VERSION 5.8 ;
BUSBITCHARS "[]" ;
DIVIDERCHAR "/" ;
UNITS
    DATABASE MICRONS 1000 ;
END UNITS

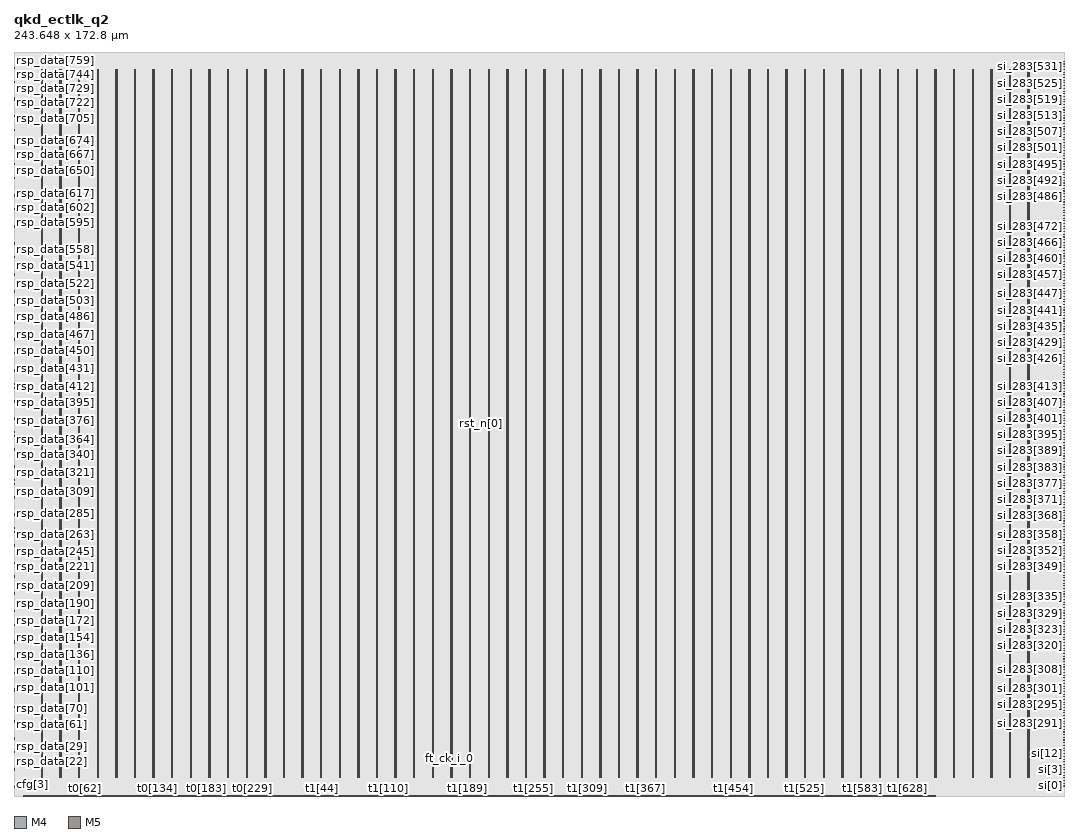
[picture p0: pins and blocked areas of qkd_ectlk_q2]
MACRO qkd_ectlk_q2
  FOREIGN qkd_ectlk_q2 0 0 ;
  CLASS BLOCK ;
  SIZE 243.648 BY 172.8 ;
  PIN cfg[0]
    DIRECTION INPUT ;
    USE SIGNAL ;
    PORT
      LAYER M4 ;
        RECT  0 2.076 0.192 2.1 ;
    END
  END cfg[0]
  PIN cfg[1]
    DIRECTION INPUT ;
    USE SIGNAL ;
    PORT
      LAYER M4 ;
        RECT  0 2.316 0.192 2.34 ;
    END
  END cfg[1]
  PIN cfg[2]
    DIRECTION INPUT ;
    USE SIGNAL ;
    PORT
      LAYER M4 ;
        RECT  0 2.556 0.192 2.58 ;
    END
  END cfg[2]
  PIN cfg[3]
    DIRECTION INPUT ;
    USE SIGNAL ;
    PORT
      LAYER M4 ;
        RECT  0 2.748 0.192 2.772 ;
    END
  END cfg[3]
  PIN cfg[4]
    DIRECTION INPUT ;
    USE SIGNAL ;
    PORT
      LAYER M4 ;
        RECT  0 2.988 0.192 3.012 ;
    END
  END cfg[4]
  PIN ck[0]
    DIRECTION INPUT ;
    USE SIGNAL ;
    PORT
      LAYER M5 ;
        RECT  108 86.16 108.048 86.64 ;
    END
  END ck[0]
  PIN ft_ck_i_0
    DIRECTION INPUT ;
    USE SIGNAL ;
    PORT
      LAYER M5 ;
        RECT  101.04 8.535 101.088 9.015 ;
    END
  END ft_ck_i_0
  PIN ft_ck_o_0
    DIRECTION OUTPUT ;
    USE SIGNAL ;
    PORT
      LAYER M5 ;
        RECT  104.88 8.535 104.928 9.015 ;
    END
  END ft_ck_o_0
  PIN rsp_data[0]
    DIRECTION INPUT ;
    USE SIGNAL ;
    PORT
      LAYER M4 ;
        RECT  0 3.18 0.192 3.204 ;
    END
  END rsp_data[0]
  PIN rsp_data[100]
    DIRECTION INPUT ;
    USE SIGNAL ;
    PORT
      LAYER M4 ;
        RECT  0 25.02 0.192 25.044 ;
    END
  END rsp_data[100]
  PIN rsp_data[101]
    DIRECTION INPUT ;
    USE SIGNAL ;
    PORT
      LAYER M4 ;
        RECT  0 25.26 0.192 25.284 ;
    END
  END rsp_data[101]
  PIN rsp_data[102]
    DIRECTION INPUT ;
    USE SIGNAL ;
    PORT
      LAYER M4 ;
        RECT  0 25.452 0.192 25.476 ;
    END
  END rsp_data[102]
  PIN rsp_data[103]
    DIRECTION INPUT ;
    USE SIGNAL ;
    PORT
      LAYER M4 ;
        RECT  0 25.692 0.192 25.716 ;
    END
  END rsp_data[103]
  PIN rsp_data[104]
    DIRECTION INPUT ;
    USE SIGNAL ;
    PORT
      LAYER M4 ;
        RECT  0 25.884 0.192 25.908 ;
    END
  END rsp_data[104]
  PIN rsp_data[105]
    DIRECTION INPUT ;
    USE SIGNAL ;
    PORT
      LAYER M4 ;
        RECT  0 26.124 0.192 26.148 ;
    END
  END rsp_data[105]
  PIN rsp_data[106]
    DIRECTION INPUT ;
    USE SIGNAL ;
    PORT
      LAYER M4 ;
        RECT  0 26.316 0.192 26.34 ;
    END
  END rsp_data[106]
  PIN rsp_data[107]
    DIRECTION INPUT ;
    USE SIGNAL ;
    PORT
      LAYER M4 ;
        RECT  0 26.556 0.192 26.58 ;
    END
  END rsp_data[107]
  PIN rsp_data[108]
    DIRECTION INPUT ;
    USE SIGNAL ;
    PORT
      LAYER M4 ;
        RECT  0 26.796 0.192 26.82 ;
    END
  END rsp_data[108]
  PIN rsp_data[109]
    DIRECTION INPUT ;
    USE SIGNAL ;
    PORT
      LAYER M4 ;
        RECT  0 26.988 0.192 27.012 ;
    END
  END rsp_data[109]
  PIN rsp_data[10]
    DIRECTION INPUT ;
    USE SIGNAL ;
    PORT
      LAYER M4 ;
        RECT  0 5.388 0.192 5.412 ;
    END
  END rsp_data[10]
  PIN rsp_data[110]
    DIRECTION INPUT ;
    USE SIGNAL ;
    PORT
      LAYER M4 ;
        RECT  0 27.228 0.192 27.252 ;
    END
  END rsp_data[110]
  PIN rsp_data[111]
    DIRECTION INPUT ;
    USE SIGNAL ;
    PORT
      LAYER M4 ;
        RECT  0 27.42 0.192 27.444 ;
    END
  END rsp_data[111]
  PIN rsp_data[112]
    DIRECTION INPUT ;
    USE SIGNAL ;
    PORT
      LAYER M4 ;
        RECT  0 27.66 0.192 27.684 ;
    END
  END rsp_data[112]
  PIN rsp_data[113]
    DIRECTION INPUT ;
    USE SIGNAL ;
    PORT
      LAYER M4 ;
        RECT  0 27.852 0.192 27.876 ;
    END
  END rsp_data[113]
  PIN rsp_data[114]
    DIRECTION INPUT ;
    USE SIGNAL ;
    PORT
      LAYER M4 ;
        RECT  0 28.092 0.192 28.116 ;
    END
  END rsp_data[114]
  PIN rsp_data[115]
    DIRECTION INPUT ;
    USE SIGNAL ;
    PORT
      LAYER M4 ;
        RECT  0 28.284 0.192 28.308 ;
    END
  END rsp_data[115]
  PIN rsp_data[116]
    DIRECTION INPUT ;
    USE SIGNAL ;
    PORT
      LAYER M4 ;
        RECT  0 28.524 0.192 28.548 ;
    END
  END rsp_data[116]
  PIN rsp_data[117]
    DIRECTION INPUT ;
    USE SIGNAL ;
    PORT
      LAYER M4 ;
        RECT  0 28.716 0.192 28.74 ;
    END
  END rsp_data[117]
  PIN rsp_data[118]
    DIRECTION INPUT ;
    USE SIGNAL ;
    PORT
      LAYER M4 ;
        RECT  0 28.956 0.192 28.98 ;
    END
  END rsp_data[118]
  PIN rsp_data[119]
    DIRECTION INPUT ;
    USE SIGNAL ;
    PORT
      LAYER M4 ;
        RECT  0 29.196 0.192 29.22 ;
    END
  END rsp_data[119]
  PIN rsp_data[11]
    DIRECTION INPUT ;
    USE SIGNAL ;
    PORT
      LAYER M4 ;
        RECT  0 5.58 0.192 5.604 ;
    END
  END rsp_data[11]
  PIN rsp_data[120]
    DIRECTION INPUT ;
    USE SIGNAL ;
    PORT
      LAYER M4 ;
        RECT  0 29.388 0.192 29.412 ;
    END
  END rsp_data[120]
  PIN rsp_data[121]
    DIRECTION INPUT ;
    USE SIGNAL ;
    PORT
      LAYER M4 ;
        RECT  0 29.628 0.192 29.652 ;
    END
  END rsp_data[121]
  PIN rsp_data[122]
    DIRECTION INPUT ;
    USE SIGNAL ;
    PORT
      LAYER M4 ;
        RECT  0 29.82 0.192 29.844 ;
    END
  END rsp_data[122]
  PIN rsp_data[123]
    DIRECTION INPUT ;
    USE SIGNAL ;
    PORT
      LAYER M4 ;
        RECT  0 30.06 0.192 30.084 ;
    END
  END rsp_data[123]
  PIN rsp_data[124]
    DIRECTION INPUT ;
    USE SIGNAL ;
    PORT
      LAYER M4 ;
        RECT  0 30.252 0.192 30.276 ;
    END
  END rsp_data[124]
  PIN rsp_data[125]
    DIRECTION INPUT ;
    USE SIGNAL ;
    PORT
      LAYER M4 ;
        RECT  0 30.492 0.192 30.516 ;
    END
  END rsp_data[125]
  PIN rsp_data[126]
    DIRECTION INPUT ;
    USE SIGNAL ;
    PORT
      LAYER M4 ;
        RECT  0 30.684 0.192 30.708 ;
    END
  END rsp_data[126]
  PIN rsp_data[127]
    DIRECTION INPUT ;
    USE SIGNAL ;
    PORT
      LAYER M4 ;
        RECT  0 30.924 0.192 30.948 ;
    END
  END rsp_data[127]
  PIN rsp_data[128]
    DIRECTION INPUT ;
    USE SIGNAL ;
    PORT
      LAYER M4 ;
        RECT  0 31.164 0.192 31.188 ;
    END
  END rsp_data[128]
  PIN rsp_data[129]
    DIRECTION INPUT ;
    USE SIGNAL ;
    PORT
      LAYER M4 ;
        RECT  0 31.356 0.192 31.38 ;
    END
  END rsp_data[129]
  PIN rsp_data[12]
    DIRECTION INPUT ;
    USE SIGNAL ;
    PORT
      LAYER M4 ;
        RECT  0 5.82 0.192 5.844 ;
    END
  END rsp_data[12]
  PIN rsp_data[130]
    DIRECTION INPUT ;
    USE SIGNAL ;
    PORT
      LAYER M4 ;
        RECT  0 31.596 0.192 31.62 ;
    END
  END rsp_data[130]
  PIN rsp_data[131]
    DIRECTION INPUT ;
    USE SIGNAL ;
    PORT
      LAYER M4 ;
        RECT  0 31.788 0.192 31.812 ;
    END
  END rsp_data[131]
  PIN rsp_data[132]
    DIRECTION INPUT ;
    USE SIGNAL ;
    PORT
      LAYER M4 ;
        RECT  0 32.028 0.192 32.052 ;
    END
  END rsp_data[132]
  PIN rsp_data[133]
    DIRECTION INPUT ;
    USE SIGNAL ;
    PORT
      LAYER M4 ;
        RECT  0 32.22 0.192 32.244 ;
    END
  END rsp_data[133]
  PIN rsp_data[134]
    DIRECTION INPUT ;
    USE SIGNAL ;
    PORT
      LAYER M4 ;
        RECT  0 32.46 0.192 32.484 ;
    END
  END rsp_data[134]
  PIN rsp_data[135]
    DIRECTION INPUT ;
    USE SIGNAL ;
    PORT
      LAYER M4 ;
        RECT  0 32.652 0.192 32.676 ;
    END
  END rsp_data[135]
  PIN rsp_data[136]
    DIRECTION INPUT ;
    USE SIGNAL ;
    PORT
      LAYER M4 ;
        RECT  0 32.892 0.192 32.916 ;
    END
  END rsp_data[136]
  PIN rsp_data[137]
    DIRECTION INPUT ;
    USE SIGNAL ;
    PORT
      LAYER M4 ;
        RECT  0 33.084 0.192 33.108 ;
    END
  END rsp_data[137]
  PIN rsp_data[138]
    DIRECTION INPUT ;
    USE SIGNAL ;
    PORT
      LAYER M4 ;
        RECT  0 33.324 0.192 33.348 ;
    END
  END rsp_data[138]
  PIN rsp_data[139]
    DIRECTION INPUT ;
    USE SIGNAL ;
    PORT
      LAYER M4 ;
        RECT  0 33.564 0.192 33.588 ;
    END
  END rsp_data[139]
  PIN rsp_data[13]
    DIRECTION INPUT ;
    USE SIGNAL ;
    PORT
      LAYER M4 ;
        RECT  0 6.012 0.192 6.036 ;
    END
  END rsp_data[13]
  PIN rsp_data[140]
    DIRECTION INPUT ;
    USE SIGNAL ;
    PORT
      LAYER M4 ;
        RECT  0 33.756 0.192 33.78 ;
    END
  END rsp_data[140]
  PIN rsp_data[141]
    DIRECTION INPUT ;
    USE SIGNAL ;
    PORT
      LAYER M4 ;
        RECT  0 33.996 0.192 34.02 ;
    END
  END rsp_data[141]
  PIN rsp_data[142]
    DIRECTION INPUT ;
    USE SIGNAL ;
    PORT
      LAYER M4 ;
        RECT  0 34.188 0.192 34.212 ;
    END
  END rsp_data[142]
  PIN rsp_data[143]
    DIRECTION INPUT ;
    USE SIGNAL ;
    PORT
      LAYER M4 ;
        RECT  0 34.428 0.192 34.452 ;
    END
  END rsp_data[143]
  PIN rsp_data[144]
    DIRECTION INPUT ;
    USE SIGNAL ;
    PORT
      LAYER M4 ;
        RECT  0 34.62 0.192 34.644 ;
    END
  END rsp_data[144]
  PIN rsp_data[145]
    DIRECTION INPUT ;
    USE SIGNAL ;
    PORT
      LAYER M4 ;
        RECT  0 34.86 0.192 34.884 ;
    END
  END rsp_data[145]
  PIN rsp_data[146]
    DIRECTION INPUT ;
    USE SIGNAL ;
    PORT
      LAYER M4 ;
        RECT  0 35.052 0.192 35.076 ;
    END
  END rsp_data[146]
  PIN rsp_data[147]
    DIRECTION INPUT ;
    USE SIGNAL ;
    PORT
      LAYER M4 ;
        RECT  0 35.292 0.192 35.316 ;
    END
  END rsp_data[147]
  PIN rsp_data[148]
    DIRECTION INPUT ;
    USE SIGNAL ;
    PORT
      LAYER M4 ;
        RECT  0 35.484 0.192 35.508 ;
    END
  END rsp_data[148]
  PIN rsp_data[149]
    DIRECTION INPUT ;
    USE SIGNAL ;
    PORT
      LAYER M4 ;
        RECT  0 35.724 0.192 35.748 ;
    END
  END rsp_data[149]
  PIN rsp_data[14]
    DIRECTION INPUT ;
    USE SIGNAL ;
    PORT
      LAYER M4 ;
        RECT  0 6.252 0.192 6.276 ;
    END
  END rsp_data[14]
  PIN rsp_data[150]
    DIRECTION INPUT ;
    USE SIGNAL ;
    PORT
      LAYER M4 ;
        RECT  0 35.964 0.192 35.988 ;
    END
  END rsp_data[150]
  PIN rsp_data[151]
    DIRECTION INPUT ;
    USE SIGNAL ;
    PORT
      LAYER M4 ;
        RECT  0 36.156 0.192 36.18 ;
    END
  END rsp_data[151]
  PIN rsp_data[152]
    DIRECTION INPUT ;
    USE SIGNAL ;
    PORT
      LAYER M4 ;
        RECT  0 36.396 0.192 36.42 ;
    END
  END rsp_data[152]
  PIN rsp_data[153]
    DIRECTION INPUT ;
    USE SIGNAL ;
    PORT
      LAYER M4 ;
        RECT  0 36.588 0.192 36.612 ;
    END
  END rsp_data[153]
  PIN rsp_data[154]
    DIRECTION INPUT ;
    USE SIGNAL ;
    PORT
      LAYER M4 ;
        RECT  0 36.828 0.192 36.852 ;
    END
  END rsp_data[154]
  PIN rsp_data[155]
    DIRECTION INPUT ;
    USE SIGNAL ;
    PORT
      LAYER M4 ;
        RECT  0 37.02 0.192 37.044 ;
    END
  END rsp_data[155]
  PIN rsp_data[156]
    DIRECTION INPUT ;
    USE SIGNAL ;
    PORT
      LAYER M4 ;
        RECT  0 37.26 0.192 37.284 ;
    END
  END rsp_data[156]
  PIN rsp_data[157]
    DIRECTION INPUT ;
    USE SIGNAL ;
    PORT
      LAYER M4 ;
        RECT  0 37.452 0.192 37.476 ;
    END
  END rsp_data[157]
  PIN rsp_data[158]
    DIRECTION INPUT ;
    USE SIGNAL ;
    PORT
      LAYER M4 ;
        RECT  0 37.692 0.192 37.716 ;
    END
  END rsp_data[158]
  PIN rsp_data[159]
    DIRECTION INPUT ;
    USE SIGNAL ;
    PORT
      LAYER M4 ;
        RECT  0 37.932 0.192 37.956 ;
    END
  END rsp_data[159]
  PIN rsp_data[15]
    DIRECTION INPUT ;
    USE SIGNAL ;
    PORT
      LAYER M4 ;
        RECT  0 6.444 0.192 6.468 ;
    END
  END rsp_data[15]
  PIN rsp_data[160]
    DIRECTION INPUT ;
    USE SIGNAL ;
    PORT
      LAYER M4 ;
        RECT  0 38.124 0.192 38.148 ;
    END
  END rsp_data[160]
  PIN rsp_data[161]
    DIRECTION INPUT ;
    USE SIGNAL ;
    PORT
      LAYER M4 ;
        RECT  0 38.364 0.192 38.388 ;
    END
  END rsp_data[161]
  PIN rsp_data[162]
    DIRECTION INPUT ;
    USE SIGNAL ;
    PORT
      LAYER M4 ;
        RECT  0 38.556 0.192 38.58 ;
    END
  END rsp_data[162]
  PIN rsp_data[163]
    DIRECTION INPUT ;
    USE SIGNAL ;
    PORT
      LAYER M4 ;
        RECT  0 38.796 0.192 38.82 ;
    END
  END rsp_data[163]
  PIN rsp_data[164]
    DIRECTION INPUT ;
    USE SIGNAL ;
    PORT
      LAYER M4 ;
        RECT  0 38.988 0.192 39.012 ;
    END
  END rsp_data[164]
  PIN rsp_data[165]
    DIRECTION INPUT ;
    USE SIGNAL ;
    PORT
      LAYER M4 ;
        RECT  0 39.228 0.192 39.252 ;
    END
  END rsp_data[165]
  PIN rsp_data[166]
    DIRECTION INPUT ;
    USE SIGNAL ;
    PORT
      LAYER M4 ;
        RECT  0 39.42 0.192 39.444 ;
    END
  END rsp_data[166]
  PIN rsp_data[167]
    DIRECTION INPUT ;
    USE SIGNAL ;
    PORT
      LAYER M4 ;
        RECT  0 39.66 0.192 39.684 ;
    END
  END rsp_data[167]
  PIN rsp_data[168]
    DIRECTION INPUT ;
    USE SIGNAL ;
    PORT
      LAYER M4 ;
        RECT  0 39.852 0.192 39.876 ;
    END
  END rsp_data[168]
  PIN rsp_data[169]
    DIRECTION INPUT ;
    USE SIGNAL ;
    PORT
      LAYER M4 ;
        RECT  0 40.092 0.192 40.116 ;
    END
  END rsp_data[169]
  PIN rsp_data[16]
    DIRECTION INPUT ;
    USE SIGNAL ;
    PORT
      LAYER M4 ;
        RECT  0 6.684 0.192 6.708 ;
    END
  END rsp_data[16]
  PIN rsp_data[170]
    DIRECTION INPUT ;
    USE SIGNAL ;
    PORT
      LAYER M4 ;
        RECT  0 40.332 0.192 40.356 ;
    END
  END rsp_data[170]
  PIN rsp_data[171]
    DIRECTION INPUT ;
    USE SIGNAL ;
    PORT
      LAYER M4 ;
        RECT  0 40.524 0.192 40.548 ;
    END
  END rsp_data[171]
  PIN rsp_data[172]
    DIRECTION INPUT ;
    USE SIGNAL ;
    PORT
      LAYER M4 ;
        RECT  0 40.764 0.192 40.788 ;
    END
  END rsp_data[172]
  PIN rsp_data[173]
    DIRECTION INPUT ;
    USE SIGNAL ;
    PORT
      LAYER M4 ;
        RECT  0 40.956 0.192 40.98 ;
    END
  END rsp_data[173]
  PIN rsp_data[174]
    DIRECTION INPUT ;
    USE SIGNAL ;
    PORT
      LAYER M4 ;
        RECT  0 41.196 0.192 41.22 ;
    END
  END rsp_data[174]
  PIN rsp_data[175]
    DIRECTION INPUT ;
    USE SIGNAL ;
    PORT
      LAYER M4 ;
        RECT  0 41.388 0.192 41.412 ;
    END
  END rsp_data[175]
  PIN rsp_data[176]
    DIRECTION INPUT ;
    USE SIGNAL ;
    PORT
      LAYER M4 ;
        RECT  0 41.628 0.192 41.652 ;
    END
  END rsp_data[176]
  PIN rsp_data[177]
    DIRECTION INPUT ;
    USE SIGNAL ;
    PORT
      LAYER M4 ;
        RECT  0 41.82 0.192 41.844 ;
    END
  END rsp_data[177]
  PIN rsp_data[178]
    DIRECTION INPUT ;
    USE SIGNAL ;
    PORT
      LAYER M4 ;
        RECT  0 42.06 0.192 42.084 ;
    END
  END rsp_data[178]
  PIN rsp_data[179]
    DIRECTION INPUT ;
    USE SIGNAL ;
    PORT
      LAYER M4 ;
        RECT  0 42.3 0.192 42.324 ;
    END
  END rsp_data[179]
  PIN rsp_data[17]
    DIRECTION INPUT ;
    USE SIGNAL ;
    PORT
      LAYER M4 ;
        RECT  0 6.924 0.192 6.948 ;
    END
  END rsp_data[17]
  PIN rsp_data[180]
    DIRECTION INPUT ;
    USE SIGNAL ;
    PORT
      LAYER M4 ;
        RECT  0 42.492 0.192 42.516 ;
    END
  END rsp_data[180]
  PIN rsp_data[181]
    DIRECTION INPUT ;
    USE SIGNAL ;
    PORT
      LAYER M4 ;
        RECT  0 42.732 0.192 42.756 ;
    END
  END rsp_data[181]
  PIN rsp_data[182]
    DIRECTION INPUT ;
    USE SIGNAL ;
    PORT
      LAYER M4 ;
        RECT  0 42.924 0.192 42.948 ;
    END
  END rsp_data[182]
  PIN rsp_data[183]
    DIRECTION INPUT ;
    USE SIGNAL ;
    PORT
      LAYER M4 ;
        RECT  0 43.164 0.192 43.188 ;
    END
  END rsp_data[183]
  PIN rsp_data[184]
    DIRECTION INPUT ;
    USE SIGNAL ;
    PORT
      LAYER M4 ;
        RECT  0 43.356 0.192 43.38 ;
    END
  END rsp_data[184]
  PIN rsp_data[185]
    DIRECTION INPUT ;
    USE SIGNAL ;
    PORT
      LAYER M4 ;
        RECT  0 43.596 0.192 43.62 ;
    END
  END rsp_data[185]
  PIN rsp_data[186]
    DIRECTION INPUT ;
    USE SIGNAL ;
    PORT
      LAYER M4 ;
        RECT  0 43.788 0.192 43.812 ;
    END
  END rsp_data[186]
  PIN rsp_data[187]
    DIRECTION INPUT ;
    USE SIGNAL ;
    PORT
      LAYER M4 ;
        RECT  0 44.028 0.192 44.052 ;
    END
  END rsp_data[187]
  PIN rsp_data[188]
    DIRECTION INPUT ;
    USE SIGNAL ;
    PORT
      LAYER M4 ;
        RECT  0 44.22 0.192 44.244 ;
    END
  END rsp_data[188]
  PIN rsp_data[189]
    DIRECTION INPUT ;
    USE SIGNAL ;
    PORT
      LAYER M4 ;
        RECT  0 44.46 0.192 44.484 ;
    END
  END rsp_data[189]
  PIN rsp_data[18]
    DIRECTION INPUT ;
    USE SIGNAL ;
    PORT
      LAYER M4 ;
        RECT  0 7.116 0.192 7.14 ;
    END
  END rsp_data[18]
  PIN rsp_data[190]
    DIRECTION INPUT ;
    USE SIGNAL ;
    PORT
      LAYER M4 ;
        RECT  0 44.7 0.192 44.724 ;
    END
  END rsp_data[190]
  PIN rsp_data[191]
    DIRECTION INPUT ;
    USE SIGNAL ;
    PORT
      LAYER M4 ;
        RECT  0 44.892 0.192 44.916 ;
    END
  END rsp_data[191]
  PIN rsp_data[192]
    DIRECTION INPUT ;
    USE SIGNAL ;
    PORT
      LAYER M4 ;
        RECT  0 45.132 0.192 45.156 ;
    END
  END rsp_data[192]
  PIN rsp_data[193]
    DIRECTION INPUT ;
    USE SIGNAL ;
    PORT
      LAYER M4 ;
        RECT  0 45.324 0.192 45.348 ;
    END
  END rsp_data[193]
  PIN rsp_data[194]
    DIRECTION INPUT ;
    USE SIGNAL ;
    PORT
      LAYER M4 ;
        RECT  0 45.564 0.192 45.588 ;
    END
  END rsp_data[194]
  PIN rsp_data[195]
    DIRECTION INPUT ;
    USE SIGNAL ;
    PORT
      LAYER M4 ;
        RECT  0 45.756 0.192 45.78 ;
    END
  END rsp_data[195]
  PIN rsp_data[196]
    DIRECTION INPUT ;
    USE SIGNAL ;
    PORT
      LAYER M4 ;
        RECT  0 45.996 0.192 46.02 ;
    END
  END rsp_data[196]
  PIN rsp_data[197]
    DIRECTION INPUT ;
    USE SIGNAL ;
    PORT
      LAYER M4 ;
        RECT  0 46.188 0.192 46.212 ;
    END
  END rsp_data[197]
  PIN rsp_data[198]
    DIRECTION INPUT ;
    USE SIGNAL ;
    PORT
      LAYER M4 ;
        RECT  0 46.428 0.192 46.452 ;
    END
  END rsp_data[198]
  PIN rsp_data[199]
    DIRECTION INPUT ;
    USE SIGNAL ;
    PORT
      LAYER M4 ;
        RECT  0 46.668 0.192 46.692 ;
    END
  END rsp_data[199]
  PIN rsp_data[19]
    DIRECTION INPUT ;
    USE SIGNAL ;
    PORT
      LAYER M4 ;
        RECT  0 7.356 0.192 7.38 ;
    END
  END rsp_data[19]
  PIN rsp_data[1]
    DIRECTION INPUT ;
    USE SIGNAL ;
    PORT
      LAYER M4 ;
        RECT  0 3.42 0.192 3.444 ;
    END
  END rsp_data[1]
  PIN rsp_data[200]
    DIRECTION INPUT ;
    USE SIGNAL ;
    PORT
      LAYER M4 ;
        RECT  0 46.86 0.192 46.884 ;
    END
  END rsp_data[200]
  PIN rsp_data[201]
    DIRECTION INPUT ;
    USE SIGNAL ;
    PORT
      LAYER M4 ;
        RECT  0 47.1 0.192 47.124 ;
    END
  END rsp_data[201]
  PIN rsp_data[202]
    DIRECTION INPUT ;
    USE SIGNAL ;
    PORT
      LAYER M4 ;
        RECT  0 47.292 0.192 47.316 ;
    END
  END rsp_data[202]
  PIN rsp_data[203]
    DIRECTION INPUT ;
    USE SIGNAL ;
    PORT
      LAYER M4 ;
        RECT  0 47.532 0.192 47.556 ;
    END
  END rsp_data[203]
  PIN rsp_data[204]
    DIRECTION INPUT ;
    USE SIGNAL ;
    PORT
      LAYER M4 ;
        RECT  0 47.724 0.192 47.748 ;
    END
  END rsp_data[204]
  PIN rsp_data[205]
    DIRECTION INPUT ;
    USE SIGNAL ;
    PORT
      LAYER M4 ;
        RECT  0 47.964 0.192 47.988 ;
    END
  END rsp_data[205]
  PIN rsp_data[206]
    DIRECTION INPUT ;
    USE SIGNAL ;
    PORT
      LAYER M4 ;
        RECT  0 48.156 0.192 48.18 ;
    END
  END rsp_data[206]
  PIN rsp_data[207]
    DIRECTION INPUT ;
    USE SIGNAL ;
    PORT
      LAYER M4 ;
        RECT  0 48.396 0.192 48.42 ;
    END
  END rsp_data[207]
  PIN rsp_data[208]
    DIRECTION INPUT ;
    USE SIGNAL ;
    PORT
      LAYER M4 ;
        RECT  0 48.588 0.192 48.612 ;
    END
  END rsp_data[208]
  PIN rsp_data[209]
    DIRECTION INPUT ;
    USE SIGNAL ;
    PORT
      LAYER M4 ;
        RECT  0 48.828 0.192 48.852 ;
    END
  END rsp_data[209]
  PIN rsp_data[20]
    DIRECTION INPUT ;
    USE SIGNAL ;
    PORT
      LAYER M4 ;
        RECT  0 7.548 0.192 7.572 ;
    END
  END rsp_data[20]
  PIN rsp_data[210]
    DIRECTION INPUT ;
    USE SIGNAL ;
    PORT
      LAYER M4 ;
        RECT  0 49.068 0.192 49.092 ;
    END
  END rsp_data[210]
  PIN rsp_data[211]
    DIRECTION INPUT ;
    USE SIGNAL ;
    PORT
      LAYER M4 ;
        RECT  0 49.26 0.192 49.284 ;
    END
  END rsp_data[211]
  PIN rsp_data[212]
    DIRECTION INPUT ;
    USE SIGNAL ;
    PORT
      LAYER M4 ;
        RECT  0 49.5 0.192 49.524 ;
    END
  END rsp_data[212]
  PIN rsp_data[213]
    DIRECTION INPUT ;
    USE SIGNAL ;
    PORT
      LAYER M4 ;
        RECT  0 49.692 0.192 49.716 ;
    END
  END rsp_data[213]
  PIN rsp_data[214]
    DIRECTION INPUT ;
    USE SIGNAL ;
    PORT
      LAYER M4 ;
        RECT  0 49.932 0.192 49.956 ;
    END
  END rsp_data[214]
  PIN rsp_data[215]
    DIRECTION INPUT ;
    USE SIGNAL ;
    PORT
      LAYER M4 ;
        RECT  0 50.124 0.192 50.148 ;
    END
  END rsp_data[215]
  PIN rsp_data[216]
    DIRECTION INPUT ;
    USE SIGNAL ;
    PORT
      LAYER M4 ;
        RECT  0 50.364 0.192 50.388 ;
    END
  END rsp_data[216]
  PIN rsp_data[217]
    DIRECTION INPUT ;
    USE SIGNAL ;
    PORT
      LAYER M4 ;
        RECT  0 50.556 0.192 50.58 ;
    END
  END rsp_data[217]
  PIN rsp_data[218]
    DIRECTION INPUT ;
    USE SIGNAL ;
    PORT
      LAYER M4 ;
        RECT  0 50.796 0.192 50.82 ;
    END
  END rsp_data[218]
  PIN rsp_data[219]
    DIRECTION INPUT ;
    USE SIGNAL ;
    PORT
      LAYER M4 ;
        RECT  0 51.036 0.192 51.06 ;
    END
  END rsp_data[219]
  PIN rsp_data[21]
    DIRECTION INPUT ;
    USE SIGNAL ;
    PORT
      LAYER M4 ;
        RECT  0 7.788 0.192 7.812 ;
    END
  END rsp_data[21]
  PIN rsp_data[220]
    DIRECTION INPUT ;
    USE SIGNAL ;
    PORT
      LAYER M4 ;
        RECT  0 51.228 0.192 51.252 ;
    END
  END rsp_data[220]
  PIN rsp_data[221]
    DIRECTION INPUT ;
    USE SIGNAL ;
    PORT
      LAYER M4 ;
        RECT  0 51.468 0.192 51.492 ;
    END
  END rsp_data[221]
  PIN rsp_data[222]
    DIRECTION INPUT ;
    USE SIGNAL ;
    PORT
      LAYER M4 ;
        RECT  0 51.66 0.192 51.684 ;
    END
  END rsp_data[222]
  PIN rsp_data[223]
    DIRECTION INPUT ;
    USE SIGNAL ;
    PORT
      LAYER M4 ;
        RECT  0 51.9 0.192 51.924 ;
    END
  END rsp_data[223]
  PIN rsp_data[224]
    DIRECTION INPUT ;
    USE SIGNAL ;
    PORT
      LAYER M4 ;
        RECT  0 52.092 0.192 52.116 ;
    END
  END rsp_data[224]
  PIN rsp_data[225]
    DIRECTION INPUT ;
    USE SIGNAL ;
    PORT
      LAYER M4 ;
        RECT  0 52.332 0.192 52.356 ;
    END
  END rsp_data[225]
  PIN rsp_data[226]
    DIRECTION INPUT ;
    USE SIGNAL ;
    PORT
      LAYER M4 ;
        RECT  0 52.524 0.192 52.548 ;
    END
  END rsp_data[226]
  PIN rsp_data[227]
    DIRECTION INPUT ;
    USE SIGNAL ;
    PORT
      LAYER M4 ;
        RECT  0 52.764 0.192 52.788 ;
    END
  END rsp_data[227]
  PIN rsp_data[228]
    DIRECTION INPUT ;
    USE SIGNAL ;
    PORT
      LAYER M4 ;
        RECT  0 52.956 0.192 52.98 ;
    END
  END rsp_data[228]
  PIN rsp_data[229]
    DIRECTION INPUT ;
    USE SIGNAL ;
    PORT
      LAYER M4 ;
        RECT  0 53.196 0.192 53.22 ;
    END
  END rsp_data[229]
  PIN rsp_data[22]
    DIRECTION INPUT ;
    USE SIGNAL ;
    PORT
      LAYER M4 ;
        RECT  0 7.98 0.192 8.004 ;
    END
  END rsp_data[22]
  PIN rsp_data[230]
    DIRECTION INPUT ;
    USE SIGNAL ;
    PORT
      LAYER M4 ;
        RECT  0 53.436 0.192 53.46 ;
    END
  END rsp_data[230]
  PIN rsp_data[231]
    DIRECTION INPUT ;
    USE SIGNAL ;
    PORT
      LAYER M4 ;
        RECT  0 53.628 0.192 53.652 ;
    END
  END rsp_data[231]
  PIN rsp_data[232]
    DIRECTION INPUT ;
    USE SIGNAL ;
    PORT
      LAYER M4 ;
        RECT  0 53.868 0.192 53.892 ;
    END
  END rsp_data[232]
  PIN rsp_data[233]
    DIRECTION INPUT ;
    USE SIGNAL ;
    PORT
      LAYER M4 ;
        RECT  0 54.06 0.192 54.084 ;
    END
  END rsp_data[233]
  PIN rsp_data[234]
    DIRECTION INPUT ;
    USE SIGNAL ;
    PORT
      LAYER M4 ;
        RECT  0 54.3 0.192 54.324 ;
    END
  END rsp_data[234]
  PIN rsp_data[235]
    DIRECTION INPUT ;
    USE SIGNAL ;
    PORT
      LAYER M4 ;
        RECT  0 54.492 0.192 54.516 ;
    END
  END rsp_data[235]
  PIN rsp_data[236]
    DIRECTION INPUT ;
    USE SIGNAL ;
    PORT
      LAYER M4 ;
        RECT  0 54.732 0.192 54.756 ;
    END
  END rsp_data[236]
  PIN rsp_data[237]
    DIRECTION INPUT ;
    USE SIGNAL ;
    PORT
      LAYER M4 ;
        RECT  0 54.924 0.192 54.948 ;
    END
  END rsp_data[237]
  PIN rsp_data[238]
    DIRECTION INPUT ;
    USE SIGNAL ;
    PORT
      LAYER M4 ;
        RECT  0 55.164 0.192 55.188 ;
    END
  END rsp_data[238]
  PIN rsp_data[239]
    DIRECTION INPUT ;
    USE SIGNAL ;
    PORT
      LAYER M4 ;
        RECT  0 55.356 0.192 55.38 ;
    END
  END rsp_data[239]
  PIN rsp_data[23]
    DIRECTION INPUT ;
    USE SIGNAL ;
    PORT
      LAYER M4 ;
        RECT  0 8.22 0.192 8.244 ;
    END
  END rsp_data[23]
  PIN rsp_data[240]
    DIRECTION INPUT ;
    USE SIGNAL ;
    PORT
      LAYER M4 ;
        RECT  0 55.596 0.192 55.62 ;
    END
  END rsp_data[240]
  PIN rsp_data[241]
    DIRECTION INPUT ;
    USE SIGNAL ;
    PORT
      LAYER M4 ;
        RECT  0 55.836 0.192 55.86 ;
    END
  END rsp_data[241]
  PIN rsp_data[242]
    DIRECTION INPUT ;
    USE SIGNAL ;
    PORT
      LAYER M4 ;
        RECT  0 56.028 0.192 56.052 ;
    END
  END rsp_data[242]
  PIN rsp_data[243]
    DIRECTION INPUT ;
    USE SIGNAL ;
    PORT
      LAYER M4 ;
        RECT  0 56.268 0.192 56.292 ;
    END
  END rsp_data[243]
  PIN rsp_data[244]
    DIRECTION INPUT ;
    USE SIGNAL ;
    PORT
      LAYER M4 ;
        RECT  0 56.46 0.192 56.484 ;
    END
  END rsp_data[244]
  PIN rsp_data[245]
    DIRECTION INPUT ;
    USE SIGNAL ;
    PORT
      LAYER M4 ;
        RECT  0 56.7 0.192 56.724 ;
    END
  END rsp_data[245]
  PIN rsp_data[246]
    DIRECTION INPUT ;
    USE SIGNAL ;
    PORT
      LAYER M4 ;
        RECT  0 56.892 0.192 56.916 ;
    END
  END rsp_data[246]
  PIN rsp_data[247]
    DIRECTION INPUT ;
    USE SIGNAL ;
    PORT
      LAYER M4 ;
        RECT  0 57.132 0.192 57.156 ;
    END
  END rsp_data[247]
  PIN rsp_data[248]
    DIRECTION INPUT ;
    USE SIGNAL ;
    PORT
      LAYER M4 ;
        RECT  0 57.324 0.192 57.348 ;
    END
  END rsp_data[248]
  PIN rsp_data[249]
    DIRECTION INPUT ;
    USE SIGNAL ;
    PORT
      LAYER M4 ;
        RECT  0 57.564 0.192 57.588 ;
    END
  END rsp_data[249]
  PIN rsp_data[24]
    DIRECTION INPUT ;
    USE SIGNAL ;
    PORT
      LAYER M4 ;
        RECT  0 8.412 0.192 8.436 ;
    END
  END rsp_data[24]
  PIN rsp_data[250]
    DIRECTION INPUT ;
    USE SIGNAL ;
    PORT
      LAYER M4 ;
        RECT  0 57.804 0.192 57.828 ;
    END
  END rsp_data[250]
  PIN rsp_data[251]
    DIRECTION INPUT ;
    USE SIGNAL ;
    PORT
      LAYER M4 ;
        RECT  0 57.996 0.192 58.02 ;
    END
  END rsp_data[251]
  PIN rsp_data[252]
    DIRECTION INPUT ;
    USE SIGNAL ;
    PORT
      LAYER M4 ;
        RECT  0 58.236 0.192 58.26 ;
    END
  END rsp_data[252]
  PIN rsp_data[253]
    DIRECTION INPUT ;
    USE SIGNAL ;
    PORT
      LAYER M4 ;
        RECT  0 58.428 0.192 58.452 ;
    END
  END rsp_data[253]
  PIN rsp_data[254]
    DIRECTION INPUT ;
    USE SIGNAL ;
    PORT
      LAYER M4 ;
        RECT  0 58.668 0.192 58.692 ;
    END
  END rsp_data[254]
  PIN rsp_data[255]
    DIRECTION INPUT ;
    USE SIGNAL ;
    PORT
      LAYER M4 ;
        RECT  0 58.86 0.192 58.884 ;
    END
  END rsp_data[255]
  PIN rsp_data[256]
    DIRECTION INPUT ;
    USE SIGNAL ;
    PORT
      LAYER M4 ;
        RECT  0 59.1 0.192 59.124 ;
    END
  END rsp_data[256]
  PIN rsp_data[257]
    DIRECTION INPUT ;
    USE SIGNAL ;
    PORT
      LAYER M4 ;
        RECT  0 59.292 0.192 59.316 ;
    END
  END rsp_data[257]
  PIN rsp_data[258]
    DIRECTION INPUT ;
    USE SIGNAL ;
    PORT
      LAYER M4 ;
        RECT  0 59.532 0.192 59.556 ;
    END
  END rsp_data[258]
  PIN rsp_data[259]
    DIRECTION INPUT ;
    USE SIGNAL ;
    PORT
      LAYER M4 ;
        RECT  0 59.724 0.192 59.748 ;
    END
  END rsp_data[259]
  PIN rsp_data[25]
    DIRECTION INPUT ;
    USE SIGNAL ;
    PORT
      LAYER M4 ;
        RECT  0 8.652 0.192 8.676 ;
    END
  END rsp_data[25]
  PIN rsp_data[260]
    DIRECTION INPUT ;
    USE SIGNAL ;
    PORT
      LAYER M4 ;
        RECT  0 59.964 0.192 59.988 ;
    END
  END rsp_data[260]
  PIN rsp_data[261]
    DIRECTION INPUT ;
    USE SIGNAL ;
    PORT
      LAYER M4 ;
        RECT  0 60.204 0.192 60.228 ;
    END
  END rsp_data[261]
  PIN rsp_data[262]
    DIRECTION INPUT ;
    USE SIGNAL ;
    PORT
      LAYER M4 ;
        RECT  0 60.396 0.192 60.42 ;
    END
  END rsp_data[262]
  PIN rsp_data[263]
    DIRECTION INPUT ;
    USE SIGNAL ;
    PORT
      LAYER M4 ;
        RECT  0 60.636 0.192 60.66 ;
    END
  END rsp_data[263]
  PIN rsp_data[264]
    DIRECTION INPUT ;
    USE SIGNAL ;
    PORT
      LAYER M4 ;
        RECT  0 60.828 0.192 60.852 ;
    END
  END rsp_data[264]
  PIN rsp_data[265]
    DIRECTION INPUT ;
    USE SIGNAL ;
    PORT
      LAYER M4 ;
        RECT  0 61.068 0.192 61.092 ;
    END
  END rsp_data[265]
  PIN rsp_data[266]
    DIRECTION INPUT ;
    USE SIGNAL ;
    PORT
      LAYER M4 ;
        RECT  0 61.26 0.192 61.284 ;
    END
  END rsp_data[266]
  PIN rsp_data[267]
    DIRECTION INPUT ;
    USE SIGNAL ;
    PORT
      LAYER M4 ;
        RECT  0 61.5 0.192 61.524 ;
    END
  END rsp_data[267]
  PIN rsp_data[268]
    DIRECTION INPUT ;
    USE SIGNAL ;
    PORT
      LAYER M4 ;
        RECT  0 61.692 0.192 61.716 ;
    END
  END rsp_data[268]
  PIN rsp_data[269]
    DIRECTION INPUT ;
    USE SIGNAL ;
    PORT
      LAYER M4 ;
        RECT  0 61.932 0.192 61.956 ;
    END
  END rsp_data[269]
  PIN rsp_data[26]
    DIRECTION INPUT ;
    USE SIGNAL ;
    PORT
      LAYER M4 ;
        RECT  0 8.844 0.192 8.868 ;
    END
  END rsp_data[26]
  PIN rsp_data[270]
    DIRECTION INPUT ;
    USE SIGNAL ;
    PORT
      LAYER M4 ;
        RECT  0 62.172 0.192 62.196 ;
    END
  END rsp_data[270]
  PIN rsp_data[271]
    DIRECTION INPUT ;
    USE SIGNAL ;
    PORT
      LAYER M4 ;
        RECT  0 62.364 0.192 62.388 ;
    END
  END rsp_data[271]
  PIN rsp_data[272]
    DIRECTION INPUT ;
    USE SIGNAL ;
    PORT
      LAYER M4 ;
        RECT  0 62.604 0.192 62.628 ;
    END
  END rsp_data[272]
  PIN rsp_data[273]
    DIRECTION INPUT ;
    USE SIGNAL ;
    PORT
      LAYER M4 ;
        RECT  0 62.796 0.192 62.82 ;
    END
  END rsp_data[273]
  PIN rsp_data[274]
    DIRECTION INPUT ;
    USE SIGNAL ;
    PORT
      LAYER M4 ;
        RECT  0 63.036 0.192 63.06 ;
    END
  END rsp_data[274]
  PIN rsp_data[275]
    DIRECTION INPUT ;
    USE SIGNAL ;
    PORT
      LAYER M4 ;
        RECT  0 63.228 0.192 63.252 ;
    END
  END rsp_data[275]
  PIN rsp_data[276]
    DIRECTION INPUT ;
    USE SIGNAL ;
    PORT
      LAYER M4 ;
        RECT  0 63.468 0.192 63.492 ;
    END
  END rsp_data[276]
  PIN rsp_data[277]
    DIRECTION INPUT ;
    USE SIGNAL ;
    PORT
      LAYER M4 ;
        RECT  0 63.66 0.192 63.684 ;
    END
  END rsp_data[277]
  PIN rsp_data[278]
    DIRECTION INPUT ;
    USE SIGNAL ;
    PORT
      LAYER M4 ;
        RECT  0 63.9 0.192 63.924 ;
    END
  END rsp_data[278]
  PIN rsp_data[279]
    DIRECTION INPUT ;
    USE SIGNAL ;
    PORT
      LAYER M4 ;
        RECT  0 64.092 0.192 64.116 ;
    END
  END rsp_data[279]
  PIN rsp_data[27]
    DIRECTION INPUT ;
    USE SIGNAL ;
    PORT
      LAYER M4 ;
        RECT  0 9.084 0.192 9.108 ;
    END
  END rsp_data[27]
  PIN rsp_data[280]
    DIRECTION INPUT ;
    USE SIGNAL ;
    PORT
      LAYER M4 ;
        RECT  0 64.332 0.192 64.356 ;
    END
  END rsp_data[280]
  PIN rsp_data[281]
    DIRECTION INPUT ;
    USE SIGNAL ;
    PORT
      LAYER M4 ;
        RECT  0 64.572 0.192 64.596 ;
    END
  END rsp_data[281]
  PIN rsp_data[282]
    DIRECTION INPUT ;
    USE SIGNAL ;
    PORT
      LAYER M4 ;
        RECT  0 64.764 0.192 64.788 ;
    END
  END rsp_data[282]
  PIN rsp_data[283]
    DIRECTION INPUT ;
    USE SIGNAL ;
    PORT
      LAYER M4 ;
        RECT  0 65.004 0.192 65.028 ;
    END
  END rsp_data[283]
  PIN rsp_data[284]
    DIRECTION INPUT ;
    USE SIGNAL ;
    PORT
      LAYER M4 ;
        RECT  0 65.196 0.192 65.22 ;
    END
  END rsp_data[284]
  PIN rsp_data[285]
    DIRECTION INPUT ;
    USE SIGNAL ;
    PORT
      LAYER M4 ;
        RECT  0 65.436 0.192 65.46 ;
    END
  END rsp_data[285]
  PIN rsp_data[286]
    DIRECTION INPUT ;
    USE SIGNAL ;
    PORT
      LAYER M4 ;
        RECT  0 65.628 0.192 65.652 ;
    END
  END rsp_data[286]
  PIN rsp_data[287]
    DIRECTION INPUT ;
    USE SIGNAL ;
    PORT
      LAYER M4 ;
        RECT  0 65.868 0.192 65.892 ;
    END
  END rsp_data[287]
  PIN rsp_data[288]
    DIRECTION INPUT ;
    USE SIGNAL ;
    PORT
      LAYER M4 ;
        RECT  0 66.06 0.192 66.084 ;
    END
  END rsp_data[288]
  PIN rsp_data[289]
    DIRECTION INPUT ;
    USE SIGNAL ;
    PORT
      LAYER M4 ;
        RECT  0 66.3 0.192 66.324 ;
    END
  END rsp_data[289]
  PIN rsp_data[28]
    DIRECTION INPUT ;
    USE SIGNAL ;
    PORT
      LAYER M4 ;
        RECT  0 9.324 0.192 9.348 ;
    END
  END rsp_data[28]
  PIN rsp_data[290]
    DIRECTION INPUT ;
    USE SIGNAL ;
    PORT
      LAYER M4 ;
        RECT  0 66.54 0.192 66.564 ;
    END
  END rsp_data[290]
  PIN rsp_data[291]
    DIRECTION INPUT ;
    USE SIGNAL ;
    PORT
      LAYER M4 ;
        RECT  0 66.732 0.192 66.756 ;
    END
  END rsp_data[291]
  PIN rsp_data[292]
    DIRECTION INPUT ;
    USE SIGNAL ;
    PORT
      LAYER M4 ;
        RECT  0 66.972 0.192 66.996 ;
    END
  END rsp_data[292]
  PIN rsp_data[293]
    DIRECTION INPUT ;
    USE SIGNAL ;
    PORT
      LAYER M4 ;
        RECT  0 67.164 0.192 67.188 ;
    END
  END rsp_data[293]
  PIN rsp_data[294]
    DIRECTION INPUT ;
    USE SIGNAL ;
    PORT
      LAYER M4 ;
        RECT  0 67.404 0.192 67.428 ;
    END
  END rsp_data[294]
  PIN rsp_data[295]
    DIRECTION INPUT ;
    USE SIGNAL ;
    PORT
      LAYER M4 ;
        RECT  0 67.596 0.192 67.62 ;
    END
  END rsp_data[295]
  PIN rsp_data[296]
    DIRECTION INPUT ;
    USE SIGNAL ;
    PORT
      LAYER M4 ;
        RECT  0 67.836 0.192 67.86 ;
    END
  END rsp_data[296]
  PIN rsp_data[297]
    DIRECTION INPUT ;
    USE SIGNAL ;
    PORT
      LAYER M4 ;
        RECT  0 68.028 0.192 68.052 ;
    END
  END rsp_data[297]
  PIN rsp_data[298]
    DIRECTION INPUT ;
    USE SIGNAL ;
    PORT
      LAYER M4 ;
        RECT  0 68.268 0.192 68.292 ;
    END
  END rsp_data[298]
  PIN rsp_data[299]
    DIRECTION INPUT ;
    USE SIGNAL ;
    PORT
      LAYER M4 ;
        RECT  0 68.46 0.192 68.484 ;
    END
  END rsp_data[299]
  PIN rsp_data[29]
    DIRECTION INPUT ;
    USE SIGNAL ;
    PORT
      LAYER M4 ;
        RECT  0 9.516 0.192 9.54 ;
    END
  END rsp_data[29]
  PIN rsp_data[2]
    DIRECTION INPUT ;
    USE SIGNAL ;
    PORT
      LAYER M4 ;
        RECT  0 3.612 0.192 3.636 ;
    END
  END rsp_data[2]
  PIN rsp_data[300]
    DIRECTION INPUT ;
    USE SIGNAL ;
    PORT
      LAYER M4 ;
        RECT  0 68.7 0.192 68.724 ;
    END
  END rsp_data[300]
  PIN rsp_data[301]
    DIRECTION INPUT ;
    USE SIGNAL ;
    PORT
      LAYER M4 ;
        RECT  0 68.94 0.192 68.964 ;
    END
  END rsp_data[301]
  PIN rsp_data[302]
    DIRECTION INPUT ;
    USE SIGNAL ;
    PORT
      LAYER M4 ;
        RECT  0 69.132 0.192 69.156 ;
    END
  END rsp_data[302]
  PIN rsp_data[303]
    DIRECTION INPUT ;
    USE SIGNAL ;
    PORT
      LAYER M4 ;
        RECT  0 69.372 0.192 69.396 ;
    END
  END rsp_data[303]
  PIN rsp_data[304]
    DIRECTION INPUT ;
    USE SIGNAL ;
    PORT
      LAYER M4 ;
        RECT  0 69.564 0.192 69.588 ;
    END
  END rsp_data[304]
  PIN rsp_data[305]
    DIRECTION INPUT ;
    USE SIGNAL ;
    PORT
      LAYER M4 ;
        RECT  0 69.804 0.192 69.828 ;
    END
  END rsp_data[305]
  PIN rsp_data[306]
    DIRECTION INPUT ;
    USE SIGNAL ;
    PORT
      LAYER M4 ;
        RECT  0 69.996 0.192 70.02 ;
    END
  END rsp_data[306]
  PIN rsp_data[307]
    DIRECTION INPUT ;
    USE SIGNAL ;
    PORT
      LAYER M4 ;
        RECT  0 70.236 0.192 70.26 ;
    END
  END rsp_data[307]
  PIN rsp_data[308]
    DIRECTION INPUT ;
    USE SIGNAL ;
    PORT
      LAYER M4 ;
        RECT  0 70.428 0.192 70.452 ;
    END
  END rsp_data[308]
  PIN rsp_data[309]
    DIRECTION INPUT ;
    USE SIGNAL ;
    PORT
      LAYER M4 ;
        RECT  0 70.668 0.192 70.692 ;
    END
  END rsp_data[309]
  PIN rsp_data[30]
    DIRECTION INPUT ;
    USE SIGNAL ;
    PORT
      LAYER M4 ;
        RECT  0 9.756 0.192 9.78 ;
    END
  END rsp_data[30]
  PIN rsp_data[310]
    DIRECTION INPUT ;
    USE SIGNAL ;
    PORT
      LAYER M4 ;
        RECT  0 70.86 0.192 70.884 ;
    END
  END rsp_data[310]
  PIN rsp_data[311]
    DIRECTION INPUT ;
    USE SIGNAL ;
    PORT
      LAYER M4 ;
        RECT  0 71.1 0.192 71.124 ;
    END
  END rsp_data[311]
  PIN rsp_data[312]
    DIRECTION INPUT ;
    USE SIGNAL ;
    PORT
      LAYER M4 ;
        RECT  0 71.34 0.192 71.364 ;
    END
  END rsp_data[312]
  PIN rsp_data[313]
    DIRECTION INPUT ;
    USE SIGNAL ;
    PORT
      LAYER M4 ;
        RECT  0 71.532 0.192 71.556 ;
    END
  END rsp_data[313]
  PIN rsp_data[314]
    DIRECTION INPUT ;
    USE SIGNAL ;
    PORT
      LAYER M4 ;
        RECT  0 71.772 0.192 71.796 ;
    END
  END rsp_data[314]
  PIN rsp_data[315]
    DIRECTION INPUT ;
    USE SIGNAL ;
    PORT
      LAYER M4 ;
        RECT  0 71.964 0.192 71.988 ;
    END
  END rsp_data[315]
  PIN rsp_data[316]
    DIRECTION INPUT ;
    USE SIGNAL ;
    PORT
      LAYER M4 ;
        RECT  0 72.204 0.192 72.228 ;
    END
  END rsp_data[316]
  PIN rsp_data[317]
    DIRECTION INPUT ;
    USE SIGNAL ;
    PORT
      LAYER M4 ;
        RECT  0 72.396 0.192 72.42 ;
    END
  END rsp_data[317]
  PIN rsp_data[318]
    DIRECTION INPUT ;
    USE SIGNAL ;
    PORT
      LAYER M4 ;
        RECT  0 72.636 0.192 72.66 ;
    END
  END rsp_data[318]
  PIN rsp_data[319]
    DIRECTION INPUT ;
    USE SIGNAL ;
    PORT
      LAYER M4 ;
        RECT  0 72.828 0.192 72.852 ;
    END
  END rsp_data[319]
  PIN rsp_data[31]
    DIRECTION INPUT ;
    USE SIGNAL ;
    PORT
      LAYER M4 ;
        RECT  0 9.948 0.192 9.972 ;
    END
  END rsp_data[31]
  PIN rsp_data[320]
    DIRECTION INPUT ;
    USE SIGNAL ;
    PORT
      LAYER M4 ;
        RECT  0 73.068 0.192 73.092 ;
    END
  END rsp_data[320]
  PIN rsp_data[321]
    DIRECTION INPUT ;
    USE SIGNAL ;
    PORT
      LAYER M4 ;
        RECT  0 73.308 0.192 73.332 ;
    END
  END rsp_data[321]
  PIN rsp_data[322]
    DIRECTION INPUT ;
    USE SIGNAL ;
    PORT
      LAYER M4 ;
        RECT  0 73.5 0.192 73.524 ;
    END
  END rsp_data[322]
  PIN rsp_data[323]
    DIRECTION INPUT ;
    USE SIGNAL ;
    PORT
      LAYER M4 ;
        RECT  0 73.74 0.192 73.764 ;
    END
  END rsp_data[323]
  PIN rsp_data[324]
    DIRECTION INPUT ;
    USE SIGNAL ;
    PORT
      LAYER M4 ;
        RECT  0 73.932 0.192 73.956 ;
    END
  END rsp_data[324]
  PIN rsp_data[325]
    DIRECTION INPUT ;
    USE SIGNAL ;
    PORT
      LAYER M4 ;
        RECT  0 74.172 0.192 74.196 ;
    END
  END rsp_data[325]
  PIN rsp_data[326]
    DIRECTION INPUT ;
    USE SIGNAL ;
    PORT
      LAYER M4 ;
        RECT  0 74.364 0.192 74.388 ;
    END
  END rsp_data[326]
  PIN rsp_data[327]
    DIRECTION INPUT ;
    USE SIGNAL ;
    PORT
      LAYER M4 ;
        RECT  0 74.604 0.192 74.628 ;
    END
  END rsp_data[327]
  PIN rsp_data[328]
    DIRECTION INPUT ;
    USE SIGNAL ;
    PORT
      LAYER M4 ;
        RECT  0 74.796 0.192 74.82 ;
    END
  END rsp_data[328]
  PIN rsp_data[329]
    DIRECTION INPUT ;
    USE SIGNAL ;
    PORT
      LAYER M4 ;
        RECT  0 75.036 0.192 75.06 ;
    END
  END rsp_data[329]
  PIN rsp_data[32]
    DIRECTION INPUT ;
    USE SIGNAL ;
    PORT
      LAYER M4 ;
        RECT  0 10.188 0.192 10.212 ;
    END
  END rsp_data[32]
  PIN rsp_data[330]
    DIRECTION INPUT ;
    USE SIGNAL ;
    PORT
      LAYER M4 ;
        RECT  0 75.228 0.192 75.252 ;
    END
  END rsp_data[330]
  PIN rsp_data[331]
    DIRECTION INPUT ;
    USE SIGNAL ;
    PORT
      LAYER M4 ;
        RECT  0 75.468 0.192 75.492 ;
    END
  END rsp_data[331]
  PIN rsp_data[332]
    DIRECTION INPUT ;
    USE SIGNAL ;
    PORT
      LAYER M4 ;
        RECT  0 75.708 0.192 75.732 ;
    END
  END rsp_data[332]
  PIN rsp_data[333]
    DIRECTION INPUT ;
    USE SIGNAL ;
    PORT
      LAYER M4 ;
        RECT  0 75.9 0.192 75.924 ;
    END
  END rsp_data[333]
  PIN rsp_data[334]
    DIRECTION INPUT ;
    USE SIGNAL ;
    PORT
      LAYER M4 ;
        RECT  0 76.14 0.192 76.164 ;
    END
  END rsp_data[334]
  PIN rsp_data[335]
    DIRECTION INPUT ;
    USE SIGNAL ;
    PORT
      LAYER M4 ;
        RECT  0 76.332 0.192 76.356 ;
    END
  END rsp_data[335]
  PIN rsp_data[336]
    DIRECTION INPUT ;
    USE SIGNAL ;
    PORT
      LAYER M4 ;
        RECT  0 76.572 0.192 76.596 ;
    END
  END rsp_data[336]
  PIN rsp_data[337]
    DIRECTION INPUT ;
    USE SIGNAL ;
    PORT
      LAYER M4 ;
        RECT  0 76.764 0.192 76.788 ;
    END
  END rsp_data[337]
  PIN rsp_data[338]
    DIRECTION INPUT ;
    USE SIGNAL ;
    PORT
      LAYER M4 ;
        RECT  0 77.004 0.192 77.028 ;
    END
  END rsp_data[338]
  PIN rsp_data[339]
    DIRECTION INPUT ;
    USE SIGNAL ;
    PORT
      LAYER M4 ;
        RECT  0 77.196 0.192 77.22 ;
    END
  END rsp_data[339]
  PIN rsp_data[33]
    DIRECTION INPUT ;
    USE SIGNAL ;
    PORT
      LAYER M4 ;
        RECT  0 10.38 0.192 10.404 ;
    END
  END rsp_data[33]
  PIN rsp_data[340]
    DIRECTION INPUT ;
    USE SIGNAL ;
    PORT
      LAYER M4 ;
        RECT  0 77.436 0.192 77.46 ;
    END
  END rsp_data[340]
  PIN rsp_data[341]
    DIRECTION INPUT ;
    USE SIGNAL ;
    PORT
      LAYER M4 ;
        RECT  0 77.676 0.192 77.7 ;
    END
  END rsp_data[341]
  PIN rsp_data[342]
    DIRECTION INPUT ;
    USE SIGNAL ;
    PORT
      LAYER M4 ;
        RECT  0 77.868 0.192 77.892 ;
    END
  END rsp_data[342]
  PIN rsp_data[343]
    DIRECTION INPUT ;
    USE SIGNAL ;
    PORT
      LAYER M4 ;
        RECT  0 78.108 0.192 78.132 ;
    END
  END rsp_data[343]
  PIN rsp_data[344]
    DIRECTION INPUT ;
    USE SIGNAL ;
    PORT
      LAYER M4 ;
        RECT  0 78.3 0.192 78.324 ;
    END
  END rsp_data[344]
  PIN rsp_data[345]
    DIRECTION INPUT ;
    USE SIGNAL ;
    PORT
      LAYER M4 ;
        RECT  0 78.54 0.192 78.564 ;
    END
  END rsp_data[345]
  PIN rsp_data[346]
    DIRECTION INPUT ;
    USE SIGNAL ;
    PORT
      LAYER M4 ;
        RECT  0 78.732 0.192 78.756 ;
    END
  END rsp_data[346]
  PIN rsp_data[347]
    DIRECTION INPUT ;
    USE SIGNAL ;
    PORT
      LAYER M4 ;
        RECT  0 78.972 0.192 78.996 ;
    END
  END rsp_data[347]
  PIN rsp_data[348]
    DIRECTION INPUT ;
    USE SIGNAL ;
    PORT
      LAYER M4 ;
        RECT  0 79.164 0.192 79.188 ;
    END
  END rsp_data[348]
  PIN rsp_data[349]
    DIRECTION INPUT ;
    USE SIGNAL ;
    PORT
      LAYER M4 ;
        RECT  0 79.404 0.192 79.428 ;
    END
  END rsp_data[349]
  PIN rsp_data[34]
    DIRECTION INPUT ;
    USE SIGNAL ;
    PORT
      LAYER M4 ;
        RECT  0 10.62 0.192 10.644 ;
    END
  END rsp_data[34]
  PIN rsp_data[350]
    DIRECTION INPUT ;
    USE SIGNAL ;
    PORT
      LAYER M4 ;
        RECT  0 79.596 0.192 79.62 ;
    END
  END rsp_data[350]
  PIN rsp_data[351]
    DIRECTION INPUT ;
    USE SIGNAL ;
    PORT
      LAYER M4 ;
        RECT  0 79.836 0.192 79.86 ;
    END
  END rsp_data[351]
  PIN rsp_data[352]
    DIRECTION INPUT ;
    USE SIGNAL ;
    PORT
      LAYER M4 ;
        RECT  0 80.076 0.192 80.1 ;
    END
  END rsp_data[352]
  PIN rsp_data[353]
    DIRECTION INPUT ;
    USE SIGNAL ;
    PORT
      LAYER M4 ;
        RECT  0 80.268 0.192 80.292 ;
    END
  END rsp_data[353]
  PIN rsp_data[354]
    DIRECTION INPUT ;
    USE SIGNAL ;
    PORT
      LAYER M4 ;
        RECT  0 80.508 0.192 80.532 ;
    END
  END rsp_data[354]
  PIN rsp_data[355]
    DIRECTION INPUT ;
    USE SIGNAL ;
    PORT
      LAYER M4 ;
        RECT  0 80.7 0.192 80.724 ;
    END
  END rsp_data[355]
  PIN rsp_data[356]
    DIRECTION INPUT ;
    USE SIGNAL ;
    PORT
      LAYER M4 ;
        RECT  0 80.94 0.192 80.964 ;
    END
  END rsp_data[356]
  PIN rsp_data[357]
    DIRECTION INPUT ;
    USE SIGNAL ;
    PORT
      LAYER M4 ;
        RECT  0 81.132 0.192 81.156 ;
    END
  END rsp_data[357]
  PIN rsp_data[358]
    DIRECTION INPUT ;
    USE SIGNAL ;
    PORT
      LAYER M4 ;
        RECT  0 81.372 0.192 81.396 ;
    END
  END rsp_data[358]
  PIN rsp_data[359]
    DIRECTION INPUT ;
    USE SIGNAL ;
    PORT
      LAYER M4 ;
        RECT  0 81.564 0.192 81.588 ;
    END
  END rsp_data[359]
  PIN rsp_data[35]
    DIRECTION INPUT ;
    USE SIGNAL ;
    PORT
      LAYER M4 ;
        RECT  0 10.812 0.192 10.836 ;
    END
  END rsp_data[35]
  PIN rsp_data[360]
    DIRECTION INPUT ;
    USE SIGNAL ;
    PORT
      LAYER M4 ;
        RECT  0 81.804 0.192 81.828 ;
    END
  END rsp_data[360]
  PIN rsp_data[361]
    DIRECTION INPUT ;
    USE SIGNAL ;
    PORT
      LAYER M4 ;
        RECT  0 82.044 0.192 82.068 ;
    END
  END rsp_data[361]
  PIN rsp_data[362]
    DIRECTION INPUT ;
    USE SIGNAL ;
    PORT
      LAYER M4 ;
        RECT  0 82.236 0.192 82.26 ;
    END
  END rsp_data[362]
  PIN rsp_data[363]
    DIRECTION INPUT ;
    USE SIGNAL ;
    PORT
      LAYER M4 ;
        RECT  0 82.476 0.192 82.5 ;
    END
  END rsp_data[363]
  PIN rsp_data[364]
    DIRECTION INPUT ;
    USE SIGNAL ;
    PORT
      LAYER M4 ;
        RECT  0 82.668 0.192 82.692 ;
    END
  END rsp_data[364]
  PIN rsp_data[365]
    DIRECTION INPUT ;
    USE SIGNAL ;
    PORT
      LAYER M4 ;
        RECT  0 82.908 0.192 82.932 ;
    END
  END rsp_data[365]
  PIN rsp_data[366]
    DIRECTION INPUT ;
    USE SIGNAL ;
    PORT
      LAYER M4 ;
        RECT  0 83.1 0.192 83.124 ;
    END
  END rsp_data[366]
  PIN rsp_data[367]
    DIRECTION INPUT ;
    USE SIGNAL ;
    PORT
      LAYER M4 ;
        RECT  0 83.34 0.192 83.364 ;
    END
  END rsp_data[367]
  PIN rsp_data[368]
    DIRECTION INPUT ;
    USE SIGNAL ;
    PORT
      LAYER M4 ;
        RECT  0 83.532 0.192 83.556 ;
    END
  END rsp_data[368]
  PIN rsp_data[369]
    DIRECTION INPUT ;
    USE SIGNAL ;
    PORT
      LAYER M4 ;
        RECT  0 83.772 0.192 83.796 ;
    END
  END rsp_data[369]
  PIN rsp_data[36]
    DIRECTION INPUT ;
    USE SIGNAL ;
    PORT
      LAYER M4 ;
        RECT  0 11.052 0.192 11.076 ;
    END
  END rsp_data[36]
  PIN rsp_data[370]
    DIRECTION INPUT ;
    USE SIGNAL ;
    PORT
      LAYER M4 ;
        RECT  0 83.964 0.192 83.988 ;
    END
  END rsp_data[370]
  PIN rsp_data[371]
    DIRECTION INPUT ;
    USE SIGNAL ;
    PORT
      LAYER M4 ;
        RECT  0 84.204 0.192 84.228 ;
    END
  END rsp_data[371]
  PIN rsp_data[372]
    DIRECTION INPUT ;
    USE SIGNAL ;
    PORT
      LAYER M4 ;
        RECT  0 84.444 0.192 84.468 ;
    END
  END rsp_data[372]
  PIN rsp_data[373]
    DIRECTION INPUT ;
    USE SIGNAL ;
    PORT
      LAYER M4 ;
        RECT  0 84.636 0.192 84.66 ;
    END
  END rsp_data[373]
  PIN rsp_data[374]
    DIRECTION INPUT ;
    USE SIGNAL ;
    PORT
      LAYER M4 ;
        RECT  0 84.876 0.192 84.9 ;
    END
  END rsp_data[374]
  PIN rsp_data[375]
    DIRECTION INPUT ;
    USE SIGNAL ;
    PORT
      LAYER M4 ;
        RECT  0 85.068 0.192 85.092 ;
    END
  END rsp_data[375]
  PIN rsp_data[376]
    DIRECTION INPUT ;
    USE SIGNAL ;
    PORT
      LAYER M4 ;
        RECT  0 85.308 0.192 85.332 ;
    END
  END rsp_data[376]
  PIN rsp_data[377]
    DIRECTION INPUT ;
    USE SIGNAL ;
    PORT
      LAYER M4 ;
        RECT  0 85.5 0.192 85.524 ;
    END
  END rsp_data[377]
  PIN rsp_data[378]
    DIRECTION INPUT ;
    USE SIGNAL ;
    PORT
      LAYER M4 ;
        RECT  0 85.74 0.192 85.764 ;
    END
  END rsp_data[378]
  PIN rsp_data[379]
    DIRECTION INPUT ;
    USE SIGNAL ;
    PORT
      LAYER M4 ;
        RECT  0 85.932 0.192 85.956 ;
    END
  END rsp_data[379]
  PIN rsp_data[37]
    DIRECTION INPUT ;
    USE SIGNAL ;
    PORT
      LAYER M4 ;
        RECT  0 11.292 0.192 11.316 ;
    END
  END rsp_data[37]
  PIN rsp_data[380]
    DIRECTION INPUT ;
    USE SIGNAL ;
    PORT
      LAYER M4 ;
        RECT  0 86.172 0.192 86.196 ;
    END
  END rsp_data[380]
  PIN rsp_data[381]
    DIRECTION INPUT ;
    USE SIGNAL ;
    PORT
      LAYER M4 ;
        RECT  0 86.412 0.192 86.436 ;
    END
  END rsp_data[381]
  PIN rsp_data[382]
    DIRECTION INPUT ;
    USE SIGNAL ;
    PORT
      LAYER M4 ;
        RECT  0 86.604 0.192 86.628 ;
    END
  END rsp_data[382]
  PIN rsp_data[383]
    DIRECTION INPUT ;
    USE SIGNAL ;
    PORT
      LAYER M4 ;
        RECT  0 86.844 0.192 86.868 ;
    END
  END rsp_data[383]
  PIN rsp_data[384]
    DIRECTION INPUT ;
    USE SIGNAL ;
    PORT
      LAYER M4 ;
        RECT  0 87.036 0.192 87.06 ;
    END
  END rsp_data[384]
  PIN rsp_data[385]
    DIRECTION INPUT ;
    USE SIGNAL ;
    PORT
      LAYER M4 ;
        RECT  0 87.276 0.192 87.3 ;
    END
  END rsp_data[385]
  PIN rsp_data[386]
    DIRECTION INPUT ;
    USE SIGNAL ;
    PORT
      LAYER M4 ;
        RECT  0 87.468 0.192 87.492 ;
    END
  END rsp_data[386]
  PIN rsp_data[387]
    DIRECTION INPUT ;
    USE SIGNAL ;
    PORT
      LAYER M4 ;
        RECT  0 87.708 0.192 87.732 ;
    END
  END rsp_data[387]
  PIN rsp_data[388]
    DIRECTION INPUT ;
    USE SIGNAL ;
    PORT
      LAYER M4 ;
        RECT  0 87.9 0.192 87.924 ;
    END
  END rsp_data[388]
  PIN rsp_data[389]
    DIRECTION INPUT ;
    USE SIGNAL ;
    PORT
      LAYER M4 ;
        RECT  0 88.14 0.192 88.164 ;
    END
  END rsp_data[389]
  PIN rsp_data[38]
    DIRECTION INPUT ;
    USE SIGNAL ;
    PORT
      LAYER M4 ;
        RECT  0 11.484 0.192 11.508 ;
    END
  END rsp_data[38]
  PIN rsp_data[390]
    DIRECTION INPUT ;
    USE SIGNAL ;
    PORT
      LAYER M4 ;
        RECT  0 88.332 0.192 88.356 ;
    END
  END rsp_data[390]
  PIN rsp_data[391]
    DIRECTION INPUT ;
    USE SIGNAL ;
    PORT
      LAYER M4 ;
        RECT  0 88.572 0.192 88.596 ;
    END
  END rsp_data[391]
  PIN rsp_data[392]
    DIRECTION INPUT ;
    USE SIGNAL ;
    PORT
      LAYER M4 ;
        RECT  0 88.812 0.192 88.836 ;
    END
  END rsp_data[392]
  PIN rsp_data[393]
    DIRECTION INPUT ;
    USE SIGNAL ;
    PORT
      LAYER M4 ;
        RECT  0 89.004 0.192 89.028 ;
    END
  END rsp_data[393]
  PIN rsp_data[394]
    DIRECTION INPUT ;
    USE SIGNAL ;
    PORT
      LAYER M4 ;
        RECT  0 89.244 0.192 89.268 ;
    END
  END rsp_data[394]
  PIN rsp_data[395]
    DIRECTION INPUT ;
    USE SIGNAL ;
    PORT
      LAYER M4 ;
        RECT  0 89.436 0.192 89.46 ;
    END
  END rsp_data[395]
  PIN rsp_data[396]
    DIRECTION INPUT ;
    USE SIGNAL ;
    PORT
      LAYER M4 ;
        RECT  0 89.676 0.192 89.7 ;
    END
  END rsp_data[396]
  PIN rsp_data[397]
    DIRECTION INPUT ;
    USE SIGNAL ;
    PORT
      LAYER M4 ;
        RECT  0 89.868 0.192 89.892 ;
    END
  END rsp_data[397]
  PIN rsp_data[398]
    DIRECTION INPUT ;
    USE SIGNAL ;
    PORT
      LAYER M4 ;
        RECT  0 90.108 0.192 90.132 ;
    END
  END rsp_data[398]
  PIN rsp_data[399]
    DIRECTION INPUT ;
    USE SIGNAL ;
    PORT
      LAYER M4 ;
        RECT  0 90.3 0.192 90.324 ;
    END
  END rsp_data[399]
  PIN rsp_data[39]
    DIRECTION INPUT ;
    USE SIGNAL ;
    PORT
      LAYER M4 ;
        RECT  0 11.724 0.192 11.748 ;
    END
  END rsp_data[39]
  PIN rsp_data[3]
    DIRECTION INPUT ;
    USE SIGNAL ;
    PORT
      LAYER M4 ;
        RECT  0 3.852 0.192 3.876 ;
    END
  END rsp_data[3]
  PIN rsp_data[400]
    DIRECTION INPUT ;
    USE SIGNAL ;
    PORT
      LAYER M4 ;
        RECT  0 90.54 0.192 90.564 ;
    END
  END rsp_data[400]
  PIN rsp_data[401]
    DIRECTION INPUT ;
    USE SIGNAL ;
    PORT
      LAYER M4 ;
        RECT  0 90.732 0.192 90.756 ;
    END
  END rsp_data[401]
  PIN rsp_data[402]
    DIRECTION INPUT ;
    USE SIGNAL ;
    PORT
      LAYER M4 ;
        RECT  0 90.972 0.192 90.996 ;
    END
  END rsp_data[402]
  PIN rsp_data[403]
    DIRECTION INPUT ;
    USE SIGNAL ;
    PORT
      LAYER M4 ;
        RECT  0 91.212 0.192 91.236 ;
    END
  END rsp_data[403]
  PIN rsp_data[404]
    DIRECTION INPUT ;
    USE SIGNAL ;
    PORT
      LAYER M4 ;
        RECT  0 91.404 0.192 91.428 ;
    END
  END rsp_data[404]
  PIN rsp_data[405]
    DIRECTION INPUT ;
    USE SIGNAL ;
    PORT
      LAYER M4 ;
        RECT  0 91.644 0.192 91.668 ;
    END
  END rsp_data[405]
  PIN rsp_data[406]
    DIRECTION INPUT ;
    USE SIGNAL ;
    PORT
      LAYER M4 ;
        RECT  0 91.836 0.192 91.86 ;
    END
  END rsp_data[406]
  PIN rsp_data[407]
    DIRECTION INPUT ;
    USE SIGNAL ;
    PORT
      LAYER M4 ;
        RECT  0 92.076 0.192 92.1 ;
    END
  END rsp_data[407]
  PIN rsp_data[408]
    DIRECTION INPUT ;
    USE SIGNAL ;
    PORT
      LAYER M4 ;
        RECT  0 92.268 0.192 92.292 ;
    END
  END rsp_data[408]
  PIN rsp_data[409]
    DIRECTION INPUT ;
    USE SIGNAL ;
    PORT
      LAYER M4 ;
        RECT  0 92.508 0.192 92.532 ;
    END
  END rsp_data[409]
  PIN rsp_data[40]
    DIRECTION INPUT ;
    USE SIGNAL ;
    PORT
      LAYER M4 ;
        RECT  0 11.916 0.192 11.94 ;
    END
  END rsp_data[40]
  PIN rsp_data[410]
    DIRECTION INPUT ;
    USE SIGNAL ;
    PORT
      LAYER M4 ;
        RECT  0 92.7 0.192 92.724 ;
    END
  END rsp_data[410]
  PIN rsp_data[411]
    DIRECTION INPUT ;
    USE SIGNAL ;
    PORT
      LAYER M4 ;
        RECT  0 92.94 0.192 92.964 ;
    END
  END rsp_data[411]
  PIN rsp_data[412]
    DIRECTION INPUT ;
    USE SIGNAL ;
    PORT
      LAYER M4 ;
        RECT  0 93.18 0.192 93.204 ;
    END
  END rsp_data[412]
  PIN rsp_data[413]
    DIRECTION INPUT ;
    USE SIGNAL ;
    PORT
      LAYER M4 ;
        RECT  0 93.372 0.192 93.396 ;
    END
  END rsp_data[413]
  PIN rsp_data[414]
    DIRECTION INPUT ;
    USE SIGNAL ;
    PORT
      LAYER M4 ;
        RECT  0 93.612 0.192 93.636 ;
    END
  END rsp_data[414]
  PIN rsp_data[415]
    DIRECTION INPUT ;
    USE SIGNAL ;
    PORT
      LAYER M4 ;
        RECT  0 93.804 0.192 93.828 ;
    END
  END rsp_data[415]
  PIN rsp_data[416]
    DIRECTION INPUT ;
    USE SIGNAL ;
    PORT
      LAYER M4 ;
        RECT  0 94.044 0.192 94.068 ;
    END
  END rsp_data[416]
  PIN rsp_data[417]
    DIRECTION INPUT ;
    USE SIGNAL ;
    PORT
      LAYER M4 ;
        RECT  0 94.236 0.192 94.26 ;
    END
  END rsp_data[417]
  PIN rsp_data[418]
    DIRECTION INPUT ;
    USE SIGNAL ;
    PORT
      LAYER M4 ;
        RECT  0 94.476 0.192 94.5 ;
    END
  END rsp_data[418]
  PIN rsp_data[419]
    DIRECTION INPUT ;
    USE SIGNAL ;
    PORT
      LAYER M4 ;
        RECT  0 94.668 0.192 94.692 ;
    END
  END rsp_data[419]
  PIN rsp_data[41]
    DIRECTION INPUT ;
    USE SIGNAL ;
    PORT
      LAYER M4 ;
        RECT  0 12.156 0.192 12.18 ;
    END
  END rsp_data[41]
  PIN rsp_data[420]
    DIRECTION INPUT ;
    USE SIGNAL ;
    PORT
      LAYER M4 ;
        RECT  0 94.908 0.192 94.932 ;
    END
  END rsp_data[420]
  PIN rsp_data[421]
    DIRECTION INPUT ;
    USE SIGNAL ;
    PORT
      LAYER M4 ;
        RECT  0 95.1 0.192 95.124 ;
    END
  END rsp_data[421]
  PIN rsp_data[422]
    DIRECTION INPUT ;
    USE SIGNAL ;
    PORT
      LAYER M4 ;
        RECT  0 95.34 0.192 95.364 ;
    END
  END rsp_data[422]
  PIN rsp_data[423]
    DIRECTION INPUT ;
    USE SIGNAL ;
    PORT
      LAYER M4 ;
        RECT  0 95.58 0.192 95.604 ;
    END
  END rsp_data[423]
  PIN rsp_data[424]
    DIRECTION INPUT ;
    USE SIGNAL ;
    PORT
      LAYER M4 ;
        RECT  0 95.772 0.192 95.796 ;
    END
  END rsp_data[424]
  PIN rsp_data[425]
    DIRECTION INPUT ;
    USE SIGNAL ;
    PORT
      LAYER M4 ;
        RECT  0 96.012 0.192 96.036 ;
    END
  END rsp_data[425]
  PIN rsp_data[426]
    DIRECTION INPUT ;
    USE SIGNAL ;
    PORT
      LAYER M4 ;
        RECT  0 96.204 0.192 96.228 ;
    END
  END rsp_data[426]
  PIN rsp_data[427]
    DIRECTION INPUT ;
    USE SIGNAL ;
    PORT
      LAYER M4 ;
        RECT  0 96.444 0.192 96.468 ;
    END
  END rsp_data[427]
  PIN rsp_data[428]
    DIRECTION INPUT ;
    USE SIGNAL ;
    PORT
      LAYER M4 ;
        RECT  0 96.636 0.192 96.66 ;
    END
  END rsp_data[428]
  PIN rsp_data[429]
    DIRECTION INPUT ;
    USE SIGNAL ;
    PORT
      LAYER M4 ;
        RECT  0 96.876 0.192 96.9 ;
    END
  END rsp_data[429]
  PIN rsp_data[42]
    DIRECTION INPUT ;
    USE SIGNAL ;
    PORT
      LAYER M4 ;
        RECT  0 12.348 0.192 12.372 ;
    END
  END rsp_data[42]
  PIN rsp_data[430]
    DIRECTION INPUT ;
    USE SIGNAL ;
    PORT
      LAYER M4 ;
        RECT  0 97.068 0.192 97.092 ;
    END
  END rsp_data[430]
  PIN rsp_data[431]
    DIRECTION INPUT ;
    USE SIGNAL ;
    PORT
      LAYER M4 ;
        RECT  0 97.308 0.192 97.332 ;
    END
  END rsp_data[431]
  PIN rsp_data[432]
    DIRECTION INPUT ;
    USE SIGNAL ;
    PORT
      LAYER M4 ;
        RECT  0 97.548 0.192 97.572 ;
    END
  END rsp_data[432]
  PIN rsp_data[433]
    DIRECTION INPUT ;
    USE SIGNAL ;
    PORT
      LAYER M4 ;
        RECT  0 97.74 0.192 97.764 ;
    END
  END rsp_data[433]
  PIN rsp_data[434]
    DIRECTION INPUT ;
    USE SIGNAL ;
    PORT
      LAYER M4 ;
        RECT  0 97.98 0.192 98.004 ;
    END
  END rsp_data[434]
  PIN rsp_data[435]
    DIRECTION INPUT ;
    USE SIGNAL ;
    PORT
      LAYER M4 ;
        RECT  0 98.172 0.192 98.196 ;
    END
  END rsp_data[435]
  PIN rsp_data[436]
    DIRECTION INPUT ;
    USE SIGNAL ;
    PORT
      LAYER M4 ;
        RECT  0 98.412 0.192 98.436 ;
    END
  END rsp_data[436]
  PIN rsp_data[437]
    DIRECTION INPUT ;
    USE SIGNAL ;
    PORT
      LAYER M4 ;
        RECT  0 98.604 0.192 98.628 ;
    END
  END rsp_data[437]
  PIN rsp_data[438]
    DIRECTION INPUT ;
    USE SIGNAL ;
    PORT
      LAYER M4 ;
        RECT  0 98.844 0.192 98.868 ;
    END
  END rsp_data[438]
  PIN rsp_data[439]
    DIRECTION INPUT ;
    USE SIGNAL ;
    PORT
      LAYER M4 ;
        RECT  0 99.036 0.192 99.06 ;
    END
  END rsp_data[439]
  PIN rsp_data[43]
    DIRECTION INPUT ;
    USE SIGNAL ;
    PORT
      LAYER M4 ;
        RECT  0 12.588 0.192 12.612 ;
    END
  END rsp_data[43]
  PIN rsp_data[440]
    DIRECTION INPUT ;
    USE SIGNAL ;
    PORT
      LAYER M4 ;
        RECT  0 99.276 0.192 99.3 ;
    END
  END rsp_data[440]
  PIN rsp_data[441]
    DIRECTION INPUT ;
    USE SIGNAL ;
    PORT
      LAYER M4 ;
        RECT  0 99.468 0.192 99.492 ;
    END
  END rsp_data[441]
  PIN rsp_data[442]
    DIRECTION INPUT ;
    USE SIGNAL ;
    PORT
      LAYER M4 ;
        RECT  0 99.708 0.192 99.732 ;
    END
  END rsp_data[442]
  PIN rsp_data[443]
    DIRECTION INPUT ;
    USE SIGNAL ;
    PORT
      LAYER M4 ;
        RECT  0 99.948 0.192 99.972 ;
    END
  END rsp_data[443]
  PIN rsp_data[444]
    DIRECTION INPUT ;
    USE SIGNAL ;
    PORT
      LAYER M4 ;
        RECT  0 100.14 0.192 100.164 ;
    END
  END rsp_data[444]
  PIN rsp_data[445]
    DIRECTION INPUT ;
    USE SIGNAL ;
    PORT
      LAYER M4 ;
        RECT  0 100.38 0.192 100.404 ;
    END
  END rsp_data[445]
  PIN rsp_data[446]
    DIRECTION INPUT ;
    USE SIGNAL ;
    PORT
      LAYER M4 ;
        RECT  0 100.572 0.192 100.596 ;
    END
  END rsp_data[446]
  PIN rsp_data[447]
    DIRECTION INPUT ;
    USE SIGNAL ;
    PORT
      LAYER M4 ;
        RECT  0 100.812 0.192 100.836 ;
    END
  END rsp_data[447]
  PIN rsp_data[448]
    DIRECTION INPUT ;
    USE SIGNAL ;
    PORT
      LAYER M4 ;
        RECT  0 101.004 0.192 101.028 ;
    END
  END rsp_data[448]
  PIN rsp_data[449]
    DIRECTION INPUT ;
    USE SIGNAL ;
    PORT
      LAYER M4 ;
        RECT  0 101.244 0.192 101.268 ;
    END
  END rsp_data[449]
  PIN rsp_data[44]
    DIRECTION INPUT ;
    USE SIGNAL ;
    PORT
      LAYER M4 ;
        RECT  0 12.78 0.192 12.804 ;
    END
  END rsp_data[44]
  PIN rsp_data[450]
    DIRECTION INPUT ;
    USE SIGNAL ;
    PORT
      LAYER M4 ;
        RECT  0 101.436 0.192 101.46 ;
    END
  END rsp_data[450]
  PIN rsp_data[451]
    DIRECTION INPUT ;
    USE SIGNAL ;
    PORT
      LAYER M4 ;
        RECT  0 101.676 0.192 101.7 ;
    END
  END rsp_data[451]
  PIN rsp_data[452]
    DIRECTION INPUT ;
    USE SIGNAL ;
    PORT
      LAYER M4 ;
        RECT  0 101.916 0.192 101.94 ;
    END
  END rsp_data[452]
  PIN rsp_data[453]
    DIRECTION INPUT ;
    USE SIGNAL ;
    PORT
      LAYER M4 ;
        RECT  0 102.108 0.192 102.132 ;
    END
  END rsp_data[453]
  PIN rsp_data[454]
    DIRECTION INPUT ;
    USE SIGNAL ;
    PORT
      LAYER M4 ;
        RECT  0 102.348 0.192 102.372 ;
    END
  END rsp_data[454]
  PIN rsp_data[455]
    DIRECTION INPUT ;
    USE SIGNAL ;
    PORT
      LAYER M4 ;
        RECT  0 102.54 0.192 102.564 ;
    END
  END rsp_data[455]
  PIN rsp_data[456]
    DIRECTION INPUT ;
    USE SIGNAL ;
    PORT
      LAYER M4 ;
        RECT  0 102.78 0.192 102.804 ;
    END
  END rsp_data[456]
  PIN rsp_data[457]
    DIRECTION INPUT ;
    USE SIGNAL ;
    PORT
      LAYER M4 ;
        RECT  0 102.972 0.192 102.996 ;
    END
  END rsp_data[457]
  PIN rsp_data[458]
    DIRECTION INPUT ;
    USE SIGNAL ;
    PORT
      LAYER M4 ;
        RECT  0 103.212 0.192 103.236 ;
    END
  END rsp_data[458]
  PIN rsp_data[459]
    DIRECTION INPUT ;
    USE SIGNAL ;
    PORT
      LAYER M4 ;
        RECT  0 103.404 0.192 103.428 ;
    END
  END rsp_data[459]
  PIN rsp_data[45]
    DIRECTION INPUT ;
    USE SIGNAL ;
    PORT
      LAYER M4 ;
        RECT  0 13.02 0.192 13.044 ;
    END
  END rsp_data[45]
  PIN rsp_data[460]
    DIRECTION INPUT ;
    USE SIGNAL ;
    PORT
      LAYER M4 ;
        RECT  0 103.644 0.192 103.668 ;
    END
  END rsp_data[460]
  PIN rsp_data[461]
    DIRECTION INPUT ;
    USE SIGNAL ;
    PORT
      LAYER M4 ;
        RECT  0 103.836 0.192 103.86 ;
    END
  END rsp_data[461]
  PIN rsp_data[462]
    DIRECTION INPUT ;
    USE SIGNAL ;
    PORT
      LAYER M4 ;
        RECT  0 104.076 0.192 104.1 ;
    END
  END rsp_data[462]
  PIN rsp_data[463]
    DIRECTION INPUT ;
    USE SIGNAL ;
    PORT
      LAYER M4 ;
        RECT  0 104.316 0.192 104.34 ;
    END
  END rsp_data[463]
  PIN rsp_data[464]
    DIRECTION INPUT ;
    USE SIGNAL ;
    PORT
      LAYER M4 ;
        RECT  0 104.508 0.192 104.532 ;
    END
  END rsp_data[464]
  PIN rsp_data[465]
    DIRECTION INPUT ;
    USE SIGNAL ;
    PORT
      LAYER M4 ;
        RECT  0 104.748 0.192 104.772 ;
    END
  END rsp_data[465]
  PIN rsp_data[466]
    DIRECTION INPUT ;
    USE SIGNAL ;
    PORT
      LAYER M4 ;
        RECT  0 104.94 0.192 104.964 ;
    END
  END rsp_data[466]
  PIN rsp_data[467]
    DIRECTION INPUT ;
    USE SIGNAL ;
    PORT
      LAYER M4 ;
        RECT  0 105.18 0.192 105.204 ;
    END
  END rsp_data[467]
  PIN rsp_data[468]
    DIRECTION INPUT ;
    USE SIGNAL ;
    PORT
      LAYER M4 ;
        RECT  0 105.372 0.192 105.396 ;
    END
  END rsp_data[468]
  PIN rsp_data[469]
    DIRECTION INPUT ;
    USE SIGNAL ;
    PORT
      LAYER M4 ;
        RECT  0 105.612 0.192 105.636 ;
    END
  END rsp_data[469]
  PIN rsp_data[46]
    DIRECTION INPUT ;
    USE SIGNAL ;
    PORT
      LAYER M4 ;
        RECT  0 13.212 0.192 13.236 ;
    END
  END rsp_data[46]
  PIN rsp_data[470]
    DIRECTION INPUT ;
    USE SIGNAL ;
    PORT
      LAYER M4 ;
        RECT  0 105.804 0.192 105.828 ;
    END
  END rsp_data[470]
  PIN rsp_data[471]
    DIRECTION INPUT ;
    USE SIGNAL ;
    PORT
      LAYER M4 ;
        RECT  0 106.044 0.192 106.068 ;
    END
  END rsp_data[471]
  PIN rsp_data[472]
    DIRECTION INPUT ;
    USE SIGNAL ;
    PORT
      LAYER M4 ;
        RECT  0 106.236 0.192 106.26 ;
    END
  END rsp_data[472]
  PIN rsp_data[473]
    DIRECTION INPUT ;
    USE SIGNAL ;
    PORT
      LAYER M4 ;
        RECT  0 106.476 0.192 106.5 ;
    END
  END rsp_data[473]
  PIN rsp_data[474]
    DIRECTION INPUT ;
    USE SIGNAL ;
    PORT
      LAYER M4 ;
        RECT  0 106.716 0.192 106.74 ;
    END
  END rsp_data[474]
  PIN rsp_data[475]
    DIRECTION INPUT ;
    USE SIGNAL ;
    PORT
      LAYER M4 ;
        RECT  0 106.908 0.192 106.932 ;
    END
  END rsp_data[475]
  PIN rsp_data[476]
    DIRECTION INPUT ;
    USE SIGNAL ;
    PORT
      LAYER M4 ;
        RECT  0 107.148 0.192 107.172 ;
    END
  END rsp_data[476]
  PIN rsp_data[477]
    DIRECTION INPUT ;
    USE SIGNAL ;
    PORT
      LAYER M4 ;
        RECT  0 107.34 0.192 107.364 ;
    END
  END rsp_data[477]
  PIN rsp_data[478]
    DIRECTION INPUT ;
    USE SIGNAL ;
    PORT
      LAYER M4 ;
        RECT  0 107.58 0.192 107.604 ;
    END
  END rsp_data[478]
  PIN rsp_data[479]
    DIRECTION INPUT ;
    USE SIGNAL ;
    PORT
      LAYER M4 ;
        RECT  0 107.772 0.192 107.796 ;
    END
  END rsp_data[479]
  PIN rsp_data[47]
    DIRECTION INPUT ;
    USE SIGNAL ;
    PORT
      LAYER M4 ;
        RECT  0 13.452 0.192 13.476 ;
    END
  END rsp_data[47]
  PIN rsp_data[480]
    DIRECTION INPUT ;
    USE SIGNAL ;
    PORT
      LAYER M4 ;
        RECT  0 108.012 0.192 108.036 ;
    END
  END rsp_data[480]
  PIN rsp_data[481]
    DIRECTION INPUT ;
    USE SIGNAL ;
    PORT
      LAYER M4 ;
        RECT  0 108.204 0.192 108.228 ;
    END
  END rsp_data[481]
  PIN rsp_data[482]
    DIRECTION INPUT ;
    USE SIGNAL ;
    PORT
      LAYER M4 ;
        RECT  0 108.444 0.192 108.468 ;
    END
  END rsp_data[482]
  PIN rsp_data[483]
    DIRECTION INPUT ;
    USE SIGNAL ;
    PORT
      LAYER M4 ;
        RECT  0 108.684 0.192 108.708 ;
    END
  END rsp_data[483]
  PIN rsp_data[484]
    DIRECTION INPUT ;
    USE SIGNAL ;
    PORT
      LAYER M4 ;
        RECT  0 108.876 0.192 108.9 ;
    END
  END rsp_data[484]
  PIN rsp_data[485]
    DIRECTION INPUT ;
    USE SIGNAL ;
    PORT
      LAYER M4 ;
        RECT  0 109.116 0.192 109.14 ;
    END
  END rsp_data[485]
  PIN rsp_data[486]
    DIRECTION INPUT ;
    USE SIGNAL ;
    PORT
      LAYER M4 ;
        RECT  0 109.308 0.192 109.332 ;
    END
  END rsp_data[486]
  PIN rsp_data[487]
    DIRECTION INPUT ;
    USE SIGNAL ;
    PORT
      LAYER M4 ;
        RECT  0 109.548 0.192 109.572 ;
    END
  END rsp_data[487]
  PIN rsp_data[488]
    DIRECTION INPUT ;
    USE SIGNAL ;
    PORT
      LAYER M4 ;
        RECT  0 109.74 0.192 109.764 ;
    END
  END rsp_data[488]
  PIN rsp_data[489]
    DIRECTION INPUT ;
    USE SIGNAL ;
    PORT
      LAYER M4 ;
        RECT  0 109.98 0.192 110.004 ;
    END
  END rsp_data[489]
  PIN rsp_data[48]
    DIRECTION INPUT ;
    USE SIGNAL ;
    PORT
      LAYER M4 ;
        RECT  0 13.692 0.192 13.716 ;
    END
  END rsp_data[48]
  PIN rsp_data[490]
    DIRECTION INPUT ;
    USE SIGNAL ;
    PORT
      LAYER M4 ;
        RECT  0 110.172 0.192 110.196 ;
    END
  END rsp_data[490]
  PIN rsp_data[491]
    DIRECTION INPUT ;
    USE SIGNAL ;
    PORT
      LAYER M4 ;
        RECT  0 110.412 0.192 110.436 ;
    END
  END rsp_data[491]
  PIN rsp_data[492]
    DIRECTION INPUT ;
    USE SIGNAL ;
    PORT
      LAYER M4 ;
        RECT  0 110.604 0.192 110.628 ;
    END
  END rsp_data[492]
  PIN rsp_data[493]
    DIRECTION INPUT ;
    USE SIGNAL ;
    PORT
      LAYER M4 ;
        RECT  0 110.844 0.192 110.868 ;
    END
  END rsp_data[493]
  PIN rsp_data[494]
    DIRECTION INPUT ;
    USE SIGNAL ;
    PORT
      LAYER M4 ;
        RECT  0 111.084 0.192 111.108 ;
    END
  END rsp_data[494]
  PIN rsp_data[495]
    DIRECTION INPUT ;
    USE SIGNAL ;
    PORT
      LAYER M4 ;
        RECT  0 111.276 0.192 111.3 ;
    END
  END rsp_data[495]
  PIN rsp_data[496]
    DIRECTION INPUT ;
    USE SIGNAL ;
    PORT
      LAYER M4 ;
        RECT  0 111.516 0.192 111.54 ;
    END
  END rsp_data[496]
  PIN rsp_data[497]
    DIRECTION INPUT ;
    USE SIGNAL ;
    PORT
      LAYER M4 ;
        RECT  0 111.708 0.192 111.732 ;
    END
  END rsp_data[497]
  PIN rsp_data[498]
    DIRECTION INPUT ;
    USE SIGNAL ;
    PORT
      LAYER M4 ;
        RECT  0 111.948 0.192 111.972 ;
    END
  END rsp_data[498]
  PIN rsp_data[499]
    DIRECTION INPUT ;
    USE SIGNAL ;
    PORT
      LAYER M4 ;
        RECT  0 112.14 0.192 112.164 ;
    END
  END rsp_data[499]
  PIN rsp_data[49]
    DIRECTION INPUT ;
    USE SIGNAL ;
    PORT
      LAYER M4 ;
        RECT  0 13.884 0.192 13.908 ;
    END
  END rsp_data[49]
  PIN rsp_data[4]
    DIRECTION INPUT ;
    USE SIGNAL ;
    PORT
      LAYER M4 ;
        RECT  0 4.044 0.192 4.068 ;
    END
  END rsp_data[4]
  PIN rsp_data[500]
    DIRECTION INPUT ;
    USE SIGNAL ;
    PORT
      LAYER M4 ;
        RECT  0 112.38 0.192 112.404 ;
    END
  END rsp_data[500]
  PIN rsp_data[501]
    DIRECTION INPUT ;
    USE SIGNAL ;
    PORT
      LAYER M4 ;
        RECT  0 112.572 0.192 112.596 ;
    END
  END rsp_data[501]
  PIN rsp_data[502]
    DIRECTION INPUT ;
    USE SIGNAL ;
    PORT
      LAYER M4 ;
        RECT  0 112.812 0.192 112.836 ;
    END
  END rsp_data[502]
  PIN rsp_data[503]
    DIRECTION INPUT ;
    USE SIGNAL ;
    PORT
      LAYER M4 ;
        RECT  0 113.052 0.192 113.076 ;
    END
  END rsp_data[503]
  PIN rsp_data[504]
    DIRECTION INPUT ;
    USE SIGNAL ;
    PORT
      LAYER M4 ;
        RECT  0 113.244 0.192 113.268 ;
    END
  END rsp_data[504]
  PIN rsp_data[505]
    DIRECTION INPUT ;
    USE SIGNAL ;
    PORT
      LAYER M4 ;
        RECT  0 113.484 0.192 113.508 ;
    END
  END rsp_data[505]
  PIN rsp_data[506]
    DIRECTION INPUT ;
    USE SIGNAL ;
    PORT
      LAYER M4 ;
        RECT  0 113.676 0.192 113.7 ;
    END
  END rsp_data[506]
  PIN rsp_data[507]
    DIRECTION INPUT ;
    USE SIGNAL ;
    PORT
      LAYER M4 ;
        RECT  0 113.916 0.192 113.94 ;
    END
  END rsp_data[507]
  PIN rsp_data[508]
    DIRECTION INPUT ;
    USE SIGNAL ;
    PORT
      LAYER M4 ;
        RECT  0 114.108 0.192 114.132 ;
    END
  END rsp_data[508]
  PIN rsp_data[509]
    DIRECTION INPUT ;
    USE SIGNAL ;
    PORT
      LAYER M4 ;
        RECT  0 114.348 0.192 114.372 ;
    END
  END rsp_data[509]
  PIN rsp_data[50]
    DIRECTION INPUT ;
    USE SIGNAL ;
    PORT
      LAYER M4 ;
        RECT  0 14.124 0.192 14.148 ;
    END
  END rsp_data[50]
  PIN rsp_data[510]
    DIRECTION INPUT ;
    USE SIGNAL ;
    PORT
      LAYER M4 ;
        RECT  0 114.54 0.192 114.564 ;
    END
  END rsp_data[510]
  PIN rsp_data[511]
    DIRECTION INPUT ;
    USE SIGNAL ;
    PORT
      LAYER M4 ;
        RECT  0 114.78 0.192 114.804 ;
    END
  END rsp_data[511]
  PIN rsp_data[512]
    DIRECTION INPUT ;
    USE SIGNAL ;
    PORT
      LAYER M4 ;
        RECT  0 114.972 0.192 114.996 ;
    END
  END rsp_data[512]
  PIN rsp_data[513]
    DIRECTION INPUT ;
    USE SIGNAL ;
    PORT
      LAYER M4 ;
        RECT  0 115.212 0.192 115.236 ;
    END
  END rsp_data[513]
  PIN rsp_data[514]
    DIRECTION INPUT ;
    USE SIGNAL ;
    PORT
      LAYER M4 ;
        RECT  0 115.452 0.192 115.476 ;
    END
  END rsp_data[514]
  PIN rsp_data[515]
    DIRECTION INPUT ;
    USE SIGNAL ;
    PORT
      LAYER M4 ;
        RECT  0 115.644 0.192 115.668 ;
    END
  END rsp_data[515]
  PIN rsp_data[516]
    DIRECTION INPUT ;
    USE SIGNAL ;
    PORT
      LAYER M4 ;
        RECT  0 115.884 0.192 115.908 ;
    END
  END rsp_data[516]
  PIN rsp_data[517]
    DIRECTION INPUT ;
    USE SIGNAL ;
    PORT
      LAYER M4 ;
        RECT  0 116.076 0.192 116.1 ;
    END
  END rsp_data[517]
  PIN rsp_data[518]
    DIRECTION INPUT ;
    USE SIGNAL ;
    PORT
      LAYER M4 ;
        RECT  0 116.316 0.192 116.34 ;
    END
  END rsp_data[518]
  PIN rsp_data[519]
    DIRECTION INPUT ;
    USE SIGNAL ;
    PORT
      LAYER M4 ;
        RECT  0 116.508 0.192 116.532 ;
    END
  END rsp_data[519]
  PIN rsp_data[51]
    DIRECTION INPUT ;
    USE SIGNAL ;
    PORT
      LAYER M4 ;
        RECT  0 14.316 0.192 14.34 ;
    END
  END rsp_data[51]
  PIN rsp_data[520]
    DIRECTION INPUT ;
    USE SIGNAL ;
    PORT
      LAYER M4 ;
        RECT  0 116.748 0.192 116.772 ;
    END
  END rsp_data[520]
  PIN rsp_data[521]
    DIRECTION INPUT ;
    USE SIGNAL ;
    PORT
      LAYER M4 ;
        RECT  0 116.94 0.192 116.964 ;
    END
  END rsp_data[521]
  PIN rsp_data[522]
    DIRECTION INPUT ;
    USE SIGNAL ;
    PORT
      LAYER M4 ;
        RECT  0 117.18 0.192 117.204 ;
    END
  END rsp_data[522]
  PIN rsp_data[523]
    DIRECTION INPUT ;
    USE SIGNAL ;
    PORT
      LAYER M4 ;
        RECT  0 117.42 0.192 117.444 ;
    END
  END rsp_data[523]
  PIN rsp_data[524]
    DIRECTION INPUT ;
    USE SIGNAL ;
    PORT
      LAYER M4 ;
        RECT  0 117.612 0.192 117.636 ;
    END
  END rsp_data[524]
  PIN rsp_data[525]
    DIRECTION INPUT ;
    USE SIGNAL ;
    PORT
      LAYER M4 ;
        RECT  0 117.852 0.192 117.876 ;
    END
  END rsp_data[525]
  PIN rsp_data[526]
    DIRECTION INPUT ;
    USE SIGNAL ;
    PORT
      LAYER M4 ;
        RECT  0 118.044 0.192 118.068 ;
    END
  END rsp_data[526]
  PIN rsp_data[527]
    DIRECTION INPUT ;
    USE SIGNAL ;
    PORT
      LAYER M4 ;
        RECT  0 118.284 0.192 118.308 ;
    END
  END rsp_data[527]
  PIN rsp_data[528]
    DIRECTION INPUT ;
    USE SIGNAL ;
    PORT
      LAYER M4 ;
        RECT  0 118.476 0.192 118.5 ;
    END
  END rsp_data[528]
  PIN rsp_data[529]
    DIRECTION INPUT ;
    USE SIGNAL ;
    PORT
      LAYER M4 ;
        RECT  0 118.716 0.192 118.74 ;
    END
  END rsp_data[529]
  PIN rsp_data[52]
    DIRECTION INPUT ;
    USE SIGNAL ;
    PORT
      LAYER M4 ;
        RECT  0 14.556 0.192 14.58 ;
    END
  END rsp_data[52]
  PIN rsp_data[530]
    DIRECTION INPUT ;
    USE SIGNAL ;
    PORT
      LAYER M4 ;
        RECT  0 118.908 0.192 118.932 ;
    END
  END rsp_data[530]
  PIN rsp_data[531]
    DIRECTION INPUT ;
    USE SIGNAL ;
    PORT
      LAYER M4 ;
        RECT  0 119.148 0.192 119.172 ;
    END
  END rsp_data[531]
  PIN rsp_data[532]
    DIRECTION INPUT ;
    USE SIGNAL ;
    PORT
      LAYER M4 ;
        RECT  0 119.34 0.192 119.364 ;
    END
  END rsp_data[532]
  PIN rsp_data[533]
    DIRECTION INPUT ;
    USE SIGNAL ;
    PORT
      LAYER M4 ;
        RECT  0 119.58 0.192 119.604 ;
    END
  END rsp_data[533]
  PIN rsp_data[534]
    DIRECTION INPUT ;
    USE SIGNAL ;
    PORT
      LAYER M4 ;
        RECT  0 119.82 0.192 119.844 ;
    END
  END rsp_data[534]
  PIN rsp_data[535]
    DIRECTION INPUT ;
    USE SIGNAL ;
    PORT
      LAYER M4 ;
        RECT  0 120.012 0.192 120.036 ;
    END
  END rsp_data[535]
  PIN rsp_data[536]
    DIRECTION INPUT ;
    USE SIGNAL ;
    PORT
      LAYER M4 ;
        RECT  0 120.252 0.192 120.276 ;
    END
  END rsp_data[536]
  PIN rsp_data[537]
    DIRECTION INPUT ;
    USE SIGNAL ;
    PORT
      LAYER M4 ;
        RECT  0 120.444 0.192 120.468 ;
    END
  END rsp_data[537]
  PIN rsp_data[538]
    DIRECTION INPUT ;
    USE SIGNAL ;
    PORT
      LAYER M4 ;
        RECT  0 120.684 0.192 120.708 ;
    END
  END rsp_data[538]
  PIN rsp_data[539]
    DIRECTION INPUT ;
    USE SIGNAL ;
    PORT
      LAYER M4 ;
        RECT  0 120.876 0.192 120.9 ;
    END
  END rsp_data[539]
  PIN rsp_data[53]
    DIRECTION INPUT ;
    USE SIGNAL ;
    PORT
      LAYER M4 ;
        RECT  0 14.748 0.192 14.772 ;
    END
  END rsp_data[53]
  PIN rsp_data[540]
    DIRECTION INPUT ;
    USE SIGNAL ;
    PORT
      LAYER M4 ;
        RECT  0 121.116 0.192 121.14 ;
    END
  END rsp_data[540]
  PIN rsp_data[541]
    DIRECTION INPUT ;
    USE SIGNAL ;
    PORT
      LAYER M4 ;
        RECT  0 121.308 0.192 121.332 ;
    END
  END rsp_data[541]
  PIN rsp_data[542]
    DIRECTION INPUT ;
    USE SIGNAL ;
    PORT
      LAYER M4 ;
        RECT  0 121.548 0.192 121.572 ;
    END
  END rsp_data[542]
  PIN rsp_data[543]
    DIRECTION INPUT ;
    USE SIGNAL ;
    PORT
      LAYER M4 ;
        RECT  0 121.74 0.192 121.764 ;
    END
  END rsp_data[543]
  PIN rsp_data[544]
    DIRECTION INPUT ;
    USE SIGNAL ;
    PORT
      LAYER M4 ;
        RECT  0 121.98 0.192 122.004 ;
    END
  END rsp_data[544]
  PIN rsp_data[545]
    DIRECTION INPUT ;
    USE SIGNAL ;
    PORT
      LAYER M4 ;
        RECT  0 122.22 0.192 122.244 ;
    END
  END rsp_data[545]
  PIN rsp_data[546]
    DIRECTION INPUT ;
    USE SIGNAL ;
    PORT
      LAYER M4 ;
        RECT  0 122.412 0.192 122.436 ;
    END
  END rsp_data[546]
  PIN rsp_data[547]
    DIRECTION INPUT ;
    USE SIGNAL ;
    PORT
      LAYER M4 ;
        RECT  0 122.652 0.192 122.676 ;
    END
  END rsp_data[547]
  PIN rsp_data[548]
    DIRECTION INPUT ;
    USE SIGNAL ;
    PORT
      LAYER M4 ;
        RECT  0 122.844 0.192 122.868 ;
    END
  END rsp_data[548]
  PIN rsp_data[549]
    DIRECTION INPUT ;
    USE SIGNAL ;
    PORT
      LAYER M4 ;
        RECT  0 123.084 0.192 123.108 ;
    END
  END rsp_data[549]
  PIN rsp_data[54]
    DIRECTION INPUT ;
    USE SIGNAL ;
    PORT
      LAYER M4 ;
        RECT  0 14.988 0.192 15.012 ;
    END
  END rsp_data[54]
  PIN rsp_data[550]
    DIRECTION INPUT ;
    USE SIGNAL ;
    PORT
      LAYER M4 ;
        RECT  0 123.276 0.192 123.3 ;
    END
  END rsp_data[550]
  PIN rsp_data[551]
    DIRECTION INPUT ;
    USE SIGNAL ;
    PORT
      LAYER M4 ;
        RECT  0 123.516 0.192 123.54 ;
    END
  END rsp_data[551]
  PIN rsp_data[552]
    DIRECTION INPUT ;
    USE SIGNAL ;
    PORT
      LAYER M4 ;
        RECT  0 123.708 0.192 123.732 ;
    END
  END rsp_data[552]
  PIN rsp_data[553]
    DIRECTION INPUT ;
    USE SIGNAL ;
    PORT
      LAYER M4 ;
        RECT  0 123.948 0.192 123.972 ;
    END
  END rsp_data[553]
  PIN rsp_data[554]
    DIRECTION INPUT ;
    USE SIGNAL ;
    PORT
      LAYER M4 ;
        RECT  0 124.188 0.192 124.212 ;
    END
  END rsp_data[554]
  PIN rsp_data[555]
    DIRECTION INPUT ;
    USE SIGNAL ;
    PORT
      LAYER M4 ;
        RECT  0 124.38 0.192 124.404 ;
    END
  END rsp_data[555]
  PIN rsp_data[556]
    DIRECTION INPUT ;
    USE SIGNAL ;
    PORT
      LAYER M4 ;
        RECT  0 124.62 0.192 124.644 ;
    END
  END rsp_data[556]
  PIN rsp_data[557]
    DIRECTION INPUT ;
    USE SIGNAL ;
    PORT
      LAYER M4 ;
        RECT  0 124.812 0.192 124.836 ;
    END
  END rsp_data[557]
  PIN rsp_data[558]
    DIRECTION INPUT ;
    USE SIGNAL ;
    PORT
      LAYER M4 ;
        RECT  0 125.052 0.192 125.076 ;
    END
  END rsp_data[558]
  PIN rsp_data[559]
    DIRECTION INPUT ;
    USE SIGNAL ;
    PORT
      LAYER M4 ;
        RECT  0 125.244 0.192 125.268 ;
    END
  END rsp_data[559]
  PIN rsp_data[55]
    DIRECTION INPUT ;
    USE SIGNAL ;
    PORT
      LAYER M4 ;
        RECT  0 15.18 0.192 15.204 ;
    END
  END rsp_data[55]
  PIN rsp_data[560]
    DIRECTION INPUT ;
    USE SIGNAL ;
    PORT
      LAYER M4 ;
        RECT  0 125.484 0.192 125.508 ;
    END
  END rsp_data[560]
  PIN rsp_data[561]
    DIRECTION INPUT ;
    USE SIGNAL ;
    PORT
      LAYER M4 ;
        RECT  0 125.676 0.192 125.7 ;
    END
  END rsp_data[561]
  PIN rsp_data[562]
    DIRECTION INPUT ;
    USE SIGNAL ;
    PORT
      LAYER M4 ;
        RECT  0 125.916 0.192 125.94 ;
    END
  END rsp_data[562]
  PIN rsp_data[563]
    DIRECTION INPUT ;
    USE SIGNAL ;
    PORT
      LAYER M4 ;
        RECT  0 126.108 0.192 126.132 ;
    END
  END rsp_data[563]
  PIN rsp_data[564]
    DIRECTION INPUT ;
    USE SIGNAL ;
    PORT
      LAYER M4 ;
        RECT  0 126.348 0.192 126.372 ;
    END
  END rsp_data[564]
  PIN rsp_data[565]
    DIRECTION INPUT ;
    USE SIGNAL ;
    PORT
      LAYER M4 ;
        RECT  0 126.588 0.192 126.612 ;
    END
  END rsp_data[565]
  PIN rsp_data[566]
    DIRECTION INPUT ;
    USE SIGNAL ;
    PORT
      LAYER M4 ;
        RECT  0 126.78 0.192 126.804 ;
    END
  END rsp_data[566]
  PIN rsp_data[567]
    DIRECTION INPUT ;
    USE SIGNAL ;
    PORT
      LAYER M4 ;
        RECT  0 127.02 0.192 127.044 ;
    END
  END rsp_data[567]
  PIN rsp_data[568]
    DIRECTION INPUT ;
    USE SIGNAL ;
    PORT
      LAYER M4 ;
        RECT  0 127.212 0.192 127.236 ;
    END
  END rsp_data[568]
  PIN rsp_data[569]
    DIRECTION INPUT ;
    USE SIGNAL ;
    PORT
      LAYER M4 ;
        RECT  0 127.452 0.192 127.476 ;
    END
  END rsp_data[569]
  PIN rsp_data[56]
    DIRECTION INPUT ;
    USE SIGNAL ;
    PORT
      LAYER M4 ;
        RECT  0 15.42 0.192 15.444 ;
    END
  END rsp_data[56]
  PIN rsp_data[570]
    DIRECTION INPUT ;
    USE SIGNAL ;
    PORT
      LAYER M4 ;
        RECT  0 127.644 0.192 127.668 ;
    END
  END rsp_data[570]
  PIN rsp_data[571]
    DIRECTION INPUT ;
    USE SIGNAL ;
    PORT
      LAYER M4 ;
        RECT  0 127.884 0.192 127.908 ;
    END
  END rsp_data[571]
  PIN rsp_data[572]
    DIRECTION INPUT ;
    USE SIGNAL ;
    PORT
      LAYER M4 ;
        RECT  0 128.076 0.192 128.1 ;
    END
  END rsp_data[572]
  PIN rsp_data[573]
    DIRECTION INPUT ;
    USE SIGNAL ;
    PORT
      LAYER M4 ;
        RECT  0 128.316 0.192 128.34 ;
    END
  END rsp_data[573]
  PIN rsp_data[574]
    DIRECTION INPUT ;
    USE SIGNAL ;
    PORT
      LAYER M4 ;
        RECT  0 128.556 0.192 128.58 ;
    END
  END rsp_data[574]
  PIN rsp_data[575]
    DIRECTION INPUT ;
    USE SIGNAL ;
    PORT
      LAYER M4 ;
        RECT  0 128.748 0.192 128.772 ;
    END
  END rsp_data[575]
  PIN rsp_data[576]
    DIRECTION INPUT ;
    USE SIGNAL ;
    PORT
      LAYER M4 ;
        RECT  0 128.988 0.192 129.012 ;
    END
  END rsp_data[576]
  PIN rsp_data[577]
    DIRECTION INPUT ;
    USE SIGNAL ;
    PORT
      LAYER M4 ;
        RECT  0 129.18 0.192 129.204 ;
    END
  END rsp_data[577]
  PIN rsp_data[578]
    DIRECTION INPUT ;
    USE SIGNAL ;
    PORT
      LAYER M4 ;
        RECT  0 129.42 0.192 129.444 ;
    END
  END rsp_data[578]
  PIN rsp_data[579]
    DIRECTION INPUT ;
    USE SIGNAL ;
    PORT
      LAYER M4 ;
        RECT  0 129.612 0.192 129.636 ;
    END
  END rsp_data[579]
  PIN rsp_data[57]
    DIRECTION INPUT ;
    USE SIGNAL ;
    PORT
      LAYER M4 ;
        RECT  0 15.66 0.192 15.684 ;
    END
  END rsp_data[57]
  PIN rsp_data[580]
    DIRECTION INPUT ;
    USE SIGNAL ;
    PORT
      LAYER M4 ;
        RECT  0 129.852 0.192 129.876 ;
    END
  END rsp_data[580]
  PIN rsp_data[581]
    DIRECTION INPUT ;
    USE SIGNAL ;
    PORT
      LAYER M4 ;
        RECT  0 130.044 0.192 130.068 ;
    END
  END rsp_data[581]
  PIN rsp_data[582]
    DIRECTION INPUT ;
    USE SIGNAL ;
    PORT
      LAYER M4 ;
        RECT  0 130.284 0.192 130.308 ;
    END
  END rsp_data[582]
  PIN rsp_data[583]
    DIRECTION INPUT ;
    USE SIGNAL ;
    PORT
      LAYER M4 ;
        RECT  0 130.476 0.192 130.5 ;
    END
  END rsp_data[583]
  PIN rsp_data[584]
    DIRECTION INPUT ;
    USE SIGNAL ;
    PORT
      LAYER M4 ;
        RECT  0 130.716 0.192 130.74 ;
    END
  END rsp_data[584]
  PIN rsp_data[585]
    DIRECTION INPUT ;
    USE SIGNAL ;
    PORT
      LAYER M4 ;
        RECT  0 130.956 0.192 130.98 ;
    END
  END rsp_data[585]
  PIN rsp_data[586]
    DIRECTION INPUT ;
    USE SIGNAL ;
    PORT
      LAYER M4 ;
        RECT  0 131.148 0.192 131.172 ;
    END
  END rsp_data[586]
  PIN rsp_data[587]
    DIRECTION INPUT ;
    USE SIGNAL ;
    PORT
      LAYER M4 ;
        RECT  0 131.388 0.192 131.412 ;
    END
  END rsp_data[587]
  PIN rsp_data[588]
    DIRECTION INPUT ;
    USE SIGNAL ;
    PORT
      LAYER M4 ;
        RECT  0 131.58 0.192 131.604 ;
    END
  END rsp_data[588]
  PIN rsp_data[589]
    DIRECTION INPUT ;
    USE SIGNAL ;
    PORT
      LAYER M4 ;
        RECT  0 131.82 0.192 131.844 ;
    END
  END rsp_data[589]
  PIN rsp_data[58]
    DIRECTION INPUT ;
    USE SIGNAL ;
    PORT
      LAYER M4 ;
        RECT  0 15.852 0.192 15.876 ;
    END
  END rsp_data[58]
  PIN rsp_data[590]
    DIRECTION INPUT ;
    USE SIGNAL ;
    PORT
      LAYER M4 ;
        RECT  0 132.012 0.192 132.036 ;
    END
  END rsp_data[590]
  PIN rsp_data[591]
    DIRECTION INPUT ;
    USE SIGNAL ;
    PORT
      LAYER M4 ;
        RECT  0 132.252 0.192 132.276 ;
    END
  END rsp_data[591]
  PIN rsp_data[592]
    DIRECTION INPUT ;
    USE SIGNAL ;
    PORT
      LAYER M4 ;
        RECT  0 132.444 0.192 132.468 ;
    END
  END rsp_data[592]
  PIN rsp_data[593]
    DIRECTION INPUT ;
    USE SIGNAL ;
    PORT
      LAYER M4 ;
        RECT  0 132.684 0.192 132.708 ;
    END
  END rsp_data[593]
  PIN rsp_data[594]
    DIRECTION INPUT ;
    USE SIGNAL ;
    PORT
      LAYER M4 ;
        RECT  0 132.924 0.192 132.948 ;
    END
  END rsp_data[594]
  PIN rsp_data[595]
    DIRECTION INPUT ;
    USE SIGNAL ;
    PORT
      LAYER M4 ;
        RECT  0 133.116 0.192 133.14 ;
    END
  END rsp_data[595]
  PIN rsp_data[596]
    DIRECTION INPUT ;
    USE SIGNAL ;
    PORT
      LAYER M4 ;
        RECT  0 133.356 0.192 133.38 ;
    END
  END rsp_data[596]
  PIN rsp_data[597]
    DIRECTION INPUT ;
    USE SIGNAL ;
    PORT
      LAYER M4 ;
        RECT  0 133.548 0.192 133.572 ;
    END
  END rsp_data[597]
  PIN rsp_data[598]
    DIRECTION INPUT ;
    USE SIGNAL ;
    PORT
      LAYER M4 ;
        RECT  0 133.788 0.192 133.812 ;
    END
  END rsp_data[598]
  PIN rsp_data[599]
    DIRECTION INPUT ;
    USE SIGNAL ;
    PORT
      LAYER M4 ;
        RECT  0 133.98 0.192 134.004 ;
    END
  END rsp_data[599]
  PIN rsp_data[59]
    DIRECTION INPUT ;
    USE SIGNAL ;
    PORT
      LAYER M4 ;
        RECT  0 16.092 0.192 16.116 ;
    END
  END rsp_data[59]
  PIN rsp_data[5]
    DIRECTION INPUT ;
    USE SIGNAL ;
    PORT
      LAYER M4 ;
        RECT  0 4.284 0.192 4.308 ;
    END
  END rsp_data[5]
  PIN rsp_data[600]
    DIRECTION INPUT ;
    USE SIGNAL ;
    PORT
      LAYER M4 ;
        RECT  0 134.22 0.192 134.244 ;
    END
  END rsp_data[600]
  PIN rsp_data[601]
    DIRECTION INPUT ;
    USE SIGNAL ;
    PORT
      LAYER M4 ;
        RECT  0 134.412 0.192 134.436 ;
    END
  END rsp_data[601]
  PIN rsp_data[602]
    DIRECTION INPUT ;
    USE SIGNAL ;
    PORT
      LAYER M4 ;
        RECT  0 134.652 0.192 134.676 ;
    END
  END rsp_data[602]
  PIN rsp_data[603]
    DIRECTION INPUT ;
    USE SIGNAL ;
    PORT
      LAYER M4 ;
        RECT  0 134.844 0.192 134.868 ;
    END
  END rsp_data[603]
  PIN rsp_data[604]
    DIRECTION INPUT ;
    USE SIGNAL ;
    PORT
      LAYER M4 ;
        RECT  0 135.084 0.192 135.108 ;
    END
  END rsp_data[604]
  PIN rsp_data[605]
    DIRECTION INPUT ;
    USE SIGNAL ;
    PORT
      LAYER M4 ;
        RECT  0 135.324 0.192 135.348 ;
    END
  END rsp_data[605]
  PIN rsp_data[606]
    DIRECTION INPUT ;
    USE SIGNAL ;
    PORT
      LAYER M4 ;
        RECT  0 135.516 0.192 135.54 ;
    END
  END rsp_data[606]
  PIN rsp_data[607]
    DIRECTION INPUT ;
    USE SIGNAL ;
    PORT
      LAYER M4 ;
        RECT  0 135.756 0.192 135.78 ;
    END
  END rsp_data[607]
  PIN rsp_data[608]
    DIRECTION INPUT ;
    USE SIGNAL ;
    PORT
      LAYER M4 ;
        RECT  0 135.948 0.192 135.972 ;
    END
  END rsp_data[608]
  PIN rsp_data[609]
    DIRECTION INPUT ;
    USE SIGNAL ;
    PORT
      LAYER M4 ;
        RECT  0 136.188 0.192 136.212 ;
    END
  END rsp_data[609]
  PIN rsp_data[60]
    DIRECTION INPUT ;
    USE SIGNAL ;
    PORT
      LAYER M4 ;
        RECT  0 16.284 0.192 16.308 ;
    END
  END rsp_data[60]
  PIN rsp_data[610]
    DIRECTION INPUT ;
    USE SIGNAL ;
    PORT
      LAYER M4 ;
        RECT  0 136.38 0.192 136.404 ;
    END
  END rsp_data[610]
  PIN rsp_data[611]
    DIRECTION INPUT ;
    USE SIGNAL ;
    PORT
      LAYER M4 ;
        RECT  0 136.62 0.192 136.644 ;
    END
  END rsp_data[611]
  PIN rsp_data[612]
    DIRECTION INPUT ;
    USE SIGNAL ;
    PORT
      LAYER M4 ;
        RECT  0 136.812 0.192 136.836 ;
    END
  END rsp_data[612]
  PIN rsp_data[613]
    DIRECTION INPUT ;
    USE SIGNAL ;
    PORT
      LAYER M4 ;
        RECT  0 137.052 0.192 137.076 ;
    END
  END rsp_data[613]
  PIN rsp_data[614]
    DIRECTION INPUT ;
    USE SIGNAL ;
    PORT
      LAYER M4 ;
        RECT  0 137.292 0.192 137.316 ;
    END
  END rsp_data[614]
  PIN rsp_data[615]
    DIRECTION INPUT ;
    USE SIGNAL ;
    PORT
      LAYER M4 ;
        RECT  0 137.484 0.192 137.508 ;
    END
  END rsp_data[615]
  PIN rsp_data[616]
    DIRECTION INPUT ;
    USE SIGNAL ;
    PORT
      LAYER M4 ;
        RECT  0 137.724 0.192 137.748 ;
    END
  END rsp_data[616]
  PIN rsp_data[617]
    DIRECTION INPUT ;
    USE SIGNAL ;
    PORT
      LAYER M4 ;
        RECT  0 137.916 0.192 137.94 ;
    END
  END rsp_data[617]
  PIN rsp_data[618]
    DIRECTION INPUT ;
    USE SIGNAL ;
    PORT
      LAYER M4 ;
        RECT  0 138.156 0.192 138.18 ;
    END
  END rsp_data[618]
  PIN rsp_data[619]
    DIRECTION INPUT ;
    USE SIGNAL ;
    PORT
      LAYER M4 ;
        RECT  0 138.348 0.192 138.372 ;
    END
  END rsp_data[619]
  PIN rsp_data[61]
    DIRECTION INPUT ;
    USE SIGNAL ;
    PORT
      LAYER M4 ;
        RECT  0 16.524 0.192 16.548 ;
    END
  END rsp_data[61]
  PIN rsp_data[620]
    DIRECTION INPUT ;
    USE SIGNAL ;
    PORT
      LAYER M4 ;
        RECT  0 138.588 0.192 138.612 ;
    END
  END rsp_data[620]
  PIN rsp_data[621]
    DIRECTION INPUT ;
    USE SIGNAL ;
    PORT
      LAYER M4 ;
        RECT  0 138.78 0.192 138.804 ;
    END
  END rsp_data[621]
  PIN rsp_data[622]
    DIRECTION INPUT ;
    USE SIGNAL ;
    PORT
      LAYER M4 ;
        RECT  0 139.02 0.192 139.044 ;
    END
  END rsp_data[622]
  PIN rsp_data[623]
    DIRECTION INPUT ;
    USE SIGNAL ;
    PORT
      LAYER M4 ;
        RECT  0 139.212 0.192 139.236 ;
    END
  END rsp_data[623]
  PIN rsp_data[624]
    DIRECTION INPUT ;
    USE SIGNAL ;
    PORT
      LAYER M4 ;
        RECT  0 139.452 0.192 139.476 ;
    END
  END rsp_data[624]
  PIN rsp_data[625]
    DIRECTION INPUT ;
    USE SIGNAL ;
    PORT
      LAYER M4 ;
        RECT  0 139.692 0.192 139.716 ;
    END
  END rsp_data[625]
  PIN rsp_data[626]
    DIRECTION INPUT ;
    USE SIGNAL ;
    PORT
      LAYER M4 ;
        RECT  0 139.884 0.192 139.908 ;
    END
  END rsp_data[626]
  PIN rsp_data[627]
    DIRECTION INPUT ;
    USE SIGNAL ;
    PORT
      LAYER M4 ;
        RECT  0 140.124 0.192 140.148 ;
    END
  END rsp_data[627]
  PIN rsp_data[628]
    DIRECTION INPUT ;
    USE SIGNAL ;
    PORT
      LAYER M4 ;
        RECT  0 140.316 0.192 140.34 ;
    END
  END rsp_data[628]
  PIN rsp_data[629]
    DIRECTION INPUT ;
    USE SIGNAL ;
    PORT
      LAYER M4 ;
        RECT  0 140.556 0.192 140.58 ;
    END
  END rsp_data[629]
  PIN rsp_data[62]
    DIRECTION INPUT ;
    USE SIGNAL ;
    PORT
      LAYER M4 ;
        RECT  0 16.716 0.192 16.74 ;
    END
  END rsp_data[62]
  PIN rsp_data[630]
    DIRECTION INPUT ;
    USE SIGNAL ;
    PORT
      LAYER M4 ;
        RECT  0 140.748 0.192 140.772 ;
    END
  END rsp_data[630]
  PIN rsp_data[631]
    DIRECTION INPUT ;
    USE SIGNAL ;
    PORT
      LAYER M4 ;
        RECT  0 140.988 0.192 141.012 ;
    END
  END rsp_data[631]
  PIN rsp_data[632]
    DIRECTION INPUT ;
    USE SIGNAL ;
    PORT
      LAYER M4 ;
        RECT  0 141.18 0.192 141.204 ;
    END
  END rsp_data[632]
  PIN rsp_data[633]
    DIRECTION INPUT ;
    USE SIGNAL ;
    PORT
      LAYER M4 ;
        RECT  0 141.42 0.192 141.444 ;
    END
  END rsp_data[633]
  PIN rsp_data[634]
    DIRECTION INPUT ;
    USE SIGNAL ;
    PORT
      LAYER M4 ;
        RECT  0 141.612 0.192 141.636 ;
    END
  END rsp_data[634]
  PIN rsp_data[635]
    DIRECTION INPUT ;
    USE SIGNAL ;
    PORT
      LAYER M4 ;
        RECT  0 141.852 0.192 141.876 ;
    END
  END rsp_data[635]
  PIN rsp_data[636]
    DIRECTION INPUT ;
    USE SIGNAL ;
    PORT
      LAYER M4 ;
        RECT  0 142.092 0.192 142.116 ;
    END
  END rsp_data[636]
  PIN rsp_data[637]
    DIRECTION INPUT ;
    USE SIGNAL ;
    PORT
      LAYER M4 ;
        RECT  0 142.284 0.192 142.308 ;
    END
  END rsp_data[637]
  PIN rsp_data[638]
    DIRECTION INPUT ;
    USE SIGNAL ;
    PORT
      LAYER M4 ;
        RECT  0 142.524 0.192 142.548 ;
    END
  END rsp_data[638]
  PIN rsp_data[639]
    DIRECTION INPUT ;
    USE SIGNAL ;
    PORT
      LAYER M4 ;
        RECT  0 142.716 0.192 142.74 ;
    END
  END rsp_data[639]
  PIN rsp_data[63]
    DIRECTION INPUT ;
    USE SIGNAL ;
    PORT
      LAYER M4 ;
        RECT  0 16.956 0.192 16.98 ;
    END
  END rsp_data[63]
  PIN rsp_data[640]
    DIRECTION INPUT ;
    USE SIGNAL ;
    PORT
      LAYER M4 ;
        RECT  0 142.956 0.192 142.98 ;
    END
  END rsp_data[640]
  PIN rsp_data[641]
    DIRECTION INPUT ;
    USE SIGNAL ;
    PORT
      LAYER M4 ;
        RECT  0 143.148 0.192 143.172 ;
    END
  END rsp_data[641]
  PIN rsp_data[642]
    DIRECTION INPUT ;
    USE SIGNAL ;
    PORT
      LAYER M4 ;
        RECT  0 143.388 0.192 143.412 ;
    END
  END rsp_data[642]
  PIN rsp_data[643]
    DIRECTION INPUT ;
    USE SIGNAL ;
    PORT
      LAYER M4 ;
        RECT  0 143.58 0.192 143.604 ;
    END
  END rsp_data[643]
  PIN rsp_data[644]
    DIRECTION INPUT ;
    USE SIGNAL ;
    PORT
      LAYER M4 ;
        RECT  0 143.82 0.192 143.844 ;
    END
  END rsp_data[644]
  PIN rsp_data[645]
    DIRECTION INPUT ;
    USE SIGNAL ;
    PORT
      LAYER M4 ;
        RECT  0 144.06 0.192 144.084 ;
    END
  END rsp_data[645]
  PIN rsp_data[646]
    DIRECTION INPUT ;
    USE SIGNAL ;
    PORT
      LAYER M4 ;
        RECT  0 144.252 0.192 144.276 ;
    END
  END rsp_data[646]
  PIN rsp_data[647]
    DIRECTION INPUT ;
    USE SIGNAL ;
    PORT
      LAYER M4 ;
        RECT  0 144.492 0.192 144.516 ;
    END
  END rsp_data[647]
  PIN rsp_data[648]
    DIRECTION INPUT ;
    USE SIGNAL ;
    PORT
      LAYER M4 ;
        RECT  0 144.684 0.192 144.708 ;
    END
  END rsp_data[648]
  PIN rsp_data[649]
    DIRECTION INPUT ;
    USE SIGNAL ;
    PORT
      LAYER M4 ;
        RECT  0 144.924 0.192 144.948 ;
    END
  END rsp_data[649]
  PIN rsp_data[64]
    DIRECTION INPUT ;
    USE SIGNAL ;
    PORT
      LAYER M4 ;
        RECT  0 17.148 0.192 17.172 ;
    END
  END rsp_data[64]
  PIN rsp_data[650]
    DIRECTION INPUT ;
    USE SIGNAL ;
    PORT
      LAYER M4 ;
        RECT  0 145.116 0.192 145.14 ;
    END
  END rsp_data[650]
  PIN rsp_data[651]
    DIRECTION INPUT ;
    USE SIGNAL ;
    PORT
      LAYER M4 ;
        RECT  0 145.356 0.192 145.38 ;
    END
  END rsp_data[651]
  PIN rsp_data[652]
    DIRECTION INPUT ;
    USE SIGNAL ;
    PORT
      LAYER M4 ;
        RECT  0 145.548 0.192 145.572 ;
    END
  END rsp_data[652]
  PIN rsp_data[653]
    DIRECTION INPUT ;
    USE SIGNAL ;
    PORT
      LAYER M4 ;
        RECT  0 145.788 0.192 145.812 ;
    END
  END rsp_data[653]
  PIN rsp_data[654]
    DIRECTION INPUT ;
    USE SIGNAL ;
    PORT
      LAYER M4 ;
        RECT  0 145.98 0.192 146.004 ;
    END
  END rsp_data[654]
  PIN rsp_data[655]
    DIRECTION INPUT ;
    USE SIGNAL ;
    PORT
      LAYER M4 ;
        RECT  0 146.22 0.192 146.244 ;
    END
  END rsp_data[655]
  PIN rsp_data[656]
    DIRECTION INPUT ;
    USE SIGNAL ;
    PORT
      LAYER M4 ;
        RECT  0 146.46 0.192 146.484 ;
    END
  END rsp_data[656]
  PIN rsp_data[657]
    DIRECTION INPUT ;
    USE SIGNAL ;
    PORT
      LAYER M4 ;
        RECT  0 146.652 0.192 146.676 ;
    END
  END rsp_data[657]
  PIN rsp_data[658]
    DIRECTION INPUT ;
    USE SIGNAL ;
    PORT
      LAYER M4 ;
        RECT  0 146.892 0.192 146.916 ;
    END
  END rsp_data[658]
  PIN rsp_data[659]
    DIRECTION INPUT ;
    USE SIGNAL ;
    PORT
      LAYER M4 ;
        RECT  0 147.084 0.192 147.108 ;
    END
  END rsp_data[659]
  PIN rsp_data[65]
    DIRECTION INPUT ;
    USE SIGNAL ;
    PORT
      LAYER M4 ;
        RECT  0 17.388 0.192 17.412 ;
    END
  END rsp_data[65]
  PIN rsp_data[660]
    DIRECTION INPUT ;
    USE SIGNAL ;
    PORT
      LAYER M4 ;
        RECT  0 147.324 0.192 147.348 ;
    END
  END rsp_data[660]
  PIN rsp_data[661]
    DIRECTION INPUT ;
    USE SIGNAL ;
    PORT
      LAYER M4 ;
        RECT  0 147.516 0.192 147.54 ;
    END
  END rsp_data[661]
  PIN rsp_data[662]
    DIRECTION INPUT ;
    USE SIGNAL ;
    PORT
      LAYER M4 ;
        RECT  0 147.756 0.192 147.78 ;
    END
  END rsp_data[662]
  PIN rsp_data[663]
    DIRECTION INPUT ;
    USE SIGNAL ;
    PORT
      LAYER M4 ;
        RECT  0 147.948 0.192 147.972 ;
    END
  END rsp_data[663]
  PIN rsp_data[664]
    DIRECTION INPUT ;
    USE SIGNAL ;
    PORT
      LAYER M4 ;
        RECT  0 148.188 0.192 148.212 ;
    END
  END rsp_data[664]
  PIN rsp_data[665]
    DIRECTION INPUT ;
    USE SIGNAL ;
    PORT
      LAYER M4 ;
        RECT  0 148.428 0.192 148.452 ;
    END
  END rsp_data[665]
  PIN rsp_data[666]
    DIRECTION INPUT ;
    USE SIGNAL ;
    PORT
      LAYER M4 ;
        RECT  0 148.62 0.192 148.644 ;
    END
  END rsp_data[666]
  PIN rsp_data[667]
    DIRECTION INPUT ;
    USE SIGNAL ;
    PORT
      LAYER M4 ;
        RECT  0 148.86 0.192 148.884 ;
    END
  END rsp_data[667]
  PIN rsp_data[668]
    DIRECTION INPUT ;
    USE SIGNAL ;
    PORT
      LAYER M4 ;
        RECT  0 149.052 0.192 149.076 ;
    END
  END rsp_data[668]
  PIN rsp_data[669]
    DIRECTION INPUT ;
    USE SIGNAL ;
    PORT
      LAYER M4 ;
        RECT  0 149.292 0.192 149.316 ;
    END
  END rsp_data[669]
  PIN rsp_data[66]
    DIRECTION INPUT ;
    USE SIGNAL ;
    PORT
      LAYER M4 ;
        RECT  0 17.58 0.192 17.604 ;
    END
  END rsp_data[66]
  PIN rsp_data[670]
    DIRECTION INPUT ;
    USE SIGNAL ;
    PORT
      LAYER M4 ;
        RECT  0 149.484 0.192 149.508 ;
    END
  END rsp_data[670]
  PIN rsp_data[671]
    DIRECTION INPUT ;
    USE SIGNAL ;
    PORT
      LAYER M4 ;
        RECT  0 149.724 0.192 149.748 ;
    END
  END rsp_data[671]
  PIN rsp_data[672]
    DIRECTION INPUT ;
    USE SIGNAL ;
    PORT
      LAYER M4 ;
        RECT  0 149.916 0.192 149.94 ;
    END
  END rsp_data[672]
  PIN rsp_data[673]
    DIRECTION INPUT ;
    USE SIGNAL ;
    PORT
      LAYER M4 ;
        RECT  0 150.156 0.192 150.18 ;
    END
  END rsp_data[673]
  PIN rsp_data[674]
    DIRECTION INPUT ;
    USE SIGNAL ;
    PORT
      LAYER M4 ;
        RECT  0 150.348 0.192 150.372 ;
    END
  END rsp_data[674]
  PIN rsp_data[675]
    DIRECTION INPUT ;
    USE SIGNAL ;
    PORT
      LAYER M4 ;
        RECT  0 150.588 0.192 150.612 ;
    END
  END rsp_data[675]
  PIN rsp_data[676]
    DIRECTION INPUT ;
    USE SIGNAL ;
    PORT
      LAYER M4 ;
        RECT  0 150.828 0.192 150.852 ;
    END
  END rsp_data[676]
  PIN rsp_data[677]
    DIRECTION INPUT ;
    USE SIGNAL ;
    PORT
      LAYER M4 ;
        RECT  0 151.02 0.192 151.044 ;
    END
  END rsp_data[677]
  PIN rsp_data[678]
    DIRECTION INPUT ;
    USE SIGNAL ;
    PORT
      LAYER M4 ;
        RECT  0 151.26 0.192 151.284 ;
    END
  END rsp_data[678]
  PIN rsp_data[679]
    DIRECTION INPUT ;
    USE SIGNAL ;
    PORT
      LAYER M4 ;
        RECT  0 151.452 0.192 151.476 ;
    END
  END rsp_data[679]
  PIN rsp_data[67]
    DIRECTION INPUT ;
    USE SIGNAL ;
    PORT
      LAYER M4 ;
        RECT  0 17.82 0.192 17.844 ;
    END
  END rsp_data[67]
  PIN rsp_data[680]
    DIRECTION INPUT ;
    USE SIGNAL ;
    PORT
      LAYER M4 ;
        RECT  0 151.692 0.192 151.716 ;
    END
  END rsp_data[680]
  PIN rsp_data[681]
    DIRECTION INPUT ;
    USE SIGNAL ;
    PORT
      LAYER M4 ;
        RECT  0 151.884 0.192 151.908 ;
    END
  END rsp_data[681]
  PIN rsp_data[682]
    DIRECTION INPUT ;
    USE SIGNAL ;
    PORT
      LAYER M4 ;
        RECT  0 152.124 0.192 152.148 ;
    END
  END rsp_data[682]
  PIN rsp_data[683]
    DIRECTION INPUT ;
    USE SIGNAL ;
    PORT
      LAYER M4 ;
        RECT  0 152.316 0.192 152.34 ;
    END
  END rsp_data[683]
  PIN rsp_data[684]
    DIRECTION INPUT ;
    USE SIGNAL ;
    PORT
      LAYER M4 ;
        RECT  0 152.556 0.192 152.58 ;
    END
  END rsp_data[684]
  PIN rsp_data[685]
    DIRECTION INPUT ;
    USE SIGNAL ;
    PORT
      LAYER M4 ;
        RECT  0 152.796 0.192 152.82 ;
    END
  END rsp_data[685]
  PIN rsp_data[686]
    DIRECTION INPUT ;
    USE SIGNAL ;
    PORT
      LAYER M4 ;
        RECT  0 152.988 0.192 153.012 ;
    END
  END rsp_data[686]
  PIN rsp_data[687]
    DIRECTION INPUT ;
    USE SIGNAL ;
    PORT
      LAYER M4 ;
        RECT  0 153.228 0.192 153.252 ;
    END
  END rsp_data[687]
  PIN rsp_data[688]
    DIRECTION INPUT ;
    USE SIGNAL ;
    PORT
      LAYER M4 ;
        RECT  0 153.42 0.192 153.444 ;
    END
  END rsp_data[688]
  PIN rsp_data[689]
    DIRECTION INPUT ;
    USE SIGNAL ;
    PORT
      LAYER M4 ;
        RECT  0 153.66 0.192 153.684 ;
    END
  END rsp_data[689]
  PIN rsp_data[68]
    DIRECTION INPUT ;
    USE SIGNAL ;
    PORT
      LAYER M4 ;
        RECT  0 18.06 0.192 18.084 ;
    END
  END rsp_data[68]
  PIN rsp_data[690]
    DIRECTION INPUT ;
    USE SIGNAL ;
    PORT
      LAYER M4 ;
        RECT  0 153.852 0.192 153.876 ;
    END
  END rsp_data[690]
  PIN rsp_data[691]
    DIRECTION INPUT ;
    USE SIGNAL ;
    PORT
      LAYER M4 ;
        RECT  0 154.092 0.192 154.116 ;
    END
  END rsp_data[691]
  PIN rsp_data[692]
    DIRECTION INPUT ;
    USE SIGNAL ;
    PORT
      LAYER M4 ;
        RECT  0 154.284 0.192 154.308 ;
    END
  END rsp_data[692]
  PIN rsp_data[693]
    DIRECTION INPUT ;
    USE SIGNAL ;
    PORT
      LAYER M4 ;
        RECT  0 154.524 0.192 154.548 ;
    END
  END rsp_data[693]
  PIN rsp_data[694]
    DIRECTION INPUT ;
    USE SIGNAL ;
    PORT
      LAYER M4 ;
        RECT  0 154.716 0.192 154.74 ;
    END
  END rsp_data[694]
  PIN rsp_data[695]
    DIRECTION INPUT ;
    USE SIGNAL ;
    PORT
      LAYER M4 ;
        RECT  0 154.956 0.192 154.98 ;
    END
  END rsp_data[695]
  PIN rsp_data[696]
    DIRECTION INPUT ;
    USE SIGNAL ;
    PORT
      LAYER M4 ;
        RECT  0 155.196 0.192 155.22 ;
    END
  END rsp_data[696]
  PIN rsp_data[697]
    DIRECTION INPUT ;
    USE SIGNAL ;
    PORT
      LAYER M4 ;
        RECT  0 155.388 0.192 155.412 ;
    END
  END rsp_data[697]
  PIN rsp_data[698]
    DIRECTION INPUT ;
    USE SIGNAL ;
    PORT
      LAYER M4 ;
        RECT  0 155.628 0.192 155.652 ;
    END
  END rsp_data[698]
  PIN rsp_data[699]
    DIRECTION INPUT ;
    USE SIGNAL ;
    PORT
      LAYER M4 ;
        RECT  0 155.82 0.192 155.844 ;
    END
  END rsp_data[699]
  PIN rsp_data[69]
    DIRECTION INPUT ;
    USE SIGNAL ;
    PORT
      LAYER M4 ;
        RECT  0 18.252 0.192 18.276 ;
    END
  END rsp_data[69]
  PIN rsp_data[6]
    DIRECTION INPUT ;
    USE SIGNAL ;
    PORT
      LAYER M4 ;
        RECT  0 4.476 0.192 4.5 ;
    END
  END rsp_data[6]
  PIN rsp_data[700]
    DIRECTION INPUT ;
    USE SIGNAL ;
    PORT
      LAYER M4 ;
        RECT  0 156.06 0.192 156.084 ;
    END
  END rsp_data[700]
  PIN rsp_data[701]
    DIRECTION INPUT ;
    USE SIGNAL ;
    PORT
      LAYER M4 ;
        RECT  0 156.252 0.192 156.276 ;
    END
  END rsp_data[701]
  PIN rsp_data[702]
    DIRECTION INPUT ;
    USE SIGNAL ;
    PORT
      LAYER M4 ;
        RECT  0 156.492 0.192 156.516 ;
    END
  END rsp_data[702]
  PIN rsp_data[703]
    DIRECTION INPUT ;
    USE SIGNAL ;
    PORT
      LAYER M4 ;
        RECT  0 156.684 0.192 156.708 ;
    END
  END rsp_data[703]
  PIN rsp_data[704]
    DIRECTION INPUT ;
    USE SIGNAL ;
    PORT
      LAYER M4 ;
        RECT  0 156.924 0.192 156.948 ;
    END
  END rsp_data[704]
  PIN rsp_data[705]
    DIRECTION INPUT ;
    USE SIGNAL ;
    PORT
      LAYER M4 ;
        RECT  0 157.116 0.192 157.14 ;
    END
  END rsp_data[705]
  PIN rsp_data[706]
    DIRECTION INPUT ;
    USE SIGNAL ;
    PORT
      LAYER M4 ;
        RECT  0 157.356 0.192 157.38 ;
    END
  END rsp_data[706]
  PIN rsp_data[707]
    DIRECTION INPUT ;
    USE SIGNAL ;
    PORT
      LAYER M4 ;
        RECT  0 157.596 0.192 157.62 ;
    END
  END rsp_data[707]
  PIN rsp_data[708]
    DIRECTION INPUT ;
    USE SIGNAL ;
    PORT
      LAYER M4 ;
        RECT  0 157.788 0.192 157.812 ;
    END
  END rsp_data[708]
  PIN rsp_data[709]
    DIRECTION INPUT ;
    USE SIGNAL ;
    PORT
      LAYER M4 ;
        RECT  0 158.028 0.192 158.052 ;
    END
  END rsp_data[709]
  PIN rsp_data[70]
    DIRECTION INPUT ;
    USE SIGNAL ;
    PORT
      LAYER M4 ;
        RECT  0 18.492 0.192 18.516 ;
    END
  END rsp_data[70]
  PIN rsp_data[710]
    DIRECTION INPUT ;
    USE SIGNAL ;
    PORT
      LAYER M4 ;
        RECT  0 158.22 0.192 158.244 ;
    END
  END rsp_data[710]
  PIN rsp_data[711]
    DIRECTION INPUT ;
    USE SIGNAL ;
    PORT
      LAYER M4 ;
        RECT  0 158.46 0.192 158.484 ;
    END
  END rsp_data[711]
  PIN rsp_data[712]
    DIRECTION INPUT ;
    USE SIGNAL ;
    PORT
      LAYER M4 ;
        RECT  0 158.652 0.192 158.676 ;
    END
  END rsp_data[712]
  PIN rsp_data[713]
    DIRECTION INPUT ;
    USE SIGNAL ;
    PORT
      LAYER M4 ;
        RECT  0 158.892 0.192 158.916 ;
    END
  END rsp_data[713]
  PIN rsp_data[714]
    DIRECTION INPUT ;
    USE SIGNAL ;
    PORT
      LAYER M4 ;
        RECT  0 159.084 0.192 159.108 ;
    END
  END rsp_data[714]
  PIN rsp_data[715]
    DIRECTION INPUT ;
    USE SIGNAL ;
    PORT
      LAYER M4 ;
        RECT  0 159.324 0.192 159.348 ;
    END
  END rsp_data[715]
  PIN rsp_data[716]
    DIRECTION INPUT ;
    USE SIGNAL ;
    PORT
      LAYER M4 ;
        RECT  0 159.564 0.192 159.588 ;
    END
  END rsp_data[716]
  PIN rsp_data[717]
    DIRECTION INPUT ;
    USE SIGNAL ;
    PORT
      LAYER M4 ;
        RECT  0 159.756 0.192 159.78 ;
    END
  END rsp_data[717]
  PIN rsp_data[718]
    DIRECTION INPUT ;
    USE SIGNAL ;
    PORT
      LAYER M4 ;
        RECT  0 159.996 0.192 160.02 ;
    END
  END rsp_data[718]
  PIN rsp_data[719]
    DIRECTION INPUT ;
    USE SIGNAL ;
    PORT
      LAYER M4 ;
        RECT  0 160.188 0.192 160.212 ;
    END
  END rsp_data[719]
  PIN rsp_data[71]
    DIRECTION INPUT ;
    USE SIGNAL ;
    PORT
      LAYER M4 ;
        RECT  0 18.684 0.192 18.708 ;
    END
  END rsp_data[71]
  PIN rsp_data[720]
    DIRECTION INPUT ;
    USE SIGNAL ;
    PORT
      LAYER M4 ;
        RECT  0 160.428 0.192 160.452 ;
    END
  END rsp_data[720]
  PIN rsp_data[721]
    DIRECTION INPUT ;
    USE SIGNAL ;
    PORT
      LAYER M4 ;
        RECT  0 160.62 0.192 160.644 ;
    END
  END rsp_data[721]
  PIN rsp_data[722]
    DIRECTION INPUT ;
    USE SIGNAL ;
    PORT
      LAYER M4 ;
        RECT  0 160.86 0.192 160.884 ;
    END
  END rsp_data[722]
  PIN rsp_data[723]
    DIRECTION INPUT ;
    USE SIGNAL ;
    PORT
      LAYER M4 ;
        RECT  0 161.052 0.192 161.076 ;
    END
  END rsp_data[723]
  PIN rsp_data[724]
    DIRECTION INPUT ;
    USE SIGNAL ;
    PORT
      LAYER M4 ;
        RECT  0 161.292 0.192 161.316 ;
    END
  END rsp_data[724]
  PIN rsp_data[725]
    DIRECTION INPUT ;
    USE SIGNAL ;
    PORT
      LAYER M4 ;
        RECT  0 161.484 0.192 161.508 ;
    END
  END rsp_data[725]
  PIN rsp_data[726]
    DIRECTION INPUT ;
    USE SIGNAL ;
    PORT
      LAYER M4 ;
        RECT  0 161.724 0.192 161.748 ;
    END
  END rsp_data[726]
  PIN rsp_data[727]
    DIRECTION INPUT ;
    USE SIGNAL ;
    PORT
      LAYER M4 ;
        RECT  0 161.964 0.192 161.988 ;
    END
  END rsp_data[727]
  PIN rsp_data[728]
    DIRECTION INPUT ;
    USE SIGNAL ;
    PORT
      LAYER M4 ;
        RECT  0 162.156 0.192 162.18 ;
    END
  END rsp_data[728]
  PIN rsp_data[729]
    DIRECTION INPUT ;
    USE SIGNAL ;
    PORT
      LAYER M4 ;
        RECT  0 162.396 0.192 162.42 ;
    END
  END rsp_data[729]
  PIN rsp_data[72]
    DIRECTION INPUT ;
    USE SIGNAL ;
    PORT
      LAYER M4 ;
        RECT  0 18.924 0.192 18.948 ;
    END
  END rsp_data[72]
  PIN rsp_data[730]
    DIRECTION INPUT ;
    USE SIGNAL ;
    PORT
      LAYER M4 ;
        RECT  0 162.588 0.192 162.612 ;
    END
  END rsp_data[730]
  PIN rsp_data[731]
    DIRECTION INPUT ;
    USE SIGNAL ;
    PORT
      LAYER M4 ;
        RECT  0 162.828 0.192 162.852 ;
    END
  END rsp_data[731]
  PIN rsp_data[732]
    DIRECTION INPUT ;
    USE SIGNAL ;
    PORT
      LAYER M4 ;
        RECT  0 163.02 0.192 163.044 ;
    END
  END rsp_data[732]
  PIN rsp_data[733]
    DIRECTION INPUT ;
    USE SIGNAL ;
    PORT
      LAYER M4 ;
        RECT  0 163.26 0.192 163.284 ;
    END
  END rsp_data[733]
  PIN rsp_data[734]
    DIRECTION INPUT ;
    USE SIGNAL ;
    PORT
      LAYER M4 ;
        RECT  0 163.452 0.192 163.476 ;
    END
  END rsp_data[734]
  PIN rsp_data[735]
    DIRECTION INPUT ;
    USE SIGNAL ;
    PORT
      LAYER M4 ;
        RECT  0 163.692 0.192 163.716 ;
    END
  END rsp_data[735]
  PIN rsp_data[736]
    DIRECTION INPUT ;
    USE SIGNAL ;
    PORT
      LAYER M4 ;
        RECT  0 163.932 0.192 163.956 ;
    END
  END rsp_data[736]
  PIN rsp_data[737]
    DIRECTION INPUT ;
    USE SIGNAL ;
    PORT
      LAYER M4 ;
        RECT  0 164.124 0.192 164.148 ;
    END
  END rsp_data[737]
  PIN rsp_data[738]
    DIRECTION INPUT ;
    USE SIGNAL ;
    PORT
      LAYER M4 ;
        RECT  0 164.364 0.192 164.388 ;
    END
  END rsp_data[738]
  PIN rsp_data[739]
    DIRECTION INPUT ;
    USE SIGNAL ;
    PORT
      LAYER M4 ;
        RECT  0 164.556 0.192 164.58 ;
    END
  END rsp_data[739]
  PIN rsp_data[73]
    DIRECTION INPUT ;
    USE SIGNAL ;
    PORT
      LAYER M4 ;
        RECT  0 19.116 0.192 19.14 ;
    END
  END rsp_data[73]
  PIN rsp_data[740]
    DIRECTION INPUT ;
    USE SIGNAL ;
    PORT
      LAYER M4 ;
        RECT  0 164.796 0.192 164.82 ;
    END
  END rsp_data[740]
  PIN rsp_data[741]
    DIRECTION INPUT ;
    USE SIGNAL ;
    PORT
      LAYER M4 ;
        RECT  0 164.988 0.192 165.012 ;
    END
  END rsp_data[741]
  PIN rsp_data[742]
    DIRECTION INPUT ;
    USE SIGNAL ;
    PORT
      LAYER M4 ;
        RECT  0 165.228 0.192 165.252 ;
    END
  END rsp_data[742]
  PIN rsp_data[743]
    DIRECTION INPUT ;
    USE SIGNAL ;
    PORT
      LAYER M4 ;
        RECT  0 165.42 0.192 165.444 ;
    END
  END rsp_data[743]
  PIN rsp_data[744]
    DIRECTION INPUT ;
    USE SIGNAL ;
    PORT
      LAYER M4 ;
        RECT  0 165.66 0.192 165.684 ;
    END
  END rsp_data[744]
  PIN rsp_data[745]
    DIRECTION INPUT ;
    USE SIGNAL ;
    PORT
      LAYER M4 ;
        RECT  0 165.852 0.192 165.876 ;
    END
  END rsp_data[745]
  PIN rsp_data[746]
    DIRECTION INPUT ;
    USE SIGNAL ;
    PORT
      LAYER M4 ;
        RECT  0 166.092 0.192 166.116 ;
    END
  END rsp_data[746]
  PIN rsp_data[747]
    DIRECTION INPUT ;
    USE SIGNAL ;
    PORT
      LAYER M4 ;
        RECT  0 166.332 0.192 166.356 ;
    END
  END rsp_data[747]
  PIN rsp_data[748]
    DIRECTION INPUT ;
    USE SIGNAL ;
    PORT
      LAYER M4 ;
        RECT  0 166.524 0.192 166.548 ;
    END
  END rsp_data[748]
  PIN rsp_data[749]
    DIRECTION INPUT ;
    USE SIGNAL ;
    PORT
      LAYER M4 ;
        RECT  0 166.764 0.192 166.788 ;
    END
  END rsp_data[749]
  PIN rsp_data[74]
    DIRECTION INPUT ;
    USE SIGNAL ;
    PORT
      LAYER M4 ;
        RECT  0 19.356 0.192 19.38 ;
    END
  END rsp_data[74]
  PIN rsp_data[750]
    DIRECTION INPUT ;
    USE SIGNAL ;
    PORT
      LAYER M4 ;
        RECT  0 166.956 0.192 166.98 ;
    END
  END rsp_data[750]
  PIN rsp_data[751]
    DIRECTION INPUT ;
    USE SIGNAL ;
    PORT
      LAYER M4 ;
        RECT  0 167.196 0.192 167.22 ;
    END
  END rsp_data[751]
  PIN rsp_data[752]
    DIRECTION INPUT ;
    USE SIGNAL ;
    PORT
      LAYER M4 ;
        RECT  0 167.388 0.192 167.412 ;
    END
  END rsp_data[752]
  PIN rsp_data[753]
    DIRECTION INPUT ;
    USE SIGNAL ;
    PORT
      LAYER M4 ;
        RECT  0 167.628 0.192 167.652 ;
    END
  END rsp_data[753]
  PIN rsp_data[754]
    DIRECTION INPUT ;
    USE SIGNAL ;
    PORT
      LAYER M4 ;
        RECT  0 167.82 0.192 167.844 ;
    END
  END rsp_data[754]
  PIN rsp_data[755]
    DIRECTION INPUT ;
    USE SIGNAL ;
    PORT
      LAYER M4 ;
        RECT  0 168.06 0.192 168.084 ;
    END
  END rsp_data[755]
  PIN rsp_data[756]
    DIRECTION INPUT ;
    USE SIGNAL ;
    PORT
      LAYER M4 ;
        RECT  0 168.3 0.192 168.324 ;
    END
  END rsp_data[756]
  PIN rsp_data[757]
    DIRECTION INPUT ;
    USE SIGNAL ;
    PORT
      LAYER M4 ;
        RECT  0 168.492 0.192 168.516 ;
    END
  END rsp_data[757]
  PIN rsp_data[758]
    DIRECTION INPUT ;
    USE SIGNAL ;
    PORT
      LAYER M4 ;
        RECT  0 168.732 0.192 168.756 ;
    END
  END rsp_data[758]
  PIN rsp_data[759]
    DIRECTION INPUT ;
    USE SIGNAL ;
    PORT
      LAYER M4 ;
        RECT  0 168.924 0.192 168.948 ;
    END
  END rsp_data[759]
  PIN rsp_data[75]
    DIRECTION INPUT ;
    USE SIGNAL ;
    PORT
      LAYER M4 ;
        RECT  0 19.548 0.192 19.572 ;
    END
  END rsp_data[75]
  PIN rsp_data[760]
    DIRECTION INPUT ;
    USE SIGNAL ;
    PORT
      LAYER M4 ;
        RECT  0 169.164 0.192 169.188 ;
    END
  END rsp_data[760]
  PIN rsp_data[761]
    DIRECTION INPUT ;
    USE SIGNAL ;
    PORT
      LAYER M4 ;
        RECT  0 169.356 0.192 169.38 ;
    END
  END rsp_data[761]
  PIN rsp_data[762]
    DIRECTION INPUT ;
    USE SIGNAL ;
    PORT
      LAYER M4 ;
        RECT  0 169.596 0.192 169.62 ;
    END
  END rsp_data[762]
  PIN rsp_data[763]
    DIRECTION INPUT ;
    USE SIGNAL ;
    PORT
      LAYER M4 ;
        RECT  0 169.788 0.192 169.812 ;
    END
  END rsp_data[763]
  PIN rsp_data[764]
    DIRECTION INPUT ;
    USE SIGNAL ;
    PORT
      LAYER M4 ;
        RECT  0 170.028 0.192 170.052 ;
    END
  END rsp_data[764]
  PIN rsp_data[765]
    DIRECTION INPUT ;
    USE SIGNAL ;
    PORT
      LAYER M4 ;
        RECT  0 170.22 0.192 170.244 ;
    END
  END rsp_data[765]
  PIN rsp_data[766]
    DIRECTION INPUT ;
    USE SIGNAL ;
    PORT
      LAYER M4 ;
        RECT  0 170.46 0.192 170.484 ;
    END
  END rsp_data[766]
  PIN rsp_data[767]
    DIRECTION INPUT ;
    USE SIGNAL ;
    PORT
      LAYER M4 ;
        RECT  0 170.7 0.192 170.724 ;
    END
  END rsp_data[767]
  PIN rsp_data[76]
    DIRECTION INPUT ;
    USE SIGNAL ;
    PORT
      LAYER M4 ;
        RECT  0 19.788 0.192 19.812 ;
    END
  END rsp_data[76]
  PIN rsp_data[77]
    DIRECTION INPUT ;
    USE SIGNAL ;
    PORT
      LAYER M4 ;
        RECT  0 19.98 0.192 20.004 ;
    END
  END rsp_data[77]
  PIN rsp_data[78]
    DIRECTION INPUT ;
    USE SIGNAL ;
    PORT
      LAYER M4 ;
        RECT  0 20.22 0.192 20.244 ;
    END
  END rsp_data[78]
  PIN rsp_data[79]
    DIRECTION INPUT ;
    USE SIGNAL ;
    PORT
      LAYER M4 ;
        RECT  0 20.46 0.192 20.484 ;
    END
  END rsp_data[79]
  PIN rsp_data[7]
    DIRECTION INPUT ;
    USE SIGNAL ;
    PORT
      LAYER M4 ;
        RECT  0 4.716 0.192 4.74 ;
    END
  END rsp_data[7]
  PIN rsp_data[80]
    DIRECTION INPUT ;
    USE SIGNAL ;
    PORT
      LAYER M4 ;
        RECT  0 20.652 0.192 20.676 ;
    END
  END rsp_data[80]
  PIN rsp_data[81]
    DIRECTION INPUT ;
    USE SIGNAL ;
    PORT
      LAYER M4 ;
        RECT  0 20.892 0.192 20.916 ;
    END
  END rsp_data[81]
  PIN rsp_data[82]
    DIRECTION INPUT ;
    USE SIGNAL ;
    PORT
      LAYER M4 ;
        RECT  0 21.084 0.192 21.108 ;
    END
  END rsp_data[82]
  PIN rsp_data[83]
    DIRECTION INPUT ;
    USE SIGNAL ;
    PORT
      LAYER M4 ;
        RECT  0 21.324 0.192 21.348 ;
    END
  END rsp_data[83]
  PIN rsp_data[84]
    DIRECTION INPUT ;
    USE SIGNAL ;
    PORT
      LAYER M4 ;
        RECT  0 21.516 0.192 21.54 ;
    END
  END rsp_data[84]
  PIN rsp_data[85]
    DIRECTION INPUT ;
    USE SIGNAL ;
    PORT
      LAYER M4 ;
        RECT  0 21.756 0.192 21.78 ;
    END
  END rsp_data[85]
  PIN rsp_data[86]
    DIRECTION INPUT ;
    USE SIGNAL ;
    PORT
      LAYER M4 ;
        RECT  0 21.948 0.192 21.972 ;
    END
  END rsp_data[86]
  PIN rsp_data[87]
    DIRECTION INPUT ;
    USE SIGNAL ;
    PORT
      LAYER M4 ;
        RECT  0 22.188 0.192 22.212 ;
    END
  END rsp_data[87]
  PIN rsp_data[88]
    DIRECTION INPUT ;
    USE SIGNAL ;
    PORT
      LAYER M4 ;
        RECT  0 22.428 0.192 22.452 ;
    END
  END rsp_data[88]
  PIN rsp_data[89]
    DIRECTION INPUT ;
    USE SIGNAL ;
    PORT
      LAYER M4 ;
        RECT  0 22.62 0.192 22.644 ;
    END
  END rsp_data[89]
  PIN rsp_data[8]
    DIRECTION INPUT ;
    USE SIGNAL ;
    PORT
      LAYER M4 ;
        RECT  0 4.956 0.192 4.98 ;
    END
  END rsp_data[8]
  PIN rsp_data[90]
    DIRECTION INPUT ;
    USE SIGNAL ;
    PORT
      LAYER M4 ;
        RECT  0 22.86 0.192 22.884 ;
    END
  END rsp_data[90]
  PIN rsp_data[91]
    DIRECTION INPUT ;
    USE SIGNAL ;
    PORT
      LAYER M4 ;
        RECT  0 23.052 0.192 23.076 ;
    END
  END rsp_data[91]
  PIN rsp_data[92]
    DIRECTION INPUT ;
    USE SIGNAL ;
    PORT
      LAYER M4 ;
        RECT  0 23.292 0.192 23.316 ;
    END
  END rsp_data[92]
  PIN rsp_data[93]
    DIRECTION INPUT ;
    USE SIGNAL ;
    PORT
      LAYER M4 ;
        RECT  0 23.484 0.192 23.508 ;
    END
  END rsp_data[93]
  PIN rsp_data[94]
    DIRECTION INPUT ;
    USE SIGNAL ;
    PORT
      LAYER M4 ;
        RECT  0 23.724 0.192 23.748 ;
    END
  END rsp_data[94]
  PIN rsp_data[95]
    DIRECTION INPUT ;
    USE SIGNAL ;
    PORT
      LAYER M4 ;
        RECT  0 23.916 0.192 23.94 ;
    END
  END rsp_data[95]
  PIN rsp_data[96]
    DIRECTION INPUT ;
    USE SIGNAL ;
    PORT
      LAYER M4 ;
        RECT  0 24.156 0.192 24.18 ;
    END
  END rsp_data[96]
  PIN rsp_data[97]
    DIRECTION INPUT ;
    USE SIGNAL ;
    PORT
      LAYER M4 ;
        RECT  0 24.348 0.192 24.372 ;
    END
  END rsp_data[97]
  PIN rsp_data[98]
    DIRECTION INPUT ;
    USE SIGNAL ;
    PORT
      LAYER M4 ;
        RECT  0 24.588 0.192 24.612 ;
    END
  END rsp_data[98]
  PIN rsp_data[99]
    DIRECTION INPUT ;
    USE SIGNAL ;
    PORT
      LAYER M4 ;
        RECT  0 24.828 0.192 24.852 ;
    END
  END rsp_data[99]
  PIN rsp_data[9]
    DIRECTION INPUT ;
    USE SIGNAL ;
    PORT
      LAYER M4 ;
        RECT  0 5.148 0.192 5.172 ;
    END
  END rsp_data[9]
  PIN rst_n[0]
    DIRECTION INPUT ;
    USE SIGNAL ;
    PORT
      LAYER M5 ;
        RECT  108.396 86.304 108.42 86.496 ;
    END
  END rst_n[0]
  PIN si[0]
    DIRECTION INPUT ;
    USE SIGNAL ;
    PORT
      LAYER M4 ;
        RECT  243.456 2.316 243.648 2.34 ;
    END
  END si[0]
  PIN si[10]
    DIRECTION INPUT ;
    USE SIGNAL ;
    PORT
      LAYER M4 ;
        RECT  243.456 8.556 243.648 8.58 ;
    END
  END si[10]
  PIN si[11]
    DIRECTION INPUT ;
    USE SIGNAL ;
    PORT
      LAYER M4 ;
        RECT  243.456 9.228 243.648 9.252 ;
    END
  END si[11]
  PIN si[12]
    DIRECTION INPUT ;
    USE SIGNAL ;
    PORT
      LAYER M4 ;
        RECT  243.456 9.852 243.648 9.876 ;
    END
  END si[12]
  PIN si[13]
    DIRECTION INPUT ;
    USE SIGNAL ;
    PORT
      LAYER M4 ;
        RECT  243.456 10.476 243.648 10.5 ;
    END
  END si[13]
  PIN si[14]
    DIRECTION INPUT ;
    USE SIGNAL ;
    PORT
      LAYER M4 ;
        RECT  243.456 11.1 243.648 11.124 ;
    END
  END si[14]
  PIN si[1]
    DIRECTION INPUT ;
    USE SIGNAL ;
    PORT
      LAYER M4 ;
        RECT  243.456 2.94 243.648 2.964 ;
    END
  END si[1]
  PIN si[2]
    DIRECTION INPUT ;
    USE SIGNAL ;
    PORT
      LAYER M4 ;
        RECT  243.456 3.564 243.648 3.588 ;
    END
  END si[2]
  PIN si[3]
    DIRECTION INPUT ;
    USE SIGNAL ;
    PORT
      LAYER M4 ;
        RECT  243.456 4.188 243.648 4.212 ;
    END
  END si[3]
  PIN si[4]
    DIRECTION INPUT ;
    USE SIGNAL ;
    PORT
      LAYER M4 ;
        RECT  243.456 4.812 243.648 4.836 ;
    END
  END si[4]
  PIN si[5]
    DIRECTION INPUT ;
    USE SIGNAL ;
    PORT
      LAYER M4 ;
        RECT  243.456 5.436 243.648 5.46 ;
    END
  END si[5]
  PIN si[6]
    DIRECTION INPUT ;
    USE SIGNAL ;
    PORT
      LAYER M4 ;
        RECT  243.456 6.06 243.648 6.084 ;
    END
  END si[6]
  PIN si[7]
    DIRECTION INPUT ;
    USE SIGNAL ;
    PORT
      LAYER M4 ;
        RECT  243.456 6.684 243.648 6.708 ;
    END
  END si[7]
  PIN si[8]
    DIRECTION INPUT ;
    USE SIGNAL ;
    PORT
      LAYER M4 ;
        RECT  243.456 7.308 243.648 7.332 ;
    END
  END si[8]
  PIN si[9]
    DIRECTION INPUT ;
    USE SIGNAL ;
    PORT
      LAYER M4 ;
        RECT  243.456 7.932 243.648 7.956 ;
    END
  END si[9]
  PIN si_283[283]
    DIRECTION INPUT ;
    USE SIGNAL ;
    PORT
      LAYER M4 ;
        RECT  243.456 11.724 243.648 11.748 ;
    END
  END si_283[283]
  PIN si_283[284]
    DIRECTION INPUT ;
    USE SIGNAL ;
    PORT
      LAYER M4 ;
        RECT  243.456 12.348 243.648 12.372 ;
    END
  END si_283[284]
  PIN si_283[285]
    DIRECTION INPUT ;
    USE SIGNAL ;
    PORT
      LAYER M4 ;
        RECT  243.456 12.972 243.648 12.996 ;
    END
  END si_283[285]
  PIN si_283[286]
    DIRECTION INPUT ;
    USE SIGNAL ;
    PORT
      LAYER M4 ;
        RECT  243.456 13.596 243.648 13.62 ;
    END
  END si_283[286]
  PIN si_283[287]
    DIRECTION INPUT ;
    USE SIGNAL ;
    PORT
      LAYER M4 ;
        RECT  243.456 14.22 243.648 14.244 ;
    END
  END si_283[287]
  PIN si_283[288]
    DIRECTION INPUT ;
    USE SIGNAL ;
    PORT
      LAYER M4 ;
        RECT  243.456 14.844 243.648 14.868 ;
    END
  END si_283[288]
  PIN si_283[289]
    DIRECTION INPUT ;
    USE SIGNAL ;
    PORT
      LAYER M4 ;
        RECT  243.456 15.468 243.648 15.492 ;
    END
  END si_283[289]
  PIN si_283[290]
    DIRECTION INPUT ;
    USE SIGNAL ;
    PORT
      LAYER M4 ;
        RECT  243.456 16.092 243.648 16.116 ;
    END
  END si_283[290]
  PIN si_283[291]
    DIRECTION INPUT ;
    USE SIGNAL ;
    PORT
      LAYER M4 ;
        RECT  243.456 16.716 243.648 16.74 ;
    END
  END si_283[291]
  PIN si_283[292]
    DIRECTION INPUT ;
    USE SIGNAL ;
    PORT
      LAYER M4 ;
        RECT  243.456 17.34 243.648 17.364 ;
    END
  END si_283[292]
  PIN si_283[293]
    DIRECTION INPUT ;
    USE SIGNAL ;
    PORT
      LAYER M4 ;
        RECT  243.456 18.012 243.648 18.036 ;
    END
  END si_283[293]
  PIN si_283[294]
    DIRECTION INPUT ;
    USE SIGNAL ;
    PORT
      LAYER M4 ;
        RECT  243.456 18.636 243.648 18.66 ;
    END
  END si_283[294]
  PIN si_283[295]
    DIRECTION INPUT ;
    USE SIGNAL ;
    PORT
      LAYER M4 ;
        RECT  243.456 19.26 243.648 19.284 ;
    END
  END si_283[295]
  PIN si_283[296]
    DIRECTION INPUT ;
    USE SIGNAL ;
    PORT
      LAYER M4 ;
        RECT  243.456 19.884 243.648 19.908 ;
    END
  END si_283[296]
  PIN si_283[297]
    DIRECTION INPUT ;
    USE SIGNAL ;
    PORT
      LAYER M4 ;
        RECT  243.456 20.508 243.648 20.532 ;
    END
  END si_283[297]
  PIN si_283[298]
    DIRECTION INPUT ;
    USE SIGNAL ;
    PORT
      LAYER M4 ;
        RECT  243.456 21.132 243.648 21.156 ;
    END
  END si_283[298]
  PIN si_283[299]
    DIRECTION INPUT ;
    USE SIGNAL ;
    PORT
      LAYER M4 ;
        RECT  243.456 21.756 243.648 21.78 ;
    END
  END si_283[299]
  PIN si_283[300]
    DIRECTION INPUT ;
    USE SIGNAL ;
    PORT
      LAYER M4 ;
        RECT  243.456 22.38 243.648 22.404 ;
    END
  END si_283[300]
  PIN si_283[301]
    DIRECTION INPUT ;
    USE SIGNAL ;
    PORT
      LAYER M4 ;
        RECT  243.456 23.004 243.648 23.028 ;
    END
  END si_283[301]
  PIN si_283[302]
    DIRECTION INPUT ;
    USE SIGNAL ;
    PORT
      LAYER M4 ;
        RECT  243.456 23.628 243.648 23.652 ;
    END
  END si_283[302]
  PIN si_283[303]
    DIRECTION INPUT ;
    USE SIGNAL ;
    PORT
      LAYER M4 ;
        RECT  243.456 24.252 243.648 24.276 ;
    END
  END si_283[303]
  PIN si_283[304]
    DIRECTION INPUT ;
    USE SIGNAL ;
    PORT
      LAYER M4 ;
        RECT  243.456 24.876 243.648 24.9 ;
    END
  END si_283[304]
  PIN si_283[305]
    DIRECTION INPUT ;
    USE SIGNAL ;
    PORT
      LAYER M4 ;
        RECT  243.456 25.5 243.648 25.524 ;
    END
  END si_283[305]
  PIN si_283[306]
    DIRECTION INPUT ;
    USE SIGNAL ;
    PORT
      LAYER M4 ;
        RECT  243.456 26.124 243.648 26.148 ;
    END
  END si_283[306]
  PIN si_283[307]
    DIRECTION INPUT ;
    USE SIGNAL ;
    PORT
      LAYER M4 ;
        RECT  243.456 26.796 243.648 26.82 ;
    END
  END si_283[307]
  PIN si_283[308]
    DIRECTION INPUT ;
    USE SIGNAL ;
    PORT
      LAYER M4 ;
        RECT  243.456 27.42 243.648 27.444 ;
    END
  END si_283[308]
  PIN si_283[309]
    DIRECTION INPUT ;
    USE SIGNAL ;
    PORT
      LAYER M4 ;
        RECT  243.456 28.044 243.648 28.068 ;
    END
  END si_283[309]
  PIN si_283[310]
    DIRECTION INPUT ;
    USE SIGNAL ;
    PORT
      LAYER M4 ;
        RECT  243.456 28.668 243.648 28.692 ;
    END
  END si_283[310]
  PIN si_283[311]
    DIRECTION INPUT ;
    USE SIGNAL ;
    PORT
      LAYER M4 ;
        RECT  243.456 29.292 243.648 29.316 ;
    END
  END si_283[311]
  PIN si_283[312]
    DIRECTION INPUT ;
    USE SIGNAL ;
    PORT
      LAYER M4 ;
        RECT  243.456 29.916 243.648 29.94 ;
    END
  END si_283[312]
  PIN si_283[313]
    DIRECTION INPUT ;
    USE SIGNAL ;
    PORT
      LAYER M4 ;
        RECT  243.456 30.54 243.648 30.564 ;
    END
  END si_283[313]
  PIN si_283[314]
    DIRECTION INPUT ;
    USE SIGNAL ;
    PORT
      LAYER M4 ;
        RECT  243.456 31.164 243.648 31.188 ;
    END
  END si_283[314]
  PIN si_283[315]
    DIRECTION INPUT ;
    USE SIGNAL ;
    PORT
      LAYER M4 ;
        RECT  243.456 31.788 243.648 31.812 ;
    END
  END si_283[315]
  PIN si_283[316]
    DIRECTION INPUT ;
    USE SIGNAL ;
    PORT
      LAYER M4 ;
        RECT  243.456 32.412 243.648 32.436 ;
    END
  END si_283[316]
  PIN si_283[317]
    DIRECTION INPUT ;
    USE SIGNAL ;
    PORT
      LAYER M4 ;
        RECT  243.456 33.036 243.648 33.06 ;
    END
  END si_283[317]
  PIN si_283[318]
    DIRECTION INPUT ;
    USE SIGNAL ;
    PORT
      LAYER M4 ;
        RECT  243.456 33.66 243.648 33.684 ;
    END
  END si_283[318]
  PIN si_283[319]
    DIRECTION INPUT ;
    USE SIGNAL ;
    PORT
      LAYER M4 ;
        RECT  243.456 34.284 243.648 34.308 ;
    END
  END si_283[319]
  PIN si_283[320]
    DIRECTION INPUT ;
    USE SIGNAL ;
    PORT
      LAYER M4 ;
        RECT  243.456 34.956 243.648 34.98 ;
    END
  END si_283[320]
  PIN si_283[321]
    DIRECTION INPUT ;
    USE SIGNAL ;
    PORT
      LAYER M4 ;
        RECT  243.456 35.58 243.648 35.604 ;
    END
  END si_283[321]
  PIN si_283[322]
    DIRECTION INPUT ;
    USE SIGNAL ;
    PORT
      LAYER M4 ;
        RECT  243.456 36.204 243.648 36.228 ;
    END
  END si_283[322]
  PIN si_283[323]
    DIRECTION INPUT ;
    USE SIGNAL ;
    PORT
      LAYER M4 ;
        RECT  243.456 36.828 243.648 36.852 ;
    END
  END si_283[323]
  PIN si_283[324]
    DIRECTION INPUT ;
    USE SIGNAL ;
    PORT
      LAYER M4 ;
        RECT  243.456 37.452 243.648 37.476 ;
    END
  END si_283[324]
  PIN si_283[325]
    DIRECTION INPUT ;
    USE SIGNAL ;
    PORT
      LAYER M4 ;
        RECT  243.456 38.076 243.648 38.1 ;
    END
  END si_283[325]
  PIN si_283[326]
    DIRECTION INPUT ;
    USE SIGNAL ;
    PORT
      LAYER M4 ;
        RECT  243.456 38.7 243.648 38.724 ;
    END
  END si_283[326]
  PIN si_283[327]
    DIRECTION INPUT ;
    USE SIGNAL ;
    PORT
      LAYER M4 ;
        RECT  243.456 39.324 243.648 39.348 ;
    END
  END si_283[327]
  PIN si_283[328]
    DIRECTION INPUT ;
    USE SIGNAL ;
    PORT
      LAYER M4 ;
        RECT  243.456 39.948 243.648 39.972 ;
    END
  END si_283[328]
  PIN si_283[329]
    DIRECTION INPUT ;
    USE SIGNAL ;
    PORT
      LAYER M4 ;
        RECT  243.456 40.572 243.648 40.596 ;
    END
  END si_283[329]
  PIN si_283[330]
    DIRECTION INPUT ;
    USE SIGNAL ;
    PORT
      LAYER M4 ;
        RECT  243.456 41.196 243.648 41.22 ;
    END
  END si_283[330]
  PIN si_283[331]
    DIRECTION INPUT ;
    USE SIGNAL ;
    PORT
      LAYER M4 ;
        RECT  243.456 41.82 243.648 41.844 ;
    END
  END si_283[331]
  PIN si_283[332]
    DIRECTION INPUT ;
    USE SIGNAL ;
    PORT
      LAYER M4 ;
        RECT  243.456 42.444 243.648 42.468 ;
    END
  END si_283[332]
  PIN si_283[333]
    DIRECTION INPUT ;
    USE SIGNAL ;
    PORT
      LAYER M4 ;
        RECT  243.456 43.068 243.648 43.092 ;
    END
  END si_283[333]
  PIN si_283[334]
    DIRECTION INPUT ;
    USE SIGNAL ;
    PORT
      LAYER M4 ;
        RECT  243.456 43.74 243.648 43.764 ;
    END
  END si_283[334]
  PIN si_283[335]
    DIRECTION INPUT ;
    USE SIGNAL ;
    PORT
      LAYER M4 ;
        RECT  243.456 44.364 243.648 44.388 ;
    END
  END si_283[335]
  PIN si_283[336]
    DIRECTION INPUT ;
    USE SIGNAL ;
    PORT
      LAYER M4 ;
        RECT  243.456 44.988 243.648 45.012 ;
    END
  END si_283[336]
  PIN si_283[337]
    DIRECTION INPUT ;
    USE SIGNAL ;
    PORT
      LAYER M4 ;
        RECT  243.456 45.612 243.648 45.636 ;
    END
  END si_283[337]
  PIN si_283[338]
    DIRECTION INPUT ;
    USE SIGNAL ;
    PORT
      LAYER M4 ;
        RECT  243.456 46.236 243.648 46.26 ;
    END
  END si_283[338]
  PIN si_283[339]
    DIRECTION INPUT ;
    USE SIGNAL ;
    PORT
      LAYER M4 ;
        RECT  243.456 46.86 243.648 46.884 ;
    END
  END si_283[339]
  PIN si_283[340]
    DIRECTION INPUT ;
    USE SIGNAL ;
    PORT
      LAYER M4 ;
        RECT  243.456 47.484 243.648 47.508 ;
    END
  END si_283[340]
  PIN si_283[341]
    DIRECTION INPUT ;
    USE SIGNAL ;
    PORT
      LAYER M4 ;
        RECT  243.456 48.108 243.648 48.132 ;
    END
  END si_283[341]
  PIN si_283[342]
    DIRECTION INPUT ;
    USE SIGNAL ;
    PORT
      LAYER M4 ;
        RECT  243.456 48.732 243.648 48.756 ;
    END
  END si_283[342]
  PIN si_283[343]
    DIRECTION INPUT ;
    USE SIGNAL ;
    PORT
      LAYER M4 ;
        RECT  243.456 49.356 243.648 49.38 ;
    END
  END si_283[343]
  PIN si_283[344]
    DIRECTION INPUT ;
    USE SIGNAL ;
    PORT
      LAYER M4 ;
        RECT  243.456 49.98 243.648 50.004 ;
    END
  END si_283[344]
  PIN si_283[345]
    DIRECTION INPUT ;
    USE SIGNAL ;
    PORT
      LAYER M4 ;
        RECT  243.456 50.604 243.648 50.628 ;
    END
  END si_283[345]
  PIN si_283[346]
    DIRECTION INPUT ;
    USE SIGNAL ;
    PORT
      LAYER M4 ;
        RECT  243.456 51.228 243.648 51.252 ;
    END
  END si_283[346]
  PIN si_283[347]
    DIRECTION INPUT ;
    USE SIGNAL ;
    PORT
      LAYER M4 ;
        RECT  243.456 51.852 243.648 51.876 ;
    END
  END si_283[347]
  PIN si_283[348]
    DIRECTION INPUT ;
    USE SIGNAL ;
    PORT
      LAYER M4 ;
        RECT  243.456 52.524 243.648 52.548 ;
    END
  END si_283[348]
  PIN si_283[349]
    DIRECTION INPUT ;
    USE SIGNAL ;
    PORT
      LAYER M4 ;
        RECT  243.456 53.148 243.648 53.172 ;
    END
  END si_283[349]
  PIN si_283[350]
    DIRECTION INPUT ;
    USE SIGNAL ;
    PORT
      LAYER M4 ;
        RECT  243.456 53.772 243.648 53.796 ;
    END
  END si_283[350]
  PIN si_283[351]
    DIRECTION INPUT ;
    USE SIGNAL ;
    PORT
      LAYER M4 ;
        RECT  243.456 54.396 243.648 54.42 ;
    END
  END si_283[351]
  PIN si_283[352]
    DIRECTION INPUT ;
    USE SIGNAL ;
    PORT
      LAYER M4 ;
        RECT  243.456 55.02 243.648 55.044 ;
    END
  END si_283[352]
  PIN si_283[353]
    DIRECTION INPUT ;
    USE SIGNAL ;
    PORT
      LAYER M4 ;
        RECT  243.456 55.644 243.648 55.668 ;
    END
  END si_283[353]
  PIN si_283[354]
    DIRECTION INPUT ;
    USE SIGNAL ;
    PORT
      LAYER M4 ;
        RECT  243.456 56.268 243.648 56.292 ;
    END
  END si_283[354]
  PIN si_283[355]
    DIRECTION INPUT ;
    USE SIGNAL ;
    PORT
      LAYER M4 ;
        RECT  243.456 56.892 243.648 56.916 ;
    END
  END si_283[355]
  PIN si_283[356]
    DIRECTION INPUT ;
    USE SIGNAL ;
    PORT
      LAYER M4 ;
        RECT  243.456 57.516 243.648 57.54 ;
    END
  END si_283[356]
  PIN si_283[357]
    DIRECTION INPUT ;
    USE SIGNAL ;
    PORT
      LAYER M4 ;
        RECT  243.456 58.14 243.648 58.164 ;
    END
  END si_283[357]
  PIN si_283[358]
    DIRECTION INPUT ;
    USE SIGNAL ;
    PORT
      LAYER M4 ;
        RECT  243.456 58.764 243.648 58.788 ;
    END
  END si_283[358]
  PIN si_283[359]
    DIRECTION INPUT ;
    USE SIGNAL ;
    PORT
      LAYER M4 ;
        RECT  243.456 59.388 243.648 59.412 ;
    END
  END si_283[359]
  PIN si_283[360]
    DIRECTION INPUT ;
    USE SIGNAL ;
    PORT
      LAYER M4 ;
        RECT  243.456 60.012 243.648 60.036 ;
    END
  END si_283[360]
  PIN si_283[361]
    DIRECTION INPUT ;
    USE SIGNAL ;
    PORT
      LAYER M4 ;
        RECT  243.456 60.684 243.648 60.708 ;
    END
  END si_283[361]
  PIN si_283[362]
    DIRECTION INPUT ;
    USE SIGNAL ;
    PORT
      LAYER M4 ;
        RECT  243.456 61.308 243.648 61.332 ;
    END
  END si_283[362]
  PIN si_283[363]
    DIRECTION INPUT ;
    USE SIGNAL ;
    PORT
      LAYER M4 ;
        RECT  243.456 61.932 243.648 61.956 ;
    END
  END si_283[363]
  PIN si_283[364]
    DIRECTION INPUT ;
    USE SIGNAL ;
    PORT
      LAYER M4 ;
        RECT  243.456 62.556 243.648 62.58 ;
    END
  END si_283[364]
  PIN si_283[365]
    DIRECTION INPUT ;
    USE SIGNAL ;
    PORT
      LAYER M4 ;
        RECT  243.456 63.18 243.648 63.204 ;
    END
  END si_283[365]
  PIN si_283[366]
    DIRECTION INPUT ;
    USE SIGNAL ;
    PORT
      LAYER M4 ;
        RECT  243.456 63.804 243.648 63.828 ;
    END
  END si_283[366]
  PIN si_283[367]
    DIRECTION INPUT ;
    USE SIGNAL ;
    PORT
      LAYER M4 ;
        RECT  243.456 64.428 243.648 64.452 ;
    END
  END si_283[367]
  PIN si_283[368]
    DIRECTION INPUT ;
    USE SIGNAL ;
    PORT
      LAYER M4 ;
        RECT  243.456 65.052 243.648 65.076 ;
    END
  END si_283[368]
  PIN si_283[369]
    DIRECTION INPUT ;
    USE SIGNAL ;
    PORT
      LAYER M4 ;
        RECT  243.456 65.676 243.648 65.7 ;
    END
  END si_283[369]
  PIN si_283[370]
    DIRECTION INPUT ;
    USE SIGNAL ;
    PORT
      LAYER M4 ;
        RECT  243.456 66.3 243.648 66.324 ;
    END
  END si_283[370]
  PIN si_283[371]
    DIRECTION INPUT ;
    USE SIGNAL ;
    PORT
      LAYER M4 ;
        RECT  243.456 66.924 243.648 66.948 ;
    END
  END si_283[371]
  PIN si_283[372]
    DIRECTION INPUT ;
    USE SIGNAL ;
    PORT
      LAYER M4 ;
        RECT  243.456 67.548 243.648 67.572 ;
    END
  END si_283[372]
  PIN si_283[373]
    DIRECTION INPUT ;
    USE SIGNAL ;
    PORT
      LAYER M4 ;
        RECT  243.456 68.172 243.648 68.196 ;
    END
  END si_283[373]
  PIN si_283[374]
    DIRECTION INPUT ;
    USE SIGNAL ;
    PORT
      LAYER M4 ;
        RECT  243.456 68.796 243.648 68.82 ;
    END
  END si_283[374]
  PIN si_283[375]
    DIRECTION INPUT ;
    USE SIGNAL ;
    PORT
      LAYER M4 ;
        RECT  243.456 69.468 243.648 69.492 ;
    END
  END si_283[375]
  PIN si_283[376]
    DIRECTION INPUT ;
    USE SIGNAL ;
    PORT
      LAYER M4 ;
        RECT  243.456 70.092 243.648 70.116 ;
    END
  END si_283[376]
  PIN si_283[377]
    DIRECTION INPUT ;
    USE SIGNAL ;
    PORT
      LAYER M4 ;
        RECT  243.456 70.716 243.648 70.74 ;
    END
  END si_283[377]
  PIN si_283[378]
    DIRECTION INPUT ;
    USE SIGNAL ;
    PORT
      LAYER M4 ;
        RECT  243.456 71.34 243.648 71.364 ;
    END
  END si_283[378]
  PIN si_283[379]
    DIRECTION INPUT ;
    USE SIGNAL ;
    PORT
      LAYER M4 ;
        RECT  243.456 71.964 243.648 71.988 ;
    END
  END si_283[379]
  PIN si_283[380]
    DIRECTION INPUT ;
    USE SIGNAL ;
    PORT
      LAYER M4 ;
        RECT  243.456 72.588 243.648 72.612 ;
    END
  END si_283[380]
  PIN si_283[381]
    DIRECTION INPUT ;
    USE SIGNAL ;
    PORT
      LAYER M4 ;
        RECT  243.456 73.212 243.648 73.236 ;
    END
  END si_283[381]
  PIN si_283[382]
    DIRECTION INPUT ;
    USE SIGNAL ;
    PORT
      LAYER M4 ;
        RECT  243.456 73.836 243.648 73.86 ;
    END
  END si_283[382]
  PIN si_283[383]
    DIRECTION INPUT ;
    USE SIGNAL ;
    PORT
      LAYER M4 ;
        RECT  243.456 74.46 243.648 74.484 ;
    END
  END si_283[383]
  PIN si_283[384]
    DIRECTION INPUT ;
    USE SIGNAL ;
    PORT
      LAYER M4 ;
        RECT  243.456 75.084 243.648 75.108 ;
    END
  END si_283[384]
  PIN si_283[385]
    DIRECTION INPUT ;
    USE SIGNAL ;
    PORT
      LAYER M4 ;
        RECT  243.456 75.708 243.648 75.732 ;
    END
  END si_283[385]
  PIN si_283[386]
    DIRECTION INPUT ;
    USE SIGNAL ;
    PORT
      LAYER M4 ;
        RECT  243.456 76.332 243.648 76.356 ;
    END
  END si_283[386]
  PIN si_283[387]
    DIRECTION INPUT ;
    USE SIGNAL ;
    PORT
      LAYER M4 ;
        RECT  243.456 76.956 243.648 76.98 ;
    END
  END si_283[387]
  PIN si_283[388]
    DIRECTION INPUT ;
    USE SIGNAL ;
    PORT
      LAYER M4 ;
        RECT  243.456 77.58 243.648 77.604 ;
    END
  END si_283[388]
  PIN si_283[389]
    DIRECTION INPUT ;
    USE SIGNAL ;
    PORT
      LAYER M4 ;
        RECT  243.456 78.252 243.648 78.276 ;
    END
  END si_283[389]
  PIN si_283[390]
    DIRECTION INPUT ;
    USE SIGNAL ;
    PORT
      LAYER M4 ;
        RECT  243.456 78.876 243.648 78.9 ;
    END
  END si_283[390]
  PIN si_283[391]
    DIRECTION INPUT ;
    USE SIGNAL ;
    PORT
      LAYER M4 ;
        RECT  243.456 79.5 243.648 79.524 ;
    END
  END si_283[391]
  PIN si_283[392]
    DIRECTION INPUT ;
    USE SIGNAL ;
    PORT
      LAYER M4 ;
        RECT  243.456 80.124 243.648 80.148 ;
    END
  END si_283[392]
  PIN si_283[393]
    DIRECTION INPUT ;
    USE SIGNAL ;
    PORT
      LAYER M4 ;
        RECT  243.456 80.748 243.648 80.772 ;
    END
  END si_283[393]
  PIN si_283[394]
    DIRECTION INPUT ;
    USE SIGNAL ;
    PORT
      LAYER M4 ;
        RECT  243.456 81.372 243.648 81.396 ;
    END
  END si_283[394]
  PIN si_283[395]
    DIRECTION INPUT ;
    USE SIGNAL ;
    PORT
      LAYER M4 ;
        RECT  243.456 81.996 243.648 82.02 ;
    END
  END si_283[395]
  PIN si_283[396]
    DIRECTION INPUT ;
    USE SIGNAL ;
    PORT
      LAYER M4 ;
        RECT  243.456 82.62 243.648 82.644 ;
    END
  END si_283[396]
  PIN si_283[397]
    DIRECTION INPUT ;
    USE SIGNAL ;
    PORT
      LAYER M4 ;
        RECT  243.456 83.244 243.648 83.268 ;
    END
  END si_283[397]
  PIN si_283[398]
    DIRECTION INPUT ;
    USE SIGNAL ;
    PORT
      LAYER M4 ;
        RECT  243.456 83.868 243.648 83.892 ;
    END
  END si_283[398]
  PIN si_283[399]
    DIRECTION INPUT ;
    USE SIGNAL ;
    PORT
      LAYER M4 ;
        RECT  243.456 84.492 243.648 84.516 ;
    END
  END si_283[399]
  PIN si_283[400]
    DIRECTION INPUT ;
    USE SIGNAL ;
    PORT
      LAYER M4 ;
        RECT  243.456 85.116 243.648 85.14 ;
    END
  END si_283[400]
  PIN si_283[401]
    DIRECTION INPUT ;
    USE SIGNAL ;
    PORT
      LAYER M4 ;
        RECT  243.456 85.74 243.648 85.764 ;
    END
  END si_283[401]
  PIN si_283[402]
    DIRECTION INPUT ;
    USE SIGNAL ;
    PORT
      LAYER M4 ;
        RECT  243.456 86.412 243.648 86.436 ;
    END
  END si_283[402]
  PIN si_283[403]
    DIRECTION INPUT ;
    USE SIGNAL ;
    PORT
      LAYER M4 ;
        RECT  243.456 87.036 243.648 87.06 ;
    END
  END si_283[403]
  PIN si_283[404]
    DIRECTION INPUT ;
    USE SIGNAL ;
    PORT
      LAYER M4 ;
        RECT  243.456 87.66 243.648 87.684 ;
    END
  END si_283[404]
  PIN si_283[405]
    DIRECTION INPUT ;
    USE SIGNAL ;
    PORT
      LAYER M4 ;
        RECT  243.456 88.284 243.648 88.308 ;
    END
  END si_283[405]
  PIN si_283[406]
    DIRECTION INPUT ;
    USE SIGNAL ;
    PORT
      LAYER M4 ;
        RECT  243.456 88.908 243.648 88.932 ;
    END
  END si_283[406]
  PIN si_283[407]
    DIRECTION INPUT ;
    USE SIGNAL ;
    PORT
      LAYER M4 ;
        RECT  243.456 89.532 243.648 89.556 ;
    END
  END si_283[407]
  PIN si_283[408]
    DIRECTION INPUT ;
    USE SIGNAL ;
    PORT
      LAYER M4 ;
        RECT  243.456 90.156 243.648 90.18 ;
    END
  END si_283[408]
  PIN si_283[409]
    DIRECTION INPUT ;
    USE SIGNAL ;
    PORT
      LAYER M4 ;
        RECT  243.456 90.78 243.648 90.804 ;
    END
  END si_283[409]
  PIN si_283[410]
    DIRECTION INPUT ;
    USE SIGNAL ;
    PORT
      LAYER M4 ;
        RECT  243.456 91.404 243.648 91.428 ;
    END
  END si_283[410]
  PIN si_283[411]
    DIRECTION INPUT ;
    USE SIGNAL ;
    PORT
      LAYER M4 ;
        RECT  243.456 92.028 243.648 92.052 ;
    END
  END si_283[411]
  PIN si_283[412]
    DIRECTION INPUT ;
    USE SIGNAL ;
    PORT
      LAYER M4 ;
        RECT  243.456 92.652 243.648 92.676 ;
    END
  END si_283[412]
  PIN si_283[413]
    DIRECTION INPUT ;
    USE SIGNAL ;
    PORT
      LAYER M4 ;
        RECT  243.456 93.276 243.648 93.3 ;
    END
  END si_283[413]
  PIN si_283[414]
    DIRECTION INPUT ;
    USE SIGNAL ;
    PORT
      LAYER M4 ;
        RECT  243.456 93.9 243.648 93.924 ;
    END
  END si_283[414]
  PIN si_283[415]
    DIRECTION INPUT ;
    USE SIGNAL ;
    PORT
      LAYER M4 ;
        RECT  243.456 94.524 243.648 94.548 ;
    END
  END si_283[415]
  PIN si_283[416]
    DIRECTION INPUT ;
    USE SIGNAL ;
    PORT
      LAYER M4 ;
        RECT  243.456 95.196 243.648 95.22 ;
    END
  END si_283[416]
  PIN si_283[417]
    DIRECTION INPUT ;
    USE SIGNAL ;
    PORT
      LAYER M4 ;
        RECT  243.456 95.82 243.648 95.844 ;
    END
  END si_283[417]
  PIN si_283[418]
    DIRECTION INPUT ;
    USE SIGNAL ;
    PORT
      LAYER M4 ;
        RECT  243.456 96.444 243.648 96.468 ;
    END
  END si_283[418]
  PIN si_283[419]
    DIRECTION INPUT ;
    USE SIGNAL ;
    PORT
      LAYER M4 ;
        RECT  243.456 97.068 243.648 97.092 ;
    END
  END si_283[419]
  PIN si_283[420]
    DIRECTION INPUT ;
    USE SIGNAL ;
    PORT
      LAYER M4 ;
        RECT  243.456 97.692 243.648 97.716 ;
    END
  END si_283[420]
  PIN si_283[421]
    DIRECTION INPUT ;
    USE SIGNAL ;
    PORT
      LAYER M4 ;
        RECT  243.456 98.316 243.648 98.34 ;
    END
  END si_283[421]
  PIN si_283[422]
    DIRECTION INPUT ;
    USE SIGNAL ;
    PORT
      LAYER M4 ;
        RECT  243.456 98.94 243.648 98.964 ;
    END
  END si_283[422]
  PIN si_283[423]
    DIRECTION INPUT ;
    USE SIGNAL ;
    PORT
      LAYER M4 ;
        RECT  243.456 99.564 243.648 99.588 ;
    END
  END si_283[423]
  PIN si_283[424]
    DIRECTION INPUT ;
    USE SIGNAL ;
    PORT
      LAYER M4 ;
        RECT  243.456 100.188 243.648 100.212 ;
    END
  END si_283[424]
  PIN si_283[425]
    DIRECTION INPUT ;
    USE SIGNAL ;
    PORT
      LAYER M4 ;
        RECT  243.456 100.812 243.648 100.836 ;
    END
  END si_283[425]
  PIN si_283[426]
    DIRECTION INPUT ;
    USE SIGNAL ;
    PORT
      LAYER M4 ;
        RECT  243.456 101.436 243.648 101.46 ;
    END
  END si_283[426]
  PIN si_283[427]
    DIRECTION INPUT ;
    USE SIGNAL ;
    PORT
      LAYER M4 ;
        RECT  243.456 102.06 243.648 102.084 ;
    END
  END si_283[427]
  PIN si_283[428]
    DIRECTION INPUT ;
    USE SIGNAL ;
    PORT
      LAYER M4 ;
        RECT  243.456 102.684 243.648 102.708 ;
    END
  END si_283[428]
  PIN si_283[429]
    DIRECTION INPUT ;
    USE SIGNAL ;
    PORT
      LAYER M4 ;
        RECT  243.456 103.308 243.648 103.332 ;
    END
  END si_283[429]
  PIN si_283[430]
    DIRECTION INPUT ;
    USE SIGNAL ;
    PORT
      LAYER M4 ;
        RECT  243.456 103.98 243.648 104.004 ;
    END
  END si_283[430]
  PIN si_283[431]
    DIRECTION INPUT ;
    USE SIGNAL ;
    PORT
      LAYER M4 ;
        RECT  243.456 104.604 243.648 104.628 ;
    END
  END si_283[431]
  PIN si_283[432]
    DIRECTION INPUT ;
    USE SIGNAL ;
    PORT
      LAYER M4 ;
        RECT  243.456 105.228 243.648 105.252 ;
    END
  END si_283[432]
  PIN si_283[433]
    DIRECTION INPUT ;
    USE SIGNAL ;
    PORT
      LAYER M4 ;
        RECT  243.456 105.852 243.648 105.876 ;
    END
  END si_283[433]
  PIN si_283[434]
    DIRECTION INPUT ;
    USE SIGNAL ;
    PORT
      LAYER M4 ;
        RECT  243.456 106.476 243.648 106.5 ;
    END
  END si_283[434]
  PIN si_283[435]
    DIRECTION INPUT ;
    USE SIGNAL ;
    PORT
      LAYER M4 ;
        RECT  243.456 107.1 243.648 107.124 ;
    END
  END si_283[435]
  PIN si_283[436]
    DIRECTION INPUT ;
    USE SIGNAL ;
    PORT
      LAYER M4 ;
        RECT  243.456 107.724 243.648 107.748 ;
    END
  END si_283[436]
  PIN si_283[437]
    DIRECTION INPUT ;
    USE SIGNAL ;
    PORT
      LAYER M4 ;
        RECT  243.456 108.348 243.648 108.372 ;
    END
  END si_283[437]
  PIN si_283[438]
    DIRECTION INPUT ;
    USE SIGNAL ;
    PORT
      LAYER M4 ;
        RECT  243.456 108.972 243.648 108.996 ;
    END
  END si_283[438]
  PIN si_283[439]
    DIRECTION INPUT ;
    USE SIGNAL ;
    PORT
      LAYER M4 ;
        RECT  243.456 109.596 243.648 109.62 ;
    END
  END si_283[439]
  PIN si_283[440]
    DIRECTION INPUT ;
    USE SIGNAL ;
    PORT
      LAYER M4 ;
        RECT  243.456 110.22 243.648 110.244 ;
    END
  END si_283[440]
  PIN si_283[441]
    DIRECTION INPUT ;
    USE SIGNAL ;
    PORT
      LAYER M4 ;
        RECT  243.456 110.844 243.648 110.868 ;
    END
  END si_283[441]
  PIN si_283[442]
    DIRECTION INPUT ;
    USE SIGNAL ;
    PORT
      LAYER M4 ;
        RECT  243.456 111.468 243.648 111.492 ;
    END
  END si_283[442]
  PIN si_283[443]
    DIRECTION INPUT ;
    USE SIGNAL ;
    PORT
      LAYER M4 ;
        RECT  243.456 112.092 243.648 112.116 ;
    END
  END si_283[443]
  PIN si_283[444]
    DIRECTION INPUT ;
    USE SIGNAL ;
    PORT
      LAYER M4 ;
        RECT  243.456 112.764 243.648 112.788 ;
    END
  END si_283[444]
  PIN si_283[445]
    DIRECTION INPUT ;
    USE SIGNAL ;
    PORT
      LAYER M4 ;
        RECT  243.456 113.388 243.648 113.412 ;
    END
  END si_283[445]
  PIN si_283[446]
    DIRECTION INPUT ;
    USE SIGNAL ;
    PORT
      LAYER M4 ;
        RECT  243.456 114.012 243.648 114.036 ;
    END
  END si_283[446]
  PIN si_283[447]
    DIRECTION INPUT ;
    USE SIGNAL ;
    PORT
      LAYER M4 ;
        RECT  243.456 114.636 243.648 114.66 ;
    END
  END si_283[447]
  PIN si_283[448]
    DIRECTION INPUT ;
    USE SIGNAL ;
    PORT
      LAYER M4 ;
        RECT  243.456 115.26 243.648 115.284 ;
    END
  END si_283[448]
  PIN si_283[449]
    DIRECTION INPUT ;
    USE SIGNAL ;
    PORT
      LAYER M4 ;
        RECT  243.456 115.884 243.648 115.908 ;
    END
  END si_283[449]
  PIN si_283[450]
    DIRECTION INPUT ;
    USE SIGNAL ;
    PORT
      LAYER M4 ;
        RECT  243.456 116.508 243.648 116.532 ;
    END
  END si_283[450]
  PIN si_283[451]
    DIRECTION INPUT ;
    USE SIGNAL ;
    PORT
      LAYER M4 ;
        RECT  243.456 117.132 243.648 117.156 ;
    END
  END si_283[451]
  PIN si_283[452]
    DIRECTION INPUT ;
    USE SIGNAL ;
    PORT
      LAYER M4 ;
        RECT  243.456 117.756 243.648 117.78 ;
    END
  END si_283[452]
  PIN si_283[453]
    DIRECTION INPUT ;
    USE SIGNAL ;
    PORT
      LAYER M4 ;
        RECT  243.456 118.38 243.648 118.404 ;
    END
  END si_283[453]
  PIN si_283[454]
    DIRECTION INPUT ;
    USE SIGNAL ;
    PORT
      LAYER M4 ;
        RECT  243.456 119.004 243.648 119.028 ;
    END
  END si_283[454]
  PIN si_283[455]
    DIRECTION INPUT ;
    USE SIGNAL ;
    PORT
      LAYER M4 ;
        RECT  243.456 119.628 243.648 119.652 ;
    END
  END si_283[455]
  PIN si_283[456]
    DIRECTION INPUT ;
    USE SIGNAL ;
    PORT
      LAYER M4 ;
        RECT  243.456 120.252 243.648 120.276 ;
    END
  END si_283[456]
  PIN si_283[457]
    DIRECTION INPUT ;
    USE SIGNAL ;
    PORT
      LAYER M4 ;
        RECT  243.456 120.924 243.648 120.948 ;
    END
  END si_283[457]
  PIN si_283[458]
    DIRECTION INPUT ;
    USE SIGNAL ;
    PORT
      LAYER M4 ;
        RECT  243.456 121.548 243.648 121.572 ;
    END
  END si_283[458]
  PIN si_283[459]
    DIRECTION INPUT ;
    USE SIGNAL ;
    PORT
      LAYER M4 ;
        RECT  243.456 122.172 243.648 122.196 ;
    END
  END si_283[459]
  PIN si_283[460]
    DIRECTION INPUT ;
    USE SIGNAL ;
    PORT
      LAYER M4 ;
        RECT  243.456 122.796 243.648 122.82 ;
    END
  END si_283[460]
  PIN si_283[461]
    DIRECTION INPUT ;
    USE SIGNAL ;
    PORT
      LAYER M4 ;
        RECT  243.456 123.42 243.648 123.444 ;
    END
  END si_283[461]
  PIN si_283[462]
    DIRECTION INPUT ;
    USE SIGNAL ;
    PORT
      LAYER M4 ;
        RECT  243.456 124.044 243.648 124.068 ;
    END
  END si_283[462]
  PIN si_283[463]
    DIRECTION INPUT ;
    USE SIGNAL ;
    PORT
      LAYER M4 ;
        RECT  243.456 124.668 243.648 124.692 ;
    END
  END si_283[463]
  PIN si_283[464]
    DIRECTION INPUT ;
    USE SIGNAL ;
    PORT
      LAYER M4 ;
        RECT  243.456 125.292 243.648 125.316 ;
    END
  END si_283[464]
  PIN si_283[465]
    DIRECTION INPUT ;
    USE SIGNAL ;
    PORT
      LAYER M4 ;
        RECT  243.456 125.916 243.648 125.94 ;
    END
  END si_283[465]
  PIN si_283[466]
    DIRECTION INPUT ;
    USE SIGNAL ;
    PORT
      LAYER M4 ;
        RECT  243.456 126.54 243.648 126.564 ;
    END
  END si_283[466]
  PIN si_283[467]
    DIRECTION INPUT ;
    USE SIGNAL ;
    PORT
      LAYER M4 ;
        RECT  243.456 127.164 243.648 127.188 ;
    END
  END si_283[467]
  PIN si_283[468]
    DIRECTION INPUT ;
    USE SIGNAL ;
    PORT
      LAYER M4 ;
        RECT  243.456 127.788 243.648 127.812 ;
    END
  END si_283[468]
  PIN si_283[469]
    DIRECTION INPUT ;
    USE SIGNAL ;
    PORT
      LAYER M4 ;
        RECT  243.456 128.412 243.648 128.436 ;
    END
  END si_283[469]
  PIN si_283[470]
    DIRECTION INPUT ;
    USE SIGNAL ;
    PORT
      LAYER M4 ;
        RECT  243.456 129.036 243.648 129.06 ;
    END
  END si_283[470]
  PIN si_283[471]
    DIRECTION INPUT ;
    USE SIGNAL ;
    PORT
      LAYER M4 ;
        RECT  243.456 129.708 243.648 129.732 ;
    END
  END si_283[471]
  PIN si_283[472]
    DIRECTION INPUT ;
    USE SIGNAL ;
    PORT
      LAYER M4 ;
        RECT  243.456 130.332 243.648 130.356 ;
    END
  END si_283[472]
  PIN si_283[473]
    DIRECTION INPUT ;
    USE SIGNAL ;
    PORT
      LAYER M4 ;
        RECT  243.456 130.956 243.648 130.98 ;
    END
  END si_283[473]
  PIN si_283[474]
    DIRECTION INPUT ;
    USE SIGNAL ;
    PORT
      LAYER M4 ;
        RECT  243.456 131.58 243.648 131.604 ;
    END
  END si_283[474]
  PIN si_283[475]
    DIRECTION INPUT ;
    USE SIGNAL ;
    PORT
      LAYER M4 ;
        RECT  243.456 132.204 243.648 132.228 ;
    END
  END si_283[475]
  PIN si_283[476]
    DIRECTION INPUT ;
    USE SIGNAL ;
    PORT
      LAYER M4 ;
        RECT  243.456 132.828 243.648 132.852 ;
    END
  END si_283[476]
  PIN si_283[477]
    DIRECTION INPUT ;
    USE SIGNAL ;
    PORT
      LAYER M4 ;
        RECT  243.456 133.452 243.648 133.476 ;
    END
  END si_283[477]
  PIN si_283[478]
    DIRECTION INPUT ;
    USE SIGNAL ;
    PORT
      LAYER M4 ;
        RECT  243.456 134.076 243.648 134.1 ;
    END
  END si_283[478]
  PIN si_283[479]
    DIRECTION INPUT ;
    USE SIGNAL ;
    PORT
      LAYER M4 ;
        RECT  243.456 134.7 243.648 134.724 ;
    END
  END si_283[479]
  PIN si_283[480]
    DIRECTION INPUT ;
    USE SIGNAL ;
    PORT
      LAYER M4 ;
        RECT  243.456 135.324 243.648 135.348 ;
    END
  END si_283[480]
  PIN si_283[481]
    DIRECTION INPUT ;
    USE SIGNAL ;
    PORT
      LAYER M4 ;
        RECT  243.456 135.948 243.648 135.972 ;
    END
  END si_283[481]
  PIN si_283[482]
    DIRECTION INPUT ;
    USE SIGNAL ;
    PORT
      LAYER M4 ;
        RECT  243.456 136.572 243.648 136.596 ;
    END
  END si_283[482]
  PIN si_283[483]
    DIRECTION INPUT ;
    USE SIGNAL ;
    PORT
      LAYER M4 ;
        RECT  243.456 137.196 243.648 137.22 ;
    END
  END si_283[483]
  PIN si_283[484]
    DIRECTION INPUT ;
    USE SIGNAL ;
    PORT
      LAYER M4 ;
        RECT  243.456 137.82 243.648 137.844 ;
    END
  END si_283[484]
  PIN si_283[485]
    DIRECTION INPUT ;
    USE SIGNAL ;
    PORT
      LAYER M4 ;
        RECT  243.456 138.492 243.648 138.516 ;
    END
  END si_283[485]
  PIN si_283[486]
    DIRECTION INPUT ;
    USE SIGNAL ;
    PORT
      LAYER M4 ;
        RECT  243.456 139.116 243.648 139.14 ;
    END
  END si_283[486]
  PIN si_283[487]
    DIRECTION INPUT ;
    USE SIGNAL ;
    PORT
      LAYER M4 ;
        RECT  243.456 139.74 243.648 139.764 ;
    END
  END si_283[487]
  PIN si_283[488]
    DIRECTION INPUT ;
    USE SIGNAL ;
    PORT
      LAYER M4 ;
        RECT  243.456 140.364 243.648 140.388 ;
    END
  END si_283[488]
  PIN si_283[489]
    DIRECTION INPUT ;
    USE SIGNAL ;
    PORT
      LAYER M4 ;
        RECT  243.456 140.988 243.648 141.012 ;
    END
  END si_283[489]
  PIN si_283[490]
    DIRECTION INPUT ;
    USE SIGNAL ;
    PORT
      LAYER M4 ;
        RECT  243.456 141.612 243.648 141.636 ;
    END
  END si_283[490]
  PIN si_283[491]
    DIRECTION INPUT ;
    USE SIGNAL ;
    PORT
      LAYER M4 ;
        RECT  243.456 142.236 243.648 142.26 ;
    END
  END si_283[491]
  PIN si_283[492]
    DIRECTION INPUT ;
    USE SIGNAL ;
    PORT
      LAYER M4 ;
        RECT  243.456 142.86 243.648 142.884 ;
    END
  END si_283[492]
  PIN si_283[493]
    DIRECTION INPUT ;
    USE SIGNAL ;
    PORT
      LAYER M4 ;
        RECT  243.456 143.484 243.648 143.508 ;
    END
  END si_283[493]
  PIN si_283[494]
    DIRECTION INPUT ;
    USE SIGNAL ;
    PORT
      LAYER M4 ;
        RECT  243.456 144.108 243.648 144.132 ;
    END
  END si_283[494]
  PIN si_283[495]
    DIRECTION INPUT ;
    USE SIGNAL ;
    PORT
      LAYER M4 ;
        RECT  243.456 144.732 243.648 144.756 ;
    END
  END si_283[495]
  PIN si_283[496]
    DIRECTION INPUT ;
    USE SIGNAL ;
    PORT
      LAYER M4 ;
        RECT  243.456 145.356 243.648 145.38 ;
    END
  END si_283[496]
  PIN si_283[497]
    DIRECTION INPUT ;
    USE SIGNAL ;
    PORT
      LAYER M4 ;
        RECT  243.456 145.98 243.648 146.004 ;
    END
  END si_283[497]
  PIN si_283[498]
    DIRECTION INPUT ;
    USE SIGNAL ;
    PORT
      LAYER M4 ;
        RECT  243.456 146.652 243.648 146.676 ;
    END
  END si_283[498]
  PIN si_283[499]
    DIRECTION INPUT ;
    USE SIGNAL ;
    PORT
      LAYER M4 ;
        RECT  243.456 147.276 243.648 147.3 ;
    END
  END si_283[499]
  PIN si_283[500]
    DIRECTION INPUT ;
    USE SIGNAL ;
    PORT
      LAYER M4 ;
        RECT  243.456 147.9 243.648 147.924 ;
    END
  END si_283[500]
  PIN si_283[501]
    DIRECTION INPUT ;
    USE SIGNAL ;
    PORT
      LAYER M4 ;
        RECT  243.456 148.524 243.648 148.548 ;
    END
  END si_283[501]
  PIN si_283[502]
    DIRECTION INPUT ;
    USE SIGNAL ;
    PORT
      LAYER M4 ;
        RECT  243.456 149.148 243.648 149.172 ;
    END
  END si_283[502]
  PIN si_283[503]
    DIRECTION INPUT ;
    USE SIGNAL ;
    PORT
      LAYER M4 ;
        RECT  243.456 149.772 243.648 149.796 ;
    END
  END si_283[503]
  PIN si_283[504]
    DIRECTION INPUT ;
    USE SIGNAL ;
    PORT
      LAYER M4 ;
        RECT  243.456 150.396 243.648 150.42 ;
    END
  END si_283[504]
  PIN si_283[505]
    DIRECTION INPUT ;
    USE SIGNAL ;
    PORT
      LAYER M4 ;
        RECT  243.456 151.02 243.648 151.044 ;
    END
  END si_283[505]
  PIN si_283[506]
    DIRECTION INPUT ;
    USE SIGNAL ;
    PORT
      LAYER M4 ;
        RECT  243.456 151.644 243.648 151.668 ;
    END
  END si_283[506]
  PIN si_283[507]
    DIRECTION INPUT ;
    USE SIGNAL ;
    PORT
      LAYER M4 ;
        RECT  243.456 152.268 243.648 152.292 ;
    END
  END si_283[507]
  PIN si_283[508]
    DIRECTION INPUT ;
    USE SIGNAL ;
    PORT
      LAYER M4 ;
        RECT  243.456 152.892 243.648 152.916 ;
    END
  END si_283[508]
  PIN si_283[509]
    DIRECTION INPUT ;
    USE SIGNAL ;
    PORT
      LAYER M4 ;
        RECT  243.456 153.516 243.648 153.54 ;
    END
  END si_283[509]
  PIN si_283[510]
    DIRECTION INPUT ;
    USE SIGNAL ;
    PORT
      LAYER M4 ;
        RECT  243.456 154.14 243.648 154.164 ;
    END
  END si_283[510]
  PIN si_283[511]
    DIRECTION INPUT ;
    USE SIGNAL ;
    PORT
      LAYER M4 ;
        RECT  243.456 154.764 243.648 154.788 ;
    END
  END si_283[511]
  PIN si_283[512]
    DIRECTION INPUT ;
    USE SIGNAL ;
    PORT
      LAYER M4 ;
        RECT  243.456 155.436 243.648 155.46 ;
    END
  END si_283[512]
  PIN si_283[513]
    DIRECTION INPUT ;
    USE SIGNAL ;
    PORT
      LAYER M4 ;
        RECT  243.456 156.06 243.648 156.084 ;
    END
  END si_283[513]
  PIN si_283[514]
    DIRECTION INPUT ;
    USE SIGNAL ;
    PORT
      LAYER M4 ;
        RECT  243.456 156.684 243.648 156.708 ;
    END
  END si_283[514]
  PIN si_283[515]
    DIRECTION INPUT ;
    USE SIGNAL ;
    PORT
      LAYER M4 ;
        RECT  243.456 157.308 243.648 157.332 ;
    END
  END si_283[515]
  PIN si_283[516]
    DIRECTION INPUT ;
    USE SIGNAL ;
    PORT
      LAYER M4 ;
        RECT  243.456 157.932 243.648 157.956 ;
    END
  END si_283[516]
  PIN si_283[517]
    DIRECTION INPUT ;
    USE SIGNAL ;
    PORT
      LAYER M4 ;
        RECT  243.456 158.556 243.648 158.58 ;
    END
  END si_283[517]
  PIN si_283[518]
    DIRECTION INPUT ;
    USE SIGNAL ;
    PORT
      LAYER M4 ;
        RECT  243.456 159.18 243.648 159.204 ;
    END
  END si_283[518]
  PIN si_283[519]
    DIRECTION INPUT ;
    USE SIGNAL ;
    PORT
      LAYER M4 ;
        RECT  243.456 159.804 243.648 159.828 ;
    END
  END si_283[519]
  PIN si_283[520]
    DIRECTION INPUT ;
    USE SIGNAL ;
    PORT
      LAYER M4 ;
        RECT  243.456 160.428 243.648 160.452 ;
    END
  END si_283[520]
  PIN si_283[521]
    DIRECTION INPUT ;
    USE SIGNAL ;
    PORT
      LAYER M4 ;
        RECT  243.456 161.052 243.648 161.076 ;
    END
  END si_283[521]
  PIN si_283[522]
    DIRECTION INPUT ;
    USE SIGNAL ;
    PORT
      LAYER M4 ;
        RECT  243.456 161.676 243.648 161.7 ;
    END
  END si_283[522]
  PIN si_283[523]
    DIRECTION INPUT ;
    USE SIGNAL ;
    PORT
      LAYER M4 ;
        RECT  243.456 162.3 243.648 162.324 ;
    END
  END si_283[523]
  PIN si_283[524]
    DIRECTION INPUT ;
    USE SIGNAL ;
    PORT
      LAYER M4 ;
        RECT  243.456 162.924 243.648 162.948 ;
    END
  END si_283[524]
  PIN si_283[525]
    DIRECTION INPUT ;
    USE SIGNAL ;
    PORT
      LAYER M4 ;
        RECT  243.456 163.548 243.648 163.572 ;
    END
  END si_283[525]
  PIN si_283[526]
    DIRECTION INPUT ;
    USE SIGNAL ;
    PORT
      LAYER M4 ;
        RECT  243.456 164.22 243.648 164.244 ;
    END
  END si_283[526]
  PIN si_283[527]
    DIRECTION INPUT ;
    USE SIGNAL ;
    PORT
      LAYER M4 ;
        RECT  243.456 164.844 243.648 164.868 ;
    END
  END si_283[527]
  PIN si_283[528]
    DIRECTION INPUT ;
    USE SIGNAL ;
    PORT
      LAYER M4 ;
        RECT  243.456 165.468 243.648 165.492 ;
    END
  END si_283[528]
  PIN si_283[529]
    DIRECTION INPUT ;
    USE SIGNAL ;
    PORT
      LAYER M4 ;
        RECT  243.456 166.092 243.648 166.116 ;
    END
  END si_283[529]
  PIN si_283[530]
    DIRECTION INPUT ;
    USE SIGNAL ;
    PORT
      LAYER M4 ;
        RECT  243.456 166.716 243.648 166.74 ;
    END
  END si_283[530]
  PIN si_283[531]
    DIRECTION INPUT ;
    USE SIGNAL ;
    PORT
      LAYER M4 ;
        RECT  243.456 167.34 243.648 167.364 ;
    END
  END si_283[531]
  PIN si_283[532]
    DIRECTION INPUT ;
    USE SIGNAL ;
    PORT
      LAYER M4 ;
        RECT  243.456 167.964 243.648 167.988 ;
    END
  END si_283[532]
  PIN si_283[533]
    DIRECTION INPUT ;
    USE SIGNAL ;
    PORT
      LAYER M4 ;
        RECT  243.456 168.588 243.648 168.612 ;
    END
  END si_283[533]
  PIN si_283[534]
    DIRECTION INPUT ;
    USE SIGNAL ;
    PORT
      LAYER M4 ;
        RECT  243.456 169.212 243.648 169.236 ;
    END
  END si_283[534]
  PIN si_283[535]
    DIRECTION INPUT ;
    USE SIGNAL ;
    PORT
      LAYER M4 ;
        RECT  243.456 169.836 243.648 169.86 ;
    END
  END si_283[535]
  PIN si_283[536]
    DIRECTION INPUT ;
    USE SIGNAL ;
    PORT
      LAYER M4 ;
        RECT  243.456 170.46 243.648 170.484 ;
    END
  END si_283[536]
  PIN t0[0]
    DIRECTION OUTPUT ;
    USE SIGNAL ;
    PORT
      LAYER M5 ;
        RECT  2.124 0 2.148 0.192 ;
    END
  END t0[0]
  PIN t0[100]
    DIRECTION OUTPUT ;
    USE SIGNAL ;
    PORT
      LAYER M5 ;
        RECT  25.356 0 25.38 0.192 ;
    END
  END t0[100]
  PIN t0[101]
    DIRECTION OUTPUT ;
    USE SIGNAL ;
    PORT
      LAYER M5 ;
        RECT  25.596 0 25.62 0.192 ;
    END
  END t0[101]
  PIN t0[102]
    DIRECTION OUTPUT ;
    USE SIGNAL ;
    PORT
      LAYER M5 ;
        RECT  25.836 0 25.86 0.192 ;
    END
  END t0[102]
  PIN t0[103]
    DIRECTION OUTPUT ;
    USE SIGNAL ;
    PORT
      LAYER M5 ;
        RECT  26.076 0 26.1 0.192 ;
    END
  END t0[103]
  PIN t0[104]
    DIRECTION OUTPUT ;
    USE SIGNAL ;
    PORT
      LAYER M5 ;
        RECT  26.316 0 26.34 0.192 ;
    END
  END t0[104]
  PIN t0[105]
    DIRECTION OUTPUT ;
    USE SIGNAL ;
    PORT
      LAYER M5 ;
        RECT  26.556 0 26.58 0.192 ;
    END
  END t0[105]
  PIN t0[106]
    DIRECTION OUTPUT ;
    USE SIGNAL ;
    PORT
      LAYER M5 ;
        RECT  26.748 0 26.772 0.192 ;
    END
  END t0[106]
  PIN t0[107]
    DIRECTION OUTPUT ;
    USE SIGNAL ;
    PORT
      LAYER M5 ;
        RECT  26.988 0 27.012 0.192 ;
    END
  END t0[107]
  PIN t0[108]
    DIRECTION OUTPUT ;
    USE SIGNAL ;
    PORT
      LAYER M5 ;
        RECT  27.228 0 27.252 0.192 ;
    END
  END t0[108]
  PIN t0[109]
    DIRECTION OUTPUT ;
    USE SIGNAL ;
    PORT
      LAYER M5 ;
        RECT  27.468 0 27.492 0.192 ;
    END
  END t0[109]
  PIN t0[10]
    DIRECTION OUTPUT ;
    USE SIGNAL ;
    PORT
      LAYER M5 ;
        RECT  4.428 0 4.452 0.192 ;
    END
  END t0[10]
  PIN t0[110]
    DIRECTION OUTPUT ;
    USE SIGNAL ;
    PORT
      LAYER M5 ;
        RECT  27.708 0 27.732 0.192 ;
    END
  END t0[110]
  PIN t0[111]
    DIRECTION OUTPUT ;
    USE SIGNAL ;
    PORT
      LAYER M5 ;
        RECT  27.948 0 27.972 0.192 ;
    END
  END t0[111]
  PIN t0[112]
    DIRECTION OUTPUT ;
    USE SIGNAL ;
    PORT
      LAYER M5 ;
        RECT  28.188 0 28.212 0.192 ;
    END
  END t0[112]
  PIN t0[113]
    DIRECTION OUTPUT ;
    USE SIGNAL ;
    PORT
      LAYER M5 ;
        RECT  28.38 0 28.404 0.192 ;
    END
  END t0[113]
  PIN t0[114]
    DIRECTION OUTPUT ;
    USE SIGNAL ;
    PORT
      LAYER M5 ;
        RECT  28.62 0 28.644 0.192 ;
    END
  END t0[114]
  PIN t0[115]
    DIRECTION OUTPUT ;
    USE SIGNAL ;
    PORT
      LAYER M5 ;
        RECT  28.86 0 28.884 0.192 ;
    END
  END t0[115]
  PIN t0[116]
    DIRECTION OUTPUT ;
    USE SIGNAL ;
    PORT
      LAYER M5 ;
        RECT  29.1 0 29.124 0.192 ;
    END
  END t0[116]
  PIN t0[117]
    DIRECTION OUTPUT ;
    USE SIGNAL ;
    PORT
      LAYER M5 ;
        RECT  29.34 0 29.364 0.192 ;
    END
  END t0[117]
  PIN t0[118]
    DIRECTION OUTPUT ;
    USE SIGNAL ;
    PORT
      LAYER M5 ;
        RECT  29.58 0 29.604 0.192 ;
    END
  END t0[118]
  PIN t0[119]
    DIRECTION OUTPUT ;
    USE SIGNAL ;
    PORT
      LAYER M5 ;
        RECT  29.82 0 29.844 0.192 ;
    END
  END t0[119]
  PIN t0[11]
    DIRECTION OUTPUT ;
    USE SIGNAL ;
    PORT
      LAYER M5 ;
        RECT  4.668 0 4.692 0.192 ;
    END
  END t0[11]
  PIN t0[120]
    DIRECTION OUTPUT ;
    USE SIGNAL ;
    PORT
      LAYER M5 ;
        RECT  30.012 0 30.036 0.192 ;
    END
  END t0[120]
  PIN t0[121]
    DIRECTION OUTPUT ;
    USE SIGNAL ;
    PORT
      LAYER M5 ;
        RECT  30.252 0 30.276 0.192 ;
    END
  END t0[121]
  PIN t0[122]
    DIRECTION OUTPUT ;
    USE SIGNAL ;
    PORT
      LAYER M5 ;
        RECT  30.492 0 30.516 0.192 ;
    END
  END t0[122]
  PIN t0[123]
    DIRECTION OUTPUT ;
    USE SIGNAL ;
    PORT
      LAYER M5 ;
        RECT  30.732 0 30.756 0.192 ;
    END
  END t0[123]
  PIN t0[124]
    DIRECTION OUTPUT ;
    USE SIGNAL ;
    PORT
      LAYER M5 ;
        RECT  30.972 0 30.996 0.192 ;
    END
  END t0[124]
  PIN t0[125]
    DIRECTION OUTPUT ;
    USE SIGNAL ;
    PORT
      LAYER M5 ;
        RECT  31.212 0 31.236 0.192 ;
    END
  END t0[125]
  PIN t0[126]
    DIRECTION OUTPUT ;
    USE SIGNAL ;
    PORT
      LAYER M5 ;
        RECT  31.404 0 31.428 0.192 ;
    END
  END t0[126]
  PIN t0[127]
    DIRECTION OUTPUT ;
    USE SIGNAL ;
    PORT
      LAYER M5 ;
        RECT  31.644 0 31.668 0.192 ;
    END
  END t0[127]
  PIN t0[128]
    DIRECTION OUTPUT ;
    USE SIGNAL ;
    PORT
      LAYER M5 ;
        RECT  31.884 0 31.908 0.192 ;
    END
  END t0[128]
  PIN t0[129]
    DIRECTION OUTPUT ;
    USE SIGNAL ;
    PORT
      LAYER M5 ;
        RECT  32.124 0 32.148 0.192 ;
    END
  END t0[129]
  PIN t0[12]
    DIRECTION OUTPUT ;
    USE SIGNAL ;
    PORT
      LAYER M5 ;
        RECT  4.908 0 4.932 0.192 ;
    END
  END t0[12]
  PIN t0[130]
    DIRECTION OUTPUT ;
    USE SIGNAL ;
    PORT
      LAYER M5 ;
        RECT  32.364 0 32.388 0.192 ;
    END
  END t0[130]
  PIN t0[131]
    DIRECTION OUTPUT ;
    USE SIGNAL ;
    PORT
      LAYER M5 ;
        RECT  32.604 0 32.628 0.192 ;
    END
  END t0[131]
  PIN t0[132]
    DIRECTION OUTPUT ;
    USE SIGNAL ;
    PORT
      LAYER M5 ;
        RECT  32.844 0 32.868 0.192 ;
    END
  END t0[132]
  PIN t0[133]
    DIRECTION OUTPUT ;
    USE SIGNAL ;
    PORT
      LAYER M5 ;
        RECT  33.036 0 33.06 0.192 ;
    END
  END t0[133]
  PIN t0[134]
    DIRECTION OUTPUT ;
    USE SIGNAL ;
    PORT
      LAYER M5 ;
        RECT  33.276 0 33.3 0.192 ;
    END
  END t0[134]
  PIN t0[135]
    DIRECTION OUTPUT ;
    USE SIGNAL ;
    PORT
      LAYER M5 ;
        RECT  33.516 0 33.54 0.192 ;
    END
  END t0[135]
  PIN t0[136]
    DIRECTION OUTPUT ;
    USE SIGNAL ;
    PORT
      LAYER M5 ;
        RECT  33.756 0 33.78 0.192 ;
    END
  END t0[136]
  PIN t0[137]
    DIRECTION OUTPUT ;
    USE SIGNAL ;
    PORT
      LAYER M5 ;
        RECT  33.996 0 34.02 0.192 ;
    END
  END t0[137]
  PIN t0[138]
    DIRECTION OUTPUT ;
    USE SIGNAL ;
    PORT
      LAYER M5 ;
        RECT  34.236 0 34.26 0.192 ;
    END
  END t0[138]
  PIN t0[139]
    DIRECTION OUTPUT ;
    USE SIGNAL ;
    PORT
      LAYER M5 ;
        RECT  34.428 0 34.452 0.192 ;
    END
  END t0[139]
  PIN t0[13]
    DIRECTION OUTPUT ;
    USE SIGNAL ;
    PORT
      LAYER M5 ;
        RECT  5.148 0 5.172 0.192 ;
    END
  END t0[13]
  PIN t0[140]
    DIRECTION OUTPUT ;
    USE SIGNAL ;
    PORT
      LAYER M5 ;
        RECT  34.668 0 34.692 0.192 ;
    END
  END t0[140]
  PIN t0[141]
    DIRECTION OUTPUT ;
    USE SIGNAL ;
    PORT
      LAYER M5 ;
        RECT  34.908 0 34.932 0.192 ;
    END
  END t0[141]
  PIN t0[142]
    DIRECTION OUTPUT ;
    USE SIGNAL ;
    PORT
      LAYER M5 ;
        RECT  35.148 0 35.172 0.192 ;
    END
  END t0[142]
  PIN t0[143]
    DIRECTION OUTPUT ;
    USE SIGNAL ;
    PORT
      LAYER M5 ;
        RECT  35.388 0 35.412 0.192 ;
    END
  END t0[143]
  PIN t0[144]
    DIRECTION OUTPUT ;
    USE SIGNAL ;
    PORT
      LAYER M5 ;
        RECT  35.628 0 35.652 0.192 ;
    END
  END t0[144]
  PIN t0[145]
    DIRECTION OUTPUT ;
    USE SIGNAL ;
    PORT
      LAYER M5 ;
        RECT  35.868 0 35.892 0.192 ;
    END
  END t0[145]
  PIN t0[146]
    DIRECTION OUTPUT ;
    USE SIGNAL ;
    PORT
      LAYER M5 ;
        RECT  36.06 0 36.084 0.192 ;
    END
  END t0[146]
  PIN t0[147]
    DIRECTION OUTPUT ;
    USE SIGNAL ;
    PORT
      LAYER M5 ;
        RECT  36.3 0 36.324 0.192 ;
    END
  END t0[147]
  PIN t0[148]
    DIRECTION OUTPUT ;
    USE SIGNAL ;
    PORT
      LAYER M5 ;
        RECT  36.54 0 36.564 0.192 ;
    END
  END t0[148]
  PIN t0[149]
    DIRECTION OUTPUT ;
    USE SIGNAL ;
    PORT
      LAYER M5 ;
        RECT  36.78 0 36.804 0.192 ;
    END
  END t0[149]
  PIN t0[14]
    DIRECTION OUTPUT ;
    USE SIGNAL ;
    PORT
      LAYER M5 ;
        RECT  5.34 0 5.364 0.192 ;
    END
  END t0[14]
  PIN t0[150]
    DIRECTION OUTPUT ;
    USE SIGNAL ;
    PORT
      LAYER M5 ;
        RECT  37.02 0 37.044 0.192 ;
    END
  END t0[150]
  PIN t0[151]
    DIRECTION OUTPUT ;
    USE SIGNAL ;
    PORT
      LAYER M5 ;
        RECT  37.26 0 37.284 0.192 ;
    END
  END t0[151]
  PIN t0[152]
    DIRECTION OUTPUT ;
    USE SIGNAL ;
    PORT
      LAYER M5 ;
        RECT  37.5 0 37.524 0.192 ;
    END
  END t0[152]
  PIN t0[153]
    DIRECTION OUTPUT ;
    USE SIGNAL ;
    PORT
      LAYER M5 ;
        RECT  37.692 0 37.716 0.192 ;
    END
  END t0[153]
  PIN t0[154]
    DIRECTION OUTPUT ;
    USE SIGNAL ;
    PORT
      LAYER M5 ;
        RECT  37.932 0 37.956 0.192 ;
    END
  END t0[154]
  PIN t0[155]
    DIRECTION OUTPUT ;
    USE SIGNAL ;
    PORT
      LAYER M5 ;
        RECT  38.172 0 38.196 0.192 ;
    END
  END t0[155]
  PIN t0[156]
    DIRECTION OUTPUT ;
    USE SIGNAL ;
    PORT
      LAYER M5 ;
        RECT  38.412 0 38.436 0.192 ;
    END
  END t0[156]
  PIN t0[157]
    DIRECTION OUTPUT ;
    USE SIGNAL ;
    PORT
      LAYER M5 ;
        RECT  38.652 0 38.676 0.192 ;
    END
  END t0[157]
  PIN t0[158]
    DIRECTION OUTPUT ;
    USE SIGNAL ;
    PORT
      LAYER M5 ;
        RECT  38.892 0 38.916 0.192 ;
    END
  END t0[158]
  PIN t0[159]
    DIRECTION OUTPUT ;
    USE SIGNAL ;
    PORT
      LAYER M5 ;
        RECT  39.084 0 39.108 0.192 ;
    END
  END t0[159]
  PIN t0[15]
    DIRECTION OUTPUT ;
    USE SIGNAL ;
    PORT
      LAYER M5 ;
        RECT  5.58 0 5.604 0.192 ;
    END
  END t0[15]
  PIN t0[160]
    DIRECTION OUTPUT ;
    USE SIGNAL ;
    PORT
      LAYER M5 ;
        RECT  39.324 0 39.348 0.192 ;
    END
  END t0[160]
  PIN t0[161]
    DIRECTION OUTPUT ;
    USE SIGNAL ;
    PORT
      LAYER M5 ;
        RECT  39.564 0 39.588 0.192 ;
    END
  END t0[161]
  PIN t0[162]
    DIRECTION OUTPUT ;
    USE SIGNAL ;
    PORT
      LAYER M5 ;
        RECT  39.804 0 39.828 0.192 ;
    END
  END t0[162]
  PIN t0[163]
    DIRECTION OUTPUT ;
    USE SIGNAL ;
    PORT
      LAYER M5 ;
        RECT  40.044 0 40.068 0.192 ;
    END
  END t0[163]
  PIN t0[164]
    DIRECTION OUTPUT ;
    USE SIGNAL ;
    PORT
      LAYER M5 ;
        RECT  40.284 0 40.308 0.192 ;
    END
  END t0[164]
  PIN t0[165]
    DIRECTION OUTPUT ;
    USE SIGNAL ;
    PORT
      LAYER M5 ;
        RECT  40.524 0 40.548 0.192 ;
    END
  END t0[165]
  PIN t0[166]
    DIRECTION OUTPUT ;
    USE SIGNAL ;
    PORT
      LAYER M5 ;
        RECT  40.716 0 40.74 0.192 ;
    END
  END t0[166]
  PIN t0[167]
    DIRECTION OUTPUT ;
    USE SIGNAL ;
    PORT
      LAYER M5 ;
        RECT  40.956 0 40.98 0.192 ;
    END
  END t0[167]
  PIN t0[168]
    DIRECTION OUTPUT ;
    USE SIGNAL ;
    PORT
      LAYER M5 ;
        RECT  41.196 0 41.22 0.192 ;
    END
  END t0[168]
  PIN t0[169]
    DIRECTION OUTPUT ;
    USE SIGNAL ;
    PORT
      LAYER M5 ;
        RECT  41.436 0 41.46 0.192 ;
    END
  END t0[169]
  PIN t0[16]
    DIRECTION OUTPUT ;
    USE SIGNAL ;
    PORT
      LAYER M5 ;
        RECT  5.82 0 5.844 0.192 ;
    END
  END t0[16]
  PIN t0[170]
    DIRECTION OUTPUT ;
    USE SIGNAL ;
    PORT
      LAYER M5 ;
        RECT  41.676 0 41.7 0.192 ;
    END
  END t0[170]
  PIN t0[171]
    DIRECTION OUTPUT ;
    USE SIGNAL ;
    PORT
      LAYER M5 ;
        RECT  41.916 0 41.94 0.192 ;
    END
  END t0[171]
  PIN t0[172]
    DIRECTION OUTPUT ;
    USE SIGNAL ;
    PORT
      LAYER M5 ;
        RECT  42.108 0 42.132 0.192 ;
    END
  END t0[172]
  PIN t0[173]
    DIRECTION OUTPUT ;
    USE SIGNAL ;
    PORT
      LAYER M5 ;
        RECT  42.348 0 42.372 0.192 ;
    END
  END t0[173]
  PIN t0[174]
    DIRECTION OUTPUT ;
    USE SIGNAL ;
    PORT
      LAYER M5 ;
        RECT  42.588 0 42.612 0.192 ;
    END
  END t0[174]
  PIN t0[175]
    DIRECTION OUTPUT ;
    USE SIGNAL ;
    PORT
      LAYER M5 ;
        RECT  42.828 0 42.852 0.192 ;
    END
  END t0[175]
  PIN t0[176]
    DIRECTION OUTPUT ;
    USE SIGNAL ;
    PORT
      LAYER M5 ;
        RECT  43.068 0 43.092 0.192 ;
    END
  END t0[176]
  PIN t0[177]
    DIRECTION OUTPUT ;
    USE SIGNAL ;
    PORT
      LAYER M5 ;
        RECT  43.308 0 43.332 0.192 ;
    END
  END t0[177]
  PIN t0[178]
    DIRECTION OUTPUT ;
    USE SIGNAL ;
    PORT
      LAYER M5 ;
        RECT  43.548 0 43.572 0.192 ;
    END
  END t0[178]
  PIN t0[179]
    DIRECTION OUTPUT ;
    USE SIGNAL ;
    PORT
      LAYER M5 ;
        RECT  43.74 0 43.764 0.192 ;
    END
  END t0[179]
  PIN t0[17]
    DIRECTION OUTPUT ;
    USE SIGNAL ;
    PORT
      LAYER M5 ;
        RECT  6.06 0 6.084 0.192 ;
    END
  END t0[17]
  PIN t0[180]
    DIRECTION OUTPUT ;
    USE SIGNAL ;
    PORT
      LAYER M5 ;
        RECT  43.98 0 44.004 0.192 ;
    END
  END t0[180]
  PIN t0[181]
    DIRECTION OUTPUT ;
    USE SIGNAL ;
    PORT
      LAYER M5 ;
        RECT  44.22 0 44.244 0.192 ;
    END
  END t0[181]
  PIN t0[182]
    DIRECTION OUTPUT ;
    USE SIGNAL ;
    PORT
      LAYER M5 ;
        RECT  44.46 0 44.484 0.192 ;
    END
  END t0[182]
  PIN t0[183]
    DIRECTION OUTPUT ;
    USE SIGNAL ;
    PORT
      LAYER M5 ;
        RECT  44.7 0 44.724 0.192 ;
    END
  END t0[183]
  PIN t0[184]
    DIRECTION OUTPUT ;
    USE SIGNAL ;
    PORT
      LAYER M5 ;
        RECT  44.94 0 44.964 0.192 ;
    END
  END t0[184]
  PIN t0[185]
    DIRECTION OUTPUT ;
    USE SIGNAL ;
    PORT
      LAYER M5 ;
        RECT  45.132 0 45.156 0.192 ;
    END
  END t0[185]
  PIN t0[186]
    DIRECTION OUTPUT ;
    USE SIGNAL ;
    PORT
      LAYER M5 ;
        RECT  45.372 0 45.396 0.192 ;
    END
  END t0[186]
  PIN t0[187]
    DIRECTION OUTPUT ;
    USE SIGNAL ;
    PORT
      LAYER M5 ;
        RECT  45.612 0 45.636 0.192 ;
    END
  END t0[187]
  PIN t0[188]
    DIRECTION OUTPUT ;
    USE SIGNAL ;
    PORT
      LAYER M5 ;
        RECT  45.852 0 45.876 0.192 ;
    END
  END t0[188]
  PIN t0[189]
    DIRECTION OUTPUT ;
    USE SIGNAL ;
    PORT
      LAYER M5 ;
        RECT  46.092 0 46.116 0.192 ;
    END
  END t0[189]
  PIN t0[18]
    DIRECTION OUTPUT ;
    USE SIGNAL ;
    PORT
      LAYER M5 ;
        RECT  6.3 0 6.324 0.192 ;
    END
  END t0[18]
  PIN t0[190]
    DIRECTION OUTPUT ;
    USE SIGNAL ;
    PORT
      LAYER M5 ;
        RECT  46.332 0 46.356 0.192 ;
    END
  END t0[190]
  PIN t0[191]
    DIRECTION OUTPUT ;
    USE SIGNAL ;
    PORT
      LAYER M5 ;
        RECT  46.572 0 46.596 0.192 ;
    END
  END t0[191]
  PIN t0[192]
    DIRECTION OUTPUT ;
    USE SIGNAL ;
    PORT
      LAYER M5 ;
        RECT  46.764 0 46.788 0.192 ;
    END
  END t0[192]
  PIN t0[193]
    DIRECTION OUTPUT ;
    USE SIGNAL ;
    PORT
      LAYER M5 ;
        RECT  47.004 0 47.028 0.192 ;
    END
  END t0[193]
  PIN t0[194]
    DIRECTION OUTPUT ;
    USE SIGNAL ;
    PORT
      LAYER M5 ;
        RECT  47.244 0 47.268 0.192 ;
    END
  END t0[194]
  PIN t0[195]
    DIRECTION OUTPUT ;
    USE SIGNAL ;
    PORT
      LAYER M5 ;
        RECT  47.484 0 47.508 0.192 ;
    END
  END t0[195]
  PIN t0[196]
    DIRECTION OUTPUT ;
    USE SIGNAL ;
    PORT
      LAYER M5 ;
        RECT  47.724 0 47.748 0.192 ;
    END
  END t0[196]
  PIN t0[197]
    DIRECTION OUTPUT ;
    USE SIGNAL ;
    PORT
      LAYER M5 ;
        RECT  47.964 0 47.988 0.192 ;
    END
  END t0[197]
  PIN t0[198]
    DIRECTION OUTPUT ;
    USE SIGNAL ;
    PORT
      LAYER M5 ;
        RECT  48.204 0 48.228 0.192 ;
    END
  END t0[198]
  PIN t0[199]
    DIRECTION OUTPUT ;
    USE SIGNAL ;
    PORT
      LAYER M5 ;
        RECT  48.396 0 48.42 0.192 ;
    END
  END t0[199]
  PIN t0[19]
    DIRECTION OUTPUT ;
    USE SIGNAL ;
    PORT
      LAYER M5 ;
        RECT  6.54 0 6.564 0.192 ;
    END
  END t0[19]
  PIN t0[1]
    DIRECTION OUTPUT ;
    USE SIGNAL ;
    PORT
      LAYER M5 ;
        RECT  2.316 0 2.34 0.192 ;
    END
  END t0[1]
  PIN t0[200]
    DIRECTION OUTPUT ;
    USE SIGNAL ;
    PORT
      LAYER M5 ;
        RECT  48.636 0 48.66 0.192 ;
    END
  END t0[200]
  PIN t0[201]
    DIRECTION OUTPUT ;
    USE SIGNAL ;
    PORT
      LAYER M5 ;
        RECT  48.876 0 48.9 0.192 ;
    END
  END t0[201]
  PIN t0[202]
    DIRECTION OUTPUT ;
    USE SIGNAL ;
    PORT
      LAYER M5 ;
        RECT  49.116 0 49.14 0.192 ;
    END
  END t0[202]
  PIN t0[203]
    DIRECTION OUTPUT ;
    USE SIGNAL ;
    PORT
      LAYER M5 ;
        RECT  49.356 0 49.38 0.192 ;
    END
  END t0[203]
  PIN t0[204]
    DIRECTION OUTPUT ;
    USE SIGNAL ;
    PORT
      LAYER M5 ;
        RECT  49.596 0 49.62 0.192 ;
    END
  END t0[204]
  PIN t0[205]
    DIRECTION OUTPUT ;
    USE SIGNAL ;
    PORT
      LAYER M5 ;
        RECT  49.788 0 49.812 0.192 ;
    END
  END t0[205]
  PIN t0[206]
    DIRECTION OUTPUT ;
    USE SIGNAL ;
    PORT
      LAYER M5 ;
        RECT  50.028 0 50.052 0.192 ;
    END
  END t0[206]
  PIN t0[207]
    DIRECTION OUTPUT ;
    USE SIGNAL ;
    PORT
      LAYER M5 ;
        RECT  50.268 0 50.292 0.192 ;
    END
  END t0[207]
  PIN t0[208]
    DIRECTION OUTPUT ;
    USE SIGNAL ;
    PORT
      LAYER M5 ;
        RECT  50.508 0 50.532 0.192 ;
    END
  END t0[208]
  PIN t0[209]
    DIRECTION OUTPUT ;
    USE SIGNAL ;
    PORT
      LAYER M5 ;
        RECT  50.748 0 50.772 0.192 ;
    END
  END t0[209]
  PIN t0[20]
    DIRECTION OUTPUT ;
    USE SIGNAL ;
    PORT
      LAYER M5 ;
        RECT  6.78 0 6.804 0.192 ;
    END
  END t0[20]
  PIN t0[210]
    DIRECTION OUTPUT ;
    USE SIGNAL ;
    PORT
      LAYER M5 ;
        RECT  50.988 0 51.012 0.192 ;
    END
  END t0[210]
  PIN t0[211]
    DIRECTION OUTPUT ;
    USE SIGNAL ;
    PORT
      LAYER M5 ;
        RECT  51.228 0 51.252 0.192 ;
    END
  END t0[211]
  PIN t0[212]
    DIRECTION OUTPUT ;
    USE SIGNAL ;
    PORT
      LAYER M5 ;
        RECT  51.42 0 51.444 0.192 ;
    END
  END t0[212]
  PIN t0[213]
    DIRECTION OUTPUT ;
    USE SIGNAL ;
    PORT
      LAYER M5 ;
        RECT  51.66 0 51.684 0.192 ;
    END
  END t0[213]
  PIN t0[214]
    DIRECTION OUTPUT ;
    USE SIGNAL ;
    PORT
      LAYER M5 ;
        RECT  51.9 0 51.924 0.192 ;
    END
  END t0[214]
  PIN t0[215]
    DIRECTION OUTPUT ;
    USE SIGNAL ;
    PORT
      LAYER M5 ;
        RECT  52.14 0 52.164 0.192 ;
    END
  END t0[215]
  PIN t0[216]
    DIRECTION OUTPUT ;
    USE SIGNAL ;
    PORT
      LAYER M5 ;
        RECT  52.38 0 52.404 0.192 ;
    END
  END t0[216]
  PIN t0[217]
    DIRECTION OUTPUT ;
    USE SIGNAL ;
    PORT
      LAYER M5 ;
        RECT  52.62 0 52.644 0.192 ;
    END
  END t0[217]
  PIN t0[218]
    DIRECTION OUTPUT ;
    USE SIGNAL ;
    PORT
      LAYER M5 ;
        RECT  52.812 0 52.836 0.192 ;
    END
  END t0[218]
  PIN t0[219]
    DIRECTION OUTPUT ;
    USE SIGNAL ;
    PORT
      LAYER M5 ;
        RECT  53.052 0 53.076 0.192 ;
    END
  END t0[219]
  PIN t0[21]
    DIRECTION OUTPUT ;
    USE SIGNAL ;
    PORT
      LAYER M5 ;
        RECT  6.972 0 6.996 0.192 ;
    END
  END t0[21]
  PIN t0[220]
    DIRECTION OUTPUT ;
    USE SIGNAL ;
    PORT
      LAYER M5 ;
        RECT  53.292 0 53.316 0.192 ;
    END
  END t0[220]
  PIN t0[221]
    DIRECTION OUTPUT ;
    USE SIGNAL ;
    PORT
      LAYER M5 ;
        RECT  53.532 0 53.556 0.192 ;
    END
  END t0[221]
  PIN t0[222]
    DIRECTION OUTPUT ;
    USE SIGNAL ;
    PORT
      LAYER M5 ;
        RECT  53.772 0 53.796 0.192 ;
    END
  END t0[222]
  PIN t0[223]
    DIRECTION OUTPUT ;
    USE SIGNAL ;
    PORT
      LAYER M5 ;
        RECT  54.012 0 54.036 0.192 ;
    END
  END t0[223]
  PIN t0[224]
    DIRECTION OUTPUT ;
    USE SIGNAL ;
    PORT
      LAYER M5 ;
        RECT  54.252 0 54.276 0.192 ;
    END
  END t0[224]
  PIN t0[225]
    DIRECTION OUTPUT ;
    USE SIGNAL ;
    PORT
      LAYER M5 ;
        RECT  54.444 0 54.468 0.192 ;
    END
  END t0[225]
  PIN t0[226]
    DIRECTION OUTPUT ;
    USE SIGNAL ;
    PORT
      LAYER M5 ;
        RECT  54.684 0 54.708 0.192 ;
    END
  END t0[226]
  PIN t0[227]
    DIRECTION OUTPUT ;
    USE SIGNAL ;
    PORT
      LAYER M5 ;
        RECT  54.924 0 54.948 0.192 ;
    END
  END t0[227]
  PIN t0[228]
    DIRECTION OUTPUT ;
    USE SIGNAL ;
    PORT
      LAYER M5 ;
        RECT  55.164 0 55.188 0.192 ;
    END
  END t0[228]
  PIN t0[229]
    DIRECTION OUTPUT ;
    USE SIGNAL ;
    PORT
      LAYER M5 ;
        RECT  55.404 0 55.428 0.192 ;
    END
  END t0[229]
  PIN t0[22]
    DIRECTION OUTPUT ;
    USE SIGNAL ;
    PORT
      LAYER M5 ;
        RECT  7.212 0 7.236 0.192 ;
    END
  END t0[22]
  PIN t0[230]
    DIRECTION OUTPUT ;
    USE SIGNAL ;
    PORT
      LAYER M5 ;
        RECT  55.644 0 55.668 0.192 ;
    END
  END t0[230]
  PIN t0[231]
    DIRECTION OUTPUT ;
    USE SIGNAL ;
    PORT
      LAYER M5 ;
        RECT  55.884 0 55.908 0.192 ;
    END
  END t0[231]
  PIN t0[232]
    DIRECTION OUTPUT ;
    USE SIGNAL ;
    PORT
      LAYER M5 ;
        RECT  56.076 0 56.1 0.192 ;
    END
  END t0[232]
  PIN t0[233]
    DIRECTION OUTPUT ;
    USE SIGNAL ;
    PORT
      LAYER M5 ;
        RECT  56.316 0 56.34 0.192 ;
    END
  END t0[233]
  PIN t0[234]
    DIRECTION OUTPUT ;
    USE SIGNAL ;
    PORT
      LAYER M5 ;
        RECT  56.556 0 56.58 0.192 ;
    END
  END t0[234]
  PIN t0[235]
    DIRECTION OUTPUT ;
    USE SIGNAL ;
    PORT
      LAYER M5 ;
        RECT  56.796 0 56.82 0.192 ;
    END
  END t0[235]
  PIN t0[236]
    DIRECTION OUTPUT ;
    USE SIGNAL ;
    PORT
      LAYER M5 ;
        RECT  57.036 0 57.06 0.192 ;
    END
  END t0[236]
  PIN t0[237]
    DIRECTION OUTPUT ;
    USE SIGNAL ;
    PORT
      LAYER M5 ;
        RECT  57.276 0 57.3 0.192 ;
    END
  END t0[237]
  PIN t0[238]
    DIRECTION OUTPUT ;
    USE SIGNAL ;
    PORT
      LAYER M5 ;
        RECT  57.468 0 57.492 0.192 ;
    END
  END t0[238]
  PIN t0[239]
    DIRECTION OUTPUT ;
    USE SIGNAL ;
    PORT
      LAYER M5 ;
        RECT  57.708 0 57.732 0.192 ;
    END
  END t0[239]
  PIN t0[23]
    DIRECTION OUTPUT ;
    USE SIGNAL ;
    PORT
      LAYER M5 ;
        RECT  7.452 0 7.476 0.192 ;
    END
  END t0[23]
  PIN t0[240]
    DIRECTION OUTPUT ;
    USE SIGNAL ;
    PORT
      LAYER M5 ;
        RECT  57.948 0 57.972 0.192 ;
    END
  END t0[240]
  PIN t0[241]
    DIRECTION OUTPUT ;
    USE SIGNAL ;
    PORT
      LAYER M5 ;
        RECT  58.188 0 58.212 0.192 ;
    END
  END t0[241]
  PIN t0[242]
    DIRECTION OUTPUT ;
    USE SIGNAL ;
    PORT
      LAYER M5 ;
        RECT  58.428 0 58.452 0.192 ;
    END
  END t0[242]
  PIN t0[243]
    DIRECTION OUTPUT ;
    USE SIGNAL ;
    PORT
      LAYER M5 ;
        RECT  58.668 0 58.692 0.192 ;
    END
  END t0[243]
  PIN t0[244]
    DIRECTION OUTPUT ;
    USE SIGNAL ;
    PORT
      LAYER M5 ;
        RECT  58.908 0 58.932 0.192 ;
    END
  END t0[244]
  PIN t0[245]
    DIRECTION OUTPUT ;
    USE SIGNAL ;
    PORT
      LAYER M5 ;
        RECT  59.1 0 59.124 0.192 ;
    END
  END t0[245]
  PIN t0[246]
    DIRECTION OUTPUT ;
    USE SIGNAL ;
    PORT
      LAYER M5 ;
        RECT  59.34 0 59.364 0.192 ;
    END
  END t0[246]
  PIN t0[247]
    DIRECTION OUTPUT ;
    USE SIGNAL ;
    PORT
      LAYER M5 ;
        RECT  59.58 0 59.604 0.192 ;
    END
  END t0[247]
  PIN t0[248]
    DIRECTION OUTPUT ;
    USE SIGNAL ;
    PORT
      LAYER M5 ;
        RECT  59.82 0 59.844 0.192 ;
    END
  END t0[248]
  PIN t0[249]
    DIRECTION OUTPUT ;
    USE SIGNAL ;
    PORT
      LAYER M5 ;
        RECT  60.06 0 60.084 0.192 ;
    END
  END t0[249]
  PIN t0[24]
    DIRECTION OUTPUT ;
    USE SIGNAL ;
    PORT
      LAYER M5 ;
        RECT  7.692 0 7.716 0.192 ;
    END
  END t0[24]
  PIN t0[250]
    DIRECTION OUTPUT ;
    USE SIGNAL ;
    PORT
      LAYER M5 ;
        RECT  60.3 0 60.324 0.192 ;
    END
  END t0[250]
  PIN t0[251]
    DIRECTION OUTPUT ;
    USE SIGNAL ;
    PORT
      LAYER M5 ;
        RECT  60.492 0 60.516 0.192 ;
    END
  END t0[251]
  PIN t0[252]
    DIRECTION OUTPUT ;
    USE SIGNAL ;
    PORT
      LAYER M5 ;
        RECT  60.732 0 60.756 0.192 ;
    END
  END t0[252]
  PIN t0[253]
    DIRECTION OUTPUT ;
    USE SIGNAL ;
    PORT
      LAYER M5 ;
        RECT  60.972 0 60.996 0.192 ;
    END
  END t0[253]
  PIN t0[25]
    DIRECTION OUTPUT ;
    USE SIGNAL ;
    PORT
      LAYER M5 ;
        RECT  7.932 0 7.956 0.192 ;
    END
  END t0[25]
  PIN t0[26]
    DIRECTION OUTPUT ;
    USE SIGNAL ;
    PORT
      LAYER M5 ;
        RECT  8.172 0 8.196 0.192 ;
    END
  END t0[26]
  PIN t0[27]
    DIRECTION OUTPUT ;
    USE SIGNAL ;
    PORT
      LAYER M5 ;
        RECT  8.364 0 8.388 0.192 ;
    END
  END t0[27]
  PIN t0[28]
    DIRECTION OUTPUT ;
    USE SIGNAL ;
    PORT
      LAYER M5 ;
        RECT  8.604 0 8.628 0.192 ;
    END
  END t0[28]
  PIN t0[29]
    DIRECTION OUTPUT ;
    USE SIGNAL ;
    PORT
      LAYER M5 ;
        RECT  8.844 0 8.868 0.192 ;
    END
  END t0[29]
  PIN t0[2]
    DIRECTION OUTPUT ;
    USE SIGNAL ;
    PORT
      LAYER M5 ;
        RECT  2.556 0 2.58 0.192 ;
    END
  END t0[2]
  PIN t0[30]
    DIRECTION OUTPUT ;
    USE SIGNAL ;
    PORT
      LAYER M5 ;
        RECT  9.084 0 9.108 0.192 ;
    END
  END t0[30]
  PIN t0[31]
    DIRECTION OUTPUT ;
    USE SIGNAL ;
    PORT
      LAYER M5 ;
        RECT  9.324 0 9.348 0.192 ;
    END
  END t0[31]
  PIN t0[32]
    DIRECTION OUTPUT ;
    USE SIGNAL ;
    PORT
      LAYER M5 ;
        RECT  9.564 0 9.588 0.192 ;
    END
  END t0[32]
  PIN t0[33]
    DIRECTION OUTPUT ;
    USE SIGNAL ;
    PORT
      LAYER M5 ;
        RECT  9.804 0 9.828 0.192 ;
    END
  END t0[33]
  PIN t0[34]
    DIRECTION OUTPUT ;
    USE SIGNAL ;
    PORT
      LAYER M5 ;
        RECT  9.996 0 10.02 0.192 ;
    END
  END t0[34]
  PIN t0[35]
    DIRECTION OUTPUT ;
    USE SIGNAL ;
    PORT
      LAYER M5 ;
        RECT  10.236 0 10.26 0.192 ;
    END
  END t0[35]
  PIN t0[36]
    DIRECTION OUTPUT ;
    USE SIGNAL ;
    PORT
      LAYER M5 ;
        RECT  10.476 0 10.5 0.192 ;
    END
  END t0[36]
  PIN t0[37]
    DIRECTION OUTPUT ;
    USE SIGNAL ;
    PORT
      LAYER M5 ;
        RECT  10.716 0 10.74 0.192 ;
    END
  END t0[37]
  PIN t0[38]
    DIRECTION OUTPUT ;
    USE SIGNAL ;
    PORT
      LAYER M5 ;
        RECT  10.956 0 10.98 0.192 ;
    END
  END t0[38]
  PIN t0[39]
    DIRECTION OUTPUT ;
    USE SIGNAL ;
    PORT
      LAYER M5 ;
        RECT  11.196 0 11.22 0.192 ;
    END
  END t0[39]
  PIN t0[3]
    DIRECTION OUTPUT ;
    USE SIGNAL ;
    PORT
      LAYER M5 ;
        RECT  2.796 0 2.82 0.192 ;
    END
  END t0[3]
  PIN t0[40]
    DIRECTION OUTPUT ;
    USE SIGNAL ;
    PORT
      LAYER M5 ;
        RECT  11.436 0 11.46 0.192 ;
    END
  END t0[40]
  PIN t0[41]
    DIRECTION OUTPUT ;
    USE SIGNAL ;
    PORT
      LAYER M5 ;
        RECT  11.628 0 11.652 0.192 ;
    END
  END t0[41]
  PIN t0[42]
    DIRECTION OUTPUT ;
    USE SIGNAL ;
    PORT
      LAYER M5 ;
        RECT  11.868 0 11.892 0.192 ;
    END
  END t0[42]
  PIN t0[43]
    DIRECTION OUTPUT ;
    USE SIGNAL ;
    PORT
      LAYER M5 ;
        RECT  12.108 0 12.132 0.192 ;
    END
  END t0[43]
  PIN t0[44]
    DIRECTION OUTPUT ;
    USE SIGNAL ;
    PORT
      LAYER M5 ;
        RECT  12.348 0 12.372 0.192 ;
    END
  END t0[44]
  PIN t0[45]
    DIRECTION OUTPUT ;
    USE SIGNAL ;
    PORT
      LAYER M5 ;
        RECT  12.588 0 12.612 0.192 ;
    END
  END t0[45]
  PIN t0[46]
    DIRECTION OUTPUT ;
    USE SIGNAL ;
    PORT
      LAYER M5 ;
        RECT  12.828 0 12.852 0.192 ;
    END
  END t0[46]
  PIN t0[47]
    DIRECTION OUTPUT ;
    USE SIGNAL ;
    PORT
      LAYER M5 ;
        RECT  13.02 0 13.044 0.192 ;
    END
  END t0[47]
  PIN t0[48]
    DIRECTION OUTPUT ;
    USE SIGNAL ;
    PORT
      LAYER M5 ;
        RECT  13.26 0 13.284 0.192 ;
    END
  END t0[48]
  PIN t0[49]
    DIRECTION OUTPUT ;
    USE SIGNAL ;
    PORT
      LAYER M5 ;
        RECT  13.5 0 13.524 0.192 ;
    END
  END t0[49]
  PIN t0[4]
    DIRECTION OUTPUT ;
    USE SIGNAL ;
    PORT
      LAYER M5 ;
        RECT  3.036 0 3.06 0.192 ;
    END
  END t0[4]
  PIN t0[50]
    DIRECTION OUTPUT ;
    USE SIGNAL ;
    PORT
      LAYER M5 ;
        RECT  13.74 0 13.764 0.192 ;
    END
  END t0[50]
  PIN t0[51]
    DIRECTION OUTPUT ;
    USE SIGNAL ;
    PORT
      LAYER M5 ;
        RECT  13.98 0 14.004 0.192 ;
    END
  END t0[51]
  PIN t0[52]
    DIRECTION OUTPUT ;
    USE SIGNAL ;
    PORT
      LAYER M5 ;
        RECT  14.22 0 14.244 0.192 ;
    END
  END t0[52]
  PIN t0[53]
    DIRECTION OUTPUT ;
    USE SIGNAL ;
    PORT
      LAYER M5 ;
        RECT  14.46 0 14.484 0.192 ;
    END
  END t0[53]
  PIN t0[54]
    DIRECTION OUTPUT ;
    USE SIGNAL ;
    PORT
      LAYER M5 ;
        RECT  14.652 0 14.676 0.192 ;
    END
  END t0[54]
  PIN t0[55]
    DIRECTION OUTPUT ;
    USE SIGNAL ;
    PORT
      LAYER M5 ;
        RECT  14.892 0 14.916 0.192 ;
    END
  END t0[55]
  PIN t0[56]
    DIRECTION OUTPUT ;
    USE SIGNAL ;
    PORT
      LAYER M5 ;
        RECT  15.132 0 15.156 0.192 ;
    END
  END t0[56]
  PIN t0[57]
    DIRECTION OUTPUT ;
    USE SIGNAL ;
    PORT
      LAYER M5 ;
        RECT  15.372 0 15.396 0.192 ;
    END
  END t0[57]
  PIN t0[58]
    DIRECTION OUTPUT ;
    USE SIGNAL ;
    PORT
      LAYER M5 ;
        RECT  15.612 0 15.636 0.192 ;
    END
  END t0[58]
  PIN t0[59]
    DIRECTION OUTPUT ;
    USE SIGNAL ;
    PORT
      LAYER M5 ;
        RECT  15.852 0 15.876 0.192 ;
    END
  END t0[59]
  PIN t0[5]
    DIRECTION OUTPUT ;
    USE SIGNAL ;
    PORT
      LAYER M5 ;
        RECT  3.276 0 3.3 0.192 ;
    END
  END t0[5]
  PIN t0[60]
    DIRECTION OUTPUT ;
    USE SIGNAL ;
    PORT
      LAYER M5 ;
        RECT  16.044 0 16.068 0.192 ;
    END
  END t0[60]
  PIN t0[61]
    DIRECTION OUTPUT ;
    USE SIGNAL ;
    PORT
      LAYER M5 ;
        RECT  16.284 0 16.308 0.192 ;
    END
  END t0[61]
  PIN t0[62]
    DIRECTION OUTPUT ;
    USE SIGNAL ;
    PORT
      LAYER M5 ;
        RECT  16.524 0 16.548 0.192 ;
    END
  END t0[62]
  PIN t0[63]
    DIRECTION OUTPUT ;
    USE SIGNAL ;
    PORT
      LAYER M5 ;
        RECT  16.764 0 16.788 0.192 ;
    END
  END t0[63]
  PIN t0[64]
    DIRECTION OUTPUT ;
    USE SIGNAL ;
    PORT
      LAYER M5 ;
        RECT  17.004 0 17.028 0.192 ;
    END
  END t0[64]
  PIN t0[65]
    DIRECTION OUTPUT ;
    USE SIGNAL ;
    PORT
      LAYER M5 ;
        RECT  17.244 0 17.268 0.192 ;
    END
  END t0[65]
  PIN t0[66]
    DIRECTION OUTPUT ;
    USE SIGNAL ;
    PORT
      LAYER M5 ;
        RECT  17.484 0 17.508 0.192 ;
    END
  END t0[66]
  PIN t0[67]
    DIRECTION OUTPUT ;
    USE SIGNAL ;
    PORT
      LAYER M5 ;
        RECT  17.676 0 17.7 0.192 ;
    END
  END t0[67]
  PIN t0[68]
    DIRECTION OUTPUT ;
    USE SIGNAL ;
    PORT
      LAYER M5 ;
        RECT  17.916 0 17.94 0.192 ;
    END
  END t0[68]
  PIN t0[69]
    DIRECTION OUTPUT ;
    USE SIGNAL ;
    PORT
      LAYER M5 ;
        RECT  18.156 0 18.18 0.192 ;
    END
  END t0[69]
  PIN t0[6]
    DIRECTION OUTPUT ;
    USE SIGNAL ;
    PORT
      LAYER M5 ;
        RECT  3.516 0 3.54 0.192 ;
    END
  END t0[6]
  PIN t0[70]
    DIRECTION OUTPUT ;
    USE SIGNAL ;
    PORT
      LAYER M5 ;
        RECT  18.396 0 18.42 0.192 ;
    END
  END t0[70]
  PIN t0[71]
    DIRECTION OUTPUT ;
    USE SIGNAL ;
    PORT
      LAYER M5 ;
        RECT  18.636 0 18.66 0.192 ;
    END
  END t0[71]
  PIN t0[72]
    DIRECTION OUTPUT ;
    USE SIGNAL ;
    PORT
      LAYER M5 ;
        RECT  18.876 0 18.9 0.192 ;
    END
  END t0[72]
  PIN t0[73]
    DIRECTION OUTPUT ;
    USE SIGNAL ;
    PORT
      LAYER M5 ;
        RECT  19.116 0 19.14 0.192 ;
    END
  END t0[73]
  PIN t0[74]
    DIRECTION OUTPUT ;
    USE SIGNAL ;
    PORT
      LAYER M5 ;
        RECT  19.308 0 19.332 0.192 ;
    END
  END t0[74]
  PIN t0[75]
    DIRECTION OUTPUT ;
    USE SIGNAL ;
    PORT
      LAYER M5 ;
        RECT  19.548 0 19.572 0.192 ;
    END
  END t0[75]
  PIN t0[76]
    DIRECTION OUTPUT ;
    USE SIGNAL ;
    PORT
      LAYER M5 ;
        RECT  19.788 0 19.812 0.192 ;
    END
  END t0[76]
  PIN t0[77]
    DIRECTION OUTPUT ;
    USE SIGNAL ;
    PORT
      LAYER M5 ;
        RECT  20.028 0 20.052 0.192 ;
    END
  END t0[77]
  PIN t0[78]
    DIRECTION OUTPUT ;
    USE SIGNAL ;
    PORT
      LAYER M5 ;
        RECT  20.268 0 20.292 0.192 ;
    END
  END t0[78]
  PIN t0[79]
    DIRECTION OUTPUT ;
    USE SIGNAL ;
    PORT
      LAYER M5 ;
        RECT  20.508 0 20.532 0.192 ;
    END
  END t0[79]
  PIN t0[7]
    DIRECTION OUTPUT ;
    USE SIGNAL ;
    PORT
      LAYER M5 ;
        RECT  3.756 0 3.78 0.192 ;
    END
  END t0[7]
  PIN t0[80]
    DIRECTION OUTPUT ;
    USE SIGNAL ;
    PORT
      LAYER M5 ;
        RECT  20.7 0 20.724 0.192 ;
    END
  END t0[80]
  PIN t0[81]
    DIRECTION OUTPUT ;
    USE SIGNAL ;
    PORT
      LAYER M5 ;
        RECT  20.94 0 20.964 0.192 ;
    END
  END t0[81]
  PIN t0[82]
    DIRECTION OUTPUT ;
    USE SIGNAL ;
    PORT
      LAYER M5 ;
        RECT  21.18 0 21.204 0.192 ;
    END
  END t0[82]
  PIN t0[83]
    DIRECTION OUTPUT ;
    USE SIGNAL ;
    PORT
      LAYER M5 ;
        RECT  21.42 0 21.444 0.192 ;
    END
  END t0[83]
  PIN t0[84]
    DIRECTION OUTPUT ;
    USE SIGNAL ;
    PORT
      LAYER M5 ;
        RECT  21.66 0 21.684 0.192 ;
    END
  END t0[84]
  PIN t0[85]
    DIRECTION OUTPUT ;
    USE SIGNAL ;
    PORT
      LAYER M5 ;
        RECT  21.9 0 21.924 0.192 ;
    END
  END t0[85]
  PIN t0[86]
    DIRECTION OUTPUT ;
    USE SIGNAL ;
    PORT
      LAYER M5 ;
        RECT  22.14 0 22.164 0.192 ;
    END
  END t0[86]
  PIN t0[87]
    DIRECTION OUTPUT ;
    USE SIGNAL ;
    PORT
      LAYER M5 ;
        RECT  22.332 0 22.356 0.192 ;
    END
  END t0[87]
  PIN t0[88]
    DIRECTION OUTPUT ;
    USE SIGNAL ;
    PORT
      LAYER M5 ;
        RECT  22.572 0 22.596 0.192 ;
    END
  END t0[88]
  PIN t0[89]
    DIRECTION OUTPUT ;
    USE SIGNAL ;
    PORT
      LAYER M5 ;
        RECT  22.812 0 22.836 0.192 ;
    END
  END t0[89]
  PIN t0[8]
    DIRECTION OUTPUT ;
    USE SIGNAL ;
    PORT
      LAYER M5 ;
        RECT  3.948 0 3.972 0.192 ;
    END
  END t0[8]
  PIN t0[90]
    DIRECTION OUTPUT ;
    USE SIGNAL ;
    PORT
      LAYER M5 ;
        RECT  23.052 0 23.076 0.192 ;
    END
  END t0[90]
  PIN t0[91]
    DIRECTION OUTPUT ;
    USE SIGNAL ;
    PORT
      LAYER M5 ;
        RECT  23.292 0 23.316 0.192 ;
    END
  END t0[91]
  PIN t0[92]
    DIRECTION OUTPUT ;
    USE SIGNAL ;
    PORT
      LAYER M5 ;
        RECT  23.532 0 23.556 0.192 ;
    END
  END t0[92]
  PIN t0[93]
    DIRECTION OUTPUT ;
    USE SIGNAL ;
    PORT
      LAYER M5 ;
        RECT  23.724 0 23.748 0.192 ;
    END
  END t0[93]
  PIN t0[94]
    DIRECTION OUTPUT ;
    USE SIGNAL ;
    PORT
      LAYER M5 ;
        RECT  23.964 0 23.988 0.192 ;
    END
  END t0[94]
  PIN t0[95]
    DIRECTION OUTPUT ;
    USE SIGNAL ;
    PORT
      LAYER M5 ;
        RECT  24.204 0 24.228 0.192 ;
    END
  END t0[95]
  PIN t0[96]
    DIRECTION OUTPUT ;
    USE SIGNAL ;
    PORT
      LAYER M5 ;
        RECT  24.444 0 24.468 0.192 ;
    END
  END t0[96]
  PIN t0[97]
    DIRECTION OUTPUT ;
    USE SIGNAL ;
    PORT
      LAYER M5 ;
        RECT  24.684 0 24.708 0.192 ;
    END
  END t0[97]
  PIN t0[98]
    DIRECTION OUTPUT ;
    USE SIGNAL ;
    PORT
      LAYER M5 ;
        RECT  24.924 0 24.948 0.192 ;
    END
  END t0[98]
  PIN t0[99]
    DIRECTION OUTPUT ;
    USE SIGNAL ;
    PORT
      LAYER M5 ;
        RECT  25.164 0 25.188 0.192 ;
    END
  END t0[99]
  PIN t0[9]
    DIRECTION OUTPUT ;
    USE SIGNAL ;
    PORT
      LAYER M5 ;
        RECT  4.188 0 4.212 0.192 ;
    END
  END t0[9]
  PIN t1[0]
    DIRECTION OUTPUT ;
    USE SIGNAL ;
    PORT
      LAYER M5 ;
        RECT  61.212 0 61.236 0.192 ;
    END
  END t1[0]
  PIN t1[100]
    DIRECTION OUTPUT ;
    USE SIGNAL ;
    PORT
      LAYER M5 ;
        RECT  84.492 0 84.516 0.192 ;
    END
  END t1[100]
  PIN t1[101]
    DIRECTION OUTPUT ;
    USE SIGNAL ;
    PORT
      LAYER M5 ;
        RECT  84.732 0 84.756 0.192 ;
    END
  END t1[101]
  PIN t1[102]
    DIRECTION OUTPUT ;
    USE SIGNAL ;
    PORT
      LAYER M5 ;
        RECT  84.972 0 84.996 0.192 ;
    END
  END t1[102]
  PIN t1[103]
    DIRECTION OUTPUT ;
    USE SIGNAL ;
    PORT
      LAYER M5 ;
        RECT  85.164 0 85.188 0.192 ;
    END
  END t1[103]
  PIN t1[104]
    DIRECTION OUTPUT ;
    USE SIGNAL ;
    PORT
      LAYER M5 ;
        RECT  85.404 0 85.428 0.192 ;
    END
  END t1[104]
  PIN t1[105]
    DIRECTION OUTPUT ;
    USE SIGNAL ;
    PORT
      LAYER M5 ;
        RECT  85.644 0 85.668 0.192 ;
    END
  END t1[105]
  PIN t1[106]
    DIRECTION OUTPUT ;
    USE SIGNAL ;
    PORT
      LAYER M5 ;
        RECT  85.884 0 85.908 0.192 ;
    END
  END t1[106]
  PIN t1[107]
    DIRECTION OUTPUT ;
    USE SIGNAL ;
    PORT
      LAYER M5 ;
        RECT  86.124 0 86.148 0.192 ;
    END
  END t1[107]
  PIN t1[108]
    DIRECTION OUTPUT ;
    USE SIGNAL ;
    PORT
      LAYER M5 ;
        RECT  86.364 0 86.388 0.192 ;
    END
  END t1[108]
  PIN t1[109]
    DIRECTION OUTPUT ;
    USE SIGNAL ;
    PORT
      LAYER M5 ;
        RECT  86.556 0 86.58 0.192 ;
    END
  END t1[109]
  PIN t1[10]
    DIRECTION OUTPUT ;
    USE SIGNAL ;
    PORT
      LAYER M5 ;
        RECT  63.564 0 63.588 0.192 ;
    END
  END t1[10]
  PIN t1[110]
    DIRECTION OUTPUT ;
    USE SIGNAL ;
    PORT
      LAYER M5 ;
        RECT  86.796 0 86.82 0.192 ;
    END
  END t1[110]
  PIN t1[111]
    DIRECTION OUTPUT ;
    USE SIGNAL ;
    PORT
      LAYER M5 ;
        RECT  87.036 0 87.06 0.192 ;
    END
  END t1[111]
  PIN t1[112]
    DIRECTION OUTPUT ;
    USE SIGNAL ;
    PORT
      LAYER M5 ;
        RECT  87.276 0 87.3 0.192 ;
    END
  END t1[112]
  PIN t1[113]
    DIRECTION OUTPUT ;
    USE SIGNAL ;
    PORT
      LAYER M5 ;
        RECT  87.516 0 87.54 0.192 ;
    END
  END t1[113]
  PIN t1[114]
    DIRECTION OUTPUT ;
    USE SIGNAL ;
    PORT
      LAYER M5 ;
        RECT  87.756 0 87.78 0.192 ;
    END
  END t1[114]
  PIN t1[115]
    DIRECTION OUTPUT ;
    USE SIGNAL ;
    PORT
      LAYER M5 ;
        RECT  87.996 0 88.02 0.192 ;
    END
  END t1[115]
  PIN t1[116]
    DIRECTION OUTPUT ;
    USE SIGNAL ;
    PORT
      LAYER M5 ;
        RECT  88.188 0 88.212 0.192 ;
    END
  END t1[116]
  PIN t1[117]
    DIRECTION OUTPUT ;
    USE SIGNAL ;
    PORT
      LAYER M5 ;
        RECT  88.428 0 88.452 0.192 ;
    END
  END t1[117]
  PIN t1[118]
    DIRECTION OUTPUT ;
    USE SIGNAL ;
    PORT
      LAYER M5 ;
        RECT  88.668 0 88.692 0.192 ;
    END
  END t1[118]
  PIN t1[119]
    DIRECTION OUTPUT ;
    USE SIGNAL ;
    PORT
      LAYER M5 ;
        RECT  88.908 0 88.932 0.192 ;
    END
  END t1[119]
  PIN t1[11]
    DIRECTION OUTPUT ;
    USE SIGNAL ;
    PORT
      LAYER M5 ;
        RECT  63.756 0 63.78 0.192 ;
    END
  END t1[11]
  PIN t1[120]
    DIRECTION OUTPUT ;
    USE SIGNAL ;
    PORT
      LAYER M5 ;
        RECT  89.148 0 89.172 0.192 ;
    END
  END t1[120]
  PIN t1[121]
    DIRECTION OUTPUT ;
    USE SIGNAL ;
    PORT
      LAYER M5 ;
        RECT  89.388 0 89.412 0.192 ;
    END
  END t1[121]
  PIN t1[122]
    DIRECTION OUTPUT ;
    USE SIGNAL ;
    PORT
      LAYER M5 ;
        RECT  89.58 0 89.604 0.192 ;
    END
  END t1[122]
  PIN t1[123]
    DIRECTION OUTPUT ;
    USE SIGNAL ;
    PORT
      LAYER M5 ;
        RECT  89.82 0 89.844 0.192 ;
    END
  END t1[123]
  PIN t1[124]
    DIRECTION OUTPUT ;
    USE SIGNAL ;
    PORT
      LAYER M5 ;
        RECT  90.06 0 90.084 0.192 ;
    END
  END t1[124]
  PIN t1[125]
    DIRECTION OUTPUT ;
    USE SIGNAL ;
    PORT
      LAYER M5 ;
        RECT  90.3 0 90.324 0.192 ;
    END
  END t1[125]
  PIN t1[126]
    DIRECTION OUTPUT ;
    USE SIGNAL ;
    PORT
      LAYER M5 ;
        RECT  90.54 0 90.564 0.192 ;
    END
  END t1[126]
  PIN t1[127]
    DIRECTION OUTPUT ;
    USE SIGNAL ;
    PORT
      LAYER M5 ;
        RECT  90.78 0 90.804 0.192 ;
    END
  END t1[127]
  PIN t1[128]
    DIRECTION OUTPUT ;
    USE SIGNAL ;
    PORT
      LAYER M5 ;
        RECT  91.02 0 91.044 0.192 ;
    END
  END t1[128]
  PIN t1[129]
    DIRECTION OUTPUT ;
    USE SIGNAL ;
    PORT
      LAYER M5 ;
        RECT  91.212 0 91.236 0.192 ;
    END
  END t1[129]
  PIN t1[12]
    DIRECTION OUTPUT ;
    USE SIGNAL ;
    PORT
      LAYER M5 ;
        RECT  63.996 0 64.02 0.192 ;
    END
  END t1[12]
  PIN t1[130]
    DIRECTION OUTPUT ;
    USE SIGNAL ;
    PORT
      LAYER M5 ;
        RECT  91.452 0 91.476 0.192 ;
    END
  END t1[130]
  PIN t1[131]
    DIRECTION OUTPUT ;
    USE SIGNAL ;
    PORT
      LAYER M5 ;
        RECT  91.692 0 91.716 0.192 ;
    END
  END t1[131]
  PIN t1[132]
    DIRECTION OUTPUT ;
    USE SIGNAL ;
    PORT
      LAYER M5 ;
        RECT  91.932 0 91.956 0.192 ;
    END
  END t1[132]
  PIN t1[133]
    DIRECTION OUTPUT ;
    USE SIGNAL ;
    PORT
      LAYER M5 ;
        RECT  92.172 0 92.196 0.192 ;
    END
  END t1[133]
  PIN t1[134]
    DIRECTION OUTPUT ;
    USE SIGNAL ;
    PORT
      LAYER M5 ;
        RECT  92.412 0 92.436 0.192 ;
    END
  END t1[134]
  PIN t1[135]
    DIRECTION OUTPUT ;
    USE SIGNAL ;
    PORT
      LAYER M5 ;
        RECT  92.652 0 92.676 0.192 ;
    END
  END t1[135]
  PIN t1[136]
    DIRECTION OUTPUT ;
    USE SIGNAL ;
    PORT
      LAYER M5 ;
        RECT  92.844 0 92.868 0.192 ;
    END
  END t1[136]
  PIN t1[137]
    DIRECTION OUTPUT ;
    USE SIGNAL ;
    PORT
      LAYER M5 ;
        RECT  93.084 0 93.108 0.192 ;
    END
  END t1[137]
  PIN t1[138]
    DIRECTION OUTPUT ;
    USE SIGNAL ;
    PORT
      LAYER M5 ;
        RECT  93.324 0 93.348 0.192 ;
    END
  END t1[138]
  PIN t1[139]
    DIRECTION OUTPUT ;
    USE SIGNAL ;
    PORT
      LAYER M5 ;
        RECT  93.564 0 93.588 0.192 ;
    END
  END t1[139]
  PIN t1[13]
    DIRECTION OUTPUT ;
    USE SIGNAL ;
    PORT
      LAYER M5 ;
        RECT  64.236 0 64.26 0.192 ;
    END
  END t1[13]
  PIN t1[140]
    DIRECTION OUTPUT ;
    USE SIGNAL ;
    PORT
      LAYER M5 ;
        RECT  93.804 0 93.828 0.192 ;
    END
  END t1[140]
  PIN t1[141]
    DIRECTION OUTPUT ;
    USE SIGNAL ;
    PORT
      LAYER M5 ;
        RECT  94.044 0 94.068 0.192 ;
    END
  END t1[141]
  PIN t1[142]
    DIRECTION OUTPUT ;
    USE SIGNAL ;
    PORT
      LAYER M5 ;
        RECT  94.236 0 94.26 0.192 ;
    END
  END t1[142]
  PIN t1[143]
    DIRECTION OUTPUT ;
    USE SIGNAL ;
    PORT
      LAYER M5 ;
        RECT  94.476 0 94.5 0.192 ;
    END
  END t1[143]
  PIN t1[144]
    DIRECTION OUTPUT ;
    USE SIGNAL ;
    PORT
      LAYER M5 ;
        RECT  94.716 0 94.74 0.192 ;
    END
  END t1[144]
  PIN t1[145]
    DIRECTION OUTPUT ;
    USE SIGNAL ;
    PORT
      LAYER M5 ;
        RECT  94.956 0 94.98 0.192 ;
    END
  END t1[145]
  PIN t1[146]
    DIRECTION OUTPUT ;
    USE SIGNAL ;
    PORT
      LAYER M5 ;
        RECT  95.196 0 95.22 0.192 ;
    END
  END t1[146]
  PIN t1[147]
    DIRECTION OUTPUT ;
    USE SIGNAL ;
    PORT
      LAYER M5 ;
        RECT  95.436 0 95.46 0.192 ;
    END
  END t1[147]
  PIN t1[148]
    DIRECTION OUTPUT ;
    USE SIGNAL ;
    PORT
      LAYER M5 ;
        RECT  95.676 0 95.7 0.192 ;
    END
  END t1[148]
  PIN t1[149]
    DIRECTION OUTPUT ;
    USE SIGNAL ;
    PORT
      LAYER M5 ;
        RECT  95.868 0 95.892 0.192 ;
    END
  END t1[149]
  PIN t1[14]
    DIRECTION OUTPUT ;
    USE SIGNAL ;
    PORT
      LAYER M5 ;
        RECT  64.476 0 64.5 0.192 ;
    END
  END t1[14]
  PIN t1[150]
    DIRECTION OUTPUT ;
    USE SIGNAL ;
    PORT
      LAYER M5 ;
        RECT  96.108 0 96.132 0.192 ;
    END
  END t1[150]
  PIN t1[151]
    DIRECTION OUTPUT ;
    USE SIGNAL ;
    PORT
      LAYER M5 ;
        RECT  96.348 0 96.372 0.192 ;
    END
  END t1[151]
  PIN t1[152]
    DIRECTION OUTPUT ;
    USE SIGNAL ;
    PORT
      LAYER M5 ;
        RECT  96.588 0 96.612 0.192 ;
    END
  END t1[152]
  PIN t1[153]
    DIRECTION OUTPUT ;
    USE SIGNAL ;
    PORT
      LAYER M5 ;
        RECT  96.828 0 96.852 0.192 ;
    END
  END t1[153]
  PIN t1[154]
    DIRECTION OUTPUT ;
    USE SIGNAL ;
    PORT
      LAYER M5 ;
        RECT  97.068 0 97.092 0.192 ;
    END
  END t1[154]
  PIN t1[155]
    DIRECTION OUTPUT ;
    USE SIGNAL ;
    PORT
      LAYER M5 ;
        RECT  97.26 0 97.284 0.192 ;
    END
  END t1[155]
  PIN t1[156]
    DIRECTION OUTPUT ;
    USE SIGNAL ;
    PORT
      LAYER M5 ;
        RECT  97.5 0 97.524 0.192 ;
    END
  END t1[156]
  PIN t1[157]
    DIRECTION OUTPUT ;
    USE SIGNAL ;
    PORT
      LAYER M5 ;
        RECT  97.74 0 97.764 0.192 ;
    END
  END t1[157]
  PIN t1[158]
    DIRECTION OUTPUT ;
    USE SIGNAL ;
    PORT
      LAYER M5 ;
        RECT  97.98 0 98.004 0.192 ;
    END
  END t1[158]
  PIN t1[159]
    DIRECTION OUTPUT ;
    USE SIGNAL ;
    PORT
      LAYER M5 ;
        RECT  98.22 0 98.244 0.192 ;
    END
  END t1[159]
  PIN t1[15]
    DIRECTION OUTPUT ;
    USE SIGNAL ;
    PORT
      LAYER M5 ;
        RECT  64.716 0 64.74 0.192 ;
    END
  END t1[15]
  PIN t1[160]
    DIRECTION OUTPUT ;
    USE SIGNAL ;
    PORT
      LAYER M5 ;
        RECT  98.46 0 98.484 0.192 ;
    END
  END t1[160]
  PIN t1[161]
    DIRECTION OUTPUT ;
    USE SIGNAL ;
    PORT
      LAYER M5 ;
        RECT  98.7 0 98.724 0.192 ;
    END
  END t1[161]
  PIN t1[162]
    DIRECTION OUTPUT ;
    USE SIGNAL ;
    PORT
      LAYER M5 ;
        RECT  98.892 0 98.916 0.192 ;
    END
  END t1[162]
  PIN t1[163]
    DIRECTION OUTPUT ;
    USE SIGNAL ;
    PORT
      LAYER M5 ;
        RECT  99.132 0 99.156 0.192 ;
    END
  END t1[163]
  PIN t1[164]
    DIRECTION OUTPUT ;
    USE SIGNAL ;
    PORT
      LAYER M5 ;
        RECT  99.372 0 99.396 0.192 ;
    END
  END t1[164]
  PIN t1[165]
    DIRECTION OUTPUT ;
    USE SIGNAL ;
    PORT
      LAYER M5 ;
        RECT  99.612 0 99.636 0.192 ;
    END
  END t1[165]
  PIN t1[166]
    DIRECTION OUTPUT ;
    USE SIGNAL ;
    PORT
      LAYER M5 ;
        RECT  99.852 0 99.876 0.192 ;
    END
  END t1[166]
  PIN t1[167]
    DIRECTION OUTPUT ;
    USE SIGNAL ;
    PORT
      LAYER M5 ;
        RECT  100.092 0 100.116 0.192 ;
    END
  END t1[167]
  PIN t1[168]
    DIRECTION OUTPUT ;
    USE SIGNAL ;
    PORT
      LAYER M5 ;
        RECT  100.332 0 100.356 0.192 ;
    END
  END t1[168]
  PIN t1[169]
    DIRECTION OUTPUT ;
    USE SIGNAL ;
    PORT
      LAYER M5 ;
        RECT  100.524 0 100.548 0.192 ;
    END
  END t1[169]
  PIN t1[16]
    DIRECTION OUTPUT ;
    USE SIGNAL ;
    PORT
      LAYER M5 ;
        RECT  64.956 0 64.98 0.192 ;
    END
  END t1[16]
  PIN t1[170]
    DIRECTION OUTPUT ;
    USE SIGNAL ;
    PORT
      LAYER M5 ;
        RECT  100.764 0 100.788 0.192 ;
    END
  END t1[170]
  PIN t1[171]
    DIRECTION OUTPUT ;
    USE SIGNAL ;
    PORT
      LAYER M5 ;
        RECT  101.004 0 101.028 0.192 ;
    END
  END t1[171]
  PIN t1[172]
    DIRECTION OUTPUT ;
    USE SIGNAL ;
    PORT
      LAYER M5 ;
        RECT  101.244 0 101.268 0.192 ;
    END
  END t1[172]
  PIN t1[173]
    DIRECTION OUTPUT ;
    USE SIGNAL ;
    PORT
      LAYER M5 ;
        RECT  101.484 0 101.508 0.192 ;
    END
  END t1[173]
  PIN t1[174]
    DIRECTION OUTPUT ;
    USE SIGNAL ;
    PORT
      LAYER M5 ;
        RECT  101.724 0 101.748 0.192 ;
    END
  END t1[174]
  PIN t1[175]
    DIRECTION OUTPUT ;
    USE SIGNAL ;
    PORT
      LAYER M5 ;
        RECT  101.916 0 101.94 0.192 ;
    END
  END t1[175]
  PIN t1[176]
    DIRECTION OUTPUT ;
    USE SIGNAL ;
    PORT
      LAYER M5 ;
        RECT  102.156 0 102.18 0.192 ;
    END
  END t1[176]
  PIN t1[177]
    DIRECTION OUTPUT ;
    USE SIGNAL ;
    PORT
      LAYER M5 ;
        RECT  102.396 0 102.42 0.192 ;
    END
  END t1[177]
  PIN t1[178]
    DIRECTION OUTPUT ;
    USE SIGNAL ;
    PORT
      LAYER M5 ;
        RECT  102.636 0 102.66 0.192 ;
    END
  END t1[178]
  PIN t1[179]
    DIRECTION OUTPUT ;
    USE SIGNAL ;
    PORT
      LAYER M5 ;
        RECT  102.876 0 102.9 0.192 ;
    END
  END t1[179]
  PIN t1[17]
    DIRECTION OUTPUT ;
    USE SIGNAL ;
    PORT
      LAYER M5 ;
        RECT  65.148 0 65.172 0.192 ;
    END
  END t1[17]
  PIN t1[180]
    DIRECTION OUTPUT ;
    USE SIGNAL ;
    PORT
      LAYER M5 ;
        RECT  103.116 0 103.14 0.192 ;
    END
  END t1[180]
  PIN t1[181]
    DIRECTION OUTPUT ;
    USE SIGNAL ;
    PORT
      LAYER M5 ;
        RECT  103.356 0 103.38 0.192 ;
    END
  END t1[181]
  PIN t1[182]
    DIRECTION OUTPUT ;
    USE SIGNAL ;
    PORT
      LAYER M5 ;
        RECT  103.548 0 103.572 0.192 ;
    END
  END t1[182]
  PIN t1[183]
    DIRECTION OUTPUT ;
    USE SIGNAL ;
    PORT
      LAYER M5 ;
        RECT  103.788 0 103.812 0.192 ;
    END
  END t1[183]
  PIN t1[184]
    DIRECTION OUTPUT ;
    USE SIGNAL ;
    PORT
      LAYER M5 ;
        RECT  104.028 0 104.052 0.192 ;
    END
  END t1[184]
  PIN t1[185]
    DIRECTION OUTPUT ;
    USE SIGNAL ;
    PORT
      LAYER M5 ;
        RECT  104.268 0 104.292 0.192 ;
    END
  END t1[185]
  PIN t1[186]
    DIRECTION OUTPUT ;
    USE SIGNAL ;
    PORT
      LAYER M5 ;
        RECT  104.508 0 104.532 0.192 ;
    END
  END t1[186]
  PIN t1[187]
    DIRECTION OUTPUT ;
    USE SIGNAL ;
    PORT
      LAYER M5 ;
        RECT  104.748 0 104.772 0.192 ;
    END
  END t1[187]
  PIN t1[188]
    DIRECTION OUTPUT ;
    USE SIGNAL ;
    PORT
      LAYER M5 ;
        RECT  104.94 0 104.964 0.192 ;
    END
  END t1[188]
  PIN t1[189]
    DIRECTION OUTPUT ;
    USE SIGNAL ;
    PORT
      LAYER M5 ;
        RECT  105.18 0 105.204 0.192 ;
    END
  END t1[189]
  PIN t1[18]
    DIRECTION OUTPUT ;
    USE SIGNAL ;
    PORT
      LAYER M5 ;
        RECT  65.388 0 65.412 0.192 ;
    END
  END t1[18]
  PIN t1[190]
    DIRECTION OUTPUT ;
    USE SIGNAL ;
    PORT
      LAYER M5 ;
        RECT  105.42 0 105.444 0.192 ;
    END
  END t1[190]
  PIN t1[191]
    DIRECTION OUTPUT ;
    USE SIGNAL ;
    PORT
      LAYER M5 ;
        RECT  105.66 0 105.684 0.192 ;
    END
  END t1[191]
  PIN t1[192]
    DIRECTION OUTPUT ;
    USE SIGNAL ;
    PORT
      LAYER M5 ;
        RECT  105.9 0 105.924 0.192 ;
    END
  END t1[192]
  PIN t1[193]
    DIRECTION OUTPUT ;
    USE SIGNAL ;
    PORT
      LAYER M5 ;
        RECT  106.14 0 106.164 0.192 ;
    END
  END t1[193]
  PIN t1[194]
    DIRECTION OUTPUT ;
    USE SIGNAL ;
    PORT
      LAYER M5 ;
        RECT  106.38 0 106.404 0.192 ;
    END
  END t1[194]
  PIN t1[195]
    DIRECTION OUTPUT ;
    USE SIGNAL ;
    PORT
      LAYER M5 ;
        RECT  106.572 0 106.596 0.192 ;
    END
  END t1[195]
  PIN t1[196]
    DIRECTION OUTPUT ;
    USE SIGNAL ;
    PORT
      LAYER M5 ;
        RECT  106.812 0 106.836 0.192 ;
    END
  END t1[196]
  PIN t1[197]
    DIRECTION OUTPUT ;
    USE SIGNAL ;
    PORT
      LAYER M5 ;
        RECT  107.052 0 107.076 0.192 ;
    END
  END t1[197]
  PIN t1[198]
    DIRECTION OUTPUT ;
    USE SIGNAL ;
    PORT
      LAYER M5 ;
        RECT  107.292 0 107.316 0.192 ;
    END
  END t1[198]
  PIN t1[199]
    DIRECTION OUTPUT ;
    USE SIGNAL ;
    PORT
      LAYER M5 ;
        RECT  107.532 0 107.556 0.192 ;
    END
  END t1[199]
  PIN t1[19]
    DIRECTION OUTPUT ;
    USE SIGNAL ;
    PORT
      LAYER M5 ;
        RECT  65.628 0 65.652 0.192 ;
    END
  END t1[19]
  PIN t1[1]
    DIRECTION OUTPUT ;
    USE SIGNAL ;
    PORT
      LAYER M5 ;
        RECT  61.452 0 61.476 0.192 ;
    END
  END t1[1]
  PIN t1[200]
    DIRECTION OUTPUT ;
    USE SIGNAL ;
    PORT
      LAYER M5 ;
        RECT  107.772 0 107.796 0.192 ;
    END
  END t1[200]
  PIN t1[201]
    DIRECTION OUTPUT ;
    USE SIGNAL ;
    PORT
      LAYER M5 ;
        RECT  108.012 0 108.036 0.192 ;
    END
  END t1[201]
  PIN t1[202]
    DIRECTION OUTPUT ;
    USE SIGNAL ;
    PORT
      LAYER M5 ;
        RECT  108.204 0 108.228 0.192 ;
    END
  END t1[202]
  PIN t1[203]
    DIRECTION OUTPUT ;
    USE SIGNAL ;
    PORT
      LAYER M5 ;
        RECT  108.444 0 108.468 0.192 ;
    END
  END t1[203]
  PIN t1[204]
    DIRECTION OUTPUT ;
    USE SIGNAL ;
    PORT
      LAYER M5 ;
        RECT  108.684 0 108.708 0.192 ;
    END
  END t1[204]
  PIN t1[205]
    DIRECTION OUTPUT ;
    USE SIGNAL ;
    PORT
      LAYER M5 ;
        RECT  108.924 0 108.948 0.192 ;
    END
  END t1[205]
  PIN t1[206]
    DIRECTION OUTPUT ;
    USE SIGNAL ;
    PORT
      LAYER M5 ;
        RECT  109.164 0 109.188 0.192 ;
    END
  END t1[206]
  PIN t1[207]
    DIRECTION OUTPUT ;
    USE SIGNAL ;
    PORT
      LAYER M5 ;
        RECT  109.404 0 109.428 0.192 ;
    END
  END t1[207]
  PIN t1[208]
    DIRECTION OUTPUT ;
    USE SIGNAL ;
    PORT
      LAYER M5 ;
        RECT  109.596 0 109.62 0.192 ;
    END
  END t1[208]
  PIN t1[209]
    DIRECTION OUTPUT ;
    USE SIGNAL ;
    PORT
      LAYER M5 ;
        RECT  109.836 0 109.86 0.192 ;
    END
  END t1[209]
  PIN t1[20]
    DIRECTION OUTPUT ;
    USE SIGNAL ;
    PORT
      LAYER M5 ;
        RECT  65.868 0 65.892 0.192 ;
    END
  END t1[20]
  PIN t1[210]
    DIRECTION OUTPUT ;
    USE SIGNAL ;
    PORT
      LAYER M5 ;
        RECT  110.076 0 110.1 0.192 ;
    END
  END t1[210]
  PIN t1[211]
    DIRECTION OUTPUT ;
    USE SIGNAL ;
    PORT
      LAYER M5 ;
        RECT  110.316 0 110.34 0.192 ;
    END
  END t1[211]
  PIN t1[212]
    DIRECTION OUTPUT ;
    USE SIGNAL ;
    PORT
      LAYER M5 ;
        RECT  110.556 0 110.58 0.192 ;
    END
  END t1[212]
  PIN t1[213]
    DIRECTION OUTPUT ;
    USE SIGNAL ;
    PORT
      LAYER M5 ;
        RECT  110.796 0 110.82 0.192 ;
    END
  END t1[213]
  PIN t1[214]
    DIRECTION OUTPUT ;
    USE SIGNAL ;
    PORT
      LAYER M5 ;
        RECT  111.036 0 111.06 0.192 ;
    END
  END t1[214]
  PIN t1[215]
    DIRECTION OUTPUT ;
    USE SIGNAL ;
    PORT
      LAYER M5 ;
        RECT  111.228 0 111.252 0.192 ;
    END
  END t1[215]
  PIN t1[216]
    DIRECTION OUTPUT ;
    USE SIGNAL ;
    PORT
      LAYER M5 ;
        RECT  111.468 0 111.492 0.192 ;
    END
  END t1[216]
  PIN t1[217]
    DIRECTION OUTPUT ;
    USE SIGNAL ;
    PORT
      LAYER M5 ;
        RECT  111.708 0 111.732 0.192 ;
    END
  END t1[217]
  PIN t1[218]
    DIRECTION OUTPUT ;
    USE SIGNAL ;
    PORT
      LAYER M5 ;
        RECT  111.948 0 111.972 0.192 ;
    END
  END t1[218]
  PIN t1[219]
    DIRECTION OUTPUT ;
    USE SIGNAL ;
    PORT
      LAYER M5 ;
        RECT  112.188 0 112.212 0.192 ;
    END
  END t1[219]
  PIN t1[21]
    DIRECTION OUTPUT ;
    USE SIGNAL ;
    PORT
      LAYER M5 ;
        RECT  66.108 0 66.132 0.192 ;
    END
  END t1[21]
  PIN t1[220]
    DIRECTION OUTPUT ;
    USE SIGNAL ;
    PORT
      LAYER M5 ;
        RECT  112.428 0 112.452 0.192 ;
    END
  END t1[220]
  PIN t1[221]
    DIRECTION OUTPUT ;
    USE SIGNAL ;
    PORT
      LAYER M5 ;
        RECT  112.62 0 112.644 0.192 ;
    END
  END t1[221]
  PIN t1[222]
    DIRECTION OUTPUT ;
    USE SIGNAL ;
    PORT
      LAYER M5 ;
        RECT  112.86 0 112.884 0.192 ;
    END
  END t1[222]
  PIN t1[223]
    DIRECTION OUTPUT ;
    USE SIGNAL ;
    PORT
      LAYER M5 ;
        RECT  113.1 0 113.124 0.192 ;
    END
  END t1[223]
  PIN t1[224]
    DIRECTION OUTPUT ;
    USE SIGNAL ;
    PORT
      LAYER M5 ;
        RECT  113.34 0 113.364 0.192 ;
    END
  END t1[224]
  PIN t1[225]
    DIRECTION OUTPUT ;
    USE SIGNAL ;
    PORT
      LAYER M5 ;
        RECT  113.58 0 113.604 0.192 ;
    END
  END t1[225]
  PIN t1[226]
    DIRECTION OUTPUT ;
    USE SIGNAL ;
    PORT
      LAYER M5 ;
        RECT  113.82 0 113.844 0.192 ;
    END
  END t1[226]
  PIN t1[227]
    DIRECTION OUTPUT ;
    USE SIGNAL ;
    PORT
      LAYER M5 ;
        RECT  114.06 0 114.084 0.192 ;
    END
  END t1[227]
  PIN t1[228]
    DIRECTION OUTPUT ;
    USE SIGNAL ;
    PORT
      LAYER M5 ;
        RECT  114.252 0 114.276 0.192 ;
    END
  END t1[228]
  PIN t1[229]
    DIRECTION OUTPUT ;
    USE SIGNAL ;
    PORT
      LAYER M5 ;
        RECT  114.492 0 114.516 0.192 ;
    END
  END t1[229]
  PIN t1[22]
    DIRECTION OUTPUT ;
    USE SIGNAL ;
    PORT
      LAYER M5 ;
        RECT  66.348 0 66.372 0.192 ;
    END
  END t1[22]
  PIN t1[230]
    DIRECTION OUTPUT ;
    USE SIGNAL ;
    PORT
      LAYER M5 ;
        RECT  114.732 0 114.756 0.192 ;
    END
  END t1[230]
  PIN t1[231]
    DIRECTION OUTPUT ;
    USE SIGNAL ;
    PORT
      LAYER M5 ;
        RECT  114.972 0 114.996 0.192 ;
    END
  END t1[231]
  PIN t1[232]
    DIRECTION OUTPUT ;
    USE SIGNAL ;
    PORT
      LAYER M5 ;
        RECT  115.212 0 115.236 0.192 ;
    END
  END t1[232]
  PIN t1[233]
    DIRECTION OUTPUT ;
    USE SIGNAL ;
    PORT
      LAYER M5 ;
        RECT  115.452 0 115.476 0.192 ;
    END
  END t1[233]
  PIN t1[234]
    DIRECTION OUTPUT ;
    USE SIGNAL ;
    PORT
      LAYER M5 ;
        RECT  115.644 0 115.668 0.192 ;
    END
  END t1[234]
  PIN t1[235]
    DIRECTION OUTPUT ;
    USE SIGNAL ;
    PORT
      LAYER M5 ;
        RECT  115.884 0 115.908 0.192 ;
    END
  END t1[235]
  PIN t1[236]
    DIRECTION OUTPUT ;
    USE SIGNAL ;
    PORT
      LAYER M5 ;
        RECT  116.124 0 116.148 0.192 ;
    END
  END t1[236]
  PIN t1[237]
    DIRECTION OUTPUT ;
    USE SIGNAL ;
    PORT
      LAYER M5 ;
        RECT  116.364 0 116.388 0.192 ;
    END
  END t1[237]
  PIN t1[238]
    DIRECTION OUTPUT ;
    USE SIGNAL ;
    PORT
      LAYER M5 ;
        RECT  116.604 0 116.628 0.192 ;
    END
  END t1[238]
  PIN t1[239]
    DIRECTION OUTPUT ;
    USE SIGNAL ;
    PORT
      LAYER M5 ;
        RECT  116.844 0 116.868 0.192 ;
    END
  END t1[239]
  PIN t1[23]
    DIRECTION OUTPUT ;
    USE SIGNAL ;
    PORT
      LAYER M5 ;
        RECT  66.588 0 66.612 0.192 ;
    END
  END t1[23]
  PIN t1[240]
    DIRECTION OUTPUT ;
    USE SIGNAL ;
    PORT
      LAYER M5 ;
        RECT  117.084 0 117.108 0.192 ;
    END
  END t1[240]
  PIN t1[241]
    DIRECTION OUTPUT ;
    USE SIGNAL ;
    PORT
      LAYER M5 ;
        RECT  117.276 0 117.3 0.192 ;
    END
  END t1[241]
  PIN t1[242]
    DIRECTION OUTPUT ;
    USE SIGNAL ;
    PORT
      LAYER M5 ;
        RECT  117.516 0 117.54 0.192 ;
    END
  END t1[242]
  PIN t1[243]
    DIRECTION OUTPUT ;
    USE SIGNAL ;
    PORT
      LAYER M5 ;
        RECT  117.756 0 117.78 0.192 ;
    END
  END t1[243]
  PIN t1[244]
    DIRECTION OUTPUT ;
    USE SIGNAL ;
    PORT
      LAYER M5 ;
        RECT  117.996 0 118.02 0.192 ;
    END
  END t1[244]
  PIN t1[245]
    DIRECTION OUTPUT ;
    USE SIGNAL ;
    PORT
      LAYER M5 ;
        RECT  118.236 0 118.26 0.192 ;
    END
  END t1[245]
  PIN t1[246]
    DIRECTION OUTPUT ;
    USE SIGNAL ;
    PORT
      LAYER M5 ;
        RECT  118.476 0 118.5 0.192 ;
    END
  END t1[246]
  PIN t1[247]
    DIRECTION OUTPUT ;
    USE SIGNAL ;
    PORT
      LAYER M5 ;
        RECT  118.716 0 118.74 0.192 ;
    END
  END t1[247]
  PIN t1[248]
    DIRECTION OUTPUT ;
    USE SIGNAL ;
    PORT
      LAYER M5 ;
        RECT  118.908 0 118.932 0.192 ;
    END
  END t1[248]
  PIN t1[249]
    DIRECTION OUTPUT ;
    USE SIGNAL ;
    PORT
      LAYER M5 ;
        RECT  119.148 0 119.172 0.192 ;
    END
  END t1[249]
  PIN t1[24]
    DIRECTION OUTPUT ;
    USE SIGNAL ;
    PORT
      LAYER M5 ;
        RECT  66.78 0 66.804 0.192 ;
    END
  END t1[24]
  PIN t1[250]
    DIRECTION OUTPUT ;
    USE SIGNAL ;
    PORT
      LAYER M5 ;
        RECT  119.388 0 119.412 0.192 ;
    END
  END t1[250]
  PIN t1[251]
    DIRECTION OUTPUT ;
    USE SIGNAL ;
    PORT
      LAYER M5 ;
        RECT  119.628 0 119.652 0.192 ;
    END
  END t1[251]
  PIN t1[252]
    DIRECTION OUTPUT ;
    USE SIGNAL ;
    PORT
      LAYER M5 ;
        RECT  119.868 0 119.892 0.192 ;
    END
  END t1[252]
  PIN t1[253]
    DIRECTION OUTPUT ;
    USE SIGNAL ;
    PORT
      LAYER M5 ;
        RECT  120.108 0 120.132 0.192 ;
    END
  END t1[253]
  PIN t1[254]
    DIRECTION OUTPUT ;
    USE SIGNAL ;
    PORT
      LAYER M5 ;
        RECT  120.3 0 120.324 0.192 ;
    END
  END t1[254]
  PIN t1[255]
    DIRECTION OUTPUT ;
    USE SIGNAL ;
    PORT
      LAYER M5 ;
        RECT  120.54 0 120.564 0.192 ;
    END
  END t1[255]
  PIN t1[256]
    DIRECTION OUTPUT ;
    USE SIGNAL ;
    PORT
      LAYER M5 ;
        RECT  120.78 0 120.804 0.192 ;
    END
  END t1[256]
  PIN t1[257]
    DIRECTION OUTPUT ;
    USE SIGNAL ;
    PORT
      LAYER M5 ;
        RECT  121.02 0 121.044 0.192 ;
    END
  END t1[257]
  PIN t1[258]
    DIRECTION OUTPUT ;
    USE SIGNAL ;
    PORT
      LAYER M5 ;
        RECT  121.26 0 121.284 0.192 ;
    END
  END t1[258]
  PIN t1[259]
    DIRECTION OUTPUT ;
    USE SIGNAL ;
    PORT
      LAYER M5 ;
        RECT  121.5 0 121.524 0.192 ;
    END
  END t1[259]
  PIN t1[25]
    DIRECTION OUTPUT ;
    USE SIGNAL ;
    PORT
      LAYER M5 ;
        RECT  67.02 0 67.044 0.192 ;
    END
  END t1[25]
  PIN t1[260]
    DIRECTION OUTPUT ;
    USE SIGNAL ;
    PORT
      LAYER M5 ;
        RECT  121.74 0 121.764 0.192 ;
    END
  END t1[260]
  PIN t1[261]
    DIRECTION OUTPUT ;
    USE SIGNAL ;
    PORT
      LAYER M5 ;
        RECT  121.932 0 121.956 0.192 ;
    END
  END t1[261]
  PIN t1[262]
    DIRECTION OUTPUT ;
    USE SIGNAL ;
    PORT
      LAYER M5 ;
        RECT  122.172 0 122.196 0.192 ;
    END
  END t1[262]
  PIN t1[263]
    DIRECTION OUTPUT ;
    USE SIGNAL ;
    PORT
      LAYER M5 ;
        RECT  122.412 0 122.436 0.192 ;
    END
  END t1[263]
  PIN t1[264]
    DIRECTION OUTPUT ;
    USE SIGNAL ;
    PORT
      LAYER M5 ;
        RECT  122.652 0 122.676 0.192 ;
    END
  END t1[264]
  PIN t1[265]
    DIRECTION OUTPUT ;
    USE SIGNAL ;
    PORT
      LAYER M5 ;
        RECT  122.892 0 122.916 0.192 ;
    END
  END t1[265]
  PIN t1[266]
    DIRECTION OUTPUT ;
    USE SIGNAL ;
    PORT
      LAYER M5 ;
        RECT  123.132 0 123.156 0.192 ;
    END
  END t1[266]
  PIN t1[267]
    DIRECTION OUTPUT ;
    USE SIGNAL ;
    PORT
      LAYER M5 ;
        RECT  123.324 0 123.348 0.192 ;
    END
  END t1[267]
  PIN t1[268]
    DIRECTION OUTPUT ;
    USE SIGNAL ;
    PORT
      LAYER M5 ;
        RECT  123.564 0 123.588 0.192 ;
    END
  END t1[268]
  PIN t1[269]
    DIRECTION OUTPUT ;
    USE SIGNAL ;
    PORT
      LAYER M5 ;
        RECT  123.804 0 123.828 0.192 ;
    END
  END t1[269]
  PIN t1[26]
    DIRECTION OUTPUT ;
    USE SIGNAL ;
    PORT
      LAYER M5 ;
        RECT  67.26 0 67.284 0.192 ;
    END
  END t1[26]
  PIN t1[270]
    DIRECTION OUTPUT ;
    USE SIGNAL ;
    PORT
      LAYER M5 ;
        RECT  124.044 0 124.068 0.192 ;
    END
  END t1[270]
  PIN t1[271]
    DIRECTION OUTPUT ;
    USE SIGNAL ;
    PORT
      LAYER M5 ;
        RECT  124.284 0 124.308 0.192 ;
    END
  END t1[271]
  PIN t1[272]
    DIRECTION OUTPUT ;
    USE SIGNAL ;
    PORT
      LAYER M5 ;
        RECT  124.524 0 124.548 0.192 ;
    END
  END t1[272]
  PIN t1[273]
    DIRECTION OUTPUT ;
    USE SIGNAL ;
    PORT
      LAYER M5 ;
        RECT  124.764 0 124.788 0.192 ;
    END
  END t1[273]
  PIN t1[274]
    DIRECTION OUTPUT ;
    USE SIGNAL ;
    PORT
      LAYER M5 ;
        RECT  124.956 0 124.98 0.192 ;
    END
  END t1[274]
  PIN t1[275]
    DIRECTION OUTPUT ;
    USE SIGNAL ;
    PORT
      LAYER M5 ;
        RECT  125.196 0 125.22 0.192 ;
    END
  END t1[275]
  PIN t1[276]
    DIRECTION OUTPUT ;
    USE SIGNAL ;
    PORT
      LAYER M5 ;
        RECT  125.436 0 125.46 0.192 ;
    END
  END t1[276]
  PIN t1[277]
    DIRECTION OUTPUT ;
    USE SIGNAL ;
    PORT
      LAYER M5 ;
        RECT  125.676 0 125.7 0.192 ;
    END
  END t1[277]
  PIN t1[278]
    DIRECTION OUTPUT ;
    USE SIGNAL ;
    PORT
      LAYER M5 ;
        RECT  125.916 0 125.94 0.192 ;
    END
  END t1[278]
  PIN t1[279]
    DIRECTION OUTPUT ;
    USE SIGNAL ;
    PORT
      LAYER M5 ;
        RECT  126.156 0 126.18 0.192 ;
    END
  END t1[279]
  PIN t1[27]
    DIRECTION OUTPUT ;
    USE SIGNAL ;
    PORT
      LAYER M5 ;
        RECT  67.5 0 67.524 0.192 ;
    END
  END t1[27]
  PIN t1[280]
    DIRECTION OUTPUT ;
    USE SIGNAL ;
    PORT
      LAYER M5 ;
        RECT  126.396 0 126.42 0.192 ;
    END
  END t1[280]
  PIN t1[281]
    DIRECTION OUTPUT ;
    USE SIGNAL ;
    PORT
      LAYER M5 ;
        RECT  126.588 0 126.612 0.192 ;
    END
  END t1[281]
  PIN t1[282]
    DIRECTION OUTPUT ;
    USE SIGNAL ;
    PORT
      LAYER M5 ;
        RECT  126.828 0 126.852 0.192 ;
    END
  END t1[282]
  PIN t1[283]
    DIRECTION OUTPUT ;
    USE SIGNAL ;
    PORT
      LAYER M5 ;
        RECT  127.068 0 127.092 0.192 ;
    END
  END t1[283]
  PIN t1[284]
    DIRECTION OUTPUT ;
    USE SIGNAL ;
    PORT
      LAYER M5 ;
        RECT  127.308 0 127.332 0.192 ;
    END
  END t1[284]
  PIN t1[285]
    DIRECTION OUTPUT ;
    USE SIGNAL ;
    PORT
      LAYER M5 ;
        RECT  127.548 0 127.572 0.192 ;
    END
  END t1[285]
  PIN t1[286]
    DIRECTION OUTPUT ;
    USE SIGNAL ;
    PORT
      LAYER M5 ;
        RECT  127.788 0 127.812 0.192 ;
    END
  END t1[286]
  PIN t1[287]
    DIRECTION OUTPUT ;
    USE SIGNAL ;
    PORT
      LAYER M5 ;
        RECT  127.98 0 128.004 0.192 ;
    END
  END t1[287]
  PIN t1[288]
    DIRECTION OUTPUT ;
    USE SIGNAL ;
    PORT
      LAYER M5 ;
        RECT  128.22 0 128.244 0.192 ;
    END
  END t1[288]
  PIN t1[289]
    DIRECTION OUTPUT ;
    USE SIGNAL ;
    PORT
      LAYER M5 ;
        RECT  128.46 0 128.484 0.192 ;
    END
  END t1[289]
  PIN t1[28]
    DIRECTION OUTPUT ;
    USE SIGNAL ;
    PORT
      LAYER M5 ;
        RECT  67.74 0 67.764 0.192 ;
    END
  END t1[28]
  PIN t1[290]
    DIRECTION OUTPUT ;
    USE SIGNAL ;
    PORT
      LAYER M5 ;
        RECT  128.7 0 128.724 0.192 ;
    END
  END t1[290]
  PIN t1[291]
    DIRECTION OUTPUT ;
    USE SIGNAL ;
    PORT
      LAYER M5 ;
        RECT  128.94 0 128.964 0.192 ;
    END
  END t1[291]
  PIN t1[292]
    DIRECTION OUTPUT ;
    USE SIGNAL ;
    PORT
      LAYER M5 ;
        RECT  129.18 0 129.204 0.192 ;
    END
  END t1[292]
  PIN t1[293]
    DIRECTION OUTPUT ;
    USE SIGNAL ;
    PORT
      LAYER M5 ;
        RECT  129.42 0 129.444 0.192 ;
    END
  END t1[293]
  PIN t1[294]
    DIRECTION OUTPUT ;
    USE SIGNAL ;
    PORT
      LAYER M5 ;
        RECT  129.612 0 129.636 0.192 ;
    END
  END t1[294]
  PIN t1[295]
    DIRECTION OUTPUT ;
    USE SIGNAL ;
    PORT
      LAYER M5 ;
        RECT  129.852 0 129.876 0.192 ;
    END
  END t1[295]
  PIN t1[296]
    DIRECTION OUTPUT ;
    USE SIGNAL ;
    PORT
      LAYER M5 ;
        RECT  130.092 0 130.116 0.192 ;
    END
  END t1[296]
  PIN t1[297]
    DIRECTION OUTPUT ;
    USE SIGNAL ;
    PORT
      LAYER M5 ;
        RECT  130.332 0 130.356 0.192 ;
    END
  END t1[297]
  PIN t1[298]
    DIRECTION OUTPUT ;
    USE SIGNAL ;
    PORT
      LAYER M5 ;
        RECT  130.572 0 130.596 0.192 ;
    END
  END t1[298]
  PIN t1[299]
    DIRECTION OUTPUT ;
    USE SIGNAL ;
    PORT
      LAYER M5 ;
        RECT  130.812 0 130.836 0.192 ;
    END
  END t1[299]
  PIN t1[29]
    DIRECTION OUTPUT ;
    USE SIGNAL ;
    PORT
      LAYER M5 ;
        RECT  67.98 0 68.004 0.192 ;
    END
  END t1[29]
  PIN t1[2]
    DIRECTION OUTPUT ;
    USE SIGNAL ;
    PORT
      LAYER M5 ;
        RECT  61.692 0 61.716 0.192 ;
    END
  END t1[2]
  PIN t1[300]
    DIRECTION OUTPUT ;
    USE SIGNAL ;
    PORT
      LAYER M5 ;
        RECT  131.004 0 131.028 0.192 ;
    END
  END t1[300]
  PIN t1[301]
    DIRECTION OUTPUT ;
    USE SIGNAL ;
    PORT
      LAYER M5 ;
        RECT  131.244 0 131.268 0.192 ;
    END
  END t1[301]
  PIN t1[302]
    DIRECTION OUTPUT ;
    USE SIGNAL ;
    PORT
      LAYER M5 ;
        RECT  131.484 0 131.508 0.192 ;
    END
  END t1[302]
  PIN t1[303]
    DIRECTION OUTPUT ;
    USE SIGNAL ;
    PORT
      LAYER M5 ;
        RECT  131.724 0 131.748 0.192 ;
    END
  END t1[303]
  PIN t1[304]
    DIRECTION OUTPUT ;
    USE SIGNAL ;
    PORT
      LAYER M5 ;
        RECT  131.964 0 131.988 0.192 ;
    END
  END t1[304]
  PIN t1[305]
    DIRECTION OUTPUT ;
    USE SIGNAL ;
    PORT
      LAYER M5 ;
        RECT  132.204 0 132.228 0.192 ;
    END
  END t1[305]
  PIN t1[306]
    DIRECTION OUTPUT ;
    USE SIGNAL ;
    PORT
      LAYER M5 ;
        RECT  132.444 0 132.468 0.192 ;
    END
  END t1[306]
  PIN t1[307]
    DIRECTION OUTPUT ;
    USE SIGNAL ;
    PORT
      LAYER M5 ;
        RECT  132.636 0 132.66 0.192 ;
    END
  END t1[307]
  PIN t1[308]
    DIRECTION OUTPUT ;
    USE SIGNAL ;
    PORT
      LAYER M5 ;
        RECT  132.876 0 132.9 0.192 ;
    END
  END t1[308]
  PIN t1[309]
    DIRECTION OUTPUT ;
    USE SIGNAL ;
    PORT
      LAYER M5 ;
        RECT  133.116 0 133.14 0.192 ;
    END
  END t1[309]
  PIN t1[30]
    DIRECTION OUTPUT ;
    USE SIGNAL ;
    PORT
      LAYER M5 ;
        RECT  68.172 0 68.196 0.192 ;
    END
  END t1[30]
  PIN t1[310]
    DIRECTION OUTPUT ;
    USE SIGNAL ;
    PORT
      LAYER M5 ;
        RECT  133.356 0 133.38 0.192 ;
    END
  END t1[310]
  PIN t1[311]
    DIRECTION OUTPUT ;
    USE SIGNAL ;
    PORT
      LAYER M5 ;
        RECT  133.596 0 133.62 0.192 ;
    END
  END t1[311]
  PIN t1[312]
    DIRECTION OUTPUT ;
    USE SIGNAL ;
    PORT
      LAYER M5 ;
        RECT  133.836 0 133.86 0.192 ;
    END
  END t1[312]
  PIN t1[313]
    DIRECTION OUTPUT ;
    USE SIGNAL ;
    PORT
      LAYER M5 ;
        RECT  134.028 0 134.052 0.192 ;
    END
  END t1[313]
  PIN t1[314]
    DIRECTION OUTPUT ;
    USE SIGNAL ;
    PORT
      LAYER M5 ;
        RECT  134.268 0 134.292 0.192 ;
    END
  END t1[314]
  PIN t1[315]
    DIRECTION OUTPUT ;
    USE SIGNAL ;
    PORT
      LAYER M5 ;
        RECT  134.508 0 134.532 0.192 ;
    END
  END t1[315]
  PIN t1[316]
    DIRECTION OUTPUT ;
    USE SIGNAL ;
    PORT
      LAYER M5 ;
        RECT  134.748 0 134.772 0.192 ;
    END
  END t1[316]
  PIN t1[317]
    DIRECTION OUTPUT ;
    USE SIGNAL ;
    PORT
      LAYER M5 ;
        RECT  134.988 0 135.012 0.192 ;
    END
  END t1[317]
  PIN t1[318]
    DIRECTION OUTPUT ;
    USE SIGNAL ;
    PORT
      LAYER M5 ;
        RECT  135.228 0 135.252 0.192 ;
    END
  END t1[318]
  PIN t1[319]
    DIRECTION OUTPUT ;
    USE SIGNAL ;
    PORT
      LAYER M5 ;
        RECT  135.468 0 135.492 0.192 ;
    END
  END t1[319]
  PIN t1[31]
    DIRECTION OUTPUT ;
    USE SIGNAL ;
    PORT
      LAYER M5 ;
        RECT  68.412 0 68.436 0.192 ;
    END
  END t1[31]
  PIN t1[320]
    DIRECTION OUTPUT ;
    USE SIGNAL ;
    PORT
      LAYER M5 ;
        RECT  135.66 0 135.684 0.192 ;
    END
  END t1[320]
  PIN t1[321]
    DIRECTION OUTPUT ;
    USE SIGNAL ;
    PORT
      LAYER M5 ;
        RECT  135.9 0 135.924 0.192 ;
    END
  END t1[321]
  PIN t1[322]
    DIRECTION OUTPUT ;
    USE SIGNAL ;
    PORT
      LAYER M5 ;
        RECT  136.14 0 136.164 0.192 ;
    END
  END t1[322]
  PIN t1[323]
    DIRECTION OUTPUT ;
    USE SIGNAL ;
    PORT
      LAYER M5 ;
        RECT  136.38 0 136.404 0.192 ;
    END
  END t1[323]
  PIN t1[324]
    DIRECTION OUTPUT ;
    USE SIGNAL ;
    PORT
      LAYER M5 ;
        RECT  136.62 0 136.644 0.192 ;
    END
  END t1[324]
  PIN t1[325]
    DIRECTION OUTPUT ;
    USE SIGNAL ;
    PORT
      LAYER M5 ;
        RECT  136.86 0 136.884 0.192 ;
    END
  END t1[325]
  PIN t1[326]
    DIRECTION OUTPUT ;
    USE SIGNAL ;
    PORT
      LAYER M5 ;
        RECT  137.1 0 137.124 0.192 ;
    END
  END t1[326]
  PIN t1[327]
    DIRECTION OUTPUT ;
    USE SIGNAL ;
    PORT
      LAYER M5 ;
        RECT  137.292 0 137.316 0.192 ;
    END
  END t1[327]
  PIN t1[328]
    DIRECTION OUTPUT ;
    USE SIGNAL ;
    PORT
      LAYER M5 ;
        RECT  137.532 0 137.556 0.192 ;
    END
  END t1[328]
  PIN t1[329]
    DIRECTION OUTPUT ;
    USE SIGNAL ;
    PORT
      LAYER M5 ;
        RECT  137.772 0 137.796 0.192 ;
    END
  END t1[329]
  PIN t1[32]
    DIRECTION OUTPUT ;
    USE SIGNAL ;
    PORT
      LAYER M5 ;
        RECT  68.652 0 68.676 0.192 ;
    END
  END t1[32]
  PIN t1[330]
    DIRECTION OUTPUT ;
    USE SIGNAL ;
    PORT
      LAYER M5 ;
        RECT  138.012 0 138.036 0.192 ;
    END
  END t1[330]
  PIN t1[331]
    DIRECTION OUTPUT ;
    USE SIGNAL ;
    PORT
      LAYER M5 ;
        RECT  138.252 0 138.276 0.192 ;
    END
  END t1[331]
  PIN t1[332]
    DIRECTION OUTPUT ;
    USE SIGNAL ;
    PORT
      LAYER M5 ;
        RECT  138.492 0 138.516 0.192 ;
    END
  END t1[332]
  PIN t1[333]
    DIRECTION OUTPUT ;
    USE SIGNAL ;
    PORT
      LAYER M5 ;
        RECT  138.684 0 138.708 0.192 ;
    END
  END t1[333]
  PIN t1[334]
    DIRECTION OUTPUT ;
    USE SIGNAL ;
    PORT
      LAYER M5 ;
        RECT  138.924 0 138.948 0.192 ;
    END
  END t1[334]
  PIN t1[335]
    DIRECTION OUTPUT ;
    USE SIGNAL ;
    PORT
      LAYER M5 ;
        RECT  139.164 0 139.188 0.192 ;
    END
  END t1[335]
  PIN t1[336]
    DIRECTION OUTPUT ;
    USE SIGNAL ;
    PORT
      LAYER M5 ;
        RECT  139.404 0 139.428 0.192 ;
    END
  END t1[336]
  PIN t1[337]
    DIRECTION OUTPUT ;
    USE SIGNAL ;
    PORT
      LAYER M5 ;
        RECT  139.644 0 139.668 0.192 ;
    END
  END t1[337]
  PIN t1[338]
    DIRECTION OUTPUT ;
    USE SIGNAL ;
    PORT
      LAYER M5 ;
        RECT  139.884 0 139.908 0.192 ;
    END
  END t1[338]
  PIN t1[339]
    DIRECTION OUTPUT ;
    USE SIGNAL ;
    PORT
      LAYER M5 ;
        RECT  140.124 0 140.148 0.192 ;
    END
  END t1[339]
  PIN t1[33]
    DIRECTION OUTPUT ;
    USE SIGNAL ;
    PORT
      LAYER M5 ;
        RECT  68.892 0 68.916 0.192 ;
    END
  END t1[33]
  PIN t1[340]
    DIRECTION OUTPUT ;
    USE SIGNAL ;
    PORT
      LAYER M5 ;
        RECT  140.316 0 140.34 0.192 ;
    END
  END t1[340]
  PIN t1[341]
    DIRECTION OUTPUT ;
    USE SIGNAL ;
    PORT
      LAYER M5 ;
        RECT  140.556 0 140.58 0.192 ;
    END
  END t1[341]
  PIN t1[342]
    DIRECTION OUTPUT ;
    USE SIGNAL ;
    PORT
      LAYER M5 ;
        RECT  140.796 0 140.82 0.192 ;
    END
  END t1[342]
  PIN t1[343]
    DIRECTION OUTPUT ;
    USE SIGNAL ;
    PORT
      LAYER M5 ;
        RECT  141.036 0 141.06 0.192 ;
    END
  END t1[343]
  PIN t1[344]
    DIRECTION OUTPUT ;
    USE SIGNAL ;
    PORT
      LAYER M5 ;
        RECT  141.276 0 141.3 0.192 ;
    END
  END t1[344]
  PIN t1[345]
    DIRECTION OUTPUT ;
    USE SIGNAL ;
    PORT
      LAYER M5 ;
        RECT  141.516 0 141.54 0.192 ;
    END
  END t1[345]
  PIN t1[346]
    DIRECTION OUTPUT ;
    USE SIGNAL ;
    PORT
      LAYER M5 ;
        RECT  141.708 0 141.732 0.192 ;
    END
  END t1[346]
  PIN t1[347]
    DIRECTION OUTPUT ;
    USE SIGNAL ;
    PORT
      LAYER M5 ;
        RECT  141.948 0 141.972 0.192 ;
    END
  END t1[347]
  PIN t1[348]
    DIRECTION OUTPUT ;
    USE SIGNAL ;
    PORT
      LAYER M5 ;
        RECT  142.188 0 142.212 0.192 ;
    END
  END t1[348]
  PIN t1[349]
    DIRECTION OUTPUT ;
    USE SIGNAL ;
    PORT
      LAYER M5 ;
        RECT  142.428 0 142.452 0.192 ;
    END
  END t1[349]
  PIN t1[34]
    DIRECTION OUTPUT ;
    USE SIGNAL ;
    PORT
      LAYER M5 ;
        RECT  69.132 0 69.156 0.192 ;
    END
  END t1[34]
  PIN t1[350]
    DIRECTION OUTPUT ;
    USE SIGNAL ;
    PORT
      LAYER M5 ;
        RECT  142.668 0 142.692 0.192 ;
    END
  END t1[350]
  PIN t1[351]
    DIRECTION OUTPUT ;
    USE SIGNAL ;
    PORT
      LAYER M5 ;
        RECT  142.908 0 142.932 0.192 ;
    END
  END t1[351]
  PIN t1[352]
    DIRECTION OUTPUT ;
    USE SIGNAL ;
    PORT
      LAYER M5 ;
        RECT  143.148 0 143.172 0.192 ;
    END
  END t1[352]
  PIN t1[353]
    DIRECTION OUTPUT ;
    USE SIGNAL ;
    PORT
      LAYER M5 ;
        RECT  143.34 0 143.364 0.192 ;
    END
  END t1[353]
  PIN t1[354]
    DIRECTION OUTPUT ;
    USE SIGNAL ;
    PORT
      LAYER M5 ;
        RECT  143.58 0 143.604 0.192 ;
    END
  END t1[354]
  PIN t1[355]
    DIRECTION OUTPUT ;
    USE SIGNAL ;
    PORT
      LAYER M5 ;
        RECT  143.82 0 143.844 0.192 ;
    END
  END t1[355]
  PIN t1[356]
    DIRECTION OUTPUT ;
    USE SIGNAL ;
    PORT
      LAYER M5 ;
        RECT  144.06 0 144.084 0.192 ;
    END
  END t1[356]
  PIN t1[357]
    DIRECTION OUTPUT ;
    USE SIGNAL ;
    PORT
      LAYER M5 ;
        RECT  144.3 0 144.324 0.192 ;
    END
  END t1[357]
  PIN t1[358]
    DIRECTION OUTPUT ;
    USE SIGNAL ;
    PORT
      LAYER M5 ;
        RECT  144.54 0 144.564 0.192 ;
    END
  END t1[358]
  PIN t1[359]
    DIRECTION OUTPUT ;
    USE SIGNAL ;
    PORT
      LAYER M5 ;
        RECT  144.78 0 144.804 0.192 ;
    END
  END t1[359]
  PIN t1[35]
    DIRECTION OUTPUT ;
    USE SIGNAL ;
    PORT
      LAYER M5 ;
        RECT  69.372 0 69.396 0.192 ;
    END
  END t1[35]
  PIN t1[360]
    DIRECTION OUTPUT ;
    USE SIGNAL ;
    PORT
      LAYER M5 ;
        RECT  144.972 0 144.996 0.192 ;
    END
  END t1[360]
  PIN t1[361]
    DIRECTION OUTPUT ;
    USE SIGNAL ;
    PORT
      LAYER M5 ;
        RECT  145.212 0 145.236 0.192 ;
    END
  END t1[361]
  PIN t1[362]
    DIRECTION OUTPUT ;
    USE SIGNAL ;
    PORT
      LAYER M5 ;
        RECT  145.452 0 145.476 0.192 ;
    END
  END t1[362]
  PIN t1[363]
    DIRECTION OUTPUT ;
    USE SIGNAL ;
    PORT
      LAYER M5 ;
        RECT  145.692 0 145.716 0.192 ;
    END
  END t1[363]
  PIN t1[364]
    DIRECTION OUTPUT ;
    USE SIGNAL ;
    PORT
      LAYER M5 ;
        RECT  145.932 0 145.956 0.192 ;
    END
  END t1[364]
  PIN t1[365]
    DIRECTION OUTPUT ;
    USE SIGNAL ;
    PORT
      LAYER M5 ;
        RECT  146.172 0 146.196 0.192 ;
    END
  END t1[365]
  PIN t1[366]
    DIRECTION OUTPUT ;
    USE SIGNAL ;
    PORT
      LAYER M5 ;
        RECT  146.364 0 146.388 0.192 ;
    END
  END t1[366]
  PIN t1[367]
    DIRECTION OUTPUT ;
    USE SIGNAL ;
    PORT
      LAYER M5 ;
        RECT  146.604 0 146.628 0.192 ;
    END
  END t1[367]
  PIN t1[368]
    DIRECTION OUTPUT ;
    USE SIGNAL ;
    PORT
      LAYER M5 ;
        RECT  146.844 0 146.868 0.192 ;
    END
  END t1[368]
  PIN t1[369]
    DIRECTION OUTPUT ;
    USE SIGNAL ;
    PORT
      LAYER M5 ;
        RECT  147.084 0 147.108 0.192 ;
    END
  END t1[369]
  PIN t1[36]
    DIRECTION OUTPUT ;
    USE SIGNAL ;
    PORT
      LAYER M5 ;
        RECT  69.612 0 69.636 0.192 ;
    END
  END t1[36]
  PIN t1[370]
    DIRECTION OUTPUT ;
    USE SIGNAL ;
    PORT
      LAYER M5 ;
        RECT  147.324 0 147.348 0.192 ;
    END
  END t1[370]
  PIN t1[371]
    DIRECTION OUTPUT ;
    USE SIGNAL ;
    PORT
      LAYER M5 ;
        RECT  147.564 0 147.588 0.192 ;
    END
  END t1[371]
  PIN t1[372]
    DIRECTION OUTPUT ;
    USE SIGNAL ;
    PORT
      LAYER M5 ;
        RECT  147.804 0 147.828 0.192 ;
    END
  END t1[372]
  PIN t1[373]
    DIRECTION OUTPUT ;
    USE SIGNAL ;
    PORT
      LAYER M5 ;
        RECT  147.996 0 148.02 0.192 ;
    END
  END t1[373]
  PIN t1[374]
    DIRECTION OUTPUT ;
    USE SIGNAL ;
    PORT
      LAYER M5 ;
        RECT  148.236 0 148.26 0.192 ;
    END
  END t1[374]
  PIN t1[375]
    DIRECTION OUTPUT ;
    USE SIGNAL ;
    PORT
      LAYER M5 ;
        RECT  148.476 0 148.5 0.192 ;
    END
  END t1[375]
  PIN t1[376]
    DIRECTION OUTPUT ;
    USE SIGNAL ;
    PORT
      LAYER M5 ;
        RECT  148.716 0 148.74 0.192 ;
    END
  END t1[376]
  PIN t1[377]
    DIRECTION OUTPUT ;
    USE SIGNAL ;
    PORT
      LAYER M5 ;
        RECT  148.956 0 148.98 0.192 ;
    END
  END t1[377]
  PIN t1[378]
    DIRECTION OUTPUT ;
    USE SIGNAL ;
    PORT
      LAYER M5 ;
        RECT  149.196 0 149.22 0.192 ;
    END
  END t1[378]
  PIN t1[379]
    DIRECTION OUTPUT ;
    USE SIGNAL ;
    PORT
      LAYER M5 ;
        RECT  149.388 0 149.412 0.192 ;
    END
  END t1[379]
  PIN t1[37]
    DIRECTION OUTPUT ;
    USE SIGNAL ;
    PORT
      LAYER M5 ;
        RECT  69.804 0 69.828 0.192 ;
    END
  END t1[37]
  PIN t1[380]
    DIRECTION OUTPUT ;
    USE SIGNAL ;
    PORT
      LAYER M5 ;
        RECT  149.628 0 149.652 0.192 ;
    END
  END t1[380]
  PIN t1[381]
    DIRECTION OUTPUT ;
    USE SIGNAL ;
    PORT
      LAYER M5 ;
        RECT  149.868 0 149.892 0.192 ;
    END
  END t1[381]
  PIN t1[382]
    DIRECTION OUTPUT ;
    USE SIGNAL ;
    PORT
      LAYER M5 ;
        RECT  150.108 0 150.132 0.192 ;
    END
  END t1[382]
  PIN t1[383]
    DIRECTION OUTPUT ;
    USE SIGNAL ;
    PORT
      LAYER M5 ;
        RECT  150.348 0 150.372 0.192 ;
    END
  END t1[383]
  PIN t1[384]
    DIRECTION OUTPUT ;
    USE SIGNAL ;
    PORT
      LAYER M5 ;
        RECT  150.588 0 150.612 0.192 ;
    END
  END t1[384]
  PIN t1[385]
    DIRECTION OUTPUT ;
    USE SIGNAL ;
    PORT
      LAYER M5 ;
        RECT  150.828 0 150.852 0.192 ;
    END
  END t1[385]
  PIN t1[386]
    DIRECTION OUTPUT ;
    USE SIGNAL ;
    PORT
      LAYER M5 ;
        RECT  151.02 0 151.044 0.192 ;
    END
  END t1[386]
  PIN t1[387]
    DIRECTION OUTPUT ;
    USE SIGNAL ;
    PORT
      LAYER M5 ;
        RECT  151.26 0 151.284 0.192 ;
    END
  END t1[387]
  PIN t1[388]
    DIRECTION OUTPUT ;
    USE SIGNAL ;
    PORT
      LAYER M5 ;
        RECT  151.5 0 151.524 0.192 ;
    END
  END t1[388]
  PIN t1[389]
    DIRECTION OUTPUT ;
    USE SIGNAL ;
    PORT
      LAYER M5 ;
        RECT  151.74 0 151.764 0.192 ;
    END
  END t1[389]
  PIN t1[38]
    DIRECTION OUTPUT ;
    USE SIGNAL ;
    PORT
      LAYER M5 ;
        RECT  70.044 0 70.068 0.192 ;
    END
  END t1[38]
  PIN t1[390]
    DIRECTION OUTPUT ;
    USE SIGNAL ;
    PORT
      LAYER M5 ;
        RECT  151.98 0 152.004 0.192 ;
    END
  END t1[390]
  PIN t1[391]
    DIRECTION OUTPUT ;
    USE SIGNAL ;
    PORT
      LAYER M5 ;
        RECT  152.22 0 152.244 0.192 ;
    END
  END t1[391]
  PIN t1[392]
    DIRECTION OUTPUT ;
    USE SIGNAL ;
    PORT
      LAYER M5 ;
        RECT  152.412 0 152.436 0.192 ;
    END
  END t1[392]
  PIN t1[393]
    DIRECTION OUTPUT ;
    USE SIGNAL ;
    PORT
      LAYER M5 ;
        RECT  152.652 0 152.676 0.192 ;
    END
  END t1[393]
  PIN t1[394]
    DIRECTION OUTPUT ;
    USE SIGNAL ;
    PORT
      LAYER M5 ;
        RECT  152.892 0 152.916 0.192 ;
    END
  END t1[394]
  PIN t1[395]
    DIRECTION OUTPUT ;
    USE SIGNAL ;
    PORT
      LAYER M5 ;
        RECT  153.132 0 153.156 0.192 ;
    END
  END t1[395]
  PIN t1[396]
    DIRECTION OUTPUT ;
    USE SIGNAL ;
    PORT
      LAYER M5 ;
        RECT  153.372 0 153.396 0.192 ;
    END
  END t1[396]
  PIN t1[397]
    DIRECTION OUTPUT ;
    USE SIGNAL ;
    PORT
      LAYER M5 ;
        RECT  153.612 0 153.636 0.192 ;
    END
  END t1[397]
  PIN t1[398]
    DIRECTION OUTPUT ;
    USE SIGNAL ;
    PORT
      LAYER M5 ;
        RECT  153.852 0 153.876 0.192 ;
    END
  END t1[398]
  PIN t1[399]
    DIRECTION OUTPUT ;
    USE SIGNAL ;
    PORT
      LAYER M5 ;
        RECT  154.044 0 154.068 0.192 ;
    END
  END t1[399]
  PIN t1[39]
    DIRECTION OUTPUT ;
    USE SIGNAL ;
    PORT
      LAYER M5 ;
        RECT  70.284 0 70.308 0.192 ;
    END
  END t1[39]
  PIN t1[3]
    DIRECTION OUTPUT ;
    USE SIGNAL ;
    PORT
      LAYER M5 ;
        RECT  61.932 0 61.956 0.192 ;
    END
  END t1[3]
  PIN t1[400]
    DIRECTION OUTPUT ;
    USE SIGNAL ;
    PORT
      LAYER M5 ;
        RECT  154.284 0 154.308 0.192 ;
    END
  END t1[400]
  PIN t1[401]
    DIRECTION OUTPUT ;
    USE SIGNAL ;
    PORT
      LAYER M5 ;
        RECT  154.524 0 154.548 0.192 ;
    END
  END t1[401]
  PIN t1[402]
    DIRECTION OUTPUT ;
    USE SIGNAL ;
    PORT
      LAYER M5 ;
        RECT  154.764 0 154.788 0.192 ;
    END
  END t1[402]
  PIN t1[403]
    DIRECTION OUTPUT ;
    USE SIGNAL ;
    PORT
      LAYER M5 ;
        RECT  155.004 0 155.028 0.192 ;
    END
  END t1[403]
  PIN t1[404]
    DIRECTION OUTPUT ;
    USE SIGNAL ;
    PORT
      LAYER M5 ;
        RECT  155.244 0 155.268 0.192 ;
    END
  END t1[404]
  PIN t1[405]
    DIRECTION OUTPUT ;
    USE SIGNAL ;
    PORT
      LAYER M5 ;
        RECT  155.484 0 155.508 0.192 ;
    END
  END t1[405]
  PIN t1[406]
    DIRECTION OUTPUT ;
    USE SIGNAL ;
    PORT
      LAYER M5 ;
        RECT  155.676 0 155.7 0.192 ;
    END
  END t1[406]
  PIN t1[407]
    DIRECTION OUTPUT ;
    USE SIGNAL ;
    PORT
      LAYER M5 ;
        RECT  155.916 0 155.94 0.192 ;
    END
  END t1[407]
  PIN t1[408]
    DIRECTION OUTPUT ;
    USE SIGNAL ;
    PORT
      LAYER M5 ;
        RECT  156.156 0 156.18 0.192 ;
    END
  END t1[408]
  PIN t1[409]
    DIRECTION OUTPUT ;
    USE SIGNAL ;
    PORT
      LAYER M5 ;
        RECT  156.396 0 156.42 0.192 ;
    END
  END t1[409]
  PIN t1[40]
    DIRECTION OUTPUT ;
    USE SIGNAL ;
    PORT
      LAYER M5 ;
        RECT  70.524 0 70.548 0.192 ;
    END
  END t1[40]
  PIN t1[410]
    DIRECTION OUTPUT ;
    USE SIGNAL ;
    PORT
      LAYER M5 ;
        RECT  156.636 0 156.66 0.192 ;
    END
  END t1[410]
  PIN t1[411]
    DIRECTION OUTPUT ;
    USE SIGNAL ;
    PORT
      LAYER M5 ;
        RECT  156.876 0 156.9 0.192 ;
    END
  END t1[411]
  PIN t1[412]
    DIRECTION OUTPUT ;
    USE SIGNAL ;
    PORT
      LAYER M5 ;
        RECT  157.068 0 157.092 0.192 ;
    END
  END t1[412]
  PIN t1[413]
    DIRECTION OUTPUT ;
    USE SIGNAL ;
    PORT
      LAYER M5 ;
        RECT  157.308 0 157.332 0.192 ;
    END
  END t1[413]
  PIN t1[414]
    DIRECTION OUTPUT ;
    USE SIGNAL ;
    PORT
      LAYER M5 ;
        RECT  157.548 0 157.572 0.192 ;
    END
  END t1[414]
  PIN t1[415]
    DIRECTION OUTPUT ;
    USE SIGNAL ;
    PORT
      LAYER M5 ;
        RECT  157.788 0 157.812 0.192 ;
    END
  END t1[415]
  PIN t1[416]
    DIRECTION OUTPUT ;
    USE SIGNAL ;
    PORT
      LAYER M5 ;
        RECT  158.028 0 158.052 0.192 ;
    END
  END t1[416]
  PIN t1[417]
    DIRECTION OUTPUT ;
    USE SIGNAL ;
    PORT
      LAYER M5 ;
        RECT  158.268 0 158.292 0.192 ;
    END
  END t1[417]
  PIN t1[418]
    DIRECTION OUTPUT ;
    USE SIGNAL ;
    PORT
      LAYER M5 ;
        RECT  158.508 0 158.532 0.192 ;
    END
  END t1[418]
  PIN t1[419]
    DIRECTION OUTPUT ;
    USE SIGNAL ;
    PORT
      LAYER M5 ;
        RECT  158.7 0 158.724 0.192 ;
    END
  END t1[419]
  PIN t1[41]
    DIRECTION OUTPUT ;
    USE SIGNAL ;
    PORT
      LAYER M5 ;
        RECT  70.764 0 70.788 0.192 ;
    END
  END t1[41]
  PIN t1[420]
    DIRECTION OUTPUT ;
    USE SIGNAL ;
    PORT
      LAYER M5 ;
        RECT  158.94 0 158.964 0.192 ;
    END
  END t1[420]
  PIN t1[421]
    DIRECTION OUTPUT ;
    USE SIGNAL ;
    PORT
      LAYER M5 ;
        RECT  159.18 0 159.204 0.192 ;
    END
  END t1[421]
  PIN t1[422]
    DIRECTION OUTPUT ;
    USE SIGNAL ;
    PORT
      LAYER M5 ;
        RECT  159.42 0 159.444 0.192 ;
    END
  END t1[422]
  PIN t1[423]
    DIRECTION OUTPUT ;
    USE SIGNAL ;
    PORT
      LAYER M5 ;
        RECT  159.66 0 159.684 0.192 ;
    END
  END t1[423]
  PIN t1[424]
    DIRECTION OUTPUT ;
    USE SIGNAL ;
    PORT
      LAYER M5 ;
        RECT  159.9 0 159.924 0.192 ;
    END
  END t1[424]
  PIN t1[425]
    DIRECTION OUTPUT ;
    USE SIGNAL ;
    PORT
      LAYER M5 ;
        RECT  160.092 0 160.116 0.192 ;
    END
  END t1[425]
  PIN t1[426]
    DIRECTION OUTPUT ;
    USE SIGNAL ;
    PORT
      LAYER M5 ;
        RECT  160.332 0 160.356 0.192 ;
    END
  END t1[426]
  PIN t1[427]
    DIRECTION OUTPUT ;
    USE SIGNAL ;
    PORT
      LAYER M5 ;
        RECT  160.572 0 160.596 0.192 ;
    END
  END t1[427]
  PIN t1[428]
    DIRECTION OUTPUT ;
    USE SIGNAL ;
    PORT
      LAYER M5 ;
        RECT  160.812 0 160.836 0.192 ;
    END
  END t1[428]
  PIN t1[429]
    DIRECTION OUTPUT ;
    USE SIGNAL ;
    PORT
      LAYER M5 ;
        RECT  161.052 0 161.076 0.192 ;
    END
  END t1[429]
  PIN t1[42]
    DIRECTION OUTPUT ;
    USE SIGNAL ;
    PORT
      LAYER M5 ;
        RECT  71.004 0 71.028 0.192 ;
    END
  END t1[42]
  PIN t1[430]
    DIRECTION OUTPUT ;
    USE SIGNAL ;
    PORT
      LAYER M5 ;
        RECT  161.292 0 161.316 0.192 ;
    END
  END t1[430]
  PIN t1[431]
    DIRECTION OUTPUT ;
    USE SIGNAL ;
    PORT
      LAYER M5 ;
        RECT  161.532 0 161.556 0.192 ;
    END
  END t1[431]
  PIN t1[432]
    DIRECTION OUTPUT ;
    USE SIGNAL ;
    PORT
      LAYER M5 ;
        RECT  161.724 0 161.748 0.192 ;
    END
  END t1[432]
  PIN t1[433]
    DIRECTION OUTPUT ;
    USE SIGNAL ;
    PORT
      LAYER M5 ;
        RECT  161.964 0 161.988 0.192 ;
    END
  END t1[433]
  PIN t1[434]
    DIRECTION OUTPUT ;
    USE SIGNAL ;
    PORT
      LAYER M5 ;
        RECT  162.204 0 162.228 0.192 ;
    END
  END t1[434]
  PIN t1[435]
    DIRECTION OUTPUT ;
    USE SIGNAL ;
    PORT
      LAYER M5 ;
        RECT  162.444 0 162.468 0.192 ;
    END
  END t1[435]
  PIN t1[436]
    DIRECTION OUTPUT ;
    USE SIGNAL ;
    PORT
      LAYER M5 ;
        RECT  162.684 0 162.708 0.192 ;
    END
  END t1[436]
  PIN t1[437]
    DIRECTION OUTPUT ;
    USE SIGNAL ;
    PORT
      LAYER M5 ;
        RECT  162.924 0 162.948 0.192 ;
    END
  END t1[437]
  PIN t1[438]
    DIRECTION OUTPUT ;
    USE SIGNAL ;
    PORT
      LAYER M5 ;
        RECT  163.164 0 163.188 0.192 ;
    END
  END t1[438]
  PIN t1[439]
    DIRECTION OUTPUT ;
    USE SIGNAL ;
    PORT
      LAYER M5 ;
        RECT  163.356 0 163.38 0.192 ;
    END
  END t1[439]
  PIN t1[43]
    DIRECTION OUTPUT ;
    USE SIGNAL ;
    PORT
      LAYER M5 ;
        RECT  71.196 0 71.22 0.192 ;
    END
  END t1[43]
  PIN t1[440]
    DIRECTION OUTPUT ;
    USE SIGNAL ;
    PORT
      LAYER M5 ;
        RECT  163.596 0 163.62 0.192 ;
    END
  END t1[440]
  PIN t1[441]
    DIRECTION OUTPUT ;
    USE SIGNAL ;
    PORT
      LAYER M5 ;
        RECT  163.836 0 163.86 0.192 ;
    END
  END t1[441]
  PIN t1[442]
    DIRECTION OUTPUT ;
    USE SIGNAL ;
    PORT
      LAYER M5 ;
        RECT  164.076 0 164.1 0.192 ;
    END
  END t1[442]
  PIN t1[443]
    DIRECTION OUTPUT ;
    USE SIGNAL ;
    PORT
      LAYER M5 ;
        RECT  164.316 0 164.34 0.192 ;
    END
  END t1[443]
  PIN t1[444]
    DIRECTION OUTPUT ;
    USE SIGNAL ;
    PORT
      LAYER M5 ;
        RECT  164.556 0 164.58 0.192 ;
    END
  END t1[444]
  PIN t1[445]
    DIRECTION OUTPUT ;
    USE SIGNAL ;
    PORT
      LAYER M5 ;
        RECT  164.748 0 164.772 0.192 ;
    END
  END t1[445]
  PIN t1[446]
    DIRECTION OUTPUT ;
    USE SIGNAL ;
    PORT
      LAYER M5 ;
        RECT  164.988 0 165.012 0.192 ;
    END
  END t1[446]
  PIN t1[447]
    DIRECTION OUTPUT ;
    USE SIGNAL ;
    PORT
      LAYER M5 ;
        RECT  165.228 0 165.252 0.192 ;
    END
  END t1[447]
  PIN t1[448]
    DIRECTION OUTPUT ;
    USE SIGNAL ;
    PORT
      LAYER M5 ;
        RECT  165.468 0 165.492 0.192 ;
    END
  END t1[448]
  PIN t1[449]
    DIRECTION OUTPUT ;
    USE SIGNAL ;
    PORT
      LAYER M5 ;
        RECT  165.708 0 165.732 0.192 ;
    END
  END t1[449]
  PIN t1[44]
    DIRECTION OUTPUT ;
    USE SIGNAL ;
    PORT
      LAYER M5 ;
        RECT  71.436 0 71.46 0.192 ;
    END
  END t1[44]
  PIN t1[450]
    DIRECTION OUTPUT ;
    USE SIGNAL ;
    PORT
      LAYER M5 ;
        RECT  165.948 0 165.972 0.192 ;
    END
  END t1[450]
  PIN t1[451]
    DIRECTION OUTPUT ;
    USE SIGNAL ;
    PORT
      LAYER M5 ;
        RECT  166.188 0 166.212 0.192 ;
    END
  END t1[451]
  PIN t1[452]
    DIRECTION OUTPUT ;
    USE SIGNAL ;
    PORT
      LAYER M5 ;
        RECT  166.38 0 166.404 0.192 ;
    END
  END t1[452]
  PIN t1[453]
    DIRECTION OUTPUT ;
    USE SIGNAL ;
    PORT
      LAYER M5 ;
        RECT  166.62 0 166.644 0.192 ;
    END
  END t1[453]
  PIN t1[454]
    DIRECTION OUTPUT ;
    USE SIGNAL ;
    PORT
      LAYER M5 ;
        RECT  166.86 0 166.884 0.192 ;
    END
  END t1[454]
  PIN t1[455]
    DIRECTION OUTPUT ;
    USE SIGNAL ;
    PORT
      LAYER M5 ;
        RECT  167.1 0 167.124 0.192 ;
    END
  END t1[455]
  PIN t1[456]
    DIRECTION OUTPUT ;
    USE SIGNAL ;
    PORT
      LAYER M5 ;
        RECT  167.34 0 167.364 0.192 ;
    END
  END t1[456]
  PIN t1[457]
    DIRECTION OUTPUT ;
    USE SIGNAL ;
    PORT
      LAYER M5 ;
        RECT  167.58 0 167.604 0.192 ;
    END
  END t1[457]
  PIN t1[458]
    DIRECTION OUTPUT ;
    USE SIGNAL ;
    PORT
      LAYER M5 ;
        RECT  167.772 0 167.796 0.192 ;
    END
  END t1[458]
  PIN t1[459]
    DIRECTION OUTPUT ;
    USE SIGNAL ;
    PORT
      LAYER M5 ;
        RECT  168.012 0 168.036 0.192 ;
    END
  END t1[459]
  PIN t1[45]
    DIRECTION OUTPUT ;
    USE SIGNAL ;
    PORT
      LAYER M5 ;
        RECT  71.676 0 71.7 0.192 ;
    END
  END t1[45]
  PIN t1[460]
    DIRECTION OUTPUT ;
    USE SIGNAL ;
    PORT
      LAYER M5 ;
        RECT  168.252 0 168.276 0.192 ;
    END
  END t1[460]
  PIN t1[461]
    DIRECTION OUTPUT ;
    USE SIGNAL ;
    PORT
      LAYER M5 ;
        RECT  168.492 0 168.516 0.192 ;
    END
  END t1[461]
  PIN t1[462]
    DIRECTION OUTPUT ;
    USE SIGNAL ;
    PORT
      LAYER M5 ;
        RECT  168.732 0 168.756 0.192 ;
    END
  END t1[462]
  PIN t1[463]
    DIRECTION OUTPUT ;
    USE SIGNAL ;
    PORT
      LAYER M5 ;
        RECT  168.972 0 168.996 0.192 ;
    END
  END t1[463]
  PIN t1[464]
    DIRECTION OUTPUT ;
    USE SIGNAL ;
    PORT
      LAYER M5 ;
        RECT  169.212 0 169.236 0.192 ;
    END
  END t1[464]
  PIN t1[465]
    DIRECTION OUTPUT ;
    USE SIGNAL ;
    PORT
      LAYER M5 ;
        RECT  169.404 0 169.428 0.192 ;
    END
  END t1[465]
  PIN t1[466]
    DIRECTION OUTPUT ;
    USE SIGNAL ;
    PORT
      LAYER M5 ;
        RECT  169.644 0 169.668 0.192 ;
    END
  END t1[466]
  PIN t1[467]
    DIRECTION OUTPUT ;
    USE SIGNAL ;
    PORT
      LAYER M5 ;
        RECT  169.884 0 169.908 0.192 ;
    END
  END t1[467]
  PIN t1[468]
    DIRECTION OUTPUT ;
    USE SIGNAL ;
    PORT
      LAYER M5 ;
        RECT  170.124 0 170.148 0.192 ;
    END
  END t1[468]
  PIN t1[469]
    DIRECTION OUTPUT ;
    USE SIGNAL ;
    PORT
      LAYER M5 ;
        RECT  170.364 0 170.388 0.192 ;
    END
  END t1[469]
  PIN t1[46]
    DIRECTION OUTPUT ;
    USE SIGNAL ;
    PORT
      LAYER M5 ;
        RECT  71.916 0 71.94 0.192 ;
    END
  END t1[46]
  PIN t1[470]
    DIRECTION OUTPUT ;
    USE SIGNAL ;
    PORT
      LAYER M5 ;
        RECT  170.604 0 170.628 0.192 ;
    END
  END t1[470]
  PIN t1[471]
    DIRECTION OUTPUT ;
    USE SIGNAL ;
    PORT
      LAYER M5 ;
        RECT  170.844 0 170.868 0.192 ;
    END
  END t1[471]
  PIN t1[472]
    DIRECTION OUTPUT ;
    USE SIGNAL ;
    PORT
      LAYER M5 ;
        RECT  171.036 0 171.06 0.192 ;
    END
  END t1[472]
  PIN t1[473]
    DIRECTION OUTPUT ;
    USE SIGNAL ;
    PORT
      LAYER M5 ;
        RECT  171.276 0 171.3 0.192 ;
    END
  END t1[473]
  PIN t1[474]
    DIRECTION OUTPUT ;
    USE SIGNAL ;
    PORT
      LAYER M5 ;
        RECT  171.516 0 171.54 0.192 ;
    END
  END t1[474]
  PIN t1[475]
    DIRECTION OUTPUT ;
    USE SIGNAL ;
    PORT
      LAYER M5 ;
        RECT  171.756 0 171.78 0.192 ;
    END
  END t1[475]
  PIN t1[476]
    DIRECTION OUTPUT ;
    USE SIGNAL ;
    PORT
      LAYER M5 ;
        RECT  171.996 0 172.02 0.192 ;
    END
  END t1[476]
  PIN t1[477]
    DIRECTION OUTPUT ;
    USE SIGNAL ;
    PORT
      LAYER M5 ;
        RECT  172.236 0 172.26 0.192 ;
    END
  END t1[477]
  PIN t1[478]
    DIRECTION OUTPUT ;
    USE SIGNAL ;
    PORT
      LAYER M5 ;
        RECT  172.428 0 172.452 0.192 ;
    END
  END t1[478]
  PIN t1[479]
    DIRECTION OUTPUT ;
    USE SIGNAL ;
    PORT
      LAYER M5 ;
        RECT  172.668 0 172.692 0.192 ;
    END
  END t1[479]
  PIN t1[47]
    DIRECTION OUTPUT ;
    USE SIGNAL ;
    PORT
      LAYER M5 ;
        RECT  72.156 0 72.18 0.192 ;
    END
  END t1[47]
  PIN t1[480]
    DIRECTION OUTPUT ;
    USE SIGNAL ;
    PORT
      LAYER M5 ;
        RECT  172.908 0 172.932 0.192 ;
    END
  END t1[480]
  PIN t1[481]
    DIRECTION OUTPUT ;
    USE SIGNAL ;
    PORT
      LAYER M5 ;
        RECT  173.148 0 173.172 0.192 ;
    END
  END t1[481]
  PIN t1[482]
    DIRECTION OUTPUT ;
    USE SIGNAL ;
    PORT
      LAYER M5 ;
        RECT  173.388 0 173.412 0.192 ;
    END
  END t1[482]
  PIN t1[483]
    DIRECTION OUTPUT ;
    USE SIGNAL ;
    PORT
      LAYER M5 ;
        RECT  173.628 0 173.652 0.192 ;
    END
  END t1[483]
  PIN t1[484]
    DIRECTION OUTPUT ;
    USE SIGNAL ;
    PORT
      LAYER M5 ;
        RECT  173.868 0 173.892 0.192 ;
    END
  END t1[484]
  PIN t1[485]
    DIRECTION OUTPUT ;
    USE SIGNAL ;
    PORT
      LAYER M5 ;
        RECT  174.06 0 174.084 0.192 ;
    END
  END t1[485]
  PIN t1[486]
    DIRECTION OUTPUT ;
    USE SIGNAL ;
    PORT
      LAYER M5 ;
        RECT  174.3 0 174.324 0.192 ;
    END
  END t1[486]
  PIN t1[487]
    DIRECTION OUTPUT ;
    USE SIGNAL ;
    PORT
      LAYER M5 ;
        RECT  174.54 0 174.564 0.192 ;
    END
  END t1[487]
  PIN t1[488]
    DIRECTION OUTPUT ;
    USE SIGNAL ;
    PORT
      LAYER M5 ;
        RECT  174.78 0 174.804 0.192 ;
    END
  END t1[488]
  PIN t1[489]
    DIRECTION OUTPUT ;
    USE SIGNAL ;
    PORT
      LAYER M5 ;
        RECT  175.02 0 175.044 0.192 ;
    END
  END t1[489]
  PIN t1[48]
    DIRECTION OUTPUT ;
    USE SIGNAL ;
    PORT
      LAYER M5 ;
        RECT  72.396 0 72.42 0.192 ;
    END
  END t1[48]
  PIN t1[490]
    DIRECTION OUTPUT ;
    USE SIGNAL ;
    PORT
      LAYER M5 ;
        RECT  175.26 0 175.284 0.192 ;
    END
  END t1[490]
  PIN t1[491]
    DIRECTION OUTPUT ;
    USE SIGNAL ;
    PORT
      LAYER M5 ;
        RECT  175.452 0 175.476 0.192 ;
    END
  END t1[491]
  PIN t1[492]
    DIRECTION OUTPUT ;
    USE SIGNAL ;
    PORT
      LAYER M5 ;
        RECT  175.692 0 175.716 0.192 ;
    END
  END t1[492]
  PIN t1[493]
    DIRECTION OUTPUT ;
    USE SIGNAL ;
    PORT
      LAYER M5 ;
        RECT  175.932 0 175.956 0.192 ;
    END
  END t1[493]
  PIN t1[494]
    DIRECTION OUTPUT ;
    USE SIGNAL ;
    PORT
      LAYER M5 ;
        RECT  176.172 0 176.196 0.192 ;
    END
  END t1[494]
  PIN t1[495]
    DIRECTION OUTPUT ;
    USE SIGNAL ;
    PORT
      LAYER M5 ;
        RECT  176.412 0 176.436 0.192 ;
    END
  END t1[495]
  PIN t1[496]
    DIRECTION OUTPUT ;
    USE SIGNAL ;
    PORT
      LAYER M5 ;
        RECT  176.652 0 176.676 0.192 ;
    END
  END t1[496]
  PIN t1[497]
    DIRECTION OUTPUT ;
    USE SIGNAL ;
    PORT
      LAYER M5 ;
        RECT  176.892 0 176.916 0.192 ;
    END
  END t1[497]
  PIN t1[498]
    DIRECTION OUTPUT ;
    USE SIGNAL ;
    PORT
      LAYER M5 ;
        RECT  177.084 0 177.108 0.192 ;
    END
  END t1[498]
  PIN t1[499]
    DIRECTION OUTPUT ;
    USE SIGNAL ;
    PORT
      LAYER M5 ;
        RECT  177.324 0 177.348 0.192 ;
    END
  END t1[499]
  PIN t1[49]
    DIRECTION OUTPUT ;
    USE SIGNAL ;
    PORT
      LAYER M5 ;
        RECT  72.636 0 72.66 0.192 ;
    END
  END t1[49]
  PIN t1[4]
    DIRECTION OUTPUT ;
    USE SIGNAL ;
    PORT
      LAYER M5 ;
        RECT  62.124 0 62.148 0.192 ;
    END
  END t1[4]
  PIN t1[500]
    DIRECTION OUTPUT ;
    USE SIGNAL ;
    PORT
      LAYER M5 ;
        RECT  177.564 0 177.588 0.192 ;
    END
  END t1[500]
  PIN t1[501]
    DIRECTION OUTPUT ;
    USE SIGNAL ;
    PORT
      LAYER M5 ;
        RECT  177.804 0 177.828 0.192 ;
    END
  END t1[501]
  PIN t1[502]
    DIRECTION OUTPUT ;
    USE SIGNAL ;
    PORT
      LAYER M5 ;
        RECT  178.044 0 178.068 0.192 ;
    END
  END t1[502]
  PIN t1[503]
    DIRECTION OUTPUT ;
    USE SIGNAL ;
    PORT
      LAYER M5 ;
        RECT  178.284 0 178.308 0.192 ;
    END
  END t1[503]
  PIN t1[504]
    DIRECTION OUTPUT ;
    USE SIGNAL ;
    PORT
      LAYER M5 ;
        RECT  178.476 0 178.5 0.192 ;
    END
  END t1[504]
  PIN t1[505]
    DIRECTION OUTPUT ;
    USE SIGNAL ;
    PORT
      LAYER M5 ;
        RECT  178.716 0 178.74 0.192 ;
    END
  END t1[505]
  PIN t1[506]
    DIRECTION OUTPUT ;
    USE SIGNAL ;
    PORT
      LAYER M5 ;
        RECT  178.956 0 178.98 0.192 ;
    END
  END t1[506]
  PIN t1[507]
    DIRECTION OUTPUT ;
    USE SIGNAL ;
    PORT
      LAYER M5 ;
        RECT  179.196 0 179.22 0.192 ;
    END
  END t1[507]
  PIN t1[508]
    DIRECTION OUTPUT ;
    USE SIGNAL ;
    PORT
      LAYER M5 ;
        RECT  179.436 0 179.46 0.192 ;
    END
  END t1[508]
  PIN t1[509]
    DIRECTION OUTPUT ;
    USE SIGNAL ;
    PORT
      LAYER M5 ;
        RECT  179.676 0 179.7 0.192 ;
    END
  END t1[509]
  PIN t1[50]
    DIRECTION OUTPUT ;
    USE SIGNAL ;
    PORT
      LAYER M5 ;
        RECT  72.828 0 72.852 0.192 ;
    END
  END t1[50]
  PIN t1[510]
    DIRECTION OUTPUT ;
    USE SIGNAL ;
    PORT
      LAYER M5 ;
        RECT  179.916 0 179.94 0.192 ;
    END
  END t1[510]
  PIN t1[511]
    DIRECTION OUTPUT ;
    USE SIGNAL ;
    PORT
      LAYER M5 ;
        RECT  180.108 0 180.132 0.192 ;
    END
  END t1[511]
  PIN t1[512]
    DIRECTION OUTPUT ;
    USE SIGNAL ;
    PORT
      LAYER M5 ;
        RECT  180.348 0 180.372 0.192 ;
    END
  END t1[512]
  PIN t1[513]
    DIRECTION OUTPUT ;
    USE SIGNAL ;
    PORT
      LAYER M5 ;
        RECT  180.588 0 180.612 0.192 ;
    END
  END t1[513]
  PIN t1[514]
    DIRECTION OUTPUT ;
    USE SIGNAL ;
    PORT
      LAYER M5 ;
        RECT  180.828 0 180.852 0.192 ;
    END
  END t1[514]
  PIN t1[515]
    DIRECTION OUTPUT ;
    USE SIGNAL ;
    PORT
      LAYER M5 ;
        RECT  181.068 0 181.092 0.192 ;
    END
  END t1[515]
  PIN t1[516]
    DIRECTION OUTPUT ;
    USE SIGNAL ;
    PORT
      LAYER M5 ;
        RECT  181.308 0 181.332 0.192 ;
    END
  END t1[516]
  PIN t1[517]
    DIRECTION OUTPUT ;
    USE SIGNAL ;
    PORT
      LAYER M5 ;
        RECT  181.548 0 181.572 0.192 ;
    END
  END t1[517]
  PIN t1[518]
    DIRECTION OUTPUT ;
    USE SIGNAL ;
    PORT
      LAYER M5 ;
        RECT  181.74 0 181.764 0.192 ;
    END
  END t1[518]
  PIN t1[519]
    DIRECTION OUTPUT ;
    USE SIGNAL ;
    PORT
      LAYER M5 ;
        RECT  181.98 0 182.004 0.192 ;
    END
  END t1[519]
  PIN t1[51]
    DIRECTION OUTPUT ;
    USE SIGNAL ;
    PORT
      LAYER M5 ;
        RECT  73.068 0 73.092 0.192 ;
    END
  END t1[51]
  PIN t1[520]
    DIRECTION OUTPUT ;
    USE SIGNAL ;
    PORT
      LAYER M5 ;
        RECT  182.22 0 182.244 0.192 ;
    END
  END t1[520]
  PIN t1[521]
    DIRECTION OUTPUT ;
    USE SIGNAL ;
    PORT
      LAYER M5 ;
        RECT  182.46 0 182.484 0.192 ;
    END
  END t1[521]
  PIN t1[522]
    DIRECTION OUTPUT ;
    USE SIGNAL ;
    PORT
      LAYER M5 ;
        RECT  182.7 0 182.724 0.192 ;
    END
  END t1[522]
  PIN t1[523]
    DIRECTION OUTPUT ;
    USE SIGNAL ;
    PORT
      LAYER M5 ;
        RECT  182.94 0 182.964 0.192 ;
    END
  END t1[523]
  PIN t1[524]
    DIRECTION OUTPUT ;
    USE SIGNAL ;
    PORT
      LAYER M5 ;
        RECT  183.132 0 183.156 0.192 ;
    END
  END t1[524]
  PIN t1[525]
    DIRECTION OUTPUT ;
    USE SIGNAL ;
    PORT
      LAYER M5 ;
        RECT  183.372 0 183.396 0.192 ;
    END
  END t1[525]
  PIN t1[526]
    DIRECTION OUTPUT ;
    USE SIGNAL ;
    PORT
      LAYER M5 ;
        RECT  183.612 0 183.636 0.192 ;
    END
  END t1[526]
  PIN t1[527]
    DIRECTION OUTPUT ;
    USE SIGNAL ;
    PORT
      LAYER M5 ;
        RECT  183.852 0 183.876 0.192 ;
    END
  END t1[527]
  PIN t1[528]
    DIRECTION OUTPUT ;
    USE SIGNAL ;
    PORT
      LAYER M5 ;
        RECT  184.092 0 184.116 0.192 ;
    END
  END t1[528]
  PIN t1[529]
    DIRECTION OUTPUT ;
    USE SIGNAL ;
    PORT
      LAYER M5 ;
        RECT  184.332 0 184.356 0.192 ;
    END
  END t1[529]
  PIN t1[52]
    DIRECTION OUTPUT ;
    USE SIGNAL ;
    PORT
      LAYER M5 ;
        RECT  73.308 0 73.332 0.192 ;
    END
  END t1[52]
  PIN t1[530]
    DIRECTION OUTPUT ;
    USE SIGNAL ;
    PORT
      LAYER M5 ;
        RECT  184.572 0 184.596 0.192 ;
    END
  END t1[530]
  PIN t1[531]
    DIRECTION OUTPUT ;
    USE SIGNAL ;
    PORT
      LAYER M5 ;
        RECT  184.764 0 184.788 0.192 ;
    END
  END t1[531]
  PIN t1[532]
    DIRECTION OUTPUT ;
    USE SIGNAL ;
    PORT
      LAYER M5 ;
        RECT  185.004 0 185.028 0.192 ;
    END
  END t1[532]
  PIN t1[533]
    DIRECTION OUTPUT ;
    USE SIGNAL ;
    PORT
      LAYER M5 ;
        RECT  185.244 0 185.268 0.192 ;
    END
  END t1[533]
  PIN t1[534]
    DIRECTION OUTPUT ;
    USE SIGNAL ;
    PORT
      LAYER M5 ;
        RECT  185.484 0 185.508 0.192 ;
    END
  END t1[534]
  PIN t1[535]
    DIRECTION OUTPUT ;
    USE SIGNAL ;
    PORT
      LAYER M5 ;
        RECT  185.724 0 185.748 0.192 ;
    END
  END t1[535]
  PIN t1[536]
    DIRECTION OUTPUT ;
    USE SIGNAL ;
    PORT
      LAYER M5 ;
        RECT  185.964 0 185.988 0.192 ;
    END
  END t1[536]
  PIN t1[537]
    DIRECTION OUTPUT ;
    USE SIGNAL ;
    PORT
      LAYER M5 ;
        RECT  186.156 0 186.18 0.192 ;
    END
  END t1[537]
  PIN t1[538]
    DIRECTION OUTPUT ;
    USE SIGNAL ;
    PORT
      LAYER M5 ;
        RECT  186.396 0 186.42 0.192 ;
    END
  END t1[538]
  PIN t1[539]
    DIRECTION OUTPUT ;
    USE SIGNAL ;
    PORT
      LAYER M5 ;
        RECT  186.636 0 186.66 0.192 ;
    END
  END t1[539]
  PIN t1[53]
    DIRECTION OUTPUT ;
    USE SIGNAL ;
    PORT
      LAYER M5 ;
        RECT  73.548 0 73.572 0.192 ;
    END
  END t1[53]
  PIN t1[540]
    DIRECTION OUTPUT ;
    USE SIGNAL ;
    PORT
      LAYER M5 ;
        RECT  186.876 0 186.9 0.192 ;
    END
  END t1[540]
  PIN t1[541]
    DIRECTION OUTPUT ;
    USE SIGNAL ;
    PORT
      LAYER M5 ;
        RECT  187.116 0 187.14 0.192 ;
    END
  END t1[541]
  PIN t1[542]
    DIRECTION OUTPUT ;
    USE SIGNAL ;
    PORT
      LAYER M5 ;
        RECT  187.356 0 187.38 0.192 ;
    END
  END t1[542]
  PIN t1[543]
    DIRECTION OUTPUT ;
    USE SIGNAL ;
    PORT
      LAYER M5 ;
        RECT  187.596 0 187.62 0.192 ;
    END
  END t1[543]
  PIN t1[544]
    DIRECTION OUTPUT ;
    USE SIGNAL ;
    PORT
      LAYER M5 ;
        RECT  187.788 0 187.812 0.192 ;
    END
  END t1[544]
  PIN t1[545]
    DIRECTION OUTPUT ;
    USE SIGNAL ;
    PORT
      LAYER M5 ;
        RECT  188.028 0 188.052 0.192 ;
    END
  END t1[545]
  PIN t1[546]
    DIRECTION OUTPUT ;
    USE SIGNAL ;
    PORT
      LAYER M5 ;
        RECT  188.268 0 188.292 0.192 ;
    END
  END t1[546]
  PIN t1[547]
    DIRECTION OUTPUT ;
    USE SIGNAL ;
    PORT
      LAYER M5 ;
        RECT  188.508 0 188.532 0.192 ;
    END
  END t1[547]
  PIN t1[548]
    DIRECTION OUTPUT ;
    USE SIGNAL ;
    PORT
      LAYER M5 ;
        RECT  188.748 0 188.772 0.192 ;
    END
  END t1[548]
  PIN t1[549]
    DIRECTION OUTPUT ;
    USE SIGNAL ;
    PORT
      LAYER M5 ;
        RECT  188.988 0 189.012 0.192 ;
    END
  END t1[549]
  PIN t1[54]
    DIRECTION OUTPUT ;
    USE SIGNAL ;
    PORT
      LAYER M5 ;
        RECT  73.788 0 73.812 0.192 ;
    END
  END t1[54]
  PIN t1[550]
    DIRECTION OUTPUT ;
    USE SIGNAL ;
    PORT
      LAYER M5 ;
        RECT  189.228 0 189.252 0.192 ;
    END
  END t1[550]
  PIN t1[551]
    DIRECTION OUTPUT ;
    USE SIGNAL ;
    PORT
      LAYER M5 ;
        RECT  189.42 0 189.444 0.192 ;
    END
  END t1[551]
  PIN t1[552]
    DIRECTION OUTPUT ;
    USE SIGNAL ;
    PORT
      LAYER M5 ;
        RECT  189.66 0 189.684 0.192 ;
    END
  END t1[552]
  PIN t1[553]
    DIRECTION OUTPUT ;
    USE SIGNAL ;
    PORT
      LAYER M5 ;
        RECT  189.9 0 189.924 0.192 ;
    END
  END t1[553]
  PIN t1[554]
    DIRECTION OUTPUT ;
    USE SIGNAL ;
    PORT
      LAYER M5 ;
        RECT  190.14 0 190.164 0.192 ;
    END
  END t1[554]
  PIN t1[555]
    DIRECTION OUTPUT ;
    USE SIGNAL ;
    PORT
      LAYER M5 ;
        RECT  190.38 0 190.404 0.192 ;
    END
  END t1[555]
  PIN t1[556]
    DIRECTION OUTPUT ;
    USE SIGNAL ;
    PORT
      LAYER M5 ;
        RECT  190.62 0 190.644 0.192 ;
    END
  END t1[556]
  PIN t1[557]
    DIRECTION OUTPUT ;
    USE SIGNAL ;
    PORT
      LAYER M5 ;
        RECT  190.812 0 190.836 0.192 ;
    END
  END t1[557]
  PIN t1[558]
    DIRECTION OUTPUT ;
    USE SIGNAL ;
    PORT
      LAYER M5 ;
        RECT  191.052 0 191.076 0.192 ;
    END
  END t1[558]
  PIN t1[559]
    DIRECTION OUTPUT ;
    USE SIGNAL ;
    PORT
      LAYER M5 ;
        RECT  191.292 0 191.316 0.192 ;
    END
  END t1[559]
  PIN t1[55]
    DIRECTION OUTPUT ;
    USE SIGNAL ;
    PORT
      LAYER M5 ;
        RECT  74.028 0 74.052 0.192 ;
    END
  END t1[55]
  PIN t1[560]
    DIRECTION OUTPUT ;
    USE SIGNAL ;
    PORT
      LAYER M5 ;
        RECT  191.532 0 191.556 0.192 ;
    END
  END t1[560]
  PIN t1[561]
    DIRECTION OUTPUT ;
    USE SIGNAL ;
    PORT
      LAYER M5 ;
        RECT  191.772 0 191.796 0.192 ;
    END
  END t1[561]
  PIN t1[562]
    DIRECTION OUTPUT ;
    USE SIGNAL ;
    PORT
      LAYER M5 ;
        RECT  192.012 0 192.036 0.192 ;
    END
  END t1[562]
  PIN t1[563]
    DIRECTION OUTPUT ;
    USE SIGNAL ;
    PORT
      LAYER M5 ;
        RECT  192.252 0 192.276 0.192 ;
    END
  END t1[563]
  PIN t1[564]
    DIRECTION OUTPUT ;
    USE SIGNAL ;
    PORT
      LAYER M5 ;
        RECT  192.444 0 192.468 0.192 ;
    END
  END t1[564]
  PIN t1[565]
    DIRECTION OUTPUT ;
    USE SIGNAL ;
    PORT
      LAYER M5 ;
        RECT  192.684 0 192.708 0.192 ;
    END
  END t1[565]
  PIN t1[566]
    DIRECTION OUTPUT ;
    USE SIGNAL ;
    PORT
      LAYER M5 ;
        RECT  192.924 0 192.948 0.192 ;
    END
  END t1[566]
  PIN t1[567]
    DIRECTION OUTPUT ;
    USE SIGNAL ;
    PORT
      LAYER M5 ;
        RECT  193.164 0 193.188 0.192 ;
    END
  END t1[567]
  PIN t1[568]
    DIRECTION OUTPUT ;
    USE SIGNAL ;
    PORT
      LAYER M5 ;
        RECT  193.404 0 193.428 0.192 ;
    END
  END t1[568]
  PIN t1[569]
    DIRECTION OUTPUT ;
    USE SIGNAL ;
    PORT
      LAYER M5 ;
        RECT  193.644 0 193.668 0.192 ;
    END
  END t1[569]
  PIN t1[56]
    DIRECTION OUTPUT ;
    USE SIGNAL ;
    PORT
      LAYER M5 ;
        RECT  74.268 0 74.292 0.192 ;
    END
  END t1[56]
  PIN t1[570]
    DIRECTION OUTPUT ;
    USE SIGNAL ;
    PORT
      LAYER M5 ;
        RECT  193.836 0 193.86 0.192 ;
    END
  END t1[570]
  PIN t1[571]
    DIRECTION OUTPUT ;
    USE SIGNAL ;
    PORT
      LAYER M5 ;
        RECT  194.076 0 194.1 0.192 ;
    END
  END t1[571]
  PIN t1[572]
    DIRECTION OUTPUT ;
    USE SIGNAL ;
    PORT
      LAYER M5 ;
        RECT  194.316 0 194.34 0.192 ;
    END
  END t1[572]
  PIN t1[573]
    DIRECTION OUTPUT ;
    USE SIGNAL ;
    PORT
      LAYER M5 ;
        RECT  194.556 0 194.58 0.192 ;
    END
  END t1[573]
  PIN t1[574]
    DIRECTION OUTPUT ;
    USE SIGNAL ;
    PORT
      LAYER M5 ;
        RECT  194.796 0 194.82 0.192 ;
    END
  END t1[574]
  PIN t1[575]
    DIRECTION OUTPUT ;
    USE SIGNAL ;
    PORT
      LAYER M5 ;
        RECT  195.036 0 195.06 0.192 ;
    END
  END t1[575]
  PIN t1[576]
    DIRECTION OUTPUT ;
    USE SIGNAL ;
    PORT
      LAYER M5 ;
        RECT  195.276 0 195.3 0.192 ;
    END
  END t1[576]
  PIN t1[577]
    DIRECTION OUTPUT ;
    USE SIGNAL ;
    PORT
      LAYER M5 ;
        RECT  195.468 0 195.492 0.192 ;
    END
  END t1[577]
  PIN t1[578]
    DIRECTION OUTPUT ;
    USE SIGNAL ;
    PORT
      LAYER M5 ;
        RECT  195.708 0 195.732 0.192 ;
    END
  END t1[578]
  PIN t1[579]
    DIRECTION OUTPUT ;
    USE SIGNAL ;
    PORT
      LAYER M5 ;
        RECT  195.948 0 195.972 0.192 ;
    END
  END t1[579]
  PIN t1[57]
    DIRECTION OUTPUT ;
    USE SIGNAL ;
    PORT
      LAYER M5 ;
        RECT  74.46 0 74.484 0.192 ;
    END
  END t1[57]
  PIN t1[580]
    DIRECTION OUTPUT ;
    USE SIGNAL ;
    PORT
      LAYER M5 ;
        RECT  196.188 0 196.212 0.192 ;
    END
  END t1[580]
  PIN t1[581]
    DIRECTION OUTPUT ;
    USE SIGNAL ;
    PORT
      LAYER M5 ;
        RECT  196.428 0 196.452 0.192 ;
    END
  END t1[581]
  PIN t1[582]
    DIRECTION OUTPUT ;
    USE SIGNAL ;
    PORT
      LAYER M5 ;
        RECT  196.668 0 196.692 0.192 ;
    END
  END t1[582]
  PIN t1[583]
    DIRECTION OUTPUT ;
    USE SIGNAL ;
    PORT
      LAYER M5 ;
        RECT  196.86 0 196.884 0.192 ;
    END
  END t1[583]
  PIN t1[584]
    DIRECTION OUTPUT ;
    USE SIGNAL ;
    PORT
      LAYER M5 ;
        RECT  197.1 0 197.124 0.192 ;
    END
  END t1[584]
  PIN t1[585]
    DIRECTION OUTPUT ;
    USE SIGNAL ;
    PORT
      LAYER M5 ;
        RECT  197.34 0 197.364 0.192 ;
    END
  END t1[585]
  PIN t1[586]
    DIRECTION OUTPUT ;
    USE SIGNAL ;
    PORT
      LAYER M5 ;
        RECT  197.58 0 197.604 0.192 ;
    END
  END t1[586]
  PIN t1[587]
    DIRECTION OUTPUT ;
    USE SIGNAL ;
    PORT
      LAYER M5 ;
        RECT  197.82 0 197.844 0.192 ;
    END
  END t1[587]
  PIN t1[588]
    DIRECTION OUTPUT ;
    USE SIGNAL ;
    PORT
      LAYER M5 ;
        RECT  198.06 0 198.084 0.192 ;
    END
  END t1[588]
  PIN t1[589]
    DIRECTION OUTPUT ;
    USE SIGNAL ;
    PORT
      LAYER M5 ;
        RECT  198.3 0 198.324 0.192 ;
    END
  END t1[589]
  PIN t1[58]
    DIRECTION OUTPUT ;
    USE SIGNAL ;
    PORT
      LAYER M5 ;
        RECT  74.7 0 74.724 0.192 ;
    END
  END t1[58]
  PIN t1[590]
    DIRECTION OUTPUT ;
    USE SIGNAL ;
    PORT
      LAYER M5 ;
        RECT  198.492 0 198.516 0.192 ;
    END
  END t1[590]
  PIN t1[591]
    DIRECTION OUTPUT ;
    USE SIGNAL ;
    PORT
      LAYER M5 ;
        RECT  198.732 0 198.756 0.192 ;
    END
  END t1[591]
  PIN t1[592]
    DIRECTION OUTPUT ;
    USE SIGNAL ;
    PORT
      LAYER M5 ;
        RECT  198.972 0 198.996 0.192 ;
    END
  END t1[592]
  PIN t1[593]
    DIRECTION OUTPUT ;
    USE SIGNAL ;
    PORT
      LAYER M5 ;
        RECT  199.212 0 199.236 0.192 ;
    END
  END t1[593]
  PIN t1[594]
    DIRECTION OUTPUT ;
    USE SIGNAL ;
    PORT
      LAYER M5 ;
        RECT  199.452 0 199.476 0.192 ;
    END
  END t1[594]
  PIN t1[595]
    DIRECTION OUTPUT ;
    USE SIGNAL ;
    PORT
      LAYER M5 ;
        RECT  199.692 0 199.716 0.192 ;
    END
  END t1[595]
  PIN t1[596]
    DIRECTION OUTPUT ;
    USE SIGNAL ;
    PORT
      LAYER M5 ;
        RECT  199.932 0 199.956 0.192 ;
    END
  END t1[596]
  PIN t1[597]
    DIRECTION OUTPUT ;
    USE SIGNAL ;
    PORT
      LAYER M5 ;
        RECT  200.124 0 200.148 0.192 ;
    END
  END t1[597]
  PIN t1[598]
    DIRECTION OUTPUT ;
    USE SIGNAL ;
    PORT
      LAYER M5 ;
        RECT  200.364 0 200.388 0.192 ;
    END
  END t1[598]
  PIN t1[599]
    DIRECTION OUTPUT ;
    USE SIGNAL ;
    PORT
      LAYER M5 ;
        RECT  200.604 0 200.628 0.192 ;
    END
  END t1[599]
  PIN t1[59]
    DIRECTION OUTPUT ;
    USE SIGNAL ;
    PORT
      LAYER M5 ;
        RECT  74.94 0 74.964 0.192 ;
    END
  END t1[59]
  PIN t1[5]
    DIRECTION OUTPUT ;
    USE SIGNAL ;
    PORT
      LAYER M5 ;
        RECT  62.364 0 62.388 0.192 ;
    END
  END t1[5]
  PIN t1[600]
    DIRECTION OUTPUT ;
    USE SIGNAL ;
    PORT
      LAYER M5 ;
        RECT  200.844 0 200.868 0.192 ;
    END
  END t1[600]
  PIN t1[601]
    DIRECTION OUTPUT ;
    USE SIGNAL ;
    PORT
      LAYER M5 ;
        RECT  201.084 0 201.108 0.192 ;
    END
  END t1[601]
  PIN t1[602]
    DIRECTION OUTPUT ;
    USE SIGNAL ;
    PORT
      LAYER M5 ;
        RECT  201.324 0 201.348 0.192 ;
    END
  END t1[602]
  PIN t1[603]
    DIRECTION OUTPUT ;
    USE SIGNAL ;
    PORT
      LAYER M5 ;
        RECT  201.516 0 201.54 0.192 ;
    END
  END t1[603]
  PIN t1[604]
    DIRECTION OUTPUT ;
    USE SIGNAL ;
    PORT
      LAYER M5 ;
        RECT  201.756 0 201.78 0.192 ;
    END
  END t1[604]
  PIN t1[605]
    DIRECTION OUTPUT ;
    USE SIGNAL ;
    PORT
      LAYER M5 ;
        RECT  201.996 0 202.02 0.192 ;
    END
  END t1[605]
  PIN t1[606]
    DIRECTION OUTPUT ;
    USE SIGNAL ;
    PORT
      LAYER M5 ;
        RECT  202.236 0 202.26 0.192 ;
    END
  END t1[606]
  PIN t1[607]
    DIRECTION OUTPUT ;
    USE SIGNAL ;
    PORT
      LAYER M5 ;
        RECT  202.476 0 202.5 0.192 ;
    END
  END t1[607]
  PIN t1[608]
    DIRECTION OUTPUT ;
    USE SIGNAL ;
    PORT
      LAYER M5 ;
        RECT  202.716 0 202.74 0.192 ;
    END
  END t1[608]
  PIN t1[609]
    DIRECTION OUTPUT ;
    USE SIGNAL ;
    PORT
      LAYER M5 ;
        RECT  202.956 0 202.98 0.192 ;
    END
  END t1[609]
  PIN t1[60]
    DIRECTION OUTPUT ;
    USE SIGNAL ;
    PORT
      LAYER M5 ;
        RECT  75.18 0 75.204 0.192 ;
    END
  END t1[60]
  PIN t1[610]
    DIRECTION OUTPUT ;
    USE SIGNAL ;
    PORT
      LAYER M5 ;
        RECT  203.148 0 203.172 0.192 ;
    END
  END t1[610]
  PIN t1[611]
    DIRECTION OUTPUT ;
    USE SIGNAL ;
    PORT
      LAYER M5 ;
        RECT  203.388 0 203.412 0.192 ;
    END
  END t1[611]
  PIN t1[612]
    DIRECTION OUTPUT ;
    USE SIGNAL ;
    PORT
      LAYER M5 ;
        RECT  203.628 0 203.652 0.192 ;
    END
  END t1[612]
  PIN t1[613]
    DIRECTION OUTPUT ;
    USE SIGNAL ;
    PORT
      LAYER M5 ;
        RECT  203.868 0 203.892 0.192 ;
    END
  END t1[613]
  PIN t1[614]
    DIRECTION OUTPUT ;
    USE SIGNAL ;
    PORT
      LAYER M5 ;
        RECT  204.108 0 204.132 0.192 ;
    END
  END t1[614]
  PIN t1[615]
    DIRECTION OUTPUT ;
    USE SIGNAL ;
    PORT
      LAYER M5 ;
        RECT  204.348 0 204.372 0.192 ;
    END
  END t1[615]
  PIN t1[616]
    DIRECTION OUTPUT ;
    USE SIGNAL ;
    PORT
      LAYER M5 ;
        RECT  204.54 0 204.564 0.192 ;
    END
  END t1[616]
  PIN t1[617]
    DIRECTION OUTPUT ;
    USE SIGNAL ;
    PORT
      LAYER M5 ;
        RECT  204.78 0 204.804 0.192 ;
    END
  END t1[617]
  PIN t1[618]
    DIRECTION OUTPUT ;
    USE SIGNAL ;
    PORT
      LAYER M5 ;
        RECT  205.02 0 205.044 0.192 ;
    END
  END t1[618]
  PIN t1[619]
    DIRECTION OUTPUT ;
    USE SIGNAL ;
    PORT
      LAYER M5 ;
        RECT  205.26 0 205.284 0.192 ;
    END
  END t1[619]
  PIN t1[61]
    DIRECTION OUTPUT ;
    USE SIGNAL ;
    PORT
      LAYER M5 ;
        RECT  75.42 0 75.444 0.192 ;
    END
  END t1[61]
  PIN t1[620]
    DIRECTION OUTPUT ;
    USE SIGNAL ;
    PORT
      LAYER M5 ;
        RECT  205.5 0 205.524 0.192 ;
    END
  END t1[620]
  PIN t1[621]
    DIRECTION OUTPUT ;
    USE SIGNAL ;
    PORT
      LAYER M5 ;
        RECT  205.74 0 205.764 0.192 ;
    END
  END t1[621]
  PIN t1[622]
    DIRECTION OUTPUT ;
    USE SIGNAL ;
    PORT
      LAYER M5 ;
        RECT  205.98 0 206.004 0.192 ;
    END
  END t1[622]
  PIN t1[623]
    DIRECTION OUTPUT ;
    USE SIGNAL ;
    PORT
      LAYER M5 ;
        RECT  206.172 0 206.196 0.192 ;
    END
  END t1[623]
  PIN t1[624]
    DIRECTION OUTPUT ;
    USE SIGNAL ;
    PORT
      LAYER M5 ;
        RECT  206.412 0 206.436 0.192 ;
    END
  END t1[624]
  PIN t1[625]
    DIRECTION OUTPUT ;
    USE SIGNAL ;
    PORT
      LAYER M5 ;
        RECT  206.652 0 206.676 0.192 ;
    END
  END t1[625]
  PIN t1[626]
    DIRECTION OUTPUT ;
    USE SIGNAL ;
    PORT
      LAYER M5 ;
        RECT  206.892 0 206.916 0.192 ;
    END
  END t1[626]
  PIN t1[627]
    DIRECTION OUTPUT ;
    USE SIGNAL ;
    PORT
      LAYER M5 ;
        RECT  207.132 0 207.156 0.192 ;
    END
  END t1[627]
  PIN t1[628]
    DIRECTION OUTPUT ;
    USE SIGNAL ;
    PORT
      LAYER M5 ;
        RECT  207.372 0 207.396 0.192 ;
    END
  END t1[628]
  PIN t1[629]
    DIRECTION OUTPUT ;
    USE SIGNAL ;
    PORT
      LAYER M5 ;
        RECT  207.612 0 207.636 0.192 ;
    END
  END t1[629]
  PIN t1[62]
    DIRECTION OUTPUT ;
    USE SIGNAL ;
    PORT
      LAYER M5 ;
        RECT  75.66 0 75.684 0.192 ;
    END
  END t1[62]
  PIN t1[630]
    DIRECTION OUTPUT ;
    USE SIGNAL ;
    PORT
      LAYER M5 ;
        RECT  207.804 0 207.828 0.192 ;
    END
  END t1[630]
  PIN t1[631]
    DIRECTION OUTPUT ;
    USE SIGNAL ;
    PORT
      LAYER M5 ;
        RECT  208.044 0 208.068 0.192 ;
    END
  END t1[631]
  PIN t1[632]
    DIRECTION OUTPUT ;
    USE SIGNAL ;
    PORT
      LAYER M5 ;
        RECT  208.284 0 208.308 0.192 ;
    END
  END t1[632]
  PIN t1[633]
    DIRECTION OUTPUT ;
    USE SIGNAL ;
    PORT
      LAYER M5 ;
        RECT  208.524 0 208.548 0.192 ;
    END
  END t1[633]
  PIN t1[634]
    DIRECTION OUTPUT ;
    USE SIGNAL ;
    PORT
      LAYER M5 ;
        RECT  208.764 0 208.788 0.192 ;
    END
  END t1[634]
  PIN t1[635]
    DIRECTION OUTPUT ;
    USE SIGNAL ;
    PORT
      LAYER M5 ;
        RECT  209.004 0 209.028 0.192 ;
    END
  END t1[635]
  PIN t1[636]
    DIRECTION OUTPUT ;
    USE SIGNAL ;
    PORT
      LAYER M5 ;
        RECT  209.196 0 209.22 0.192 ;
    END
  END t1[636]
  PIN t1[637]
    DIRECTION OUTPUT ;
    USE SIGNAL ;
    PORT
      LAYER M5 ;
        RECT  209.436 0 209.46 0.192 ;
    END
  END t1[637]
  PIN t1[638]
    DIRECTION OUTPUT ;
    USE SIGNAL ;
    PORT
      LAYER M5 ;
        RECT  209.676 0 209.7 0.192 ;
    END
  END t1[638]
  PIN t1[639]
    DIRECTION OUTPUT ;
    USE SIGNAL ;
    PORT
      LAYER M5 ;
        RECT  209.916 0 209.94 0.192 ;
    END
  END t1[639]
  PIN t1[63]
    DIRECTION OUTPUT ;
    USE SIGNAL ;
    PORT
      LAYER M5 ;
        RECT  75.852 0 75.876 0.192 ;
    END
  END t1[63]
  PIN t1[640]
    DIRECTION OUTPUT ;
    USE SIGNAL ;
    PORT
      LAYER M5 ;
        RECT  210.156 0 210.18 0.192 ;
    END
  END t1[640]
  PIN t1[641]
    DIRECTION OUTPUT ;
    USE SIGNAL ;
    PORT
      LAYER M5 ;
        RECT  210.396 0 210.42 0.192 ;
    END
  END t1[641]
  PIN t1[642]
    DIRECTION OUTPUT ;
    USE SIGNAL ;
    PORT
      LAYER M5 ;
        RECT  210.636 0 210.66 0.192 ;
    END
  END t1[642]
  PIN t1[643]
    DIRECTION OUTPUT ;
    USE SIGNAL ;
    PORT
      LAYER M5 ;
        RECT  210.828 0 210.852 0.192 ;
    END
  END t1[643]
  PIN t1[644]
    DIRECTION OUTPUT ;
    USE SIGNAL ;
    PORT
      LAYER M5 ;
        RECT  211.068 0 211.092 0.192 ;
    END
  END t1[644]
  PIN t1[645]
    DIRECTION OUTPUT ;
    USE SIGNAL ;
    PORT
      LAYER M5 ;
        RECT  211.308 0 211.332 0.192 ;
    END
  END t1[645]
  PIN t1[646]
    DIRECTION OUTPUT ;
    USE SIGNAL ;
    PORT
      LAYER M5 ;
        RECT  211.548 0 211.572 0.192 ;
    END
  END t1[646]
  PIN t1[647]
    DIRECTION OUTPUT ;
    USE SIGNAL ;
    PORT
      LAYER M5 ;
        RECT  211.788 0 211.812 0.192 ;
    END
  END t1[647]
  PIN t1[648]
    DIRECTION OUTPUT ;
    USE SIGNAL ;
    PORT
      LAYER M5 ;
        RECT  212.028 0 212.052 0.192 ;
    END
  END t1[648]
  PIN t1[649]
    DIRECTION OUTPUT ;
    USE SIGNAL ;
    PORT
      LAYER M5 ;
        RECT  212.22 0 212.244 0.192 ;
    END
  END t1[649]
  PIN t1[64]
    DIRECTION OUTPUT ;
    USE SIGNAL ;
    PORT
      LAYER M5 ;
        RECT  76.092 0 76.116 0.192 ;
    END
  END t1[64]
  PIN t1[650]
    DIRECTION OUTPUT ;
    USE SIGNAL ;
    PORT
      LAYER M5 ;
        RECT  212.46 0 212.484 0.192 ;
    END
  END t1[650]
  PIN t1[651]
    DIRECTION OUTPUT ;
    USE SIGNAL ;
    PORT
      LAYER M5 ;
        RECT  212.7 0 212.724 0.192 ;
    END
  END t1[651]
  PIN t1[652]
    DIRECTION OUTPUT ;
    USE SIGNAL ;
    PORT
      LAYER M5 ;
        RECT  212.94 0 212.964 0.192 ;
    END
  END t1[652]
  PIN t1[653]
    DIRECTION OUTPUT ;
    USE SIGNAL ;
    PORT
      LAYER M5 ;
        RECT  213.18 0 213.204 0.192 ;
    END
  END t1[653]
  PIN t1[654]
    DIRECTION OUTPUT ;
    USE SIGNAL ;
    PORT
      LAYER M5 ;
        RECT  213.42 0 213.444 0.192 ;
    END
  END t1[654]
  PIN t1[655]
    DIRECTION OUTPUT ;
    USE SIGNAL ;
    PORT
      LAYER M5 ;
        RECT  213.66 0 213.684 0.192 ;
    END
  END t1[655]
  PIN t1[656]
    DIRECTION OUTPUT ;
    USE SIGNAL ;
    PORT
      LAYER M5 ;
        RECT  213.852 0 213.876 0.192 ;
    END
  END t1[656]
  PIN t1[65]
    DIRECTION OUTPUT ;
    USE SIGNAL ;
    PORT
      LAYER M5 ;
        RECT  76.332 0 76.356 0.192 ;
    END
  END t1[65]
  PIN t1[66]
    DIRECTION OUTPUT ;
    USE SIGNAL ;
    PORT
      LAYER M5 ;
        RECT  76.572 0 76.596 0.192 ;
    END
  END t1[66]
  PIN t1[67]
    DIRECTION OUTPUT ;
    USE SIGNAL ;
    PORT
      LAYER M5 ;
        RECT  76.812 0 76.836 0.192 ;
    END
  END t1[67]
  PIN t1[68]
    DIRECTION OUTPUT ;
    USE SIGNAL ;
    PORT
      LAYER M5 ;
        RECT  77.052 0 77.076 0.192 ;
    END
  END t1[68]
  PIN t1[69]
    DIRECTION OUTPUT ;
    USE SIGNAL ;
    PORT
      LAYER M5 ;
        RECT  77.292 0 77.316 0.192 ;
    END
  END t1[69]
  PIN t1[6]
    DIRECTION OUTPUT ;
    USE SIGNAL ;
    PORT
      LAYER M5 ;
        RECT  62.604 0 62.628 0.192 ;
    END
  END t1[6]
  PIN t1[70]
    DIRECTION OUTPUT ;
    USE SIGNAL ;
    PORT
      LAYER M5 ;
        RECT  77.484 0 77.508 0.192 ;
    END
  END t1[70]
  PIN t1[71]
    DIRECTION OUTPUT ;
    USE SIGNAL ;
    PORT
      LAYER M5 ;
        RECT  77.724 0 77.748 0.192 ;
    END
  END t1[71]
  PIN t1[72]
    DIRECTION OUTPUT ;
    USE SIGNAL ;
    PORT
      LAYER M5 ;
        RECT  77.964 0 77.988 0.192 ;
    END
  END t1[72]
  PIN t1[73]
    DIRECTION OUTPUT ;
    USE SIGNAL ;
    PORT
      LAYER M5 ;
        RECT  78.204 0 78.228 0.192 ;
    END
  END t1[73]
  PIN t1[74]
    DIRECTION OUTPUT ;
    USE SIGNAL ;
    PORT
      LAYER M5 ;
        RECT  78.444 0 78.468 0.192 ;
    END
  END t1[74]
  PIN t1[75]
    DIRECTION OUTPUT ;
    USE SIGNAL ;
    PORT
      LAYER M5 ;
        RECT  78.684 0 78.708 0.192 ;
    END
  END t1[75]
  PIN t1[76]
    DIRECTION OUTPUT ;
    USE SIGNAL ;
    PORT
      LAYER M5 ;
        RECT  78.876 0 78.9 0.192 ;
    END
  END t1[76]
  PIN t1[77]
    DIRECTION OUTPUT ;
    USE SIGNAL ;
    PORT
      LAYER M5 ;
        RECT  79.116 0 79.14 0.192 ;
    END
  END t1[77]
  PIN t1[78]
    DIRECTION OUTPUT ;
    USE SIGNAL ;
    PORT
      LAYER M5 ;
        RECT  79.356 0 79.38 0.192 ;
    END
  END t1[78]
  PIN t1[79]
    DIRECTION OUTPUT ;
    USE SIGNAL ;
    PORT
      LAYER M5 ;
        RECT  79.596 0 79.62 0.192 ;
    END
  END t1[79]
  PIN t1[7]
    DIRECTION OUTPUT ;
    USE SIGNAL ;
    PORT
      LAYER M5 ;
        RECT  62.844 0 62.868 0.192 ;
    END
  END t1[7]
  PIN t1[80]
    DIRECTION OUTPUT ;
    USE SIGNAL ;
    PORT
      LAYER M5 ;
        RECT  79.836 0 79.86 0.192 ;
    END
  END t1[80]
  PIN t1[81]
    DIRECTION OUTPUT ;
    USE SIGNAL ;
    PORT
      LAYER M5 ;
        RECT  80.076 0 80.1 0.192 ;
    END
  END t1[81]
  PIN t1[82]
    DIRECTION OUTPUT ;
    USE SIGNAL ;
    PORT
      LAYER M5 ;
        RECT  80.316 0 80.34 0.192 ;
    END
  END t1[82]
  PIN t1[83]
    DIRECTION OUTPUT ;
    USE SIGNAL ;
    PORT
      LAYER M5 ;
        RECT  80.508 0 80.532 0.192 ;
    END
  END t1[83]
  PIN t1[84]
    DIRECTION OUTPUT ;
    USE SIGNAL ;
    PORT
      LAYER M5 ;
        RECT  80.748 0 80.772 0.192 ;
    END
  END t1[84]
  PIN t1[85]
    DIRECTION OUTPUT ;
    USE SIGNAL ;
    PORT
      LAYER M5 ;
        RECT  80.988 0 81.012 0.192 ;
    END
  END t1[85]
  PIN t1[86]
    DIRECTION OUTPUT ;
    USE SIGNAL ;
    PORT
      LAYER M5 ;
        RECT  81.228 0 81.252 0.192 ;
    END
  END t1[86]
  PIN t1[87]
    DIRECTION OUTPUT ;
    USE SIGNAL ;
    PORT
      LAYER M5 ;
        RECT  81.468 0 81.492 0.192 ;
    END
  END t1[87]
  PIN t1[88]
    DIRECTION OUTPUT ;
    USE SIGNAL ;
    PORT
      LAYER M5 ;
        RECT  81.708 0 81.732 0.192 ;
    END
  END t1[88]
  PIN t1[89]
    DIRECTION OUTPUT ;
    USE SIGNAL ;
    PORT
      LAYER M5 ;
        RECT  81.948 0 81.972 0.192 ;
    END
  END t1[89]
  PIN t1[8]
    DIRECTION OUTPUT ;
    USE SIGNAL ;
    PORT
      LAYER M5 ;
        RECT  63.084 0 63.108 0.192 ;
    END
  END t1[8]
  PIN t1[90]
    DIRECTION OUTPUT ;
    USE SIGNAL ;
    PORT
      LAYER M5 ;
        RECT  82.14 0 82.164 0.192 ;
    END
  END t1[90]
  PIN t1[91]
    DIRECTION OUTPUT ;
    USE SIGNAL ;
    PORT
      LAYER M5 ;
        RECT  82.38 0 82.404 0.192 ;
    END
  END t1[91]
  PIN t1[92]
    DIRECTION OUTPUT ;
    USE SIGNAL ;
    PORT
      LAYER M5 ;
        RECT  82.62 0 82.644 0.192 ;
    END
  END t1[92]
  PIN t1[93]
    DIRECTION OUTPUT ;
    USE SIGNAL ;
    PORT
      LAYER M5 ;
        RECT  82.86 0 82.884 0.192 ;
    END
  END t1[93]
  PIN t1[94]
    DIRECTION OUTPUT ;
    USE SIGNAL ;
    PORT
      LAYER M5 ;
        RECT  83.1 0 83.124 0.192 ;
    END
  END t1[94]
  PIN t1[95]
    DIRECTION OUTPUT ;
    USE SIGNAL ;
    PORT
      LAYER M5 ;
        RECT  83.34 0 83.364 0.192 ;
    END
  END t1[95]
  PIN t1[96]
    DIRECTION OUTPUT ;
    USE SIGNAL ;
    PORT
      LAYER M5 ;
        RECT  83.532 0 83.556 0.192 ;
    END
  END t1[96]
  PIN t1[97]
    DIRECTION OUTPUT ;
    USE SIGNAL ;
    PORT
      LAYER M5 ;
        RECT  83.772 0 83.796 0.192 ;
    END
  END t1[97]
  PIN t1[98]
    DIRECTION OUTPUT ;
    USE SIGNAL ;
    PORT
      LAYER M5 ;
        RECT  84.012 0 84.036 0.192 ;
    END
  END t1[98]
  PIN t1[99]
    DIRECTION OUTPUT ;
    USE SIGNAL ;
    PORT
      LAYER M5 ;
        RECT  84.252 0 84.276 0.192 ;
    END
  END t1[99]
  PIN t1[9]
    DIRECTION OUTPUT ;
    USE SIGNAL ;
    PORT
      LAYER M5 ;
        RECT  63.324 0 63.348 0.192 ;
    END
  END t1[9]
  PIN VDD
    DIRECTION INOUT ;
    USE POWER ;
    PORT
      LAYER M5 ;
        RECT  235.476 4.311 235.596 168.489 ;
        RECT  231.156 4.311 231.276 168.489 ;
        RECT  226.836 4.311 226.956 168.489 ;
        RECT  222.516 4.311 222.636 168.489 ;
        RECT  218.196 4.311 218.316 168.489 ;
        RECT  213.876 4.311 213.996 168.489 ;
        RECT  209.556 4.311 209.676 168.489 ;
        RECT  205.236 4.311 205.356 168.489 ;
        RECT  200.916 4.311 201.036 168.489 ;
        RECT  196.596 4.311 196.716 168.489 ;
        RECT  192.276 4.311 192.396 168.489 ;
        RECT  187.956 4.311 188.076 168.489 ;
        RECT  183.636 4.311 183.756 168.489 ;
        RECT  179.316 4.311 179.436 168.489 ;
        RECT  174.996 4.311 175.116 168.489 ;
        RECT  170.676 4.311 170.796 168.489 ;
        RECT  166.356 4.311 166.476 168.489 ;
        RECT  162.036 4.311 162.156 168.489 ;
        RECT  157.716 4.311 157.836 168.489 ;
        RECT  153.396 4.311 153.516 168.489 ;
        RECT  149.076 4.311 149.196 168.489 ;
        RECT  144.756 4.311 144.876 168.489 ;
        RECT  140.436 4.311 140.556 168.489 ;
        RECT  136.116 4.311 136.236 168.489 ;
        RECT  131.796 4.311 131.916 168.489 ;
        RECT  127.476 4.311 127.596 168.489 ;
        RECT  123.156 4.311 123.276 168.489 ;
        RECT  118.836 4.311 118.956 168.489 ;
        RECT  114.516 4.311 114.636 168.489 ;
        RECT  110.196 4.311 110.316 168.489 ;
        RECT  105.876 4.311 105.996 168.489 ;
        RECT  101.556 4.311 101.676 168.489 ;
        RECT  97.236 4.311 97.356 168.489 ;
        RECT  92.916 4.311 93.036 168.489 ;
        RECT  88.596 4.311 88.716 168.489 ;
        RECT  84.276 4.311 84.396 168.489 ;
        RECT  79.956 4.311 80.076 168.489 ;
        RECT  75.636 4.311 75.756 168.489 ;
        RECT  71.316 4.311 71.436 168.489 ;
        RECT  66.996 4.311 67.116 168.489 ;
        RECT  62.676 4.311 62.796 168.489 ;
        RECT  58.356 4.311 58.476 168.489 ;
        RECT  54.036 4.311 54.156 168.489 ;
        RECT  49.716 4.311 49.836 168.489 ;
        RECT  45.396 4.311 45.516 168.489 ;
        RECT  41.076 4.311 41.196 168.489 ;
        RECT  36.756 4.311 36.876 168.489 ;
        RECT  32.436 4.311 32.556 168.489 ;
        RECT  28.116 4.311 28.236 168.489 ;
        RECT  23.796 4.311 23.916 168.489 ;
        RECT  19.476 4.311 19.596 168.489 ;
        RECT  15.156 4.311 15.276 168.489 ;
        RECT  10.836 4.311 10.956 168.489 ;
        RECT  6.516 4.311 6.636 168.489 ;
    END
  END VDD
  PIN VSS
    DIRECTION INOUT ;
    USE GROUND ;
    PORT
      LAYER M5 ;
        RECT  235.284 4.297 235.404 168.503 ;
        RECT  230.964 4.297 231.084 168.503 ;
        RECT  226.644 4.297 226.764 168.489 ;
        RECT  222.324 4.297 222.444 168.489 ;
        RECT  218.004 4.297 218.124 168.489 ;
        RECT  213.684 4.297 213.804 168.489 ;
        RECT  209.364 4.297 209.484 168.489 ;
        RECT  205.044 4.297 205.164 168.489 ;
        RECT  200.724 4.297 200.844 168.489 ;
        RECT  196.404 4.297 196.524 168.489 ;
        RECT  192.084 4.297 192.204 168.489 ;
        RECT  187.764 4.297 187.884 168.489 ;
        RECT  183.444 4.297 183.564 168.489 ;
        RECT  179.124 4.297 179.244 168.489 ;
        RECT  174.804 4.297 174.924 168.489 ;
        RECT  170.484 4.297 170.604 168.489 ;
        RECT  166.164 4.297 166.284 168.489 ;
        RECT  161.844 4.297 161.964 168.489 ;
        RECT  157.524 4.297 157.644 168.489 ;
        RECT  153.204 4.297 153.324 168.489 ;
        RECT  148.884 4.297 149.004 168.489 ;
        RECT  144.564 4.297 144.684 168.489 ;
        RECT  140.244 4.297 140.364 168.489 ;
        RECT  135.924 4.297 136.044 168.489 ;
        RECT  131.604 4.297 131.724 168.489 ;
        RECT  127.284 4.297 127.404 168.503 ;
        RECT  122.964 4.297 123.084 168.503 ;
        RECT  118.644 4.297 118.764 168.503 ;
        RECT  114.324 4.297 114.444 168.503 ;
        RECT  110.004 4.297 110.124 168.489 ;
        RECT  105.684 4.297 105.804 168.489 ;
        RECT  101.364 4.297 101.484 168.489 ;
        RECT  97.044 4.297 97.164 168.489 ;
        RECT  92.724 4.297 92.844 168.489 ;
        RECT  88.404 4.297 88.524 168.489 ;
        RECT  84.084 4.297 84.204 168.489 ;
        RECT  79.764 4.297 79.884 168.489 ;
        RECT  75.444 4.297 75.564 168.489 ;
        RECT  71.124 4.297 71.244 168.489 ;
        RECT  66.804 4.297 66.924 168.489 ;
        RECT  62.484 4.297 62.604 168.489 ;
        RECT  58.164 4.297 58.284 168.489 ;
        RECT  53.844 4.297 53.964 168.489 ;
        RECT  49.524 4.297 49.644 168.489 ;
        RECT  45.204 4.297 45.324 168.489 ;
        RECT  40.884 4.297 41.004 168.489 ;
        RECT  36.564 4.297 36.684 168.489 ;
        RECT  32.244 4.297 32.364 168.489 ;
        RECT  27.924 4.297 28.044 168.489 ;
        RECT  23.604 4.297 23.724 168.489 ;
        RECT  19.284 4.297 19.404 168.489 ;
        RECT  14.964 4.297 15.084 168.489 ;
        RECT  10.644 4.297 10.764 168.503 ;
        RECT  6.324 4.297 6.444 168.503 ;
    END
  END VSS
  OBS
    LAYER LVTN ;
     RECT  0 0 243.648 172.559 ;
    LAYER LVTP ;
     RECT  0 0 243.648 172.559 ;
    LAYER RVTN ;
     RECT  0 0 243.648 172.559 ;
    LAYER RVTP ;
     RECT  0 0 243.648 172.559 ;
    LAYER M1 ;
     RECT  0 0 243.648 172.559 ;
    LAYER M2 ;
     RECT  0 0 243.648 172.559 ;
    LAYER M3 ;
     RECT  0 0 243.648 172.559 ;
    LAYER M4 ;
     RECT  0 0 243.648 172.559 ;
    LAYER M5 ;
     RECT  0 0 243.648 172.559 ;
  END
END qkd_ectlk_q2
END LIBRARY
